VERSION 5.8 ;
BUSBITCHARS "[]" ;
DIVIDERCHAR "/" ;
UNITS
    DATABASE MICRONS 1000 ;
END UNITS

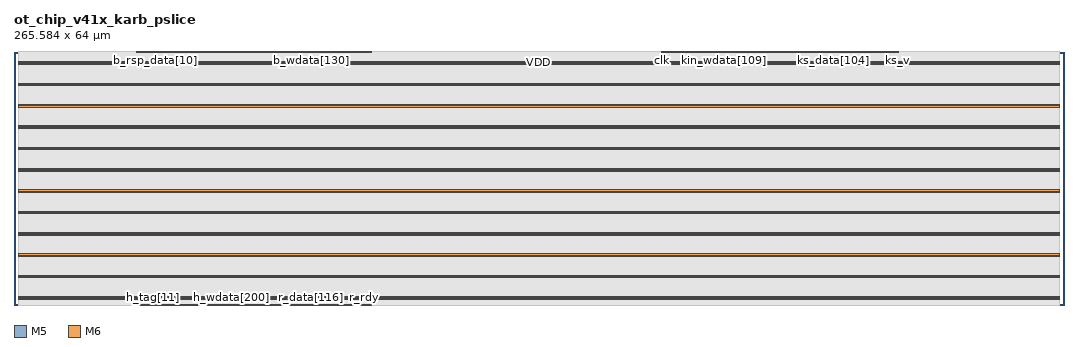
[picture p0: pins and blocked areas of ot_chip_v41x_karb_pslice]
MACRO ot_chip_v41x_karb_pslice
  FOREIGN ot_chip_v41x_karb_pslice 0 0 ;
  CLASS BLOCK ;
  SIZE 265.584 BY 64 ;
  PIN b_addr[0]
    DIRECTION INPUT ;
    USE SIGNAL ;
    PORT
      LAYER M5 ;
        RECT  31.008 63.916 31.032 64 ;
    END
  END b_addr[0]
  PIN b_addr[10]
    DIRECTION INPUT ;
    USE SIGNAL ;
    PORT
      LAYER M5 ;
        RECT  31.968 63.916 31.992 64 ;
    END
  END b_addr[10]
  PIN b_addr[11]
    DIRECTION INPUT ;
    USE SIGNAL ;
    PORT
      LAYER M5 ;
        RECT  32.064 63.916 32.088 64 ;
    END
  END b_addr[11]
  PIN b_addr[12]
    DIRECTION INPUT ;
    USE SIGNAL ;
    PORT
      LAYER M5 ;
        RECT  32.16 63.916 32.184 64 ;
    END
  END b_addr[12]
  PIN b_addr[13]
    DIRECTION INPUT ;
    USE SIGNAL ;
    PORT
      LAYER M5 ;
        RECT  32.256 63.916 32.28 64 ;
    END
  END b_addr[13]
  PIN b_addr[14]
    DIRECTION INPUT ;
    USE SIGNAL ;
    PORT
      LAYER M5 ;
        RECT  32.352 63.916 32.376 64 ;
    END
  END b_addr[14]
  PIN b_addr[15]
    DIRECTION INPUT ;
    USE SIGNAL ;
    PORT
      LAYER M5 ;
        RECT  32.448 63.916 32.472 64 ;
    END
  END b_addr[15]
  PIN b_addr[16]
    DIRECTION INPUT ;
    USE SIGNAL ;
    PORT
      LAYER M5 ;
        RECT  32.544 63.916 32.568 64 ;
    END
  END b_addr[16]
  PIN b_addr[17]
    DIRECTION INPUT ;
    USE SIGNAL ;
    PORT
      LAYER M5 ;
        RECT  32.64 63.916 32.664 64 ;
    END
  END b_addr[17]
  PIN b_addr[18]
    DIRECTION INPUT ;
    USE SIGNAL ;
    PORT
      LAYER M5 ;
        RECT  32.736 63.916 32.76 64 ;
    END
  END b_addr[18]
  PIN b_addr[19]
    DIRECTION INPUT ;
    USE SIGNAL ;
    PORT
      LAYER M5 ;
        RECT  32.832 63.916 32.856 64 ;
    END
  END b_addr[19]
  PIN b_addr[1]
    DIRECTION INPUT ;
    USE SIGNAL ;
    PORT
      LAYER M5 ;
        RECT  31.104 63.916 31.128 64 ;
    END
  END b_addr[1]
  PIN b_addr[20]
    DIRECTION INPUT ;
    USE SIGNAL ;
    PORT
      LAYER M5 ;
        RECT  32.928 63.916 32.952 64 ;
    END
  END b_addr[20]
  PIN b_addr[21]
    DIRECTION INPUT ;
    USE SIGNAL ;
    PORT
      LAYER M5 ;
        RECT  33.024 63.916 33.048 64 ;
    END
  END b_addr[21]
  PIN b_addr[22]
    DIRECTION INPUT ;
    USE SIGNAL ;
    PORT
      LAYER M5 ;
        RECT  33.12 63.916 33.144 64 ;
    END
  END b_addr[22]
  PIN b_addr[23]
    DIRECTION INPUT ;
    USE SIGNAL ;
    PORT
      LAYER M5 ;
        RECT  33.216 63.916 33.24 64 ;
    END
  END b_addr[23]
  PIN b_addr[24]
    DIRECTION INPUT ;
    USE SIGNAL ;
    PORT
      LAYER M5 ;
        RECT  33.312 63.916 33.336 64 ;
    END
  END b_addr[24]
  PIN b_addr[25]
    DIRECTION INPUT ;
    USE SIGNAL ;
    PORT
      LAYER M5 ;
        RECT  33.408 63.916 33.432 64 ;
    END
  END b_addr[25]
  PIN b_addr[26]
    DIRECTION INPUT ;
    USE SIGNAL ;
    PORT
      LAYER M5 ;
        RECT  33.504 63.916 33.528 64 ;
    END
  END b_addr[26]
  PIN b_addr[27]
    DIRECTION INPUT ;
    USE SIGNAL ;
    PORT
      LAYER M5 ;
        RECT  33.6 63.916 33.624 64 ;
    END
  END b_addr[27]
  PIN b_addr[28]
    DIRECTION INPUT ;
    USE SIGNAL ;
    PORT
      LAYER M5 ;
        RECT  33.696 63.916 33.72 64 ;
    END
  END b_addr[28]
  PIN b_addr[29]
    DIRECTION INPUT ;
    USE SIGNAL ;
    PORT
      LAYER M5 ;
        RECT  33.792 63.916 33.816 64 ;
    END
  END b_addr[29]
  PIN b_addr[2]
    DIRECTION INPUT ;
    USE SIGNAL ;
    PORT
      LAYER M5 ;
        RECT  31.2 63.916 31.224 64 ;
    END
  END b_addr[2]
  PIN b_addr[3]
    DIRECTION INPUT ;
    USE SIGNAL ;
    PORT
      LAYER M5 ;
        RECT  31.296 63.916 31.32 64 ;
    END
  END b_addr[3]
  PIN b_addr[4]
    DIRECTION INPUT ;
    USE SIGNAL ;
    PORT
      LAYER M5 ;
        RECT  31.392 63.916 31.416 64 ;
    END
  END b_addr[4]
  PIN b_addr[5]
    DIRECTION INPUT ;
    USE SIGNAL ;
    PORT
      LAYER M5 ;
        RECT  31.488 63.916 31.512 64 ;
    END
  END b_addr[5]
  PIN b_addr[6]
    DIRECTION INPUT ;
    USE SIGNAL ;
    PORT
      LAYER M5 ;
        RECT  31.584 63.916 31.608 64 ;
    END
  END b_addr[6]
  PIN b_addr[7]
    DIRECTION INPUT ;
    USE SIGNAL ;
    PORT
      LAYER M5 ;
        RECT  31.68 63.916 31.704 64 ;
    END
  END b_addr[7]
  PIN b_addr[8]
    DIRECTION INPUT ;
    USE SIGNAL ;
    PORT
      LAYER M5 ;
        RECT  31.776 63.916 31.8 64 ;
    END
  END b_addr[8]
  PIN b_addr[9]
    DIRECTION INPUT ;
    USE SIGNAL ;
    PORT
      LAYER M5 ;
        RECT  31.872 63.916 31.896 64 ;
    END
  END b_addr[9]
  PIN b_grant
    DIRECTION OUTPUT ;
    USE SIGNAL ;
    PORT
      LAYER M5 ;
        RECT  163.776 63.916 163.8 64 ;
    END
  END b_grant
  PIN b_len[0]
    DIRECTION INPUT ;
    USE SIGNAL ;
    PORT
      LAYER M5 ;
        RECT  33.888 63.916 33.912 64 ;
    END
  END b_len[0]
  PIN b_len[1]
    DIRECTION INPUT ;
    USE SIGNAL ;
    PORT
      LAYER M5 ;
        RECT  33.984 63.916 34.008 64 ;
    END
  END b_len[1]
  PIN b_len[2]
    DIRECTION INPUT ;
    USE SIGNAL ;
    PORT
      LAYER M5 ;
        RECT  34.08 63.916 34.104 64 ;
    END
  END b_len[2]
  PIN b_len[3]
    DIRECTION INPUT ;
    USE SIGNAL ;
    PORT
      LAYER M5 ;
        RECT  34.176 63.916 34.2 64 ;
    END
  END b_len[3]
  PIN b_rdy
    DIRECTION OUTPUT ;
    USE SIGNAL ;
    PORT
      LAYER M5 ;
        RECT  34.272 63.916 34.296 64 ;
    END
  END b_rdy
  PIN b_rsp_beat[0]
    DIRECTION OUTPUT ;
    USE SIGNAL ;
    PORT
      LAYER M5 ;
        RECT  34.368 63.916 34.392 64 ;
    END
  END b_rsp_beat[0]
  PIN b_rsp_beat[1]
    DIRECTION OUTPUT ;
    USE SIGNAL ;
    PORT
      LAYER M5 ;
        RECT  34.464 63.916 34.488 64 ;
    END
  END b_rsp_beat[1]
  PIN b_rsp_beat[2]
    DIRECTION OUTPUT ;
    USE SIGNAL ;
    PORT
      LAYER M5 ;
        RECT  34.56 63.916 34.584 64 ;
    END
  END b_rsp_beat[2]
  PIN b_rsp_beat[3]
    DIRECTION OUTPUT ;
    USE SIGNAL ;
    PORT
      LAYER M5 ;
        RECT  34.656 63.916 34.68 64 ;
    END
  END b_rsp_beat[3]
  PIN b_rsp_data[0]
    DIRECTION OUTPUT ;
    USE SIGNAL ;
    PORT
      LAYER M5 ;
        RECT  34.752 63.916 34.776 64 ;
    END
  END b_rsp_data[0]
  PIN b_rsp_data[100]
    DIRECTION OUTPUT ;
    USE SIGNAL ;
    PORT
      LAYER M5 ;
        RECT  44.352 63.916 44.376 64 ;
    END
  END b_rsp_data[100]
  PIN b_rsp_data[101]
    DIRECTION OUTPUT ;
    USE SIGNAL ;
    PORT
      LAYER M5 ;
        RECT  44.448 63.916 44.472 64 ;
    END
  END b_rsp_data[101]
  PIN b_rsp_data[102]
    DIRECTION OUTPUT ;
    USE SIGNAL ;
    PORT
      LAYER M5 ;
        RECT  44.544 63.916 44.568 64 ;
    END
  END b_rsp_data[102]
  PIN b_rsp_data[103]
    DIRECTION OUTPUT ;
    USE SIGNAL ;
    PORT
      LAYER M5 ;
        RECT  44.64 63.916 44.664 64 ;
    END
  END b_rsp_data[103]
  PIN b_rsp_data[104]
    DIRECTION OUTPUT ;
    USE SIGNAL ;
    PORT
      LAYER M5 ;
        RECT  44.736 63.916 44.76 64 ;
    END
  END b_rsp_data[104]
  PIN b_rsp_data[105]
    DIRECTION OUTPUT ;
    USE SIGNAL ;
    PORT
      LAYER M5 ;
        RECT  44.832 63.916 44.856 64 ;
    END
  END b_rsp_data[105]
  PIN b_rsp_data[106]
    DIRECTION OUTPUT ;
    USE SIGNAL ;
    PORT
      LAYER M5 ;
        RECT  44.928 63.916 44.952 64 ;
    END
  END b_rsp_data[106]
  PIN b_rsp_data[107]
    DIRECTION OUTPUT ;
    USE SIGNAL ;
    PORT
      LAYER M5 ;
        RECT  45.024 63.916 45.048 64 ;
    END
  END b_rsp_data[107]
  PIN b_rsp_data[108]
    DIRECTION OUTPUT ;
    USE SIGNAL ;
    PORT
      LAYER M5 ;
        RECT  45.12 63.916 45.144 64 ;
    END
  END b_rsp_data[108]
  PIN b_rsp_data[109]
    DIRECTION OUTPUT ;
    USE SIGNAL ;
    PORT
      LAYER M5 ;
        RECT  45.216 63.916 45.24 64 ;
    END
  END b_rsp_data[109]
  PIN b_rsp_data[10]
    DIRECTION OUTPUT ;
    USE SIGNAL ;
    PORT
      LAYER M5 ;
        RECT  35.712 63.916 35.736 64 ;
    END
  END b_rsp_data[10]
  PIN b_rsp_data[110]
    DIRECTION OUTPUT ;
    USE SIGNAL ;
    PORT
      LAYER M5 ;
        RECT  45.312 63.916 45.336 64 ;
    END
  END b_rsp_data[110]
  PIN b_rsp_data[111]
    DIRECTION OUTPUT ;
    USE SIGNAL ;
    PORT
      LAYER M5 ;
        RECT  45.408 63.916 45.432 64 ;
    END
  END b_rsp_data[111]
  PIN b_rsp_data[112]
    DIRECTION OUTPUT ;
    USE SIGNAL ;
    PORT
      LAYER M5 ;
        RECT  45.504 63.916 45.528 64 ;
    END
  END b_rsp_data[112]
  PIN b_rsp_data[113]
    DIRECTION OUTPUT ;
    USE SIGNAL ;
    PORT
      LAYER M5 ;
        RECT  45.6 63.916 45.624 64 ;
    END
  END b_rsp_data[113]
  PIN b_rsp_data[114]
    DIRECTION OUTPUT ;
    USE SIGNAL ;
    PORT
      LAYER M5 ;
        RECT  45.696 63.916 45.72 64 ;
    END
  END b_rsp_data[114]
  PIN b_rsp_data[115]
    DIRECTION OUTPUT ;
    USE SIGNAL ;
    PORT
      LAYER M5 ;
        RECT  45.792 63.916 45.816 64 ;
    END
  END b_rsp_data[115]
  PIN b_rsp_data[116]
    DIRECTION OUTPUT ;
    USE SIGNAL ;
    PORT
      LAYER M5 ;
        RECT  45.888 63.916 45.912 64 ;
    END
  END b_rsp_data[116]
  PIN b_rsp_data[117]
    DIRECTION OUTPUT ;
    USE SIGNAL ;
    PORT
      LAYER M5 ;
        RECT  45.984 63.916 46.008 64 ;
    END
  END b_rsp_data[117]
  PIN b_rsp_data[118]
    DIRECTION OUTPUT ;
    USE SIGNAL ;
    PORT
      LAYER M5 ;
        RECT  46.08 63.916 46.104 64 ;
    END
  END b_rsp_data[118]
  PIN b_rsp_data[119]
    DIRECTION OUTPUT ;
    USE SIGNAL ;
    PORT
      LAYER M5 ;
        RECT  46.176 63.916 46.2 64 ;
    END
  END b_rsp_data[119]
  PIN b_rsp_data[11]
    DIRECTION OUTPUT ;
    USE SIGNAL ;
    PORT
      LAYER M5 ;
        RECT  35.808 63.916 35.832 64 ;
    END
  END b_rsp_data[11]
  PIN b_rsp_data[120]
    DIRECTION OUTPUT ;
    USE SIGNAL ;
    PORT
      LAYER M5 ;
        RECT  46.272 63.916 46.296 64 ;
    END
  END b_rsp_data[120]
  PIN b_rsp_data[121]
    DIRECTION OUTPUT ;
    USE SIGNAL ;
    PORT
      LAYER M5 ;
        RECT  46.368 63.916 46.392 64 ;
    END
  END b_rsp_data[121]
  PIN b_rsp_data[122]
    DIRECTION OUTPUT ;
    USE SIGNAL ;
    PORT
      LAYER M5 ;
        RECT  46.464 63.916 46.488 64 ;
    END
  END b_rsp_data[122]
  PIN b_rsp_data[123]
    DIRECTION OUTPUT ;
    USE SIGNAL ;
    PORT
      LAYER M5 ;
        RECT  46.56 63.916 46.584 64 ;
    END
  END b_rsp_data[123]
  PIN b_rsp_data[124]
    DIRECTION OUTPUT ;
    USE SIGNAL ;
    PORT
      LAYER M5 ;
        RECT  46.656 63.916 46.68 64 ;
    END
  END b_rsp_data[124]
  PIN b_rsp_data[125]
    DIRECTION OUTPUT ;
    USE SIGNAL ;
    PORT
      LAYER M5 ;
        RECT  46.752 63.916 46.776 64 ;
    END
  END b_rsp_data[125]
  PIN b_rsp_data[126]
    DIRECTION OUTPUT ;
    USE SIGNAL ;
    PORT
      LAYER M5 ;
        RECT  46.848 63.916 46.872 64 ;
    END
  END b_rsp_data[126]
  PIN b_rsp_data[127]
    DIRECTION OUTPUT ;
    USE SIGNAL ;
    PORT
      LAYER M5 ;
        RECT  46.944 63.916 46.968 64 ;
    END
  END b_rsp_data[127]
  PIN b_rsp_data[128]
    DIRECTION OUTPUT ;
    USE SIGNAL ;
    PORT
      LAYER M5 ;
        RECT  47.04 63.916 47.064 64 ;
    END
  END b_rsp_data[128]
  PIN b_rsp_data[129]
    DIRECTION OUTPUT ;
    USE SIGNAL ;
    PORT
      LAYER M5 ;
        RECT  47.136 63.916 47.16 64 ;
    END
  END b_rsp_data[129]
  PIN b_rsp_data[12]
    DIRECTION OUTPUT ;
    USE SIGNAL ;
    PORT
      LAYER M5 ;
        RECT  35.904 63.916 35.928 64 ;
    END
  END b_rsp_data[12]
  PIN b_rsp_data[130]
    DIRECTION OUTPUT ;
    USE SIGNAL ;
    PORT
      LAYER M5 ;
        RECT  47.232 63.916 47.256 64 ;
    END
  END b_rsp_data[130]
  PIN b_rsp_data[131]
    DIRECTION OUTPUT ;
    USE SIGNAL ;
    PORT
      LAYER M5 ;
        RECT  47.328 63.916 47.352 64 ;
    END
  END b_rsp_data[131]
  PIN b_rsp_data[132]
    DIRECTION OUTPUT ;
    USE SIGNAL ;
    PORT
      LAYER M5 ;
        RECT  47.424 63.916 47.448 64 ;
    END
  END b_rsp_data[132]
  PIN b_rsp_data[133]
    DIRECTION OUTPUT ;
    USE SIGNAL ;
    PORT
      LAYER M5 ;
        RECT  47.52 63.916 47.544 64 ;
    END
  END b_rsp_data[133]
  PIN b_rsp_data[134]
    DIRECTION OUTPUT ;
    USE SIGNAL ;
    PORT
      LAYER M5 ;
        RECT  47.616 63.916 47.64 64 ;
    END
  END b_rsp_data[134]
  PIN b_rsp_data[135]
    DIRECTION OUTPUT ;
    USE SIGNAL ;
    PORT
      LAYER M5 ;
        RECT  47.712 63.916 47.736 64 ;
    END
  END b_rsp_data[135]
  PIN b_rsp_data[136]
    DIRECTION OUTPUT ;
    USE SIGNAL ;
    PORT
      LAYER M5 ;
        RECT  47.808 63.916 47.832 64 ;
    END
  END b_rsp_data[136]
  PIN b_rsp_data[137]
    DIRECTION OUTPUT ;
    USE SIGNAL ;
    PORT
      LAYER M5 ;
        RECT  47.904 63.916 47.928 64 ;
    END
  END b_rsp_data[137]
  PIN b_rsp_data[138]
    DIRECTION OUTPUT ;
    USE SIGNAL ;
    PORT
      LAYER M5 ;
        RECT  48 63.916 48.024 64 ;
    END
  END b_rsp_data[138]
  PIN b_rsp_data[139]
    DIRECTION OUTPUT ;
    USE SIGNAL ;
    PORT
      LAYER M5 ;
        RECT  48.096 63.916 48.12 64 ;
    END
  END b_rsp_data[139]
  PIN b_rsp_data[13]
    DIRECTION OUTPUT ;
    USE SIGNAL ;
    PORT
      LAYER M5 ;
        RECT  36 63.916 36.024 64 ;
    END
  END b_rsp_data[13]
  PIN b_rsp_data[140]
    DIRECTION OUTPUT ;
    USE SIGNAL ;
    PORT
      LAYER M5 ;
        RECT  48.192 63.916 48.216 64 ;
    END
  END b_rsp_data[140]
  PIN b_rsp_data[141]
    DIRECTION OUTPUT ;
    USE SIGNAL ;
    PORT
      LAYER M5 ;
        RECT  48.288 63.916 48.312 64 ;
    END
  END b_rsp_data[141]
  PIN b_rsp_data[142]
    DIRECTION OUTPUT ;
    USE SIGNAL ;
    PORT
      LAYER M5 ;
        RECT  48.384 63.916 48.408 64 ;
    END
  END b_rsp_data[142]
  PIN b_rsp_data[143]
    DIRECTION OUTPUT ;
    USE SIGNAL ;
    PORT
      LAYER M5 ;
        RECT  48.48 63.916 48.504 64 ;
    END
  END b_rsp_data[143]
  PIN b_rsp_data[144]
    DIRECTION OUTPUT ;
    USE SIGNAL ;
    PORT
      LAYER M5 ;
        RECT  48.576 63.916 48.6 64 ;
    END
  END b_rsp_data[144]
  PIN b_rsp_data[145]
    DIRECTION OUTPUT ;
    USE SIGNAL ;
    PORT
      LAYER M5 ;
        RECT  48.672 63.916 48.696 64 ;
    END
  END b_rsp_data[145]
  PIN b_rsp_data[146]
    DIRECTION OUTPUT ;
    USE SIGNAL ;
    PORT
      LAYER M5 ;
        RECT  48.768 63.916 48.792 64 ;
    END
  END b_rsp_data[146]
  PIN b_rsp_data[147]
    DIRECTION OUTPUT ;
    USE SIGNAL ;
    PORT
      LAYER M5 ;
        RECT  48.864 63.916 48.888 64 ;
    END
  END b_rsp_data[147]
  PIN b_rsp_data[148]
    DIRECTION OUTPUT ;
    USE SIGNAL ;
    PORT
      LAYER M5 ;
        RECT  48.96 63.916 48.984 64 ;
    END
  END b_rsp_data[148]
  PIN b_rsp_data[149]
    DIRECTION OUTPUT ;
    USE SIGNAL ;
    PORT
      LAYER M5 ;
        RECT  49.056 63.916 49.08 64 ;
    END
  END b_rsp_data[149]
  PIN b_rsp_data[14]
    DIRECTION OUTPUT ;
    USE SIGNAL ;
    PORT
      LAYER M5 ;
        RECT  36.096 63.916 36.12 64 ;
    END
  END b_rsp_data[14]
  PIN b_rsp_data[150]
    DIRECTION OUTPUT ;
    USE SIGNAL ;
    PORT
      LAYER M5 ;
        RECT  49.152 63.916 49.176 64 ;
    END
  END b_rsp_data[150]
  PIN b_rsp_data[151]
    DIRECTION OUTPUT ;
    USE SIGNAL ;
    PORT
      LAYER M5 ;
        RECT  49.248 63.916 49.272 64 ;
    END
  END b_rsp_data[151]
  PIN b_rsp_data[152]
    DIRECTION OUTPUT ;
    USE SIGNAL ;
    PORT
      LAYER M5 ;
        RECT  49.344 63.916 49.368 64 ;
    END
  END b_rsp_data[152]
  PIN b_rsp_data[153]
    DIRECTION OUTPUT ;
    USE SIGNAL ;
    PORT
      LAYER M5 ;
        RECT  49.44 63.916 49.464 64 ;
    END
  END b_rsp_data[153]
  PIN b_rsp_data[154]
    DIRECTION OUTPUT ;
    USE SIGNAL ;
    PORT
      LAYER M5 ;
        RECT  49.536 63.916 49.56 64 ;
    END
  END b_rsp_data[154]
  PIN b_rsp_data[155]
    DIRECTION OUTPUT ;
    USE SIGNAL ;
    PORT
      LAYER M5 ;
        RECT  49.632 63.916 49.656 64 ;
    END
  END b_rsp_data[155]
  PIN b_rsp_data[156]
    DIRECTION OUTPUT ;
    USE SIGNAL ;
    PORT
      LAYER M5 ;
        RECT  49.728 63.916 49.752 64 ;
    END
  END b_rsp_data[156]
  PIN b_rsp_data[157]
    DIRECTION OUTPUT ;
    USE SIGNAL ;
    PORT
      LAYER M5 ;
        RECT  49.824 63.916 49.848 64 ;
    END
  END b_rsp_data[157]
  PIN b_rsp_data[158]
    DIRECTION OUTPUT ;
    USE SIGNAL ;
    PORT
      LAYER M5 ;
        RECT  49.92 63.916 49.944 64 ;
    END
  END b_rsp_data[158]
  PIN b_rsp_data[159]
    DIRECTION OUTPUT ;
    USE SIGNAL ;
    PORT
      LAYER M5 ;
        RECT  50.016 63.916 50.04 64 ;
    END
  END b_rsp_data[159]
  PIN b_rsp_data[15]
    DIRECTION OUTPUT ;
    USE SIGNAL ;
    PORT
      LAYER M5 ;
        RECT  36.192 63.916 36.216 64 ;
    END
  END b_rsp_data[15]
  PIN b_rsp_data[160]
    DIRECTION OUTPUT ;
    USE SIGNAL ;
    PORT
      LAYER M5 ;
        RECT  50.112 63.916 50.136 64 ;
    END
  END b_rsp_data[160]
  PIN b_rsp_data[161]
    DIRECTION OUTPUT ;
    USE SIGNAL ;
    PORT
      LAYER M5 ;
        RECT  50.208 63.916 50.232 64 ;
    END
  END b_rsp_data[161]
  PIN b_rsp_data[162]
    DIRECTION OUTPUT ;
    USE SIGNAL ;
    PORT
      LAYER M5 ;
        RECT  50.304 63.916 50.328 64 ;
    END
  END b_rsp_data[162]
  PIN b_rsp_data[163]
    DIRECTION OUTPUT ;
    USE SIGNAL ;
    PORT
      LAYER M5 ;
        RECT  50.4 63.916 50.424 64 ;
    END
  END b_rsp_data[163]
  PIN b_rsp_data[164]
    DIRECTION OUTPUT ;
    USE SIGNAL ;
    PORT
      LAYER M5 ;
        RECT  50.496 63.916 50.52 64 ;
    END
  END b_rsp_data[164]
  PIN b_rsp_data[165]
    DIRECTION OUTPUT ;
    USE SIGNAL ;
    PORT
      LAYER M5 ;
        RECT  50.592 63.916 50.616 64 ;
    END
  END b_rsp_data[165]
  PIN b_rsp_data[166]
    DIRECTION OUTPUT ;
    USE SIGNAL ;
    PORT
      LAYER M5 ;
        RECT  50.688 63.916 50.712 64 ;
    END
  END b_rsp_data[166]
  PIN b_rsp_data[167]
    DIRECTION OUTPUT ;
    USE SIGNAL ;
    PORT
      LAYER M5 ;
        RECT  50.784 63.916 50.808 64 ;
    END
  END b_rsp_data[167]
  PIN b_rsp_data[168]
    DIRECTION OUTPUT ;
    USE SIGNAL ;
    PORT
      LAYER M5 ;
        RECT  50.88 63.916 50.904 64 ;
    END
  END b_rsp_data[168]
  PIN b_rsp_data[169]
    DIRECTION OUTPUT ;
    USE SIGNAL ;
    PORT
      LAYER M5 ;
        RECT  50.976 63.916 51 64 ;
    END
  END b_rsp_data[169]
  PIN b_rsp_data[16]
    DIRECTION OUTPUT ;
    USE SIGNAL ;
    PORT
      LAYER M5 ;
        RECT  36.288 63.916 36.312 64 ;
    END
  END b_rsp_data[16]
  PIN b_rsp_data[170]
    DIRECTION OUTPUT ;
    USE SIGNAL ;
    PORT
      LAYER M5 ;
        RECT  51.072 63.916 51.096 64 ;
    END
  END b_rsp_data[170]
  PIN b_rsp_data[171]
    DIRECTION OUTPUT ;
    USE SIGNAL ;
    PORT
      LAYER M5 ;
        RECT  51.168 63.916 51.192 64 ;
    END
  END b_rsp_data[171]
  PIN b_rsp_data[172]
    DIRECTION OUTPUT ;
    USE SIGNAL ;
    PORT
      LAYER M5 ;
        RECT  51.264 63.916 51.288 64 ;
    END
  END b_rsp_data[172]
  PIN b_rsp_data[173]
    DIRECTION OUTPUT ;
    USE SIGNAL ;
    PORT
      LAYER M5 ;
        RECT  51.36 63.916 51.384 64 ;
    END
  END b_rsp_data[173]
  PIN b_rsp_data[174]
    DIRECTION OUTPUT ;
    USE SIGNAL ;
    PORT
      LAYER M5 ;
        RECT  51.456 63.916 51.48 64 ;
    END
  END b_rsp_data[174]
  PIN b_rsp_data[175]
    DIRECTION OUTPUT ;
    USE SIGNAL ;
    PORT
      LAYER M5 ;
        RECT  51.552 63.916 51.576 64 ;
    END
  END b_rsp_data[175]
  PIN b_rsp_data[176]
    DIRECTION OUTPUT ;
    USE SIGNAL ;
    PORT
      LAYER M5 ;
        RECT  51.648 63.916 51.672 64 ;
    END
  END b_rsp_data[176]
  PIN b_rsp_data[177]
    DIRECTION OUTPUT ;
    USE SIGNAL ;
    PORT
      LAYER M5 ;
        RECT  51.744 63.916 51.768 64 ;
    END
  END b_rsp_data[177]
  PIN b_rsp_data[178]
    DIRECTION OUTPUT ;
    USE SIGNAL ;
    PORT
      LAYER M5 ;
        RECT  51.84 63.916 51.864 64 ;
    END
  END b_rsp_data[178]
  PIN b_rsp_data[179]
    DIRECTION OUTPUT ;
    USE SIGNAL ;
    PORT
      LAYER M5 ;
        RECT  51.936 63.916 51.96 64 ;
    END
  END b_rsp_data[179]
  PIN b_rsp_data[17]
    DIRECTION OUTPUT ;
    USE SIGNAL ;
    PORT
      LAYER M5 ;
        RECT  36.384 63.916 36.408 64 ;
    END
  END b_rsp_data[17]
  PIN b_rsp_data[180]
    DIRECTION OUTPUT ;
    USE SIGNAL ;
    PORT
      LAYER M5 ;
        RECT  52.032 63.916 52.056 64 ;
    END
  END b_rsp_data[180]
  PIN b_rsp_data[181]
    DIRECTION OUTPUT ;
    USE SIGNAL ;
    PORT
      LAYER M5 ;
        RECT  52.128 63.916 52.152 64 ;
    END
  END b_rsp_data[181]
  PIN b_rsp_data[182]
    DIRECTION OUTPUT ;
    USE SIGNAL ;
    PORT
      LAYER M5 ;
        RECT  52.224 63.916 52.248 64 ;
    END
  END b_rsp_data[182]
  PIN b_rsp_data[183]
    DIRECTION OUTPUT ;
    USE SIGNAL ;
    PORT
      LAYER M5 ;
        RECT  52.32 63.916 52.344 64 ;
    END
  END b_rsp_data[183]
  PIN b_rsp_data[184]
    DIRECTION OUTPUT ;
    USE SIGNAL ;
    PORT
      LAYER M5 ;
        RECT  52.416 63.916 52.44 64 ;
    END
  END b_rsp_data[184]
  PIN b_rsp_data[185]
    DIRECTION OUTPUT ;
    USE SIGNAL ;
    PORT
      LAYER M5 ;
        RECT  52.512 63.916 52.536 64 ;
    END
  END b_rsp_data[185]
  PIN b_rsp_data[186]
    DIRECTION OUTPUT ;
    USE SIGNAL ;
    PORT
      LAYER M5 ;
        RECT  52.608 63.916 52.632 64 ;
    END
  END b_rsp_data[186]
  PIN b_rsp_data[187]
    DIRECTION OUTPUT ;
    USE SIGNAL ;
    PORT
      LAYER M5 ;
        RECT  52.704 63.916 52.728 64 ;
    END
  END b_rsp_data[187]
  PIN b_rsp_data[188]
    DIRECTION OUTPUT ;
    USE SIGNAL ;
    PORT
      LAYER M5 ;
        RECT  52.8 63.916 52.824 64 ;
    END
  END b_rsp_data[188]
  PIN b_rsp_data[189]
    DIRECTION OUTPUT ;
    USE SIGNAL ;
    PORT
      LAYER M5 ;
        RECT  52.896 63.916 52.92 64 ;
    END
  END b_rsp_data[189]
  PIN b_rsp_data[18]
    DIRECTION OUTPUT ;
    USE SIGNAL ;
    PORT
      LAYER M5 ;
        RECT  36.48 63.916 36.504 64 ;
    END
  END b_rsp_data[18]
  PIN b_rsp_data[190]
    DIRECTION OUTPUT ;
    USE SIGNAL ;
    PORT
      LAYER M5 ;
        RECT  52.992 63.916 53.016 64 ;
    END
  END b_rsp_data[190]
  PIN b_rsp_data[191]
    DIRECTION OUTPUT ;
    USE SIGNAL ;
    PORT
      LAYER M5 ;
        RECT  53.088 63.916 53.112 64 ;
    END
  END b_rsp_data[191]
  PIN b_rsp_data[192]
    DIRECTION OUTPUT ;
    USE SIGNAL ;
    PORT
      LAYER M5 ;
        RECT  53.184 63.916 53.208 64 ;
    END
  END b_rsp_data[192]
  PIN b_rsp_data[193]
    DIRECTION OUTPUT ;
    USE SIGNAL ;
    PORT
      LAYER M5 ;
        RECT  53.28 63.916 53.304 64 ;
    END
  END b_rsp_data[193]
  PIN b_rsp_data[194]
    DIRECTION OUTPUT ;
    USE SIGNAL ;
    PORT
      LAYER M5 ;
        RECT  53.376 63.916 53.4 64 ;
    END
  END b_rsp_data[194]
  PIN b_rsp_data[195]
    DIRECTION OUTPUT ;
    USE SIGNAL ;
    PORT
      LAYER M5 ;
        RECT  53.472 63.916 53.496 64 ;
    END
  END b_rsp_data[195]
  PIN b_rsp_data[196]
    DIRECTION OUTPUT ;
    USE SIGNAL ;
    PORT
      LAYER M5 ;
        RECT  53.568 63.916 53.592 64 ;
    END
  END b_rsp_data[196]
  PIN b_rsp_data[197]
    DIRECTION OUTPUT ;
    USE SIGNAL ;
    PORT
      LAYER M5 ;
        RECT  53.664 63.916 53.688 64 ;
    END
  END b_rsp_data[197]
  PIN b_rsp_data[198]
    DIRECTION OUTPUT ;
    USE SIGNAL ;
    PORT
      LAYER M5 ;
        RECT  53.76 63.916 53.784 64 ;
    END
  END b_rsp_data[198]
  PIN b_rsp_data[199]
    DIRECTION OUTPUT ;
    USE SIGNAL ;
    PORT
      LAYER M5 ;
        RECT  53.856 63.916 53.88 64 ;
    END
  END b_rsp_data[199]
  PIN b_rsp_data[19]
    DIRECTION OUTPUT ;
    USE SIGNAL ;
    PORT
      LAYER M5 ;
        RECT  36.576 63.916 36.6 64 ;
    END
  END b_rsp_data[19]
  PIN b_rsp_data[1]
    DIRECTION OUTPUT ;
    USE SIGNAL ;
    PORT
      LAYER M5 ;
        RECT  34.848 63.916 34.872 64 ;
    END
  END b_rsp_data[1]
  PIN b_rsp_data[200]
    DIRECTION OUTPUT ;
    USE SIGNAL ;
    PORT
      LAYER M5 ;
        RECT  53.952 63.916 53.976 64 ;
    END
  END b_rsp_data[200]
  PIN b_rsp_data[201]
    DIRECTION OUTPUT ;
    USE SIGNAL ;
    PORT
      LAYER M5 ;
        RECT  54.048 63.916 54.072 64 ;
    END
  END b_rsp_data[201]
  PIN b_rsp_data[202]
    DIRECTION OUTPUT ;
    USE SIGNAL ;
    PORT
      LAYER M5 ;
        RECT  54.144 63.916 54.168 64 ;
    END
  END b_rsp_data[202]
  PIN b_rsp_data[203]
    DIRECTION OUTPUT ;
    USE SIGNAL ;
    PORT
      LAYER M5 ;
        RECT  54.24 63.916 54.264 64 ;
    END
  END b_rsp_data[203]
  PIN b_rsp_data[204]
    DIRECTION OUTPUT ;
    USE SIGNAL ;
    PORT
      LAYER M5 ;
        RECT  54.336 63.916 54.36 64 ;
    END
  END b_rsp_data[204]
  PIN b_rsp_data[205]
    DIRECTION OUTPUT ;
    USE SIGNAL ;
    PORT
      LAYER M5 ;
        RECT  54.432 63.916 54.456 64 ;
    END
  END b_rsp_data[205]
  PIN b_rsp_data[206]
    DIRECTION OUTPUT ;
    USE SIGNAL ;
    PORT
      LAYER M5 ;
        RECT  54.528 63.916 54.552 64 ;
    END
  END b_rsp_data[206]
  PIN b_rsp_data[207]
    DIRECTION OUTPUT ;
    USE SIGNAL ;
    PORT
      LAYER M5 ;
        RECT  54.624 63.916 54.648 64 ;
    END
  END b_rsp_data[207]
  PIN b_rsp_data[208]
    DIRECTION OUTPUT ;
    USE SIGNAL ;
    PORT
      LAYER M5 ;
        RECT  54.72 63.916 54.744 64 ;
    END
  END b_rsp_data[208]
  PIN b_rsp_data[209]
    DIRECTION OUTPUT ;
    USE SIGNAL ;
    PORT
      LAYER M5 ;
        RECT  54.816 63.916 54.84 64 ;
    END
  END b_rsp_data[209]
  PIN b_rsp_data[20]
    DIRECTION OUTPUT ;
    USE SIGNAL ;
    PORT
      LAYER M5 ;
        RECT  36.672 63.916 36.696 64 ;
    END
  END b_rsp_data[20]
  PIN b_rsp_data[210]
    DIRECTION OUTPUT ;
    USE SIGNAL ;
    PORT
      LAYER M5 ;
        RECT  54.912 63.916 54.936 64 ;
    END
  END b_rsp_data[210]
  PIN b_rsp_data[211]
    DIRECTION OUTPUT ;
    USE SIGNAL ;
    PORT
      LAYER M5 ;
        RECT  55.008 63.916 55.032 64 ;
    END
  END b_rsp_data[211]
  PIN b_rsp_data[212]
    DIRECTION OUTPUT ;
    USE SIGNAL ;
    PORT
      LAYER M5 ;
        RECT  55.104 63.916 55.128 64 ;
    END
  END b_rsp_data[212]
  PIN b_rsp_data[213]
    DIRECTION OUTPUT ;
    USE SIGNAL ;
    PORT
      LAYER M5 ;
        RECT  55.2 63.916 55.224 64 ;
    END
  END b_rsp_data[213]
  PIN b_rsp_data[214]
    DIRECTION OUTPUT ;
    USE SIGNAL ;
    PORT
      LAYER M5 ;
        RECT  55.296 63.916 55.32 64 ;
    END
  END b_rsp_data[214]
  PIN b_rsp_data[215]
    DIRECTION OUTPUT ;
    USE SIGNAL ;
    PORT
      LAYER M5 ;
        RECT  55.392 63.916 55.416 64 ;
    END
  END b_rsp_data[215]
  PIN b_rsp_data[216]
    DIRECTION OUTPUT ;
    USE SIGNAL ;
    PORT
      LAYER M5 ;
        RECT  55.488 63.916 55.512 64 ;
    END
  END b_rsp_data[216]
  PIN b_rsp_data[217]
    DIRECTION OUTPUT ;
    USE SIGNAL ;
    PORT
      LAYER M5 ;
        RECT  55.584 63.916 55.608 64 ;
    END
  END b_rsp_data[217]
  PIN b_rsp_data[218]
    DIRECTION OUTPUT ;
    USE SIGNAL ;
    PORT
      LAYER M5 ;
        RECT  55.68 63.916 55.704 64 ;
    END
  END b_rsp_data[218]
  PIN b_rsp_data[219]
    DIRECTION OUTPUT ;
    USE SIGNAL ;
    PORT
      LAYER M5 ;
        RECT  55.776 63.916 55.8 64 ;
    END
  END b_rsp_data[219]
  PIN b_rsp_data[21]
    DIRECTION OUTPUT ;
    USE SIGNAL ;
    PORT
      LAYER M5 ;
        RECT  36.768 63.916 36.792 64 ;
    END
  END b_rsp_data[21]
  PIN b_rsp_data[220]
    DIRECTION OUTPUT ;
    USE SIGNAL ;
    PORT
      LAYER M5 ;
        RECT  55.872 63.916 55.896 64 ;
    END
  END b_rsp_data[220]
  PIN b_rsp_data[221]
    DIRECTION OUTPUT ;
    USE SIGNAL ;
    PORT
      LAYER M5 ;
        RECT  55.968 63.916 55.992 64 ;
    END
  END b_rsp_data[221]
  PIN b_rsp_data[222]
    DIRECTION OUTPUT ;
    USE SIGNAL ;
    PORT
      LAYER M5 ;
        RECT  56.064 63.916 56.088 64 ;
    END
  END b_rsp_data[222]
  PIN b_rsp_data[223]
    DIRECTION OUTPUT ;
    USE SIGNAL ;
    PORT
      LAYER M5 ;
        RECT  56.16 63.916 56.184 64 ;
    END
  END b_rsp_data[223]
  PIN b_rsp_data[224]
    DIRECTION OUTPUT ;
    USE SIGNAL ;
    PORT
      LAYER M5 ;
        RECT  56.256 63.916 56.28 64 ;
    END
  END b_rsp_data[224]
  PIN b_rsp_data[225]
    DIRECTION OUTPUT ;
    USE SIGNAL ;
    PORT
      LAYER M5 ;
        RECT  56.352 63.916 56.376 64 ;
    END
  END b_rsp_data[225]
  PIN b_rsp_data[226]
    DIRECTION OUTPUT ;
    USE SIGNAL ;
    PORT
      LAYER M5 ;
        RECT  56.448 63.916 56.472 64 ;
    END
  END b_rsp_data[226]
  PIN b_rsp_data[227]
    DIRECTION OUTPUT ;
    USE SIGNAL ;
    PORT
      LAYER M5 ;
        RECT  56.544 63.916 56.568 64 ;
    END
  END b_rsp_data[227]
  PIN b_rsp_data[228]
    DIRECTION OUTPUT ;
    USE SIGNAL ;
    PORT
      LAYER M5 ;
        RECT  56.64 63.916 56.664 64 ;
    END
  END b_rsp_data[228]
  PIN b_rsp_data[229]
    DIRECTION OUTPUT ;
    USE SIGNAL ;
    PORT
      LAYER M5 ;
        RECT  56.736 63.916 56.76 64 ;
    END
  END b_rsp_data[229]
  PIN b_rsp_data[22]
    DIRECTION OUTPUT ;
    USE SIGNAL ;
    PORT
      LAYER M5 ;
        RECT  36.864 63.916 36.888 64 ;
    END
  END b_rsp_data[22]
  PIN b_rsp_data[230]
    DIRECTION OUTPUT ;
    USE SIGNAL ;
    PORT
      LAYER M5 ;
        RECT  56.832 63.916 56.856 64 ;
    END
  END b_rsp_data[230]
  PIN b_rsp_data[231]
    DIRECTION OUTPUT ;
    USE SIGNAL ;
    PORT
      LAYER M5 ;
        RECT  56.928 63.916 56.952 64 ;
    END
  END b_rsp_data[231]
  PIN b_rsp_data[232]
    DIRECTION OUTPUT ;
    USE SIGNAL ;
    PORT
      LAYER M5 ;
        RECT  57.024 63.916 57.048 64 ;
    END
  END b_rsp_data[232]
  PIN b_rsp_data[233]
    DIRECTION OUTPUT ;
    USE SIGNAL ;
    PORT
      LAYER M5 ;
        RECT  57.12 63.916 57.144 64 ;
    END
  END b_rsp_data[233]
  PIN b_rsp_data[234]
    DIRECTION OUTPUT ;
    USE SIGNAL ;
    PORT
      LAYER M5 ;
        RECT  57.216 63.916 57.24 64 ;
    END
  END b_rsp_data[234]
  PIN b_rsp_data[235]
    DIRECTION OUTPUT ;
    USE SIGNAL ;
    PORT
      LAYER M5 ;
        RECT  57.312 63.916 57.336 64 ;
    END
  END b_rsp_data[235]
  PIN b_rsp_data[236]
    DIRECTION OUTPUT ;
    USE SIGNAL ;
    PORT
      LAYER M5 ;
        RECT  57.408 63.916 57.432 64 ;
    END
  END b_rsp_data[236]
  PIN b_rsp_data[237]
    DIRECTION OUTPUT ;
    USE SIGNAL ;
    PORT
      LAYER M5 ;
        RECT  57.504 63.916 57.528 64 ;
    END
  END b_rsp_data[237]
  PIN b_rsp_data[238]
    DIRECTION OUTPUT ;
    USE SIGNAL ;
    PORT
      LAYER M5 ;
        RECT  57.6 63.916 57.624 64 ;
    END
  END b_rsp_data[238]
  PIN b_rsp_data[239]
    DIRECTION OUTPUT ;
    USE SIGNAL ;
    PORT
      LAYER M5 ;
        RECT  57.696 63.916 57.72 64 ;
    END
  END b_rsp_data[239]
  PIN b_rsp_data[23]
    DIRECTION OUTPUT ;
    USE SIGNAL ;
    PORT
      LAYER M5 ;
        RECT  36.96 63.916 36.984 64 ;
    END
  END b_rsp_data[23]
  PIN b_rsp_data[240]
    DIRECTION OUTPUT ;
    USE SIGNAL ;
    PORT
      LAYER M5 ;
        RECT  57.792 63.916 57.816 64 ;
    END
  END b_rsp_data[240]
  PIN b_rsp_data[241]
    DIRECTION OUTPUT ;
    USE SIGNAL ;
    PORT
      LAYER M5 ;
        RECT  57.888 63.916 57.912 64 ;
    END
  END b_rsp_data[241]
  PIN b_rsp_data[242]
    DIRECTION OUTPUT ;
    USE SIGNAL ;
    PORT
      LAYER M5 ;
        RECT  57.984 63.916 58.008 64 ;
    END
  END b_rsp_data[242]
  PIN b_rsp_data[243]
    DIRECTION OUTPUT ;
    USE SIGNAL ;
    PORT
      LAYER M5 ;
        RECT  58.08 63.916 58.104 64 ;
    END
  END b_rsp_data[243]
  PIN b_rsp_data[244]
    DIRECTION OUTPUT ;
    USE SIGNAL ;
    PORT
      LAYER M5 ;
        RECT  58.176 63.916 58.2 64 ;
    END
  END b_rsp_data[244]
  PIN b_rsp_data[245]
    DIRECTION OUTPUT ;
    USE SIGNAL ;
    PORT
      LAYER M5 ;
        RECT  58.272 63.916 58.296 64 ;
    END
  END b_rsp_data[245]
  PIN b_rsp_data[246]
    DIRECTION OUTPUT ;
    USE SIGNAL ;
    PORT
      LAYER M5 ;
        RECT  58.368 63.916 58.392 64 ;
    END
  END b_rsp_data[246]
  PIN b_rsp_data[247]
    DIRECTION OUTPUT ;
    USE SIGNAL ;
    PORT
      LAYER M5 ;
        RECT  58.464 63.916 58.488 64 ;
    END
  END b_rsp_data[247]
  PIN b_rsp_data[248]
    DIRECTION OUTPUT ;
    USE SIGNAL ;
    PORT
      LAYER M5 ;
        RECT  58.56 63.916 58.584 64 ;
    END
  END b_rsp_data[248]
  PIN b_rsp_data[249]
    DIRECTION OUTPUT ;
    USE SIGNAL ;
    PORT
      LAYER M5 ;
        RECT  58.656 63.916 58.68 64 ;
    END
  END b_rsp_data[249]
  PIN b_rsp_data[24]
    DIRECTION OUTPUT ;
    USE SIGNAL ;
    PORT
      LAYER M5 ;
        RECT  37.056 63.916 37.08 64 ;
    END
  END b_rsp_data[24]
  PIN b_rsp_data[250]
    DIRECTION OUTPUT ;
    USE SIGNAL ;
    PORT
      LAYER M5 ;
        RECT  58.752 63.916 58.776 64 ;
    END
  END b_rsp_data[250]
  PIN b_rsp_data[251]
    DIRECTION OUTPUT ;
    USE SIGNAL ;
    PORT
      LAYER M5 ;
        RECT  58.848 63.916 58.872 64 ;
    END
  END b_rsp_data[251]
  PIN b_rsp_data[252]
    DIRECTION OUTPUT ;
    USE SIGNAL ;
    PORT
      LAYER M5 ;
        RECT  58.944 63.916 58.968 64 ;
    END
  END b_rsp_data[252]
  PIN b_rsp_data[253]
    DIRECTION OUTPUT ;
    USE SIGNAL ;
    PORT
      LAYER M5 ;
        RECT  59.04 63.916 59.064 64 ;
    END
  END b_rsp_data[253]
  PIN b_rsp_data[254]
    DIRECTION OUTPUT ;
    USE SIGNAL ;
    PORT
      LAYER M5 ;
        RECT  59.136 63.916 59.16 64 ;
    END
  END b_rsp_data[254]
  PIN b_rsp_data[255]
    DIRECTION OUTPUT ;
    USE SIGNAL ;
    PORT
      LAYER M5 ;
        RECT  59.232 63.916 59.256 64 ;
    END
  END b_rsp_data[255]
  PIN b_rsp_data[25]
    DIRECTION OUTPUT ;
    USE SIGNAL ;
    PORT
      LAYER M5 ;
        RECT  37.152 63.916 37.176 64 ;
    END
  END b_rsp_data[25]
  PIN b_rsp_data[26]
    DIRECTION OUTPUT ;
    USE SIGNAL ;
    PORT
      LAYER M5 ;
        RECT  37.248 63.916 37.272 64 ;
    END
  END b_rsp_data[26]
  PIN b_rsp_data[27]
    DIRECTION OUTPUT ;
    USE SIGNAL ;
    PORT
      LAYER M5 ;
        RECT  37.344 63.916 37.368 64 ;
    END
  END b_rsp_data[27]
  PIN b_rsp_data[28]
    DIRECTION OUTPUT ;
    USE SIGNAL ;
    PORT
      LAYER M5 ;
        RECT  37.44 63.916 37.464 64 ;
    END
  END b_rsp_data[28]
  PIN b_rsp_data[29]
    DIRECTION OUTPUT ;
    USE SIGNAL ;
    PORT
      LAYER M5 ;
        RECT  37.536 63.916 37.56 64 ;
    END
  END b_rsp_data[29]
  PIN b_rsp_data[2]
    DIRECTION OUTPUT ;
    USE SIGNAL ;
    PORT
      LAYER M5 ;
        RECT  34.944 63.916 34.968 64 ;
    END
  END b_rsp_data[2]
  PIN b_rsp_data[30]
    DIRECTION OUTPUT ;
    USE SIGNAL ;
    PORT
      LAYER M5 ;
        RECT  37.632 63.916 37.656 64 ;
    END
  END b_rsp_data[30]
  PIN b_rsp_data[31]
    DIRECTION OUTPUT ;
    USE SIGNAL ;
    PORT
      LAYER M5 ;
        RECT  37.728 63.916 37.752 64 ;
    END
  END b_rsp_data[31]
  PIN b_rsp_data[32]
    DIRECTION OUTPUT ;
    USE SIGNAL ;
    PORT
      LAYER M5 ;
        RECT  37.824 63.916 37.848 64 ;
    END
  END b_rsp_data[32]
  PIN b_rsp_data[33]
    DIRECTION OUTPUT ;
    USE SIGNAL ;
    PORT
      LAYER M5 ;
        RECT  37.92 63.916 37.944 64 ;
    END
  END b_rsp_data[33]
  PIN b_rsp_data[34]
    DIRECTION OUTPUT ;
    USE SIGNAL ;
    PORT
      LAYER M5 ;
        RECT  38.016 63.916 38.04 64 ;
    END
  END b_rsp_data[34]
  PIN b_rsp_data[35]
    DIRECTION OUTPUT ;
    USE SIGNAL ;
    PORT
      LAYER M5 ;
        RECT  38.112 63.916 38.136 64 ;
    END
  END b_rsp_data[35]
  PIN b_rsp_data[36]
    DIRECTION OUTPUT ;
    USE SIGNAL ;
    PORT
      LAYER M5 ;
        RECT  38.208 63.916 38.232 64 ;
    END
  END b_rsp_data[36]
  PIN b_rsp_data[37]
    DIRECTION OUTPUT ;
    USE SIGNAL ;
    PORT
      LAYER M5 ;
        RECT  38.304 63.916 38.328 64 ;
    END
  END b_rsp_data[37]
  PIN b_rsp_data[38]
    DIRECTION OUTPUT ;
    USE SIGNAL ;
    PORT
      LAYER M5 ;
        RECT  38.4 63.916 38.424 64 ;
    END
  END b_rsp_data[38]
  PIN b_rsp_data[39]
    DIRECTION OUTPUT ;
    USE SIGNAL ;
    PORT
      LAYER M5 ;
        RECT  38.496 63.916 38.52 64 ;
    END
  END b_rsp_data[39]
  PIN b_rsp_data[3]
    DIRECTION OUTPUT ;
    USE SIGNAL ;
    PORT
      LAYER M5 ;
        RECT  35.04 63.916 35.064 64 ;
    END
  END b_rsp_data[3]
  PIN b_rsp_data[40]
    DIRECTION OUTPUT ;
    USE SIGNAL ;
    PORT
      LAYER M5 ;
        RECT  38.592 63.916 38.616 64 ;
    END
  END b_rsp_data[40]
  PIN b_rsp_data[41]
    DIRECTION OUTPUT ;
    USE SIGNAL ;
    PORT
      LAYER M5 ;
        RECT  38.688 63.916 38.712 64 ;
    END
  END b_rsp_data[41]
  PIN b_rsp_data[42]
    DIRECTION OUTPUT ;
    USE SIGNAL ;
    PORT
      LAYER M5 ;
        RECT  38.784 63.916 38.808 64 ;
    END
  END b_rsp_data[42]
  PIN b_rsp_data[43]
    DIRECTION OUTPUT ;
    USE SIGNAL ;
    PORT
      LAYER M5 ;
        RECT  38.88 63.916 38.904 64 ;
    END
  END b_rsp_data[43]
  PIN b_rsp_data[44]
    DIRECTION OUTPUT ;
    USE SIGNAL ;
    PORT
      LAYER M5 ;
        RECT  38.976 63.916 39 64 ;
    END
  END b_rsp_data[44]
  PIN b_rsp_data[45]
    DIRECTION OUTPUT ;
    USE SIGNAL ;
    PORT
      LAYER M5 ;
        RECT  39.072 63.916 39.096 64 ;
    END
  END b_rsp_data[45]
  PIN b_rsp_data[46]
    DIRECTION OUTPUT ;
    USE SIGNAL ;
    PORT
      LAYER M5 ;
        RECT  39.168 63.916 39.192 64 ;
    END
  END b_rsp_data[46]
  PIN b_rsp_data[47]
    DIRECTION OUTPUT ;
    USE SIGNAL ;
    PORT
      LAYER M5 ;
        RECT  39.264 63.916 39.288 64 ;
    END
  END b_rsp_data[47]
  PIN b_rsp_data[48]
    DIRECTION OUTPUT ;
    USE SIGNAL ;
    PORT
      LAYER M5 ;
        RECT  39.36 63.916 39.384 64 ;
    END
  END b_rsp_data[48]
  PIN b_rsp_data[49]
    DIRECTION OUTPUT ;
    USE SIGNAL ;
    PORT
      LAYER M5 ;
        RECT  39.456 63.916 39.48 64 ;
    END
  END b_rsp_data[49]
  PIN b_rsp_data[4]
    DIRECTION OUTPUT ;
    USE SIGNAL ;
    PORT
      LAYER M5 ;
        RECT  35.136 63.916 35.16 64 ;
    END
  END b_rsp_data[4]
  PIN b_rsp_data[50]
    DIRECTION OUTPUT ;
    USE SIGNAL ;
    PORT
      LAYER M5 ;
        RECT  39.552 63.916 39.576 64 ;
    END
  END b_rsp_data[50]
  PIN b_rsp_data[51]
    DIRECTION OUTPUT ;
    USE SIGNAL ;
    PORT
      LAYER M5 ;
        RECT  39.648 63.916 39.672 64 ;
    END
  END b_rsp_data[51]
  PIN b_rsp_data[52]
    DIRECTION OUTPUT ;
    USE SIGNAL ;
    PORT
      LAYER M5 ;
        RECT  39.744 63.916 39.768 64 ;
    END
  END b_rsp_data[52]
  PIN b_rsp_data[53]
    DIRECTION OUTPUT ;
    USE SIGNAL ;
    PORT
      LAYER M5 ;
        RECT  39.84 63.916 39.864 64 ;
    END
  END b_rsp_data[53]
  PIN b_rsp_data[54]
    DIRECTION OUTPUT ;
    USE SIGNAL ;
    PORT
      LAYER M5 ;
        RECT  39.936 63.916 39.96 64 ;
    END
  END b_rsp_data[54]
  PIN b_rsp_data[55]
    DIRECTION OUTPUT ;
    USE SIGNAL ;
    PORT
      LAYER M5 ;
        RECT  40.032 63.916 40.056 64 ;
    END
  END b_rsp_data[55]
  PIN b_rsp_data[56]
    DIRECTION OUTPUT ;
    USE SIGNAL ;
    PORT
      LAYER M5 ;
        RECT  40.128 63.916 40.152 64 ;
    END
  END b_rsp_data[56]
  PIN b_rsp_data[57]
    DIRECTION OUTPUT ;
    USE SIGNAL ;
    PORT
      LAYER M5 ;
        RECT  40.224 63.916 40.248 64 ;
    END
  END b_rsp_data[57]
  PIN b_rsp_data[58]
    DIRECTION OUTPUT ;
    USE SIGNAL ;
    PORT
      LAYER M5 ;
        RECT  40.32 63.916 40.344 64 ;
    END
  END b_rsp_data[58]
  PIN b_rsp_data[59]
    DIRECTION OUTPUT ;
    USE SIGNAL ;
    PORT
      LAYER M5 ;
        RECT  40.416 63.916 40.44 64 ;
    END
  END b_rsp_data[59]
  PIN b_rsp_data[5]
    DIRECTION OUTPUT ;
    USE SIGNAL ;
    PORT
      LAYER M5 ;
        RECT  35.232 63.916 35.256 64 ;
    END
  END b_rsp_data[5]
  PIN b_rsp_data[60]
    DIRECTION OUTPUT ;
    USE SIGNAL ;
    PORT
      LAYER M5 ;
        RECT  40.512 63.916 40.536 64 ;
    END
  END b_rsp_data[60]
  PIN b_rsp_data[61]
    DIRECTION OUTPUT ;
    USE SIGNAL ;
    PORT
      LAYER M5 ;
        RECT  40.608 63.916 40.632 64 ;
    END
  END b_rsp_data[61]
  PIN b_rsp_data[62]
    DIRECTION OUTPUT ;
    USE SIGNAL ;
    PORT
      LAYER M5 ;
        RECT  40.704 63.916 40.728 64 ;
    END
  END b_rsp_data[62]
  PIN b_rsp_data[63]
    DIRECTION OUTPUT ;
    USE SIGNAL ;
    PORT
      LAYER M5 ;
        RECT  40.8 63.916 40.824 64 ;
    END
  END b_rsp_data[63]
  PIN b_rsp_data[64]
    DIRECTION OUTPUT ;
    USE SIGNAL ;
    PORT
      LAYER M5 ;
        RECT  40.896 63.916 40.92 64 ;
    END
  END b_rsp_data[64]
  PIN b_rsp_data[65]
    DIRECTION OUTPUT ;
    USE SIGNAL ;
    PORT
      LAYER M5 ;
        RECT  40.992 63.916 41.016 64 ;
    END
  END b_rsp_data[65]
  PIN b_rsp_data[66]
    DIRECTION OUTPUT ;
    USE SIGNAL ;
    PORT
      LAYER M5 ;
        RECT  41.088 63.916 41.112 64 ;
    END
  END b_rsp_data[66]
  PIN b_rsp_data[67]
    DIRECTION OUTPUT ;
    USE SIGNAL ;
    PORT
      LAYER M5 ;
        RECT  41.184 63.916 41.208 64 ;
    END
  END b_rsp_data[67]
  PIN b_rsp_data[68]
    DIRECTION OUTPUT ;
    USE SIGNAL ;
    PORT
      LAYER M5 ;
        RECT  41.28 63.916 41.304 64 ;
    END
  END b_rsp_data[68]
  PIN b_rsp_data[69]
    DIRECTION OUTPUT ;
    USE SIGNAL ;
    PORT
      LAYER M5 ;
        RECT  41.376 63.916 41.4 64 ;
    END
  END b_rsp_data[69]
  PIN b_rsp_data[6]
    DIRECTION OUTPUT ;
    USE SIGNAL ;
    PORT
      LAYER M5 ;
        RECT  35.328 63.916 35.352 64 ;
    END
  END b_rsp_data[6]
  PIN b_rsp_data[70]
    DIRECTION OUTPUT ;
    USE SIGNAL ;
    PORT
      LAYER M5 ;
        RECT  41.472 63.916 41.496 64 ;
    END
  END b_rsp_data[70]
  PIN b_rsp_data[71]
    DIRECTION OUTPUT ;
    USE SIGNAL ;
    PORT
      LAYER M5 ;
        RECT  41.568 63.916 41.592 64 ;
    END
  END b_rsp_data[71]
  PIN b_rsp_data[72]
    DIRECTION OUTPUT ;
    USE SIGNAL ;
    PORT
      LAYER M5 ;
        RECT  41.664 63.916 41.688 64 ;
    END
  END b_rsp_data[72]
  PIN b_rsp_data[73]
    DIRECTION OUTPUT ;
    USE SIGNAL ;
    PORT
      LAYER M5 ;
        RECT  41.76 63.916 41.784 64 ;
    END
  END b_rsp_data[73]
  PIN b_rsp_data[74]
    DIRECTION OUTPUT ;
    USE SIGNAL ;
    PORT
      LAYER M5 ;
        RECT  41.856 63.916 41.88 64 ;
    END
  END b_rsp_data[74]
  PIN b_rsp_data[75]
    DIRECTION OUTPUT ;
    USE SIGNAL ;
    PORT
      LAYER M5 ;
        RECT  41.952 63.916 41.976 64 ;
    END
  END b_rsp_data[75]
  PIN b_rsp_data[76]
    DIRECTION OUTPUT ;
    USE SIGNAL ;
    PORT
      LAYER M5 ;
        RECT  42.048 63.916 42.072 64 ;
    END
  END b_rsp_data[76]
  PIN b_rsp_data[77]
    DIRECTION OUTPUT ;
    USE SIGNAL ;
    PORT
      LAYER M5 ;
        RECT  42.144 63.916 42.168 64 ;
    END
  END b_rsp_data[77]
  PIN b_rsp_data[78]
    DIRECTION OUTPUT ;
    USE SIGNAL ;
    PORT
      LAYER M5 ;
        RECT  42.24 63.916 42.264 64 ;
    END
  END b_rsp_data[78]
  PIN b_rsp_data[79]
    DIRECTION OUTPUT ;
    USE SIGNAL ;
    PORT
      LAYER M5 ;
        RECT  42.336 63.916 42.36 64 ;
    END
  END b_rsp_data[79]
  PIN b_rsp_data[7]
    DIRECTION OUTPUT ;
    USE SIGNAL ;
    PORT
      LAYER M5 ;
        RECT  35.424 63.916 35.448 64 ;
    END
  END b_rsp_data[7]
  PIN b_rsp_data[80]
    DIRECTION OUTPUT ;
    USE SIGNAL ;
    PORT
      LAYER M5 ;
        RECT  42.432 63.916 42.456 64 ;
    END
  END b_rsp_data[80]
  PIN b_rsp_data[81]
    DIRECTION OUTPUT ;
    USE SIGNAL ;
    PORT
      LAYER M5 ;
        RECT  42.528 63.916 42.552 64 ;
    END
  END b_rsp_data[81]
  PIN b_rsp_data[82]
    DIRECTION OUTPUT ;
    USE SIGNAL ;
    PORT
      LAYER M5 ;
        RECT  42.624 63.916 42.648 64 ;
    END
  END b_rsp_data[82]
  PIN b_rsp_data[83]
    DIRECTION OUTPUT ;
    USE SIGNAL ;
    PORT
      LAYER M5 ;
        RECT  42.72 63.916 42.744 64 ;
    END
  END b_rsp_data[83]
  PIN b_rsp_data[84]
    DIRECTION OUTPUT ;
    USE SIGNAL ;
    PORT
      LAYER M5 ;
        RECT  42.816 63.916 42.84 64 ;
    END
  END b_rsp_data[84]
  PIN b_rsp_data[85]
    DIRECTION OUTPUT ;
    USE SIGNAL ;
    PORT
      LAYER M5 ;
        RECT  42.912 63.916 42.936 64 ;
    END
  END b_rsp_data[85]
  PIN b_rsp_data[86]
    DIRECTION OUTPUT ;
    USE SIGNAL ;
    PORT
      LAYER M5 ;
        RECT  43.008 63.916 43.032 64 ;
    END
  END b_rsp_data[86]
  PIN b_rsp_data[87]
    DIRECTION OUTPUT ;
    USE SIGNAL ;
    PORT
      LAYER M5 ;
        RECT  43.104 63.916 43.128 64 ;
    END
  END b_rsp_data[87]
  PIN b_rsp_data[88]
    DIRECTION OUTPUT ;
    USE SIGNAL ;
    PORT
      LAYER M5 ;
        RECT  43.2 63.916 43.224 64 ;
    END
  END b_rsp_data[88]
  PIN b_rsp_data[89]
    DIRECTION OUTPUT ;
    USE SIGNAL ;
    PORT
      LAYER M5 ;
        RECT  43.296 63.916 43.32 64 ;
    END
  END b_rsp_data[89]
  PIN b_rsp_data[8]
    DIRECTION OUTPUT ;
    USE SIGNAL ;
    PORT
      LAYER M5 ;
        RECT  35.52 63.916 35.544 64 ;
    END
  END b_rsp_data[8]
  PIN b_rsp_data[90]
    DIRECTION OUTPUT ;
    USE SIGNAL ;
    PORT
      LAYER M5 ;
        RECT  43.392 63.916 43.416 64 ;
    END
  END b_rsp_data[90]
  PIN b_rsp_data[91]
    DIRECTION OUTPUT ;
    USE SIGNAL ;
    PORT
      LAYER M5 ;
        RECT  43.488 63.916 43.512 64 ;
    END
  END b_rsp_data[91]
  PIN b_rsp_data[92]
    DIRECTION OUTPUT ;
    USE SIGNAL ;
    PORT
      LAYER M5 ;
        RECT  43.584 63.916 43.608 64 ;
    END
  END b_rsp_data[92]
  PIN b_rsp_data[93]
    DIRECTION OUTPUT ;
    USE SIGNAL ;
    PORT
      LAYER M5 ;
        RECT  43.68 63.916 43.704 64 ;
    END
  END b_rsp_data[93]
  PIN b_rsp_data[94]
    DIRECTION OUTPUT ;
    USE SIGNAL ;
    PORT
      LAYER M5 ;
        RECT  43.776 63.916 43.8 64 ;
    END
  END b_rsp_data[94]
  PIN b_rsp_data[95]
    DIRECTION OUTPUT ;
    USE SIGNAL ;
    PORT
      LAYER M5 ;
        RECT  43.872 63.916 43.896 64 ;
    END
  END b_rsp_data[95]
  PIN b_rsp_data[96]
    DIRECTION OUTPUT ;
    USE SIGNAL ;
    PORT
      LAYER M5 ;
        RECT  43.968 63.916 43.992 64 ;
    END
  END b_rsp_data[96]
  PIN b_rsp_data[97]
    DIRECTION OUTPUT ;
    USE SIGNAL ;
    PORT
      LAYER M5 ;
        RECT  44.064 63.916 44.088 64 ;
    END
  END b_rsp_data[97]
  PIN b_rsp_data[98]
    DIRECTION OUTPUT ;
    USE SIGNAL ;
    PORT
      LAYER M5 ;
        RECT  44.16 63.916 44.184 64 ;
    END
  END b_rsp_data[98]
  PIN b_rsp_data[99]
    DIRECTION OUTPUT ;
    USE SIGNAL ;
    PORT
      LAYER M5 ;
        RECT  44.256 63.916 44.28 64 ;
    END
  END b_rsp_data[99]
  PIN b_rsp_data[9]
    DIRECTION OUTPUT ;
    USE SIGNAL ;
    PORT
      LAYER M5 ;
        RECT  35.616 63.916 35.64 64 ;
    END
  END b_rsp_data[9]
  PIN b_rsp_rdy
    DIRECTION INPUT ;
    USE SIGNAL ;
    PORT
      LAYER M5 ;
        RECT  59.328 63.916 59.352 64 ;
    END
  END b_rsp_rdy
  PIN b_rsp_tag[0]
    DIRECTION OUTPUT ;
    USE SIGNAL ;
    PORT
      LAYER M5 ;
        RECT  59.424 63.916 59.448 64 ;
    END
  END b_rsp_tag[0]
  PIN b_rsp_tag[10]
    DIRECTION OUTPUT ;
    USE SIGNAL ;
    PORT
      LAYER M5 ;
        RECT  60.384 63.916 60.408 64 ;
    END
  END b_rsp_tag[10]
  PIN b_rsp_tag[11]
    DIRECTION OUTPUT ;
    USE SIGNAL ;
    PORT
      LAYER M5 ;
        RECT  60.48 63.916 60.504 64 ;
    END
  END b_rsp_tag[11]
  PIN b_rsp_tag[12]
    DIRECTION OUTPUT ;
    USE SIGNAL ;
    PORT
      LAYER M5 ;
        RECT  60.576 63.916 60.6 64 ;
    END
  END b_rsp_tag[12]
  PIN b_rsp_tag[13]
    DIRECTION OUTPUT ;
    USE SIGNAL ;
    PORT
      LAYER M5 ;
        RECT  60.672 63.916 60.696 64 ;
    END
  END b_rsp_tag[13]
  PIN b_rsp_tag[14]
    DIRECTION OUTPUT ;
    USE SIGNAL ;
    PORT
      LAYER M5 ;
        RECT  60.768 63.916 60.792 64 ;
    END
  END b_rsp_tag[14]
  PIN b_rsp_tag[15]
    DIRECTION OUTPUT ;
    USE SIGNAL ;
    PORT
      LAYER M5 ;
        RECT  60.864 63.916 60.888 64 ;
    END
  END b_rsp_tag[15]
  PIN b_rsp_tag[1]
    DIRECTION OUTPUT ;
    USE SIGNAL ;
    PORT
      LAYER M5 ;
        RECT  59.52 63.916 59.544 64 ;
    END
  END b_rsp_tag[1]
  PIN b_rsp_tag[2]
    DIRECTION OUTPUT ;
    USE SIGNAL ;
    PORT
      LAYER M5 ;
        RECT  59.616 63.916 59.64 64 ;
    END
  END b_rsp_tag[2]
  PIN b_rsp_tag[3]
    DIRECTION OUTPUT ;
    USE SIGNAL ;
    PORT
      LAYER M5 ;
        RECT  59.712 63.916 59.736 64 ;
    END
  END b_rsp_tag[3]
  PIN b_rsp_tag[4]
    DIRECTION OUTPUT ;
    USE SIGNAL ;
    PORT
      LAYER M5 ;
        RECT  59.808 63.916 59.832 64 ;
    END
  END b_rsp_tag[4]
  PIN b_rsp_tag[5]
    DIRECTION OUTPUT ;
    USE SIGNAL ;
    PORT
      LAYER M5 ;
        RECT  59.904 63.916 59.928 64 ;
    END
  END b_rsp_tag[5]
  PIN b_rsp_tag[6]
    DIRECTION OUTPUT ;
    USE SIGNAL ;
    PORT
      LAYER M5 ;
        RECT  60 63.916 60.024 64 ;
    END
  END b_rsp_tag[6]
  PIN b_rsp_tag[7]
    DIRECTION OUTPUT ;
    USE SIGNAL ;
    PORT
      LAYER M5 ;
        RECT  60.096 63.916 60.12 64 ;
    END
  END b_rsp_tag[7]
  PIN b_rsp_tag[8]
    DIRECTION OUTPUT ;
    USE SIGNAL ;
    PORT
      LAYER M5 ;
        RECT  60.192 63.916 60.216 64 ;
    END
  END b_rsp_tag[8]
  PIN b_rsp_tag[9]
    DIRECTION OUTPUT ;
    USE SIGNAL ;
    PORT
      LAYER M5 ;
        RECT  60.288 63.916 60.312 64 ;
    END
  END b_rsp_tag[9]
  PIN b_rsp_v
    DIRECTION OUTPUT ;
    USE SIGNAL ;
    PORT
      LAYER M5 ;
        RECT  60.96 63.916 60.984 64 ;
    END
  END b_rsp_v
  PIN b_tag[0]
    DIRECTION INPUT ;
    USE SIGNAL ;
    PORT
      LAYER M5 ;
        RECT  61.056 63.916 61.08 64 ;
    END
  END b_tag[0]
  PIN b_tag[10]
    DIRECTION INPUT ;
    USE SIGNAL ;
    PORT
      LAYER M5 ;
        RECT  62.016 63.916 62.04 64 ;
    END
  END b_tag[10]
  PIN b_tag[11]
    DIRECTION INPUT ;
    USE SIGNAL ;
    PORT
      LAYER M5 ;
        RECT  62.112 63.916 62.136 64 ;
    END
  END b_tag[11]
  PIN b_tag[12]
    DIRECTION INPUT ;
    USE SIGNAL ;
    PORT
      LAYER M5 ;
        RECT  62.208 63.916 62.232 64 ;
    END
  END b_tag[12]
  PIN b_tag[13]
    DIRECTION INPUT ;
    USE SIGNAL ;
    PORT
      LAYER M5 ;
        RECT  62.304 63.916 62.328 64 ;
    END
  END b_tag[13]
  PIN b_tag[14]
    DIRECTION INPUT ;
    USE SIGNAL ;
    PORT
      LAYER M5 ;
        RECT  62.4 63.916 62.424 64 ;
    END
  END b_tag[14]
  PIN b_tag[15]
    DIRECTION INPUT ;
    USE SIGNAL ;
    PORT
      LAYER M5 ;
        RECT  62.496 63.916 62.52 64 ;
    END
  END b_tag[15]
  PIN b_tag[1]
    DIRECTION INPUT ;
    USE SIGNAL ;
    PORT
      LAYER M5 ;
        RECT  61.152 63.916 61.176 64 ;
    END
  END b_tag[1]
  PIN b_tag[2]
    DIRECTION INPUT ;
    USE SIGNAL ;
    PORT
      LAYER M5 ;
        RECT  61.248 63.916 61.272 64 ;
    END
  END b_tag[2]
  PIN b_tag[3]
    DIRECTION INPUT ;
    USE SIGNAL ;
    PORT
      LAYER M5 ;
        RECT  61.344 63.916 61.368 64 ;
    END
  END b_tag[3]
  PIN b_tag[4]
    DIRECTION INPUT ;
    USE SIGNAL ;
    PORT
      LAYER M5 ;
        RECT  61.44 63.916 61.464 64 ;
    END
  END b_tag[4]
  PIN b_tag[5]
    DIRECTION INPUT ;
    USE SIGNAL ;
    PORT
      LAYER M5 ;
        RECT  61.536 63.916 61.56 64 ;
    END
  END b_tag[5]
  PIN b_tag[6]
    DIRECTION INPUT ;
    USE SIGNAL ;
    PORT
      LAYER M5 ;
        RECT  61.632 63.916 61.656 64 ;
    END
  END b_tag[6]
  PIN b_tag[7]
    DIRECTION INPUT ;
    USE SIGNAL ;
    PORT
      LAYER M5 ;
        RECT  61.728 63.916 61.752 64 ;
    END
  END b_tag[7]
  PIN b_tag[8]
    DIRECTION INPUT ;
    USE SIGNAL ;
    PORT
      LAYER M5 ;
        RECT  61.824 63.916 61.848 64 ;
    END
  END b_tag[8]
  PIN b_tag[9]
    DIRECTION INPUT ;
    USE SIGNAL ;
    PORT
      LAYER M5 ;
        RECT  61.92 63.916 61.944 64 ;
    END
  END b_tag[9]
  PIN b_v
    DIRECTION INPUT ;
    USE SIGNAL ;
    PORT
      LAYER M5 ;
        RECT  62.592 63.916 62.616 64 ;
    END
  END b_v
  PIN b_wdata[0]
    DIRECTION INPUT ;
    USE SIGNAL ;
    PORT
      LAYER M5 ;
        RECT  62.688 63.916 62.712 64 ;
    END
  END b_wdata[0]
  PIN b_wdata[100]
    DIRECTION INPUT ;
    USE SIGNAL ;
    PORT
      LAYER M5 ;
        RECT  72.288 63.916 72.312 64 ;
    END
  END b_wdata[100]
  PIN b_wdata[101]
    DIRECTION INPUT ;
    USE SIGNAL ;
    PORT
      LAYER M5 ;
        RECT  72.384 63.916 72.408 64 ;
    END
  END b_wdata[101]
  PIN b_wdata[102]
    DIRECTION INPUT ;
    USE SIGNAL ;
    PORT
      LAYER M5 ;
        RECT  72.48 63.916 72.504 64 ;
    END
  END b_wdata[102]
  PIN b_wdata[103]
    DIRECTION INPUT ;
    USE SIGNAL ;
    PORT
      LAYER M5 ;
        RECT  72.576 63.916 72.6 64 ;
    END
  END b_wdata[103]
  PIN b_wdata[104]
    DIRECTION INPUT ;
    USE SIGNAL ;
    PORT
      LAYER M5 ;
        RECT  72.672 63.916 72.696 64 ;
    END
  END b_wdata[104]
  PIN b_wdata[105]
    DIRECTION INPUT ;
    USE SIGNAL ;
    PORT
      LAYER M5 ;
        RECT  72.768 63.916 72.792 64 ;
    END
  END b_wdata[105]
  PIN b_wdata[106]
    DIRECTION INPUT ;
    USE SIGNAL ;
    PORT
      LAYER M5 ;
        RECT  72.864 63.916 72.888 64 ;
    END
  END b_wdata[106]
  PIN b_wdata[107]
    DIRECTION INPUT ;
    USE SIGNAL ;
    PORT
      LAYER M5 ;
        RECT  72.96 63.916 72.984 64 ;
    END
  END b_wdata[107]
  PIN b_wdata[108]
    DIRECTION INPUT ;
    USE SIGNAL ;
    PORT
      LAYER M5 ;
        RECT  73.056 63.916 73.08 64 ;
    END
  END b_wdata[108]
  PIN b_wdata[109]
    DIRECTION INPUT ;
    USE SIGNAL ;
    PORT
      LAYER M5 ;
        RECT  73.152 63.916 73.176 64 ;
    END
  END b_wdata[109]
  PIN b_wdata[10]
    DIRECTION INPUT ;
    USE SIGNAL ;
    PORT
      LAYER M5 ;
        RECT  63.648 63.916 63.672 64 ;
    END
  END b_wdata[10]
  PIN b_wdata[110]
    DIRECTION INPUT ;
    USE SIGNAL ;
    PORT
      LAYER M5 ;
        RECT  73.248 63.916 73.272 64 ;
    END
  END b_wdata[110]
  PIN b_wdata[111]
    DIRECTION INPUT ;
    USE SIGNAL ;
    PORT
      LAYER M5 ;
        RECT  73.344 63.916 73.368 64 ;
    END
  END b_wdata[111]
  PIN b_wdata[112]
    DIRECTION INPUT ;
    USE SIGNAL ;
    PORT
      LAYER M5 ;
        RECT  73.44 63.916 73.464 64 ;
    END
  END b_wdata[112]
  PIN b_wdata[113]
    DIRECTION INPUT ;
    USE SIGNAL ;
    PORT
      LAYER M5 ;
        RECT  73.536 63.916 73.56 64 ;
    END
  END b_wdata[113]
  PIN b_wdata[114]
    DIRECTION INPUT ;
    USE SIGNAL ;
    PORT
      LAYER M5 ;
        RECT  73.632 63.916 73.656 64 ;
    END
  END b_wdata[114]
  PIN b_wdata[115]
    DIRECTION INPUT ;
    USE SIGNAL ;
    PORT
      LAYER M5 ;
        RECT  73.728 63.916 73.752 64 ;
    END
  END b_wdata[115]
  PIN b_wdata[116]
    DIRECTION INPUT ;
    USE SIGNAL ;
    PORT
      LAYER M5 ;
        RECT  73.824 63.916 73.848 64 ;
    END
  END b_wdata[116]
  PIN b_wdata[117]
    DIRECTION INPUT ;
    USE SIGNAL ;
    PORT
      LAYER M5 ;
        RECT  73.92 63.916 73.944 64 ;
    END
  END b_wdata[117]
  PIN b_wdata[118]
    DIRECTION INPUT ;
    USE SIGNAL ;
    PORT
      LAYER M5 ;
        RECT  74.016 63.916 74.04 64 ;
    END
  END b_wdata[118]
  PIN b_wdata[119]
    DIRECTION INPUT ;
    USE SIGNAL ;
    PORT
      LAYER M5 ;
        RECT  74.112 63.916 74.136 64 ;
    END
  END b_wdata[119]
  PIN b_wdata[11]
    DIRECTION INPUT ;
    USE SIGNAL ;
    PORT
      LAYER M5 ;
        RECT  63.744 63.916 63.768 64 ;
    END
  END b_wdata[11]
  PIN b_wdata[120]
    DIRECTION INPUT ;
    USE SIGNAL ;
    PORT
      LAYER M5 ;
        RECT  74.208 63.916 74.232 64 ;
    END
  END b_wdata[120]
  PIN b_wdata[121]
    DIRECTION INPUT ;
    USE SIGNAL ;
    PORT
      LAYER M5 ;
        RECT  74.304 63.916 74.328 64 ;
    END
  END b_wdata[121]
  PIN b_wdata[122]
    DIRECTION INPUT ;
    USE SIGNAL ;
    PORT
      LAYER M5 ;
        RECT  74.4 63.916 74.424 64 ;
    END
  END b_wdata[122]
  PIN b_wdata[123]
    DIRECTION INPUT ;
    USE SIGNAL ;
    PORT
      LAYER M5 ;
        RECT  74.496 63.916 74.52 64 ;
    END
  END b_wdata[123]
  PIN b_wdata[124]
    DIRECTION INPUT ;
    USE SIGNAL ;
    PORT
      LAYER M5 ;
        RECT  74.592 63.916 74.616 64 ;
    END
  END b_wdata[124]
  PIN b_wdata[125]
    DIRECTION INPUT ;
    USE SIGNAL ;
    PORT
      LAYER M5 ;
        RECT  74.688 63.916 74.712 64 ;
    END
  END b_wdata[125]
  PIN b_wdata[126]
    DIRECTION INPUT ;
    USE SIGNAL ;
    PORT
      LAYER M5 ;
        RECT  74.784 63.916 74.808 64 ;
    END
  END b_wdata[126]
  PIN b_wdata[127]
    DIRECTION INPUT ;
    USE SIGNAL ;
    PORT
      LAYER M5 ;
        RECT  74.88 63.916 74.904 64 ;
    END
  END b_wdata[127]
  PIN b_wdata[128]
    DIRECTION INPUT ;
    USE SIGNAL ;
    PORT
      LAYER M5 ;
        RECT  74.976 63.916 75 64 ;
    END
  END b_wdata[128]
  PIN b_wdata[129]
    DIRECTION INPUT ;
    USE SIGNAL ;
    PORT
      LAYER M5 ;
        RECT  75.072 63.916 75.096 64 ;
    END
  END b_wdata[129]
  PIN b_wdata[12]
    DIRECTION INPUT ;
    USE SIGNAL ;
    PORT
      LAYER M5 ;
        RECT  63.84 63.916 63.864 64 ;
    END
  END b_wdata[12]
  PIN b_wdata[130]
    DIRECTION INPUT ;
    USE SIGNAL ;
    PORT
      LAYER M5 ;
        RECT  75.168 63.916 75.192 64 ;
    END
  END b_wdata[130]
  PIN b_wdata[131]
    DIRECTION INPUT ;
    USE SIGNAL ;
    PORT
      LAYER M5 ;
        RECT  75.264 63.916 75.288 64 ;
    END
  END b_wdata[131]
  PIN b_wdata[132]
    DIRECTION INPUT ;
    USE SIGNAL ;
    PORT
      LAYER M5 ;
        RECT  75.36 63.916 75.384 64 ;
    END
  END b_wdata[132]
  PIN b_wdata[133]
    DIRECTION INPUT ;
    USE SIGNAL ;
    PORT
      LAYER M5 ;
        RECT  75.456 63.916 75.48 64 ;
    END
  END b_wdata[133]
  PIN b_wdata[134]
    DIRECTION INPUT ;
    USE SIGNAL ;
    PORT
      LAYER M5 ;
        RECT  75.552 63.916 75.576 64 ;
    END
  END b_wdata[134]
  PIN b_wdata[135]
    DIRECTION INPUT ;
    USE SIGNAL ;
    PORT
      LAYER M5 ;
        RECT  75.648 63.916 75.672 64 ;
    END
  END b_wdata[135]
  PIN b_wdata[136]
    DIRECTION INPUT ;
    USE SIGNAL ;
    PORT
      LAYER M5 ;
        RECT  75.744 63.916 75.768 64 ;
    END
  END b_wdata[136]
  PIN b_wdata[137]
    DIRECTION INPUT ;
    USE SIGNAL ;
    PORT
      LAYER M5 ;
        RECT  75.84 63.916 75.864 64 ;
    END
  END b_wdata[137]
  PIN b_wdata[138]
    DIRECTION INPUT ;
    USE SIGNAL ;
    PORT
      LAYER M5 ;
        RECT  75.936 63.916 75.96 64 ;
    END
  END b_wdata[138]
  PIN b_wdata[139]
    DIRECTION INPUT ;
    USE SIGNAL ;
    PORT
      LAYER M5 ;
        RECT  76.032 63.916 76.056 64 ;
    END
  END b_wdata[139]
  PIN b_wdata[13]
    DIRECTION INPUT ;
    USE SIGNAL ;
    PORT
      LAYER M5 ;
        RECT  63.936 63.916 63.96 64 ;
    END
  END b_wdata[13]
  PIN b_wdata[140]
    DIRECTION INPUT ;
    USE SIGNAL ;
    PORT
      LAYER M5 ;
        RECT  76.128 63.916 76.152 64 ;
    END
  END b_wdata[140]
  PIN b_wdata[141]
    DIRECTION INPUT ;
    USE SIGNAL ;
    PORT
      LAYER M5 ;
        RECT  76.224 63.916 76.248 64 ;
    END
  END b_wdata[141]
  PIN b_wdata[142]
    DIRECTION INPUT ;
    USE SIGNAL ;
    PORT
      LAYER M5 ;
        RECT  76.32 63.916 76.344 64 ;
    END
  END b_wdata[142]
  PIN b_wdata[143]
    DIRECTION INPUT ;
    USE SIGNAL ;
    PORT
      LAYER M5 ;
        RECT  76.416 63.916 76.44 64 ;
    END
  END b_wdata[143]
  PIN b_wdata[144]
    DIRECTION INPUT ;
    USE SIGNAL ;
    PORT
      LAYER M5 ;
        RECT  76.512 63.916 76.536 64 ;
    END
  END b_wdata[144]
  PIN b_wdata[145]
    DIRECTION INPUT ;
    USE SIGNAL ;
    PORT
      LAYER M5 ;
        RECT  76.608 63.916 76.632 64 ;
    END
  END b_wdata[145]
  PIN b_wdata[146]
    DIRECTION INPUT ;
    USE SIGNAL ;
    PORT
      LAYER M5 ;
        RECT  76.704 63.916 76.728 64 ;
    END
  END b_wdata[146]
  PIN b_wdata[147]
    DIRECTION INPUT ;
    USE SIGNAL ;
    PORT
      LAYER M5 ;
        RECT  76.8 63.916 76.824 64 ;
    END
  END b_wdata[147]
  PIN b_wdata[148]
    DIRECTION INPUT ;
    USE SIGNAL ;
    PORT
      LAYER M5 ;
        RECT  76.896 63.916 76.92 64 ;
    END
  END b_wdata[148]
  PIN b_wdata[149]
    DIRECTION INPUT ;
    USE SIGNAL ;
    PORT
      LAYER M5 ;
        RECT  76.992 63.916 77.016 64 ;
    END
  END b_wdata[149]
  PIN b_wdata[14]
    DIRECTION INPUT ;
    USE SIGNAL ;
    PORT
      LAYER M5 ;
        RECT  64.032 63.916 64.056 64 ;
    END
  END b_wdata[14]
  PIN b_wdata[150]
    DIRECTION INPUT ;
    USE SIGNAL ;
    PORT
      LAYER M5 ;
        RECT  77.088 63.916 77.112 64 ;
    END
  END b_wdata[150]
  PIN b_wdata[151]
    DIRECTION INPUT ;
    USE SIGNAL ;
    PORT
      LAYER M5 ;
        RECT  77.184 63.916 77.208 64 ;
    END
  END b_wdata[151]
  PIN b_wdata[152]
    DIRECTION INPUT ;
    USE SIGNAL ;
    PORT
      LAYER M5 ;
        RECT  77.28 63.916 77.304 64 ;
    END
  END b_wdata[152]
  PIN b_wdata[153]
    DIRECTION INPUT ;
    USE SIGNAL ;
    PORT
      LAYER M5 ;
        RECT  77.376 63.916 77.4 64 ;
    END
  END b_wdata[153]
  PIN b_wdata[154]
    DIRECTION INPUT ;
    USE SIGNAL ;
    PORT
      LAYER M5 ;
        RECT  77.472 63.916 77.496 64 ;
    END
  END b_wdata[154]
  PIN b_wdata[155]
    DIRECTION INPUT ;
    USE SIGNAL ;
    PORT
      LAYER M5 ;
        RECT  77.568 63.916 77.592 64 ;
    END
  END b_wdata[155]
  PIN b_wdata[156]
    DIRECTION INPUT ;
    USE SIGNAL ;
    PORT
      LAYER M5 ;
        RECT  77.664 63.916 77.688 64 ;
    END
  END b_wdata[156]
  PIN b_wdata[157]
    DIRECTION INPUT ;
    USE SIGNAL ;
    PORT
      LAYER M5 ;
        RECT  77.76 63.916 77.784 64 ;
    END
  END b_wdata[157]
  PIN b_wdata[158]
    DIRECTION INPUT ;
    USE SIGNAL ;
    PORT
      LAYER M5 ;
        RECT  77.856 63.916 77.88 64 ;
    END
  END b_wdata[158]
  PIN b_wdata[159]
    DIRECTION INPUT ;
    USE SIGNAL ;
    PORT
      LAYER M5 ;
        RECT  77.952 63.916 77.976 64 ;
    END
  END b_wdata[159]
  PIN b_wdata[15]
    DIRECTION INPUT ;
    USE SIGNAL ;
    PORT
      LAYER M5 ;
        RECT  64.128 63.916 64.152 64 ;
    END
  END b_wdata[15]
  PIN b_wdata[160]
    DIRECTION INPUT ;
    USE SIGNAL ;
    PORT
      LAYER M5 ;
        RECT  78.048 63.916 78.072 64 ;
    END
  END b_wdata[160]
  PIN b_wdata[161]
    DIRECTION INPUT ;
    USE SIGNAL ;
    PORT
      LAYER M5 ;
        RECT  78.144 63.916 78.168 64 ;
    END
  END b_wdata[161]
  PIN b_wdata[162]
    DIRECTION INPUT ;
    USE SIGNAL ;
    PORT
      LAYER M5 ;
        RECT  78.24 63.916 78.264 64 ;
    END
  END b_wdata[162]
  PIN b_wdata[163]
    DIRECTION INPUT ;
    USE SIGNAL ;
    PORT
      LAYER M5 ;
        RECT  78.336 63.916 78.36 64 ;
    END
  END b_wdata[163]
  PIN b_wdata[164]
    DIRECTION INPUT ;
    USE SIGNAL ;
    PORT
      LAYER M5 ;
        RECT  78.432 63.916 78.456 64 ;
    END
  END b_wdata[164]
  PIN b_wdata[165]
    DIRECTION INPUT ;
    USE SIGNAL ;
    PORT
      LAYER M5 ;
        RECT  78.528 63.916 78.552 64 ;
    END
  END b_wdata[165]
  PIN b_wdata[166]
    DIRECTION INPUT ;
    USE SIGNAL ;
    PORT
      LAYER M5 ;
        RECT  78.624 63.916 78.648 64 ;
    END
  END b_wdata[166]
  PIN b_wdata[167]
    DIRECTION INPUT ;
    USE SIGNAL ;
    PORT
      LAYER M5 ;
        RECT  78.72 63.916 78.744 64 ;
    END
  END b_wdata[167]
  PIN b_wdata[168]
    DIRECTION INPUT ;
    USE SIGNAL ;
    PORT
      LAYER M5 ;
        RECT  78.816 63.916 78.84 64 ;
    END
  END b_wdata[168]
  PIN b_wdata[169]
    DIRECTION INPUT ;
    USE SIGNAL ;
    PORT
      LAYER M5 ;
        RECT  78.912 63.916 78.936 64 ;
    END
  END b_wdata[169]
  PIN b_wdata[16]
    DIRECTION INPUT ;
    USE SIGNAL ;
    PORT
      LAYER M5 ;
        RECT  64.224 63.916 64.248 64 ;
    END
  END b_wdata[16]
  PIN b_wdata[170]
    DIRECTION INPUT ;
    USE SIGNAL ;
    PORT
      LAYER M5 ;
        RECT  79.008 63.916 79.032 64 ;
    END
  END b_wdata[170]
  PIN b_wdata[171]
    DIRECTION INPUT ;
    USE SIGNAL ;
    PORT
      LAYER M5 ;
        RECT  79.104 63.916 79.128 64 ;
    END
  END b_wdata[171]
  PIN b_wdata[172]
    DIRECTION INPUT ;
    USE SIGNAL ;
    PORT
      LAYER M5 ;
        RECT  79.2 63.916 79.224 64 ;
    END
  END b_wdata[172]
  PIN b_wdata[173]
    DIRECTION INPUT ;
    USE SIGNAL ;
    PORT
      LAYER M5 ;
        RECT  79.296 63.916 79.32 64 ;
    END
  END b_wdata[173]
  PIN b_wdata[174]
    DIRECTION INPUT ;
    USE SIGNAL ;
    PORT
      LAYER M5 ;
        RECT  79.392 63.916 79.416 64 ;
    END
  END b_wdata[174]
  PIN b_wdata[175]
    DIRECTION INPUT ;
    USE SIGNAL ;
    PORT
      LAYER M5 ;
        RECT  79.488 63.916 79.512 64 ;
    END
  END b_wdata[175]
  PIN b_wdata[176]
    DIRECTION INPUT ;
    USE SIGNAL ;
    PORT
      LAYER M5 ;
        RECT  79.584 63.916 79.608 64 ;
    END
  END b_wdata[176]
  PIN b_wdata[177]
    DIRECTION INPUT ;
    USE SIGNAL ;
    PORT
      LAYER M5 ;
        RECT  79.68 63.916 79.704 64 ;
    END
  END b_wdata[177]
  PIN b_wdata[178]
    DIRECTION INPUT ;
    USE SIGNAL ;
    PORT
      LAYER M5 ;
        RECT  79.776 63.916 79.8 64 ;
    END
  END b_wdata[178]
  PIN b_wdata[179]
    DIRECTION INPUT ;
    USE SIGNAL ;
    PORT
      LAYER M5 ;
        RECT  79.872 63.916 79.896 64 ;
    END
  END b_wdata[179]
  PIN b_wdata[17]
    DIRECTION INPUT ;
    USE SIGNAL ;
    PORT
      LAYER M5 ;
        RECT  64.32 63.916 64.344 64 ;
    END
  END b_wdata[17]
  PIN b_wdata[180]
    DIRECTION INPUT ;
    USE SIGNAL ;
    PORT
      LAYER M5 ;
        RECT  79.968 63.916 79.992 64 ;
    END
  END b_wdata[180]
  PIN b_wdata[181]
    DIRECTION INPUT ;
    USE SIGNAL ;
    PORT
      LAYER M5 ;
        RECT  80.064 63.916 80.088 64 ;
    END
  END b_wdata[181]
  PIN b_wdata[182]
    DIRECTION INPUT ;
    USE SIGNAL ;
    PORT
      LAYER M5 ;
        RECT  80.16 63.916 80.184 64 ;
    END
  END b_wdata[182]
  PIN b_wdata[183]
    DIRECTION INPUT ;
    USE SIGNAL ;
    PORT
      LAYER M5 ;
        RECT  80.256 63.916 80.28 64 ;
    END
  END b_wdata[183]
  PIN b_wdata[184]
    DIRECTION INPUT ;
    USE SIGNAL ;
    PORT
      LAYER M5 ;
        RECT  80.352 63.916 80.376 64 ;
    END
  END b_wdata[184]
  PIN b_wdata[185]
    DIRECTION INPUT ;
    USE SIGNAL ;
    PORT
      LAYER M5 ;
        RECT  80.448 63.916 80.472 64 ;
    END
  END b_wdata[185]
  PIN b_wdata[186]
    DIRECTION INPUT ;
    USE SIGNAL ;
    PORT
      LAYER M5 ;
        RECT  80.544 63.916 80.568 64 ;
    END
  END b_wdata[186]
  PIN b_wdata[187]
    DIRECTION INPUT ;
    USE SIGNAL ;
    PORT
      LAYER M5 ;
        RECT  80.64 63.916 80.664 64 ;
    END
  END b_wdata[187]
  PIN b_wdata[188]
    DIRECTION INPUT ;
    USE SIGNAL ;
    PORT
      LAYER M5 ;
        RECT  80.736 63.916 80.76 64 ;
    END
  END b_wdata[188]
  PIN b_wdata[189]
    DIRECTION INPUT ;
    USE SIGNAL ;
    PORT
      LAYER M5 ;
        RECT  80.832 63.916 80.856 64 ;
    END
  END b_wdata[189]
  PIN b_wdata[18]
    DIRECTION INPUT ;
    USE SIGNAL ;
    PORT
      LAYER M5 ;
        RECT  64.416 63.916 64.44 64 ;
    END
  END b_wdata[18]
  PIN b_wdata[190]
    DIRECTION INPUT ;
    USE SIGNAL ;
    PORT
      LAYER M5 ;
        RECT  80.928 63.916 80.952 64 ;
    END
  END b_wdata[190]
  PIN b_wdata[191]
    DIRECTION INPUT ;
    USE SIGNAL ;
    PORT
      LAYER M5 ;
        RECT  81.024 63.916 81.048 64 ;
    END
  END b_wdata[191]
  PIN b_wdata[192]
    DIRECTION INPUT ;
    USE SIGNAL ;
    PORT
      LAYER M5 ;
        RECT  81.12 63.916 81.144 64 ;
    END
  END b_wdata[192]
  PIN b_wdata[193]
    DIRECTION INPUT ;
    USE SIGNAL ;
    PORT
      LAYER M5 ;
        RECT  81.216 63.916 81.24 64 ;
    END
  END b_wdata[193]
  PIN b_wdata[194]
    DIRECTION INPUT ;
    USE SIGNAL ;
    PORT
      LAYER M5 ;
        RECT  81.312 63.916 81.336 64 ;
    END
  END b_wdata[194]
  PIN b_wdata[195]
    DIRECTION INPUT ;
    USE SIGNAL ;
    PORT
      LAYER M5 ;
        RECT  81.408 63.916 81.432 64 ;
    END
  END b_wdata[195]
  PIN b_wdata[196]
    DIRECTION INPUT ;
    USE SIGNAL ;
    PORT
      LAYER M5 ;
        RECT  81.504 63.916 81.528 64 ;
    END
  END b_wdata[196]
  PIN b_wdata[197]
    DIRECTION INPUT ;
    USE SIGNAL ;
    PORT
      LAYER M5 ;
        RECT  81.6 63.916 81.624 64 ;
    END
  END b_wdata[197]
  PIN b_wdata[198]
    DIRECTION INPUT ;
    USE SIGNAL ;
    PORT
      LAYER M5 ;
        RECT  81.696 63.916 81.72 64 ;
    END
  END b_wdata[198]
  PIN b_wdata[199]
    DIRECTION INPUT ;
    USE SIGNAL ;
    PORT
      LAYER M5 ;
        RECT  81.792 63.916 81.816 64 ;
    END
  END b_wdata[199]
  PIN b_wdata[19]
    DIRECTION INPUT ;
    USE SIGNAL ;
    PORT
      LAYER M5 ;
        RECT  64.512 63.916 64.536 64 ;
    END
  END b_wdata[19]
  PIN b_wdata[1]
    DIRECTION INPUT ;
    USE SIGNAL ;
    PORT
      LAYER M5 ;
        RECT  62.784 63.916 62.808 64 ;
    END
  END b_wdata[1]
  PIN b_wdata[200]
    DIRECTION INPUT ;
    USE SIGNAL ;
    PORT
      LAYER M5 ;
        RECT  81.888 63.916 81.912 64 ;
    END
  END b_wdata[200]
  PIN b_wdata[201]
    DIRECTION INPUT ;
    USE SIGNAL ;
    PORT
      LAYER M5 ;
        RECT  81.984 63.916 82.008 64 ;
    END
  END b_wdata[201]
  PIN b_wdata[202]
    DIRECTION INPUT ;
    USE SIGNAL ;
    PORT
      LAYER M5 ;
        RECT  82.08 63.916 82.104 64 ;
    END
  END b_wdata[202]
  PIN b_wdata[203]
    DIRECTION INPUT ;
    USE SIGNAL ;
    PORT
      LAYER M5 ;
        RECT  82.176 63.916 82.2 64 ;
    END
  END b_wdata[203]
  PIN b_wdata[204]
    DIRECTION INPUT ;
    USE SIGNAL ;
    PORT
      LAYER M5 ;
        RECT  82.272 63.916 82.296 64 ;
    END
  END b_wdata[204]
  PIN b_wdata[205]
    DIRECTION INPUT ;
    USE SIGNAL ;
    PORT
      LAYER M5 ;
        RECT  82.368 63.916 82.392 64 ;
    END
  END b_wdata[205]
  PIN b_wdata[206]
    DIRECTION INPUT ;
    USE SIGNAL ;
    PORT
      LAYER M5 ;
        RECT  82.464 63.916 82.488 64 ;
    END
  END b_wdata[206]
  PIN b_wdata[207]
    DIRECTION INPUT ;
    USE SIGNAL ;
    PORT
      LAYER M5 ;
        RECT  82.56 63.916 82.584 64 ;
    END
  END b_wdata[207]
  PIN b_wdata[208]
    DIRECTION INPUT ;
    USE SIGNAL ;
    PORT
      LAYER M5 ;
        RECT  82.656 63.916 82.68 64 ;
    END
  END b_wdata[208]
  PIN b_wdata[209]
    DIRECTION INPUT ;
    USE SIGNAL ;
    PORT
      LAYER M5 ;
        RECT  82.752 63.916 82.776 64 ;
    END
  END b_wdata[209]
  PIN b_wdata[20]
    DIRECTION INPUT ;
    USE SIGNAL ;
    PORT
      LAYER M5 ;
        RECT  64.608 63.916 64.632 64 ;
    END
  END b_wdata[20]
  PIN b_wdata[210]
    DIRECTION INPUT ;
    USE SIGNAL ;
    PORT
      LAYER M5 ;
        RECT  82.848 63.916 82.872 64 ;
    END
  END b_wdata[210]
  PIN b_wdata[211]
    DIRECTION INPUT ;
    USE SIGNAL ;
    PORT
      LAYER M5 ;
        RECT  82.944 63.916 82.968 64 ;
    END
  END b_wdata[211]
  PIN b_wdata[212]
    DIRECTION INPUT ;
    USE SIGNAL ;
    PORT
      LAYER M5 ;
        RECT  83.04 63.916 83.064 64 ;
    END
  END b_wdata[212]
  PIN b_wdata[213]
    DIRECTION INPUT ;
    USE SIGNAL ;
    PORT
      LAYER M5 ;
        RECT  83.136 63.916 83.16 64 ;
    END
  END b_wdata[213]
  PIN b_wdata[214]
    DIRECTION INPUT ;
    USE SIGNAL ;
    PORT
      LAYER M5 ;
        RECT  83.232 63.916 83.256 64 ;
    END
  END b_wdata[214]
  PIN b_wdata[215]
    DIRECTION INPUT ;
    USE SIGNAL ;
    PORT
      LAYER M5 ;
        RECT  83.328 63.916 83.352 64 ;
    END
  END b_wdata[215]
  PIN b_wdata[216]
    DIRECTION INPUT ;
    USE SIGNAL ;
    PORT
      LAYER M5 ;
        RECT  83.424 63.916 83.448 64 ;
    END
  END b_wdata[216]
  PIN b_wdata[217]
    DIRECTION INPUT ;
    USE SIGNAL ;
    PORT
      LAYER M5 ;
        RECT  83.52 63.916 83.544 64 ;
    END
  END b_wdata[217]
  PIN b_wdata[218]
    DIRECTION INPUT ;
    USE SIGNAL ;
    PORT
      LAYER M5 ;
        RECT  83.616 63.916 83.64 64 ;
    END
  END b_wdata[218]
  PIN b_wdata[219]
    DIRECTION INPUT ;
    USE SIGNAL ;
    PORT
      LAYER M5 ;
        RECT  83.712 63.916 83.736 64 ;
    END
  END b_wdata[219]
  PIN b_wdata[21]
    DIRECTION INPUT ;
    USE SIGNAL ;
    PORT
      LAYER M5 ;
        RECT  64.704 63.916 64.728 64 ;
    END
  END b_wdata[21]
  PIN b_wdata[220]
    DIRECTION INPUT ;
    USE SIGNAL ;
    PORT
      LAYER M5 ;
        RECT  83.808 63.916 83.832 64 ;
    END
  END b_wdata[220]
  PIN b_wdata[221]
    DIRECTION INPUT ;
    USE SIGNAL ;
    PORT
      LAYER M5 ;
        RECT  83.904 63.916 83.928 64 ;
    END
  END b_wdata[221]
  PIN b_wdata[222]
    DIRECTION INPUT ;
    USE SIGNAL ;
    PORT
      LAYER M5 ;
        RECT  84 63.916 84.024 64 ;
    END
  END b_wdata[222]
  PIN b_wdata[223]
    DIRECTION INPUT ;
    USE SIGNAL ;
    PORT
      LAYER M5 ;
        RECT  84.096 63.916 84.12 64 ;
    END
  END b_wdata[223]
  PIN b_wdata[224]
    DIRECTION INPUT ;
    USE SIGNAL ;
    PORT
      LAYER M5 ;
        RECT  84.192 63.916 84.216 64 ;
    END
  END b_wdata[224]
  PIN b_wdata[225]
    DIRECTION INPUT ;
    USE SIGNAL ;
    PORT
      LAYER M5 ;
        RECT  84.288 63.916 84.312 64 ;
    END
  END b_wdata[225]
  PIN b_wdata[226]
    DIRECTION INPUT ;
    USE SIGNAL ;
    PORT
      LAYER M5 ;
        RECT  84.384 63.916 84.408 64 ;
    END
  END b_wdata[226]
  PIN b_wdata[227]
    DIRECTION INPUT ;
    USE SIGNAL ;
    PORT
      LAYER M5 ;
        RECT  84.48 63.916 84.504 64 ;
    END
  END b_wdata[227]
  PIN b_wdata[228]
    DIRECTION INPUT ;
    USE SIGNAL ;
    PORT
      LAYER M5 ;
        RECT  84.576 63.916 84.6 64 ;
    END
  END b_wdata[228]
  PIN b_wdata[229]
    DIRECTION INPUT ;
    USE SIGNAL ;
    PORT
      LAYER M5 ;
        RECT  84.672 63.916 84.696 64 ;
    END
  END b_wdata[229]
  PIN b_wdata[22]
    DIRECTION INPUT ;
    USE SIGNAL ;
    PORT
      LAYER M5 ;
        RECT  64.8 63.916 64.824 64 ;
    END
  END b_wdata[22]
  PIN b_wdata[230]
    DIRECTION INPUT ;
    USE SIGNAL ;
    PORT
      LAYER M5 ;
        RECT  84.768 63.916 84.792 64 ;
    END
  END b_wdata[230]
  PIN b_wdata[231]
    DIRECTION INPUT ;
    USE SIGNAL ;
    PORT
      LAYER M5 ;
        RECT  84.864 63.916 84.888 64 ;
    END
  END b_wdata[231]
  PIN b_wdata[232]
    DIRECTION INPUT ;
    USE SIGNAL ;
    PORT
      LAYER M5 ;
        RECT  84.96 63.916 84.984 64 ;
    END
  END b_wdata[232]
  PIN b_wdata[233]
    DIRECTION INPUT ;
    USE SIGNAL ;
    PORT
      LAYER M5 ;
        RECT  85.056 63.916 85.08 64 ;
    END
  END b_wdata[233]
  PIN b_wdata[234]
    DIRECTION INPUT ;
    USE SIGNAL ;
    PORT
      LAYER M5 ;
        RECT  85.152 63.916 85.176 64 ;
    END
  END b_wdata[234]
  PIN b_wdata[235]
    DIRECTION INPUT ;
    USE SIGNAL ;
    PORT
      LAYER M5 ;
        RECT  85.248 63.916 85.272 64 ;
    END
  END b_wdata[235]
  PIN b_wdata[236]
    DIRECTION INPUT ;
    USE SIGNAL ;
    PORT
      LAYER M5 ;
        RECT  85.344 63.916 85.368 64 ;
    END
  END b_wdata[236]
  PIN b_wdata[237]
    DIRECTION INPUT ;
    USE SIGNAL ;
    PORT
      LAYER M5 ;
        RECT  85.44 63.916 85.464 64 ;
    END
  END b_wdata[237]
  PIN b_wdata[238]
    DIRECTION INPUT ;
    USE SIGNAL ;
    PORT
      LAYER M5 ;
        RECT  85.536 63.916 85.56 64 ;
    END
  END b_wdata[238]
  PIN b_wdata[239]
    DIRECTION INPUT ;
    USE SIGNAL ;
    PORT
      LAYER M5 ;
        RECT  85.632 63.916 85.656 64 ;
    END
  END b_wdata[239]
  PIN b_wdata[23]
    DIRECTION INPUT ;
    USE SIGNAL ;
    PORT
      LAYER M5 ;
        RECT  64.896 63.916 64.92 64 ;
    END
  END b_wdata[23]
  PIN b_wdata[240]
    DIRECTION INPUT ;
    USE SIGNAL ;
    PORT
      LAYER M5 ;
        RECT  85.728 63.916 85.752 64 ;
    END
  END b_wdata[240]
  PIN b_wdata[241]
    DIRECTION INPUT ;
    USE SIGNAL ;
    PORT
      LAYER M5 ;
        RECT  85.824 63.916 85.848 64 ;
    END
  END b_wdata[241]
  PIN b_wdata[242]
    DIRECTION INPUT ;
    USE SIGNAL ;
    PORT
      LAYER M5 ;
        RECT  85.92 63.916 85.944 64 ;
    END
  END b_wdata[242]
  PIN b_wdata[243]
    DIRECTION INPUT ;
    USE SIGNAL ;
    PORT
      LAYER M5 ;
        RECT  86.016 63.916 86.04 64 ;
    END
  END b_wdata[243]
  PIN b_wdata[244]
    DIRECTION INPUT ;
    USE SIGNAL ;
    PORT
      LAYER M5 ;
        RECT  86.112 63.916 86.136 64 ;
    END
  END b_wdata[244]
  PIN b_wdata[245]
    DIRECTION INPUT ;
    USE SIGNAL ;
    PORT
      LAYER M5 ;
        RECT  86.208 63.916 86.232 64 ;
    END
  END b_wdata[245]
  PIN b_wdata[246]
    DIRECTION INPUT ;
    USE SIGNAL ;
    PORT
      LAYER M5 ;
        RECT  86.304 63.916 86.328 64 ;
    END
  END b_wdata[246]
  PIN b_wdata[247]
    DIRECTION INPUT ;
    USE SIGNAL ;
    PORT
      LAYER M5 ;
        RECT  86.4 63.916 86.424 64 ;
    END
  END b_wdata[247]
  PIN b_wdata[248]
    DIRECTION INPUT ;
    USE SIGNAL ;
    PORT
      LAYER M5 ;
        RECT  86.496 63.916 86.52 64 ;
    END
  END b_wdata[248]
  PIN b_wdata[249]
    DIRECTION INPUT ;
    USE SIGNAL ;
    PORT
      LAYER M5 ;
        RECT  86.592 63.916 86.616 64 ;
    END
  END b_wdata[249]
  PIN b_wdata[24]
    DIRECTION INPUT ;
    USE SIGNAL ;
    PORT
      LAYER M5 ;
        RECT  64.992 63.916 65.016 64 ;
    END
  END b_wdata[24]
  PIN b_wdata[250]
    DIRECTION INPUT ;
    USE SIGNAL ;
    PORT
      LAYER M5 ;
        RECT  86.688 63.916 86.712 64 ;
    END
  END b_wdata[250]
  PIN b_wdata[251]
    DIRECTION INPUT ;
    USE SIGNAL ;
    PORT
      LAYER M5 ;
        RECT  86.784 63.916 86.808 64 ;
    END
  END b_wdata[251]
  PIN b_wdata[252]
    DIRECTION INPUT ;
    USE SIGNAL ;
    PORT
      LAYER M5 ;
        RECT  86.88 63.916 86.904 64 ;
    END
  END b_wdata[252]
  PIN b_wdata[253]
    DIRECTION INPUT ;
    USE SIGNAL ;
    PORT
      LAYER M5 ;
        RECT  86.976 63.916 87 64 ;
    END
  END b_wdata[253]
  PIN b_wdata[254]
    DIRECTION INPUT ;
    USE SIGNAL ;
    PORT
      LAYER M5 ;
        RECT  87.072 63.916 87.096 64 ;
    END
  END b_wdata[254]
  PIN b_wdata[255]
    DIRECTION INPUT ;
    USE SIGNAL ;
    PORT
      LAYER M5 ;
        RECT  87.168 63.916 87.192 64 ;
    END
  END b_wdata[255]
  PIN b_wdata[25]
    DIRECTION INPUT ;
    USE SIGNAL ;
    PORT
      LAYER M5 ;
        RECT  65.088 63.916 65.112 64 ;
    END
  END b_wdata[25]
  PIN b_wdata[26]
    DIRECTION INPUT ;
    USE SIGNAL ;
    PORT
      LAYER M5 ;
        RECT  65.184 63.916 65.208 64 ;
    END
  END b_wdata[26]
  PIN b_wdata[27]
    DIRECTION INPUT ;
    USE SIGNAL ;
    PORT
      LAYER M5 ;
        RECT  65.28 63.916 65.304 64 ;
    END
  END b_wdata[27]
  PIN b_wdata[28]
    DIRECTION INPUT ;
    USE SIGNAL ;
    PORT
      LAYER M5 ;
        RECT  65.376 63.916 65.4 64 ;
    END
  END b_wdata[28]
  PIN b_wdata[29]
    DIRECTION INPUT ;
    USE SIGNAL ;
    PORT
      LAYER M5 ;
        RECT  65.472 63.916 65.496 64 ;
    END
  END b_wdata[29]
  PIN b_wdata[2]
    DIRECTION INPUT ;
    USE SIGNAL ;
    PORT
      LAYER M5 ;
        RECT  62.88 63.916 62.904 64 ;
    END
  END b_wdata[2]
  PIN b_wdata[30]
    DIRECTION INPUT ;
    USE SIGNAL ;
    PORT
      LAYER M5 ;
        RECT  65.568 63.916 65.592 64 ;
    END
  END b_wdata[30]
  PIN b_wdata[31]
    DIRECTION INPUT ;
    USE SIGNAL ;
    PORT
      LAYER M5 ;
        RECT  65.664 63.916 65.688 64 ;
    END
  END b_wdata[31]
  PIN b_wdata[32]
    DIRECTION INPUT ;
    USE SIGNAL ;
    PORT
      LAYER M5 ;
        RECT  65.76 63.916 65.784 64 ;
    END
  END b_wdata[32]
  PIN b_wdata[33]
    DIRECTION INPUT ;
    USE SIGNAL ;
    PORT
      LAYER M5 ;
        RECT  65.856 63.916 65.88 64 ;
    END
  END b_wdata[33]
  PIN b_wdata[34]
    DIRECTION INPUT ;
    USE SIGNAL ;
    PORT
      LAYER M5 ;
        RECT  65.952 63.916 65.976 64 ;
    END
  END b_wdata[34]
  PIN b_wdata[35]
    DIRECTION INPUT ;
    USE SIGNAL ;
    PORT
      LAYER M5 ;
        RECT  66.048 63.916 66.072 64 ;
    END
  END b_wdata[35]
  PIN b_wdata[36]
    DIRECTION INPUT ;
    USE SIGNAL ;
    PORT
      LAYER M5 ;
        RECT  66.144 63.916 66.168 64 ;
    END
  END b_wdata[36]
  PIN b_wdata[37]
    DIRECTION INPUT ;
    USE SIGNAL ;
    PORT
      LAYER M5 ;
        RECT  66.24 63.916 66.264 64 ;
    END
  END b_wdata[37]
  PIN b_wdata[38]
    DIRECTION INPUT ;
    USE SIGNAL ;
    PORT
      LAYER M5 ;
        RECT  66.336 63.916 66.36 64 ;
    END
  END b_wdata[38]
  PIN b_wdata[39]
    DIRECTION INPUT ;
    USE SIGNAL ;
    PORT
      LAYER M5 ;
        RECT  66.432 63.916 66.456 64 ;
    END
  END b_wdata[39]
  PIN b_wdata[3]
    DIRECTION INPUT ;
    USE SIGNAL ;
    PORT
      LAYER M5 ;
        RECT  62.976 63.916 63 64 ;
    END
  END b_wdata[3]
  PIN b_wdata[40]
    DIRECTION INPUT ;
    USE SIGNAL ;
    PORT
      LAYER M5 ;
        RECT  66.528 63.916 66.552 64 ;
    END
  END b_wdata[40]
  PIN b_wdata[41]
    DIRECTION INPUT ;
    USE SIGNAL ;
    PORT
      LAYER M5 ;
        RECT  66.624 63.916 66.648 64 ;
    END
  END b_wdata[41]
  PIN b_wdata[42]
    DIRECTION INPUT ;
    USE SIGNAL ;
    PORT
      LAYER M5 ;
        RECT  66.72 63.916 66.744 64 ;
    END
  END b_wdata[42]
  PIN b_wdata[43]
    DIRECTION INPUT ;
    USE SIGNAL ;
    PORT
      LAYER M5 ;
        RECT  66.816 63.916 66.84 64 ;
    END
  END b_wdata[43]
  PIN b_wdata[44]
    DIRECTION INPUT ;
    USE SIGNAL ;
    PORT
      LAYER M5 ;
        RECT  66.912 63.916 66.936 64 ;
    END
  END b_wdata[44]
  PIN b_wdata[45]
    DIRECTION INPUT ;
    USE SIGNAL ;
    PORT
      LAYER M5 ;
        RECT  67.008 63.916 67.032 64 ;
    END
  END b_wdata[45]
  PIN b_wdata[46]
    DIRECTION INPUT ;
    USE SIGNAL ;
    PORT
      LAYER M5 ;
        RECT  67.104 63.916 67.128 64 ;
    END
  END b_wdata[46]
  PIN b_wdata[47]
    DIRECTION INPUT ;
    USE SIGNAL ;
    PORT
      LAYER M5 ;
        RECT  67.2 63.916 67.224 64 ;
    END
  END b_wdata[47]
  PIN b_wdata[48]
    DIRECTION INPUT ;
    USE SIGNAL ;
    PORT
      LAYER M5 ;
        RECT  67.296 63.916 67.32 64 ;
    END
  END b_wdata[48]
  PIN b_wdata[49]
    DIRECTION INPUT ;
    USE SIGNAL ;
    PORT
      LAYER M5 ;
        RECT  67.392 63.916 67.416 64 ;
    END
  END b_wdata[49]
  PIN b_wdata[4]
    DIRECTION INPUT ;
    USE SIGNAL ;
    PORT
      LAYER M5 ;
        RECT  63.072 63.916 63.096 64 ;
    END
  END b_wdata[4]
  PIN b_wdata[50]
    DIRECTION INPUT ;
    USE SIGNAL ;
    PORT
      LAYER M5 ;
        RECT  67.488 63.916 67.512 64 ;
    END
  END b_wdata[50]
  PIN b_wdata[51]
    DIRECTION INPUT ;
    USE SIGNAL ;
    PORT
      LAYER M5 ;
        RECT  67.584 63.916 67.608 64 ;
    END
  END b_wdata[51]
  PIN b_wdata[52]
    DIRECTION INPUT ;
    USE SIGNAL ;
    PORT
      LAYER M5 ;
        RECT  67.68 63.916 67.704 64 ;
    END
  END b_wdata[52]
  PIN b_wdata[53]
    DIRECTION INPUT ;
    USE SIGNAL ;
    PORT
      LAYER M5 ;
        RECT  67.776 63.916 67.8 64 ;
    END
  END b_wdata[53]
  PIN b_wdata[54]
    DIRECTION INPUT ;
    USE SIGNAL ;
    PORT
      LAYER M5 ;
        RECT  67.872 63.916 67.896 64 ;
    END
  END b_wdata[54]
  PIN b_wdata[55]
    DIRECTION INPUT ;
    USE SIGNAL ;
    PORT
      LAYER M5 ;
        RECT  67.968 63.916 67.992 64 ;
    END
  END b_wdata[55]
  PIN b_wdata[56]
    DIRECTION INPUT ;
    USE SIGNAL ;
    PORT
      LAYER M5 ;
        RECT  68.064 63.916 68.088 64 ;
    END
  END b_wdata[56]
  PIN b_wdata[57]
    DIRECTION INPUT ;
    USE SIGNAL ;
    PORT
      LAYER M5 ;
        RECT  68.16 63.916 68.184 64 ;
    END
  END b_wdata[57]
  PIN b_wdata[58]
    DIRECTION INPUT ;
    USE SIGNAL ;
    PORT
      LAYER M5 ;
        RECT  68.256 63.916 68.28 64 ;
    END
  END b_wdata[58]
  PIN b_wdata[59]
    DIRECTION INPUT ;
    USE SIGNAL ;
    PORT
      LAYER M5 ;
        RECT  68.352 63.916 68.376 64 ;
    END
  END b_wdata[59]
  PIN b_wdata[5]
    DIRECTION INPUT ;
    USE SIGNAL ;
    PORT
      LAYER M5 ;
        RECT  63.168 63.916 63.192 64 ;
    END
  END b_wdata[5]
  PIN b_wdata[60]
    DIRECTION INPUT ;
    USE SIGNAL ;
    PORT
      LAYER M5 ;
        RECT  68.448 63.916 68.472 64 ;
    END
  END b_wdata[60]
  PIN b_wdata[61]
    DIRECTION INPUT ;
    USE SIGNAL ;
    PORT
      LAYER M5 ;
        RECT  68.544 63.916 68.568 64 ;
    END
  END b_wdata[61]
  PIN b_wdata[62]
    DIRECTION INPUT ;
    USE SIGNAL ;
    PORT
      LAYER M5 ;
        RECT  68.64 63.916 68.664 64 ;
    END
  END b_wdata[62]
  PIN b_wdata[63]
    DIRECTION INPUT ;
    USE SIGNAL ;
    PORT
      LAYER M5 ;
        RECT  68.736 63.916 68.76 64 ;
    END
  END b_wdata[63]
  PIN b_wdata[64]
    DIRECTION INPUT ;
    USE SIGNAL ;
    PORT
      LAYER M5 ;
        RECT  68.832 63.916 68.856 64 ;
    END
  END b_wdata[64]
  PIN b_wdata[65]
    DIRECTION INPUT ;
    USE SIGNAL ;
    PORT
      LAYER M5 ;
        RECT  68.928 63.916 68.952 64 ;
    END
  END b_wdata[65]
  PIN b_wdata[66]
    DIRECTION INPUT ;
    USE SIGNAL ;
    PORT
      LAYER M5 ;
        RECT  69.024 63.916 69.048 64 ;
    END
  END b_wdata[66]
  PIN b_wdata[67]
    DIRECTION INPUT ;
    USE SIGNAL ;
    PORT
      LAYER M5 ;
        RECT  69.12 63.916 69.144 64 ;
    END
  END b_wdata[67]
  PIN b_wdata[68]
    DIRECTION INPUT ;
    USE SIGNAL ;
    PORT
      LAYER M5 ;
        RECT  69.216 63.916 69.24 64 ;
    END
  END b_wdata[68]
  PIN b_wdata[69]
    DIRECTION INPUT ;
    USE SIGNAL ;
    PORT
      LAYER M5 ;
        RECT  69.312 63.916 69.336 64 ;
    END
  END b_wdata[69]
  PIN b_wdata[6]
    DIRECTION INPUT ;
    USE SIGNAL ;
    PORT
      LAYER M5 ;
        RECT  63.264 63.916 63.288 64 ;
    END
  END b_wdata[6]
  PIN b_wdata[70]
    DIRECTION INPUT ;
    USE SIGNAL ;
    PORT
      LAYER M5 ;
        RECT  69.408 63.916 69.432 64 ;
    END
  END b_wdata[70]
  PIN b_wdata[71]
    DIRECTION INPUT ;
    USE SIGNAL ;
    PORT
      LAYER M5 ;
        RECT  69.504 63.916 69.528 64 ;
    END
  END b_wdata[71]
  PIN b_wdata[72]
    DIRECTION INPUT ;
    USE SIGNAL ;
    PORT
      LAYER M5 ;
        RECT  69.6 63.916 69.624 64 ;
    END
  END b_wdata[72]
  PIN b_wdata[73]
    DIRECTION INPUT ;
    USE SIGNAL ;
    PORT
      LAYER M5 ;
        RECT  69.696 63.916 69.72 64 ;
    END
  END b_wdata[73]
  PIN b_wdata[74]
    DIRECTION INPUT ;
    USE SIGNAL ;
    PORT
      LAYER M5 ;
        RECT  69.792 63.916 69.816 64 ;
    END
  END b_wdata[74]
  PIN b_wdata[75]
    DIRECTION INPUT ;
    USE SIGNAL ;
    PORT
      LAYER M5 ;
        RECT  69.888 63.916 69.912 64 ;
    END
  END b_wdata[75]
  PIN b_wdata[76]
    DIRECTION INPUT ;
    USE SIGNAL ;
    PORT
      LAYER M5 ;
        RECT  69.984 63.916 70.008 64 ;
    END
  END b_wdata[76]
  PIN b_wdata[77]
    DIRECTION INPUT ;
    USE SIGNAL ;
    PORT
      LAYER M5 ;
        RECT  70.08 63.916 70.104 64 ;
    END
  END b_wdata[77]
  PIN b_wdata[78]
    DIRECTION INPUT ;
    USE SIGNAL ;
    PORT
      LAYER M5 ;
        RECT  70.176 63.916 70.2 64 ;
    END
  END b_wdata[78]
  PIN b_wdata[79]
    DIRECTION INPUT ;
    USE SIGNAL ;
    PORT
      LAYER M5 ;
        RECT  70.272 63.916 70.296 64 ;
    END
  END b_wdata[79]
  PIN b_wdata[7]
    DIRECTION INPUT ;
    USE SIGNAL ;
    PORT
      LAYER M5 ;
        RECT  63.36 63.916 63.384 64 ;
    END
  END b_wdata[7]
  PIN b_wdata[80]
    DIRECTION INPUT ;
    USE SIGNAL ;
    PORT
      LAYER M5 ;
        RECT  70.368 63.916 70.392 64 ;
    END
  END b_wdata[80]
  PIN b_wdata[81]
    DIRECTION INPUT ;
    USE SIGNAL ;
    PORT
      LAYER M5 ;
        RECT  70.464 63.916 70.488 64 ;
    END
  END b_wdata[81]
  PIN b_wdata[82]
    DIRECTION INPUT ;
    USE SIGNAL ;
    PORT
      LAYER M5 ;
        RECT  70.56 63.916 70.584 64 ;
    END
  END b_wdata[82]
  PIN b_wdata[83]
    DIRECTION INPUT ;
    USE SIGNAL ;
    PORT
      LAYER M5 ;
        RECT  70.656 63.916 70.68 64 ;
    END
  END b_wdata[83]
  PIN b_wdata[84]
    DIRECTION INPUT ;
    USE SIGNAL ;
    PORT
      LAYER M5 ;
        RECT  70.752 63.916 70.776 64 ;
    END
  END b_wdata[84]
  PIN b_wdata[85]
    DIRECTION INPUT ;
    USE SIGNAL ;
    PORT
      LAYER M5 ;
        RECT  70.848 63.916 70.872 64 ;
    END
  END b_wdata[85]
  PIN b_wdata[86]
    DIRECTION INPUT ;
    USE SIGNAL ;
    PORT
      LAYER M5 ;
        RECT  70.944 63.916 70.968 64 ;
    END
  END b_wdata[86]
  PIN b_wdata[87]
    DIRECTION INPUT ;
    USE SIGNAL ;
    PORT
      LAYER M5 ;
        RECT  71.04 63.916 71.064 64 ;
    END
  END b_wdata[87]
  PIN b_wdata[88]
    DIRECTION INPUT ;
    USE SIGNAL ;
    PORT
      LAYER M5 ;
        RECT  71.136 63.916 71.16 64 ;
    END
  END b_wdata[88]
  PIN b_wdata[89]
    DIRECTION INPUT ;
    USE SIGNAL ;
    PORT
      LAYER M5 ;
        RECT  71.232 63.916 71.256 64 ;
    END
  END b_wdata[89]
  PIN b_wdata[8]
    DIRECTION INPUT ;
    USE SIGNAL ;
    PORT
      LAYER M5 ;
        RECT  63.456 63.916 63.48 64 ;
    END
  END b_wdata[8]
  PIN b_wdata[90]
    DIRECTION INPUT ;
    USE SIGNAL ;
    PORT
      LAYER M5 ;
        RECT  71.328 63.916 71.352 64 ;
    END
  END b_wdata[90]
  PIN b_wdata[91]
    DIRECTION INPUT ;
    USE SIGNAL ;
    PORT
      LAYER M5 ;
        RECT  71.424 63.916 71.448 64 ;
    END
  END b_wdata[91]
  PIN b_wdata[92]
    DIRECTION INPUT ;
    USE SIGNAL ;
    PORT
      LAYER M5 ;
        RECT  71.52 63.916 71.544 64 ;
    END
  END b_wdata[92]
  PIN b_wdata[93]
    DIRECTION INPUT ;
    USE SIGNAL ;
    PORT
      LAYER M5 ;
        RECT  71.616 63.916 71.64 64 ;
    END
  END b_wdata[93]
  PIN b_wdata[94]
    DIRECTION INPUT ;
    USE SIGNAL ;
    PORT
      LAYER M5 ;
        RECT  71.712 63.916 71.736 64 ;
    END
  END b_wdata[94]
  PIN b_wdata[95]
    DIRECTION INPUT ;
    USE SIGNAL ;
    PORT
      LAYER M5 ;
        RECT  71.808 63.916 71.832 64 ;
    END
  END b_wdata[95]
  PIN b_wdata[96]
    DIRECTION INPUT ;
    USE SIGNAL ;
    PORT
      LAYER M5 ;
        RECT  71.904 63.916 71.928 64 ;
    END
  END b_wdata[96]
  PIN b_wdata[97]
    DIRECTION INPUT ;
    USE SIGNAL ;
    PORT
      LAYER M5 ;
        RECT  72 63.916 72.024 64 ;
    END
  END b_wdata[97]
  PIN b_wdata[98]
    DIRECTION INPUT ;
    USE SIGNAL ;
    PORT
      LAYER M5 ;
        RECT  72.096 63.916 72.12 64 ;
    END
  END b_wdata[98]
  PIN b_wdata[99]
    DIRECTION INPUT ;
    USE SIGNAL ;
    PORT
      LAYER M5 ;
        RECT  72.192 63.916 72.216 64 ;
    END
  END b_wdata[99]
  PIN b_wdata[9]
    DIRECTION INPUT ;
    USE SIGNAL ;
    PORT
      LAYER M5 ;
        RECT  63.552 63.916 63.576 64 ;
    END
  END b_wdata[9]
  PIN b_we
    DIRECTION INPUT ;
    USE SIGNAL ;
    PORT
      LAYER M5 ;
        RECT  87.264 63.916 87.288 64 ;
    END
  END b_we
  PIN b_wr_done
    DIRECTION OUTPUT ;
    USE SIGNAL ;
    PORT
      LAYER M5 ;
        RECT  87.36 63.916 87.384 64 ;
    END
  END b_wr_done
  PIN b_wstrb[0]
    DIRECTION INPUT ;
    USE SIGNAL ;
    PORT
      LAYER M5 ;
        RECT  87.456 63.916 87.48 64 ;
    END
  END b_wstrb[0]
  PIN b_wstrb[10]
    DIRECTION INPUT ;
    USE SIGNAL ;
    PORT
      LAYER M5 ;
        RECT  88.416 63.916 88.44 64 ;
    END
  END b_wstrb[10]
  PIN b_wstrb[11]
    DIRECTION INPUT ;
    USE SIGNAL ;
    PORT
      LAYER M5 ;
        RECT  88.512 63.916 88.536 64 ;
    END
  END b_wstrb[11]
  PIN b_wstrb[12]
    DIRECTION INPUT ;
    USE SIGNAL ;
    PORT
      LAYER M5 ;
        RECT  88.608 63.916 88.632 64 ;
    END
  END b_wstrb[12]
  PIN b_wstrb[13]
    DIRECTION INPUT ;
    USE SIGNAL ;
    PORT
      LAYER M5 ;
        RECT  88.704 63.916 88.728 64 ;
    END
  END b_wstrb[13]
  PIN b_wstrb[14]
    DIRECTION INPUT ;
    USE SIGNAL ;
    PORT
      LAYER M5 ;
        RECT  88.8 63.916 88.824 64 ;
    END
  END b_wstrb[14]
  PIN b_wstrb[15]
    DIRECTION INPUT ;
    USE SIGNAL ;
    PORT
      LAYER M5 ;
        RECT  88.896 63.916 88.92 64 ;
    END
  END b_wstrb[15]
  PIN b_wstrb[16]
    DIRECTION INPUT ;
    USE SIGNAL ;
    PORT
      LAYER M5 ;
        RECT  88.992 63.916 89.016 64 ;
    END
  END b_wstrb[16]
  PIN b_wstrb[17]
    DIRECTION INPUT ;
    USE SIGNAL ;
    PORT
      LAYER M5 ;
        RECT  89.088 63.916 89.112 64 ;
    END
  END b_wstrb[17]
  PIN b_wstrb[18]
    DIRECTION INPUT ;
    USE SIGNAL ;
    PORT
      LAYER M5 ;
        RECT  89.184 63.916 89.208 64 ;
    END
  END b_wstrb[18]
  PIN b_wstrb[19]
    DIRECTION INPUT ;
    USE SIGNAL ;
    PORT
      LAYER M5 ;
        RECT  89.28 63.916 89.304 64 ;
    END
  END b_wstrb[19]
  PIN b_wstrb[1]
    DIRECTION INPUT ;
    USE SIGNAL ;
    PORT
      LAYER M5 ;
        RECT  87.552 63.916 87.576 64 ;
    END
  END b_wstrb[1]
  PIN b_wstrb[20]
    DIRECTION INPUT ;
    USE SIGNAL ;
    PORT
      LAYER M5 ;
        RECT  89.376 63.916 89.4 64 ;
    END
  END b_wstrb[20]
  PIN b_wstrb[21]
    DIRECTION INPUT ;
    USE SIGNAL ;
    PORT
      LAYER M5 ;
        RECT  89.472 63.916 89.496 64 ;
    END
  END b_wstrb[21]
  PIN b_wstrb[22]
    DIRECTION INPUT ;
    USE SIGNAL ;
    PORT
      LAYER M5 ;
        RECT  89.568 63.916 89.592 64 ;
    END
  END b_wstrb[22]
  PIN b_wstrb[23]
    DIRECTION INPUT ;
    USE SIGNAL ;
    PORT
      LAYER M5 ;
        RECT  89.664 63.916 89.688 64 ;
    END
  END b_wstrb[23]
  PIN b_wstrb[24]
    DIRECTION INPUT ;
    USE SIGNAL ;
    PORT
      LAYER M5 ;
        RECT  89.76 63.916 89.784 64 ;
    END
  END b_wstrb[24]
  PIN b_wstrb[25]
    DIRECTION INPUT ;
    USE SIGNAL ;
    PORT
      LAYER M5 ;
        RECT  89.856 63.916 89.88 64 ;
    END
  END b_wstrb[25]
  PIN b_wstrb[26]
    DIRECTION INPUT ;
    USE SIGNAL ;
    PORT
      LAYER M5 ;
        RECT  89.952 63.916 89.976 64 ;
    END
  END b_wstrb[26]
  PIN b_wstrb[27]
    DIRECTION INPUT ;
    USE SIGNAL ;
    PORT
      LAYER M5 ;
        RECT  90.048 63.916 90.072 64 ;
    END
  END b_wstrb[27]
  PIN b_wstrb[28]
    DIRECTION INPUT ;
    USE SIGNAL ;
    PORT
      LAYER M5 ;
        RECT  90.144 63.916 90.168 64 ;
    END
  END b_wstrb[28]
  PIN b_wstrb[29]
    DIRECTION INPUT ;
    USE SIGNAL ;
    PORT
      LAYER M5 ;
        RECT  90.24 63.916 90.264 64 ;
    END
  END b_wstrb[29]
  PIN b_wstrb[2]
    DIRECTION INPUT ;
    USE SIGNAL ;
    PORT
      LAYER M5 ;
        RECT  87.648 63.916 87.672 64 ;
    END
  END b_wstrb[2]
  PIN b_wstrb[30]
    DIRECTION INPUT ;
    USE SIGNAL ;
    PORT
      LAYER M5 ;
        RECT  90.336 63.916 90.36 64 ;
    END
  END b_wstrb[30]
  PIN b_wstrb[31]
    DIRECTION INPUT ;
    USE SIGNAL ;
    PORT
      LAYER M5 ;
        RECT  90.432 63.916 90.456 64 ;
    END
  END b_wstrb[31]
  PIN b_wstrb[3]
    DIRECTION INPUT ;
    USE SIGNAL ;
    PORT
      LAYER M5 ;
        RECT  87.744 63.916 87.768 64 ;
    END
  END b_wstrb[3]
  PIN b_wstrb[4]
    DIRECTION INPUT ;
    USE SIGNAL ;
    PORT
      LAYER M5 ;
        RECT  87.84 63.916 87.864 64 ;
    END
  END b_wstrb[4]
  PIN b_wstrb[5]
    DIRECTION INPUT ;
    USE SIGNAL ;
    PORT
      LAYER M5 ;
        RECT  87.936 63.916 87.96 64 ;
    END
  END b_wstrb[5]
  PIN b_wstrb[6]
    DIRECTION INPUT ;
    USE SIGNAL ;
    PORT
      LAYER M5 ;
        RECT  88.032 63.916 88.056 64 ;
    END
  END b_wstrb[6]
  PIN b_wstrb[7]
    DIRECTION INPUT ;
    USE SIGNAL ;
    PORT
      LAYER M5 ;
        RECT  88.128 63.916 88.152 64 ;
    END
  END b_wstrb[7]
  PIN b_wstrb[8]
    DIRECTION INPUT ;
    USE SIGNAL ;
    PORT
      LAYER M5 ;
        RECT  88.224 63.916 88.248 64 ;
    END
  END b_wstrb[8]
  PIN b_wstrb[9]
    DIRECTION INPUT ;
    USE SIGNAL ;
    PORT
      LAYER M5 ;
        RECT  88.32 63.916 88.344 64 ;
    END
  END b_wstrb[9]
  PIN clk
    DIRECTION INPUT ;
    USE SIGNAL ;
    PORT
      LAYER M5 ;
        RECT  163.872 63.916 163.896 64 ;
    END
  END clk
  PIN contend
    DIRECTION OUTPUT ;
    USE SIGNAL ;
    PORT
      LAYER M5 ;
        RECT  163.968 63.916 163.992 64 ;
    END
  END contend
  PIN h_addr[0]
    DIRECTION OUTPUT ;
    USE SIGNAL ;
    PORT
      LAYER M5 ;
        RECT  30.72 0 30.744 0.084 ;
    END
  END h_addr[0]
  PIN h_addr[10]
    DIRECTION OUTPUT ;
    USE SIGNAL ;
    PORT
      LAYER M5 ;
        RECT  31.68 0 31.704 0.084 ;
    END
  END h_addr[10]
  PIN h_addr[11]
    DIRECTION OUTPUT ;
    USE SIGNAL ;
    PORT
      LAYER M5 ;
        RECT  31.776 0 31.8 0.084 ;
    END
  END h_addr[11]
  PIN h_addr[12]
    DIRECTION OUTPUT ;
    USE SIGNAL ;
    PORT
      LAYER M5 ;
        RECT  31.872 0 31.896 0.084 ;
    END
  END h_addr[12]
  PIN h_addr[13]
    DIRECTION OUTPUT ;
    USE SIGNAL ;
    PORT
      LAYER M5 ;
        RECT  31.968 0 31.992 0.084 ;
    END
  END h_addr[13]
  PIN h_addr[14]
    DIRECTION OUTPUT ;
    USE SIGNAL ;
    PORT
      LAYER M5 ;
        RECT  32.064 0 32.088 0.084 ;
    END
  END h_addr[14]
  PIN h_addr[15]
    DIRECTION OUTPUT ;
    USE SIGNAL ;
    PORT
      LAYER M5 ;
        RECT  32.16 0 32.184 0.084 ;
    END
  END h_addr[15]
  PIN h_addr[16]
    DIRECTION OUTPUT ;
    USE SIGNAL ;
    PORT
      LAYER M5 ;
        RECT  32.256 0 32.28 0.084 ;
    END
  END h_addr[16]
  PIN h_addr[17]
    DIRECTION OUTPUT ;
    USE SIGNAL ;
    PORT
      LAYER M5 ;
        RECT  32.352 0 32.376 0.084 ;
    END
  END h_addr[17]
  PIN h_addr[18]
    DIRECTION OUTPUT ;
    USE SIGNAL ;
    PORT
      LAYER M5 ;
        RECT  32.448 0 32.472 0.084 ;
    END
  END h_addr[18]
  PIN h_addr[19]
    DIRECTION OUTPUT ;
    USE SIGNAL ;
    PORT
      LAYER M5 ;
        RECT  32.544 0 32.568 0.084 ;
    END
  END h_addr[19]
  PIN h_addr[1]
    DIRECTION OUTPUT ;
    USE SIGNAL ;
    PORT
      LAYER M5 ;
        RECT  30.816 0 30.84 0.084 ;
    END
  END h_addr[1]
  PIN h_addr[20]
    DIRECTION OUTPUT ;
    USE SIGNAL ;
    PORT
      LAYER M5 ;
        RECT  32.64 0 32.664 0.084 ;
    END
  END h_addr[20]
  PIN h_addr[21]
    DIRECTION OUTPUT ;
    USE SIGNAL ;
    PORT
      LAYER M5 ;
        RECT  32.736 0 32.76 0.084 ;
    END
  END h_addr[21]
  PIN h_addr[22]
    DIRECTION OUTPUT ;
    USE SIGNAL ;
    PORT
      LAYER M5 ;
        RECT  32.832 0 32.856 0.084 ;
    END
  END h_addr[22]
  PIN h_addr[23]
    DIRECTION OUTPUT ;
    USE SIGNAL ;
    PORT
      LAYER M5 ;
        RECT  32.928 0 32.952 0.084 ;
    END
  END h_addr[23]
  PIN h_addr[24]
    DIRECTION OUTPUT ;
    USE SIGNAL ;
    PORT
      LAYER M5 ;
        RECT  33.024 0 33.048 0.084 ;
    END
  END h_addr[24]
  PIN h_addr[25]
    DIRECTION OUTPUT ;
    USE SIGNAL ;
    PORT
      LAYER M5 ;
        RECT  33.12 0 33.144 0.084 ;
    END
  END h_addr[25]
  PIN h_addr[26]
    DIRECTION OUTPUT ;
    USE SIGNAL ;
    PORT
      LAYER M5 ;
        RECT  33.216 0 33.24 0.084 ;
    END
  END h_addr[26]
  PIN h_addr[27]
    DIRECTION OUTPUT ;
    USE SIGNAL ;
    PORT
      LAYER M5 ;
        RECT  33.312 0 33.336 0.084 ;
    END
  END h_addr[27]
  PIN h_addr[28]
    DIRECTION OUTPUT ;
    USE SIGNAL ;
    PORT
      LAYER M5 ;
        RECT  33.408 0 33.432 0.084 ;
    END
  END h_addr[28]
  PIN h_addr[29]
    DIRECTION OUTPUT ;
    USE SIGNAL ;
    PORT
      LAYER M5 ;
        RECT  33.504 0 33.528 0.084 ;
    END
  END h_addr[29]
  PIN h_addr[2]
    DIRECTION OUTPUT ;
    USE SIGNAL ;
    PORT
      LAYER M5 ;
        RECT  30.912 0 30.936 0.084 ;
    END
  END h_addr[2]
  PIN h_addr[3]
    DIRECTION OUTPUT ;
    USE SIGNAL ;
    PORT
      LAYER M5 ;
        RECT  31.008 0 31.032 0.084 ;
    END
  END h_addr[3]
  PIN h_addr[4]
    DIRECTION OUTPUT ;
    USE SIGNAL ;
    PORT
      LAYER M5 ;
        RECT  31.104 0 31.128 0.084 ;
    END
  END h_addr[4]
  PIN h_addr[5]
    DIRECTION OUTPUT ;
    USE SIGNAL ;
    PORT
      LAYER M5 ;
        RECT  31.2 0 31.224 0.084 ;
    END
  END h_addr[5]
  PIN h_addr[6]
    DIRECTION OUTPUT ;
    USE SIGNAL ;
    PORT
      LAYER M5 ;
        RECT  31.296 0 31.32 0.084 ;
    END
  END h_addr[6]
  PIN h_addr[7]
    DIRECTION OUTPUT ;
    USE SIGNAL ;
    PORT
      LAYER M5 ;
        RECT  31.392 0 31.416 0.084 ;
    END
  END h_addr[7]
  PIN h_addr[8]
    DIRECTION OUTPUT ;
    USE SIGNAL ;
    PORT
      LAYER M5 ;
        RECT  31.488 0 31.512 0.084 ;
    END
  END h_addr[8]
  PIN h_addr[9]
    DIRECTION OUTPUT ;
    USE SIGNAL ;
    PORT
      LAYER M5 ;
        RECT  31.584 0 31.608 0.084 ;
    END
  END h_addr[9]
  PIN h_len[0]
    DIRECTION OUTPUT ;
    USE SIGNAL ;
    PORT
      LAYER M5 ;
        RECT  33.6 0 33.624 0.084 ;
    END
  END h_len[0]
  PIN h_len[1]
    DIRECTION OUTPUT ;
    USE SIGNAL ;
    PORT
      LAYER M5 ;
        RECT  33.696 0 33.72 0.084 ;
    END
  END h_len[1]
  PIN h_len[2]
    DIRECTION OUTPUT ;
    USE SIGNAL ;
    PORT
      LAYER M5 ;
        RECT  33.792 0 33.816 0.084 ;
    END
  END h_len[2]
  PIN h_len[3]
    DIRECTION OUTPUT ;
    USE SIGNAL ;
    PORT
      LAYER M5 ;
        RECT  33.888 0 33.912 0.084 ;
    END
  END h_len[3]
  PIN h_rdy
    DIRECTION INPUT ;
    USE SIGNAL ;
    PORT
      LAYER M5 ;
        RECT  33.984 0 34.008 0.084 ;
    END
  END h_rdy
  PIN h_tag[0]
    DIRECTION OUTPUT ;
    USE SIGNAL ;
    PORT
      LAYER M5 ;
        RECT  34.08 0 34.104 0.084 ;
    END
  END h_tag[0]
  PIN h_tag[10]
    DIRECTION OUTPUT ;
    USE SIGNAL ;
    PORT
      LAYER M5 ;
        RECT  35.04 0 35.064 0.084 ;
    END
  END h_tag[10]
  PIN h_tag[11]
    DIRECTION OUTPUT ;
    USE SIGNAL ;
    PORT
      LAYER M5 ;
        RECT  35.136 0 35.16 0.084 ;
    END
  END h_tag[11]
  PIN h_tag[12]
    DIRECTION OUTPUT ;
    USE SIGNAL ;
    PORT
      LAYER M5 ;
        RECT  35.232 0 35.256 0.084 ;
    END
  END h_tag[12]
  PIN h_tag[13]
    DIRECTION OUTPUT ;
    USE SIGNAL ;
    PORT
      LAYER M5 ;
        RECT  35.328 0 35.352 0.084 ;
    END
  END h_tag[13]
  PIN h_tag[14]
    DIRECTION OUTPUT ;
    USE SIGNAL ;
    PORT
      LAYER M5 ;
        RECT  35.424 0 35.448 0.084 ;
    END
  END h_tag[14]
  PIN h_tag[15]
    DIRECTION OUTPUT ;
    USE SIGNAL ;
    PORT
      LAYER M5 ;
        RECT  35.52 0 35.544 0.084 ;
    END
  END h_tag[15]
  PIN h_tag[16]
    DIRECTION OUTPUT ;
    USE SIGNAL ;
    PORT
      LAYER M5 ;
        RECT  35.616 0 35.64 0.084 ;
    END
  END h_tag[16]
  PIN h_tag[1]
    DIRECTION OUTPUT ;
    USE SIGNAL ;
    PORT
      LAYER M5 ;
        RECT  34.176 0 34.2 0.084 ;
    END
  END h_tag[1]
  PIN h_tag[2]
    DIRECTION OUTPUT ;
    USE SIGNAL ;
    PORT
      LAYER M5 ;
        RECT  34.272 0 34.296 0.084 ;
    END
  END h_tag[2]
  PIN h_tag[3]
    DIRECTION OUTPUT ;
    USE SIGNAL ;
    PORT
      LAYER M5 ;
        RECT  34.368 0 34.392 0.084 ;
    END
  END h_tag[3]
  PIN h_tag[4]
    DIRECTION OUTPUT ;
    USE SIGNAL ;
    PORT
      LAYER M5 ;
        RECT  34.464 0 34.488 0.084 ;
    END
  END h_tag[4]
  PIN h_tag[5]
    DIRECTION OUTPUT ;
    USE SIGNAL ;
    PORT
      LAYER M5 ;
        RECT  34.56 0 34.584 0.084 ;
    END
  END h_tag[5]
  PIN h_tag[6]
    DIRECTION OUTPUT ;
    USE SIGNAL ;
    PORT
      LAYER M5 ;
        RECT  34.656 0 34.68 0.084 ;
    END
  END h_tag[6]
  PIN h_tag[7]
    DIRECTION OUTPUT ;
    USE SIGNAL ;
    PORT
      LAYER M5 ;
        RECT  34.752 0 34.776 0.084 ;
    END
  END h_tag[7]
  PIN h_tag[8]
    DIRECTION OUTPUT ;
    USE SIGNAL ;
    PORT
      LAYER M5 ;
        RECT  34.848 0 34.872 0.084 ;
    END
  END h_tag[8]
  PIN h_tag[9]
    DIRECTION OUTPUT ;
    USE SIGNAL ;
    PORT
      LAYER M5 ;
        RECT  34.944 0 34.968 0.084 ;
    END
  END h_tag[9]
  PIN h_v
    DIRECTION OUTPUT ;
    USE SIGNAL ;
    PORT
      LAYER M5 ;
        RECT  35.712 0 35.736 0.084 ;
    END
  END h_v
  PIN h_wdata[0]
    DIRECTION OUTPUT ;
    USE SIGNAL ;
    PORT
      LAYER M5 ;
        RECT  35.808 0 35.832 0.084 ;
    END
  END h_wdata[0]
  PIN h_wdata[100]
    DIRECTION OUTPUT ;
    USE SIGNAL ;
    PORT
      LAYER M5 ;
        RECT  45.408 0 45.432 0.084 ;
    END
  END h_wdata[100]
  PIN h_wdata[101]
    DIRECTION OUTPUT ;
    USE SIGNAL ;
    PORT
      LAYER M5 ;
        RECT  45.504 0 45.528 0.084 ;
    END
  END h_wdata[101]
  PIN h_wdata[102]
    DIRECTION OUTPUT ;
    USE SIGNAL ;
    PORT
      LAYER M5 ;
        RECT  45.6 0 45.624 0.084 ;
    END
  END h_wdata[102]
  PIN h_wdata[103]
    DIRECTION OUTPUT ;
    USE SIGNAL ;
    PORT
      LAYER M5 ;
        RECT  45.696 0 45.72 0.084 ;
    END
  END h_wdata[103]
  PIN h_wdata[104]
    DIRECTION OUTPUT ;
    USE SIGNAL ;
    PORT
      LAYER M5 ;
        RECT  45.792 0 45.816 0.084 ;
    END
  END h_wdata[104]
  PIN h_wdata[105]
    DIRECTION OUTPUT ;
    USE SIGNAL ;
    PORT
      LAYER M5 ;
        RECT  45.888 0 45.912 0.084 ;
    END
  END h_wdata[105]
  PIN h_wdata[106]
    DIRECTION OUTPUT ;
    USE SIGNAL ;
    PORT
      LAYER M5 ;
        RECT  45.984 0 46.008 0.084 ;
    END
  END h_wdata[106]
  PIN h_wdata[107]
    DIRECTION OUTPUT ;
    USE SIGNAL ;
    PORT
      LAYER M5 ;
        RECT  46.08 0 46.104 0.084 ;
    END
  END h_wdata[107]
  PIN h_wdata[108]
    DIRECTION OUTPUT ;
    USE SIGNAL ;
    PORT
      LAYER M5 ;
        RECT  46.176 0 46.2 0.084 ;
    END
  END h_wdata[108]
  PIN h_wdata[109]
    DIRECTION OUTPUT ;
    USE SIGNAL ;
    PORT
      LAYER M5 ;
        RECT  46.272 0 46.296 0.084 ;
    END
  END h_wdata[109]
  PIN h_wdata[10]
    DIRECTION OUTPUT ;
    USE SIGNAL ;
    PORT
      LAYER M5 ;
        RECT  36.768 0 36.792 0.084 ;
    END
  END h_wdata[10]
  PIN h_wdata[110]
    DIRECTION OUTPUT ;
    USE SIGNAL ;
    PORT
      LAYER M5 ;
        RECT  46.368 0 46.392 0.084 ;
    END
  END h_wdata[110]
  PIN h_wdata[111]
    DIRECTION OUTPUT ;
    USE SIGNAL ;
    PORT
      LAYER M5 ;
        RECT  46.464 0 46.488 0.084 ;
    END
  END h_wdata[111]
  PIN h_wdata[112]
    DIRECTION OUTPUT ;
    USE SIGNAL ;
    PORT
      LAYER M5 ;
        RECT  46.56 0 46.584 0.084 ;
    END
  END h_wdata[112]
  PIN h_wdata[113]
    DIRECTION OUTPUT ;
    USE SIGNAL ;
    PORT
      LAYER M5 ;
        RECT  46.656 0 46.68 0.084 ;
    END
  END h_wdata[113]
  PIN h_wdata[114]
    DIRECTION OUTPUT ;
    USE SIGNAL ;
    PORT
      LAYER M5 ;
        RECT  46.752 0 46.776 0.084 ;
    END
  END h_wdata[114]
  PIN h_wdata[115]
    DIRECTION OUTPUT ;
    USE SIGNAL ;
    PORT
      LAYER M5 ;
        RECT  46.848 0 46.872 0.084 ;
    END
  END h_wdata[115]
  PIN h_wdata[116]
    DIRECTION OUTPUT ;
    USE SIGNAL ;
    PORT
      LAYER M5 ;
        RECT  46.944 0 46.968 0.084 ;
    END
  END h_wdata[116]
  PIN h_wdata[117]
    DIRECTION OUTPUT ;
    USE SIGNAL ;
    PORT
      LAYER M5 ;
        RECT  47.04 0 47.064 0.084 ;
    END
  END h_wdata[117]
  PIN h_wdata[118]
    DIRECTION OUTPUT ;
    USE SIGNAL ;
    PORT
      LAYER M5 ;
        RECT  47.136 0 47.16 0.084 ;
    END
  END h_wdata[118]
  PIN h_wdata[119]
    DIRECTION OUTPUT ;
    USE SIGNAL ;
    PORT
      LAYER M5 ;
        RECT  47.232 0 47.256 0.084 ;
    END
  END h_wdata[119]
  PIN h_wdata[11]
    DIRECTION OUTPUT ;
    USE SIGNAL ;
    PORT
      LAYER M5 ;
        RECT  36.864 0 36.888 0.084 ;
    END
  END h_wdata[11]
  PIN h_wdata[120]
    DIRECTION OUTPUT ;
    USE SIGNAL ;
    PORT
      LAYER M5 ;
        RECT  47.328 0 47.352 0.084 ;
    END
  END h_wdata[120]
  PIN h_wdata[121]
    DIRECTION OUTPUT ;
    USE SIGNAL ;
    PORT
      LAYER M5 ;
        RECT  47.424 0 47.448 0.084 ;
    END
  END h_wdata[121]
  PIN h_wdata[122]
    DIRECTION OUTPUT ;
    USE SIGNAL ;
    PORT
      LAYER M5 ;
        RECT  47.52 0 47.544 0.084 ;
    END
  END h_wdata[122]
  PIN h_wdata[123]
    DIRECTION OUTPUT ;
    USE SIGNAL ;
    PORT
      LAYER M5 ;
        RECT  47.616 0 47.64 0.084 ;
    END
  END h_wdata[123]
  PIN h_wdata[124]
    DIRECTION OUTPUT ;
    USE SIGNAL ;
    PORT
      LAYER M5 ;
        RECT  47.712 0 47.736 0.084 ;
    END
  END h_wdata[124]
  PIN h_wdata[125]
    DIRECTION OUTPUT ;
    USE SIGNAL ;
    PORT
      LAYER M5 ;
        RECT  47.808 0 47.832 0.084 ;
    END
  END h_wdata[125]
  PIN h_wdata[126]
    DIRECTION OUTPUT ;
    USE SIGNAL ;
    PORT
      LAYER M5 ;
        RECT  47.904 0 47.928 0.084 ;
    END
  END h_wdata[126]
  PIN h_wdata[127]
    DIRECTION OUTPUT ;
    USE SIGNAL ;
    PORT
      LAYER M5 ;
        RECT  48 0 48.024 0.084 ;
    END
  END h_wdata[127]
  PIN h_wdata[128]
    DIRECTION OUTPUT ;
    USE SIGNAL ;
    PORT
      LAYER M5 ;
        RECT  48.096 0 48.12 0.084 ;
    END
  END h_wdata[128]
  PIN h_wdata[129]
    DIRECTION OUTPUT ;
    USE SIGNAL ;
    PORT
      LAYER M5 ;
        RECT  48.192 0 48.216 0.084 ;
    END
  END h_wdata[129]
  PIN h_wdata[12]
    DIRECTION OUTPUT ;
    USE SIGNAL ;
    PORT
      LAYER M5 ;
        RECT  36.96 0 36.984 0.084 ;
    END
  END h_wdata[12]
  PIN h_wdata[130]
    DIRECTION OUTPUT ;
    USE SIGNAL ;
    PORT
      LAYER M5 ;
        RECT  48.288 0 48.312 0.084 ;
    END
  END h_wdata[130]
  PIN h_wdata[131]
    DIRECTION OUTPUT ;
    USE SIGNAL ;
    PORT
      LAYER M5 ;
        RECT  48.384 0 48.408 0.084 ;
    END
  END h_wdata[131]
  PIN h_wdata[132]
    DIRECTION OUTPUT ;
    USE SIGNAL ;
    PORT
      LAYER M5 ;
        RECT  48.48 0 48.504 0.084 ;
    END
  END h_wdata[132]
  PIN h_wdata[133]
    DIRECTION OUTPUT ;
    USE SIGNAL ;
    PORT
      LAYER M5 ;
        RECT  48.576 0 48.6 0.084 ;
    END
  END h_wdata[133]
  PIN h_wdata[134]
    DIRECTION OUTPUT ;
    USE SIGNAL ;
    PORT
      LAYER M5 ;
        RECT  48.672 0 48.696 0.084 ;
    END
  END h_wdata[134]
  PIN h_wdata[135]
    DIRECTION OUTPUT ;
    USE SIGNAL ;
    PORT
      LAYER M5 ;
        RECT  48.768 0 48.792 0.084 ;
    END
  END h_wdata[135]
  PIN h_wdata[136]
    DIRECTION OUTPUT ;
    USE SIGNAL ;
    PORT
      LAYER M5 ;
        RECT  48.864 0 48.888 0.084 ;
    END
  END h_wdata[136]
  PIN h_wdata[137]
    DIRECTION OUTPUT ;
    USE SIGNAL ;
    PORT
      LAYER M5 ;
        RECT  48.96 0 48.984 0.084 ;
    END
  END h_wdata[137]
  PIN h_wdata[138]
    DIRECTION OUTPUT ;
    USE SIGNAL ;
    PORT
      LAYER M5 ;
        RECT  49.056 0 49.08 0.084 ;
    END
  END h_wdata[138]
  PIN h_wdata[139]
    DIRECTION OUTPUT ;
    USE SIGNAL ;
    PORT
      LAYER M5 ;
        RECT  49.152 0 49.176 0.084 ;
    END
  END h_wdata[139]
  PIN h_wdata[13]
    DIRECTION OUTPUT ;
    USE SIGNAL ;
    PORT
      LAYER M5 ;
        RECT  37.056 0 37.08 0.084 ;
    END
  END h_wdata[13]
  PIN h_wdata[140]
    DIRECTION OUTPUT ;
    USE SIGNAL ;
    PORT
      LAYER M5 ;
        RECT  49.248 0 49.272 0.084 ;
    END
  END h_wdata[140]
  PIN h_wdata[141]
    DIRECTION OUTPUT ;
    USE SIGNAL ;
    PORT
      LAYER M5 ;
        RECT  49.344 0 49.368 0.084 ;
    END
  END h_wdata[141]
  PIN h_wdata[142]
    DIRECTION OUTPUT ;
    USE SIGNAL ;
    PORT
      LAYER M5 ;
        RECT  49.44 0 49.464 0.084 ;
    END
  END h_wdata[142]
  PIN h_wdata[143]
    DIRECTION OUTPUT ;
    USE SIGNAL ;
    PORT
      LAYER M5 ;
        RECT  49.536 0 49.56 0.084 ;
    END
  END h_wdata[143]
  PIN h_wdata[144]
    DIRECTION OUTPUT ;
    USE SIGNAL ;
    PORT
      LAYER M5 ;
        RECT  49.632 0 49.656 0.084 ;
    END
  END h_wdata[144]
  PIN h_wdata[145]
    DIRECTION OUTPUT ;
    USE SIGNAL ;
    PORT
      LAYER M5 ;
        RECT  49.728 0 49.752 0.084 ;
    END
  END h_wdata[145]
  PIN h_wdata[146]
    DIRECTION OUTPUT ;
    USE SIGNAL ;
    PORT
      LAYER M5 ;
        RECT  49.824 0 49.848 0.084 ;
    END
  END h_wdata[146]
  PIN h_wdata[147]
    DIRECTION OUTPUT ;
    USE SIGNAL ;
    PORT
      LAYER M5 ;
        RECT  49.92 0 49.944 0.084 ;
    END
  END h_wdata[147]
  PIN h_wdata[148]
    DIRECTION OUTPUT ;
    USE SIGNAL ;
    PORT
      LAYER M5 ;
        RECT  50.016 0 50.04 0.084 ;
    END
  END h_wdata[148]
  PIN h_wdata[149]
    DIRECTION OUTPUT ;
    USE SIGNAL ;
    PORT
      LAYER M5 ;
        RECT  50.112 0 50.136 0.084 ;
    END
  END h_wdata[149]
  PIN h_wdata[14]
    DIRECTION OUTPUT ;
    USE SIGNAL ;
    PORT
      LAYER M5 ;
        RECT  37.152 0 37.176 0.084 ;
    END
  END h_wdata[14]
  PIN h_wdata[150]
    DIRECTION OUTPUT ;
    USE SIGNAL ;
    PORT
      LAYER M5 ;
        RECT  50.208 0 50.232 0.084 ;
    END
  END h_wdata[150]
  PIN h_wdata[151]
    DIRECTION OUTPUT ;
    USE SIGNAL ;
    PORT
      LAYER M5 ;
        RECT  50.304 0 50.328 0.084 ;
    END
  END h_wdata[151]
  PIN h_wdata[152]
    DIRECTION OUTPUT ;
    USE SIGNAL ;
    PORT
      LAYER M5 ;
        RECT  50.4 0 50.424 0.084 ;
    END
  END h_wdata[152]
  PIN h_wdata[153]
    DIRECTION OUTPUT ;
    USE SIGNAL ;
    PORT
      LAYER M5 ;
        RECT  50.496 0 50.52 0.084 ;
    END
  END h_wdata[153]
  PIN h_wdata[154]
    DIRECTION OUTPUT ;
    USE SIGNAL ;
    PORT
      LAYER M5 ;
        RECT  50.592 0 50.616 0.084 ;
    END
  END h_wdata[154]
  PIN h_wdata[155]
    DIRECTION OUTPUT ;
    USE SIGNAL ;
    PORT
      LAYER M5 ;
        RECT  50.688 0 50.712 0.084 ;
    END
  END h_wdata[155]
  PIN h_wdata[156]
    DIRECTION OUTPUT ;
    USE SIGNAL ;
    PORT
      LAYER M5 ;
        RECT  50.784 0 50.808 0.084 ;
    END
  END h_wdata[156]
  PIN h_wdata[157]
    DIRECTION OUTPUT ;
    USE SIGNAL ;
    PORT
      LAYER M5 ;
        RECT  50.88 0 50.904 0.084 ;
    END
  END h_wdata[157]
  PIN h_wdata[158]
    DIRECTION OUTPUT ;
    USE SIGNAL ;
    PORT
      LAYER M5 ;
        RECT  50.976 0 51 0.084 ;
    END
  END h_wdata[158]
  PIN h_wdata[159]
    DIRECTION OUTPUT ;
    USE SIGNAL ;
    PORT
      LAYER M5 ;
        RECT  51.072 0 51.096 0.084 ;
    END
  END h_wdata[159]
  PIN h_wdata[15]
    DIRECTION OUTPUT ;
    USE SIGNAL ;
    PORT
      LAYER M5 ;
        RECT  37.248 0 37.272 0.084 ;
    END
  END h_wdata[15]
  PIN h_wdata[160]
    DIRECTION OUTPUT ;
    USE SIGNAL ;
    PORT
      LAYER M5 ;
        RECT  51.168 0 51.192 0.084 ;
    END
  END h_wdata[160]
  PIN h_wdata[161]
    DIRECTION OUTPUT ;
    USE SIGNAL ;
    PORT
      LAYER M5 ;
        RECT  51.264 0 51.288 0.084 ;
    END
  END h_wdata[161]
  PIN h_wdata[162]
    DIRECTION OUTPUT ;
    USE SIGNAL ;
    PORT
      LAYER M5 ;
        RECT  51.36 0 51.384 0.084 ;
    END
  END h_wdata[162]
  PIN h_wdata[163]
    DIRECTION OUTPUT ;
    USE SIGNAL ;
    PORT
      LAYER M5 ;
        RECT  51.456 0 51.48 0.084 ;
    END
  END h_wdata[163]
  PIN h_wdata[164]
    DIRECTION OUTPUT ;
    USE SIGNAL ;
    PORT
      LAYER M5 ;
        RECT  51.552 0 51.576 0.084 ;
    END
  END h_wdata[164]
  PIN h_wdata[165]
    DIRECTION OUTPUT ;
    USE SIGNAL ;
    PORT
      LAYER M5 ;
        RECT  51.648 0 51.672 0.084 ;
    END
  END h_wdata[165]
  PIN h_wdata[166]
    DIRECTION OUTPUT ;
    USE SIGNAL ;
    PORT
      LAYER M5 ;
        RECT  51.744 0 51.768 0.084 ;
    END
  END h_wdata[166]
  PIN h_wdata[167]
    DIRECTION OUTPUT ;
    USE SIGNAL ;
    PORT
      LAYER M5 ;
        RECT  51.84 0 51.864 0.084 ;
    END
  END h_wdata[167]
  PIN h_wdata[168]
    DIRECTION OUTPUT ;
    USE SIGNAL ;
    PORT
      LAYER M5 ;
        RECT  51.936 0 51.96 0.084 ;
    END
  END h_wdata[168]
  PIN h_wdata[169]
    DIRECTION OUTPUT ;
    USE SIGNAL ;
    PORT
      LAYER M5 ;
        RECT  52.032 0 52.056 0.084 ;
    END
  END h_wdata[169]
  PIN h_wdata[16]
    DIRECTION OUTPUT ;
    USE SIGNAL ;
    PORT
      LAYER M5 ;
        RECT  37.344 0 37.368 0.084 ;
    END
  END h_wdata[16]
  PIN h_wdata[170]
    DIRECTION OUTPUT ;
    USE SIGNAL ;
    PORT
      LAYER M5 ;
        RECT  52.128 0 52.152 0.084 ;
    END
  END h_wdata[170]
  PIN h_wdata[171]
    DIRECTION OUTPUT ;
    USE SIGNAL ;
    PORT
      LAYER M5 ;
        RECT  52.224 0 52.248 0.084 ;
    END
  END h_wdata[171]
  PIN h_wdata[172]
    DIRECTION OUTPUT ;
    USE SIGNAL ;
    PORT
      LAYER M5 ;
        RECT  52.32 0 52.344 0.084 ;
    END
  END h_wdata[172]
  PIN h_wdata[173]
    DIRECTION OUTPUT ;
    USE SIGNAL ;
    PORT
      LAYER M5 ;
        RECT  52.416 0 52.44 0.084 ;
    END
  END h_wdata[173]
  PIN h_wdata[174]
    DIRECTION OUTPUT ;
    USE SIGNAL ;
    PORT
      LAYER M5 ;
        RECT  52.512 0 52.536 0.084 ;
    END
  END h_wdata[174]
  PIN h_wdata[175]
    DIRECTION OUTPUT ;
    USE SIGNAL ;
    PORT
      LAYER M5 ;
        RECT  52.608 0 52.632 0.084 ;
    END
  END h_wdata[175]
  PIN h_wdata[176]
    DIRECTION OUTPUT ;
    USE SIGNAL ;
    PORT
      LAYER M5 ;
        RECT  52.704 0 52.728 0.084 ;
    END
  END h_wdata[176]
  PIN h_wdata[177]
    DIRECTION OUTPUT ;
    USE SIGNAL ;
    PORT
      LAYER M5 ;
        RECT  52.8 0 52.824 0.084 ;
    END
  END h_wdata[177]
  PIN h_wdata[178]
    DIRECTION OUTPUT ;
    USE SIGNAL ;
    PORT
      LAYER M5 ;
        RECT  52.896 0 52.92 0.084 ;
    END
  END h_wdata[178]
  PIN h_wdata[179]
    DIRECTION OUTPUT ;
    USE SIGNAL ;
    PORT
      LAYER M5 ;
        RECT  52.992 0 53.016 0.084 ;
    END
  END h_wdata[179]
  PIN h_wdata[17]
    DIRECTION OUTPUT ;
    USE SIGNAL ;
    PORT
      LAYER M5 ;
        RECT  37.44 0 37.464 0.084 ;
    END
  END h_wdata[17]
  PIN h_wdata[180]
    DIRECTION OUTPUT ;
    USE SIGNAL ;
    PORT
      LAYER M5 ;
        RECT  53.088 0 53.112 0.084 ;
    END
  END h_wdata[180]
  PIN h_wdata[181]
    DIRECTION OUTPUT ;
    USE SIGNAL ;
    PORT
      LAYER M5 ;
        RECT  53.184 0 53.208 0.084 ;
    END
  END h_wdata[181]
  PIN h_wdata[182]
    DIRECTION OUTPUT ;
    USE SIGNAL ;
    PORT
      LAYER M5 ;
        RECT  53.28 0 53.304 0.084 ;
    END
  END h_wdata[182]
  PIN h_wdata[183]
    DIRECTION OUTPUT ;
    USE SIGNAL ;
    PORT
      LAYER M5 ;
        RECT  53.376 0 53.4 0.084 ;
    END
  END h_wdata[183]
  PIN h_wdata[184]
    DIRECTION OUTPUT ;
    USE SIGNAL ;
    PORT
      LAYER M5 ;
        RECT  53.472 0 53.496 0.084 ;
    END
  END h_wdata[184]
  PIN h_wdata[185]
    DIRECTION OUTPUT ;
    USE SIGNAL ;
    PORT
      LAYER M5 ;
        RECT  53.568 0 53.592 0.084 ;
    END
  END h_wdata[185]
  PIN h_wdata[186]
    DIRECTION OUTPUT ;
    USE SIGNAL ;
    PORT
      LAYER M5 ;
        RECT  53.664 0 53.688 0.084 ;
    END
  END h_wdata[186]
  PIN h_wdata[187]
    DIRECTION OUTPUT ;
    USE SIGNAL ;
    PORT
      LAYER M5 ;
        RECT  53.76 0 53.784 0.084 ;
    END
  END h_wdata[187]
  PIN h_wdata[188]
    DIRECTION OUTPUT ;
    USE SIGNAL ;
    PORT
      LAYER M5 ;
        RECT  53.856 0 53.88 0.084 ;
    END
  END h_wdata[188]
  PIN h_wdata[189]
    DIRECTION OUTPUT ;
    USE SIGNAL ;
    PORT
      LAYER M5 ;
        RECT  53.952 0 53.976 0.084 ;
    END
  END h_wdata[189]
  PIN h_wdata[18]
    DIRECTION OUTPUT ;
    USE SIGNAL ;
    PORT
      LAYER M5 ;
        RECT  37.536 0 37.56 0.084 ;
    END
  END h_wdata[18]
  PIN h_wdata[190]
    DIRECTION OUTPUT ;
    USE SIGNAL ;
    PORT
      LAYER M5 ;
        RECT  54.048 0 54.072 0.084 ;
    END
  END h_wdata[190]
  PIN h_wdata[191]
    DIRECTION OUTPUT ;
    USE SIGNAL ;
    PORT
      LAYER M5 ;
        RECT  54.144 0 54.168 0.084 ;
    END
  END h_wdata[191]
  PIN h_wdata[192]
    DIRECTION OUTPUT ;
    USE SIGNAL ;
    PORT
      LAYER M5 ;
        RECT  54.24 0 54.264 0.084 ;
    END
  END h_wdata[192]
  PIN h_wdata[193]
    DIRECTION OUTPUT ;
    USE SIGNAL ;
    PORT
      LAYER M5 ;
        RECT  54.336 0 54.36 0.084 ;
    END
  END h_wdata[193]
  PIN h_wdata[194]
    DIRECTION OUTPUT ;
    USE SIGNAL ;
    PORT
      LAYER M5 ;
        RECT  54.432 0 54.456 0.084 ;
    END
  END h_wdata[194]
  PIN h_wdata[195]
    DIRECTION OUTPUT ;
    USE SIGNAL ;
    PORT
      LAYER M5 ;
        RECT  54.528 0 54.552 0.084 ;
    END
  END h_wdata[195]
  PIN h_wdata[196]
    DIRECTION OUTPUT ;
    USE SIGNAL ;
    PORT
      LAYER M5 ;
        RECT  54.624 0 54.648 0.084 ;
    END
  END h_wdata[196]
  PIN h_wdata[197]
    DIRECTION OUTPUT ;
    USE SIGNAL ;
    PORT
      LAYER M5 ;
        RECT  54.72 0 54.744 0.084 ;
    END
  END h_wdata[197]
  PIN h_wdata[198]
    DIRECTION OUTPUT ;
    USE SIGNAL ;
    PORT
      LAYER M5 ;
        RECT  54.816 0 54.84 0.084 ;
    END
  END h_wdata[198]
  PIN h_wdata[199]
    DIRECTION OUTPUT ;
    USE SIGNAL ;
    PORT
      LAYER M5 ;
        RECT  54.912 0 54.936 0.084 ;
    END
  END h_wdata[199]
  PIN h_wdata[19]
    DIRECTION OUTPUT ;
    USE SIGNAL ;
    PORT
      LAYER M5 ;
        RECT  37.632 0 37.656 0.084 ;
    END
  END h_wdata[19]
  PIN h_wdata[1]
    DIRECTION OUTPUT ;
    USE SIGNAL ;
    PORT
      LAYER M5 ;
        RECT  35.904 0 35.928 0.084 ;
    END
  END h_wdata[1]
  PIN h_wdata[200]
    DIRECTION OUTPUT ;
    USE SIGNAL ;
    PORT
      LAYER M5 ;
        RECT  55.008 0 55.032 0.084 ;
    END
  END h_wdata[200]
  PIN h_wdata[201]
    DIRECTION OUTPUT ;
    USE SIGNAL ;
    PORT
      LAYER M5 ;
        RECT  55.104 0 55.128 0.084 ;
    END
  END h_wdata[201]
  PIN h_wdata[202]
    DIRECTION OUTPUT ;
    USE SIGNAL ;
    PORT
      LAYER M5 ;
        RECT  55.2 0 55.224 0.084 ;
    END
  END h_wdata[202]
  PIN h_wdata[203]
    DIRECTION OUTPUT ;
    USE SIGNAL ;
    PORT
      LAYER M5 ;
        RECT  55.296 0 55.32 0.084 ;
    END
  END h_wdata[203]
  PIN h_wdata[204]
    DIRECTION OUTPUT ;
    USE SIGNAL ;
    PORT
      LAYER M5 ;
        RECT  55.392 0 55.416 0.084 ;
    END
  END h_wdata[204]
  PIN h_wdata[205]
    DIRECTION OUTPUT ;
    USE SIGNAL ;
    PORT
      LAYER M5 ;
        RECT  55.488 0 55.512 0.084 ;
    END
  END h_wdata[205]
  PIN h_wdata[206]
    DIRECTION OUTPUT ;
    USE SIGNAL ;
    PORT
      LAYER M5 ;
        RECT  55.584 0 55.608 0.084 ;
    END
  END h_wdata[206]
  PIN h_wdata[207]
    DIRECTION OUTPUT ;
    USE SIGNAL ;
    PORT
      LAYER M5 ;
        RECT  55.68 0 55.704 0.084 ;
    END
  END h_wdata[207]
  PIN h_wdata[208]
    DIRECTION OUTPUT ;
    USE SIGNAL ;
    PORT
      LAYER M5 ;
        RECT  55.776 0 55.8 0.084 ;
    END
  END h_wdata[208]
  PIN h_wdata[209]
    DIRECTION OUTPUT ;
    USE SIGNAL ;
    PORT
      LAYER M5 ;
        RECT  55.872 0 55.896 0.084 ;
    END
  END h_wdata[209]
  PIN h_wdata[20]
    DIRECTION OUTPUT ;
    USE SIGNAL ;
    PORT
      LAYER M5 ;
        RECT  37.728 0 37.752 0.084 ;
    END
  END h_wdata[20]
  PIN h_wdata[210]
    DIRECTION OUTPUT ;
    USE SIGNAL ;
    PORT
      LAYER M5 ;
        RECT  55.968 0 55.992 0.084 ;
    END
  END h_wdata[210]
  PIN h_wdata[211]
    DIRECTION OUTPUT ;
    USE SIGNAL ;
    PORT
      LAYER M5 ;
        RECT  56.064 0 56.088 0.084 ;
    END
  END h_wdata[211]
  PIN h_wdata[212]
    DIRECTION OUTPUT ;
    USE SIGNAL ;
    PORT
      LAYER M5 ;
        RECT  56.16 0 56.184 0.084 ;
    END
  END h_wdata[212]
  PIN h_wdata[213]
    DIRECTION OUTPUT ;
    USE SIGNAL ;
    PORT
      LAYER M5 ;
        RECT  56.256 0 56.28 0.084 ;
    END
  END h_wdata[213]
  PIN h_wdata[214]
    DIRECTION OUTPUT ;
    USE SIGNAL ;
    PORT
      LAYER M5 ;
        RECT  56.352 0 56.376 0.084 ;
    END
  END h_wdata[214]
  PIN h_wdata[215]
    DIRECTION OUTPUT ;
    USE SIGNAL ;
    PORT
      LAYER M5 ;
        RECT  56.448 0 56.472 0.084 ;
    END
  END h_wdata[215]
  PIN h_wdata[216]
    DIRECTION OUTPUT ;
    USE SIGNAL ;
    PORT
      LAYER M5 ;
        RECT  56.544 0 56.568 0.084 ;
    END
  END h_wdata[216]
  PIN h_wdata[217]
    DIRECTION OUTPUT ;
    USE SIGNAL ;
    PORT
      LAYER M5 ;
        RECT  56.64 0 56.664 0.084 ;
    END
  END h_wdata[217]
  PIN h_wdata[218]
    DIRECTION OUTPUT ;
    USE SIGNAL ;
    PORT
      LAYER M5 ;
        RECT  56.736 0 56.76 0.084 ;
    END
  END h_wdata[218]
  PIN h_wdata[219]
    DIRECTION OUTPUT ;
    USE SIGNAL ;
    PORT
      LAYER M5 ;
        RECT  56.832 0 56.856 0.084 ;
    END
  END h_wdata[219]
  PIN h_wdata[21]
    DIRECTION OUTPUT ;
    USE SIGNAL ;
    PORT
      LAYER M5 ;
        RECT  37.824 0 37.848 0.084 ;
    END
  END h_wdata[21]
  PIN h_wdata[220]
    DIRECTION OUTPUT ;
    USE SIGNAL ;
    PORT
      LAYER M5 ;
        RECT  56.928 0 56.952 0.084 ;
    END
  END h_wdata[220]
  PIN h_wdata[221]
    DIRECTION OUTPUT ;
    USE SIGNAL ;
    PORT
      LAYER M5 ;
        RECT  57.024 0 57.048 0.084 ;
    END
  END h_wdata[221]
  PIN h_wdata[222]
    DIRECTION OUTPUT ;
    USE SIGNAL ;
    PORT
      LAYER M5 ;
        RECT  57.12 0 57.144 0.084 ;
    END
  END h_wdata[222]
  PIN h_wdata[223]
    DIRECTION OUTPUT ;
    USE SIGNAL ;
    PORT
      LAYER M5 ;
        RECT  57.216 0 57.24 0.084 ;
    END
  END h_wdata[223]
  PIN h_wdata[224]
    DIRECTION OUTPUT ;
    USE SIGNAL ;
    PORT
      LAYER M5 ;
        RECT  57.312 0 57.336 0.084 ;
    END
  END h_wdata[224]
  PIN h_wdata[225]
    DIRECTION OUTPUT ;
    USE SIGNAL ;
    PORT
      LAYER M5 ;
        RECT  57.408 0 57.432 0.084 ;
    END
  END h_wdata[225]
  PIN h_wdata[226]
    DIRECTION OUTPUT ;
    USE SIGNAL ;
    PORT
      LAYER M5 ;
        RECT  57.504 0 57.528 0.084 ;
    END
  END h_wdata[226]
  PIN h_wdata[227]
    DIRECTION OUTPUT ;
    USE SIGNAL ;
    PORT
      LAYER M5 ;
        RECT  57.6 0 57.624 0.084 ;
    END
  END h_wdata[227]
  PIN h_wdata[228]
    DIRECTION OUTPUT ;
    USE SIGNAL ;
    PORT
      LAYER M5 ;
        RECT  57.696 0 57.72 0.084 ;
    END
  END h_wdata[228]
  PIN h_wdata[229]
    DIRECTION OUTPUT ;
    USE SIGNAL ;
    PORT
      LAYER M5 ;
        RECT  57.792 0 57.816 0.084 ;
    END
  END h_wdata[229]
  PIN h_wdata[22]
    DIRECTION OUTPUT ;
    USE SIGNAL ;
    PORT
      LAYER M5 ;
        RECT  37.92 0 37.944 0.084 ;
    END
  END h_wdata[22]
  PIN h_wdata[230]
    DIRECTION OUTPUT ;
    USE SIGNAL ;
    PORT
      LAYER M5 ;
        RECT  57.888 0 57.912 0.084 ;
    END
  END h_wdata[230]
  PIN h_wdata[231]
    DIRECTION OUTPUT ;
    USE SIGNAL ;
    PORT
      LAYER M5 ;
        RECT  57.984 0 58.008 0.084 ;
    END
  END h_wdata[231]
  PIN h_wdata[232]
    DIRECTION OUTPUT ;
    USE SIGNAL ;
    PORT
      LAYER M5 ;
        RECT  58.08 0 58.104 0.084 ;
    END
  END h_wdata[232]
  PIN h_wdata[233]
    DIRECTION OUTPUT ;
    USE SIGNAL ;
    PORT
      LAYER M5 ;
        RECT  58.176 0 58.2 0.084 ;
    END
  END h_wdata[233]
  PIN h_wdata[234]
    DIRECTION OUTPUT ;
    USE SIGNAL ;
    PORT
      LAYER M5 ;
        RECT  58.272 0 58.296 0.084 ;
    END
  END h_wdata[234]
  PIN h_wdata[235]
    DIRECTION OUTPUT ;
    USE SIGNAL ;
    PORT
      LAYER M5 ;
        RECT  58.368 0 58.392 0.084 ;
    END
  END h_wdata[235]
  PIN h_wdata[236]
    DIRECTION OUTPUT ;
    USE SIGNAL ;
    PORT
      LAYER M5 ;
        RECT  58.464 0 58.488 0.084 ;
    END
  END h_wdata[236]
  PIN h_wdata[237]
    DIRECTION OUTPUT ;
    USE SIGNAL ;
    PORT
      LAYER M5 ;
        RECT  58.56 0 58.584 0.084 ;
    END
  END h_wdata[237]
  PIN h_wdata[238]
    DIRECTION OUTPUT ;
    USE SIGNAL ;
    PORT
      LAYER M5 ;
        RECT  58.656 0 58.68 0.084 ;
    END
  END h_wdata[238]
  PIN h_wdata[239]
    DIRECTION OUTPUT ;
    USE SIGNAL ;
    PORT
      LAYER M5 ;
        RECT  58.752 0 58.776 0.084 ;
    END
  END h_wdata[239]
  PIN h_wdata[23]
    DIRECTION OUTPUT ;
    USE SIGNAL ;
    PORT
      LAYER M5 ;
        RECT  38.016 0 38.04 0.084 ;
    END
  END h_wdata[23]
  PIN h_wdata[240]
    DIRECTION OUTPUT ;
    USE SIGNAL ;
    PORT
      LAYER M5 ;
        RECT  58.848 0 58.872 0.084 ;
    END
  END h_wdata[240]
  PIN h_wdata[241]
    DIRECTION OUTPUT ;
    USE SIGNAL ;
    PORT
      LAYER M5 ;
        RECT  58.944 0 58.968 0.084 ;
    END
  END h_wdata[241]
  PIN h_wdata[242]
    DIRECTION OUTPUT ;
    USE SIGNAL ;
    PORT
      LAYER M5 ;
        RECT  59.04 0 59.064 0.084 ;
    END
  END h_wdata[242]
  PIN h_wdata[243]
    DIRECTION OUTPUT ;
    USE SIGNAL ;
    PORT
      LAYER M5 ;
        RECT  59.136 0 59.16 0.084 ;
    END
  END h_wdata[243]
  PIN h_wdata[244]
    DIRECTION OUTPUT ;
    USE SIGNAL ;
    PORT
      LAYER M5 ;
        RECT  59.232 0 59.256 0.084 ;
    END
  END h_wdata[244]
  PIN h_wdata[245]
    DIRECTION OUTPUT ;
    USE SIGNAL ;
    PORT
      LAYER M5 ;
        RECT  59.328 0 59.352 0.084 ;
    END
  END h_wdata[245]
  PIN h_wdata[246]
    DIRECTION OUTPUT ;
    USE SIGNAL ;
    PORT
      LAYER M5 ;
        RECT  59.424 0 59.448 0.084 ;
    END
  END h_wdata[246]
  PIN h_wdata[247]
    DIRECTION OUTPUT ;
    USE SIGNAL ;
    PORT
      LAYER M5 ;
        RECT  59.52 0 59.544 0.084 ;
    END
  END h_wdata[247]
  PIN h_wdata[248]
    DIRECTION OUTPUT ;
    USE SIGNAL ;
    PORT
      LAYER M5 ;
        RECT  59.616 0 59.64 0.084 ;
    END
  END h_wdata[248]
  PIN h_wdata[249]
    DIRECTION OUTPUT ;
    USE SIGNAL ;
    PORT
      LAYER M5 ;
        RECT  59.712 0 59.736 0.084 ;
    END
  END h_wdata[249]
  PIN h_wdata[24]
    DIRECTION OUTPUT ;
    USE SIGNAL ;
    PORT
      LAYER M5 ;
        RECT  38.112 0 38.136 0.084 ;
    END
  END h_wdata[24]
  PIN h_wdata[250]
    DIRECTION OUTPUT ;
    USE SIGNAL ;
    PORT
      LAYER M5 ;
        RECT  59.808 0 59.832 0.084 ;
    END
  END h_wdata[250]
  PIN h_wdata[251]
    DIRECTION OUTPUT ;
    USE SIGNAL ;
    PORT
      LAYER M5 ;
        RECT  59.904 0 59.928 0.084 ;
    END
  END h_wdata[251]
  PIN h_wdata[252]
    DIRECTION OUTPUT ;
    USE SIGNAL ;
    PORT
      LAYER M5 ;
        RECT  60 0 60.024 0.084 ;
    END
  END h_wdata[252]
  PIN h_wdata[253]
    DIRECTION OUTPUT ;
    USE SIGNAL ;
    PORT
      LAYER M5 ;
        RECT  60.096 0 60.12 0.084 ;
    END
  END h_wdata[253]
  PIN h_wdata[254]
    DIRECTION OUTPUT ;
    USE SIGNAL ;
    PORT
      LAYER M5 ;
        RECT  60.192 0 60.216 0.084 ;
    END
  END h_wdata[254]
  PIN h_wdata[255]
    DIRECTION OUTPUT ;
    USE SIGNAL ;
    PORT
      LAYER M5 ;
        RECT  60.288 0 60.312 0.084 ;
    END
  END h_wdata[255]
  PIN h_wdata[25]
    DIRECTION OUTPUT ;
    USE SIGNAL ;
    PORT
      LAYER M5 ;
        RECT  38.208 0 38.232 0.084 ;
    END
  END h_wdata[25]
  PIN h_wdata[26]
    DIRECTION OUTPUT ;
    USE SIGNAL ;
    PORT
      LAYER M5 ;
        RECT  38.304 0 38.328 0.084 ;
    END
  END h_wdata[26]
  PIN h_wdata[27]
    DIRECTION OUTPUT ;
    USE SIGNAL ;
    PORT
      LAYER M5 ;
        RECT  38.4 0 38.424 0.084 ;
    END
  END h_wdata[27]
  PIN h_wdata[28]
    DIRECTION OUTPUT ;
    USE SIGNAL ;
    PORT
      LAYER M5 ;
        RECT  38.496 0 38.52 0.084 ;
    END
  END h_wdata[28]
  PIN h_wdata[29]
    DIRECTION OUTPUT ;
    USE SIGNAL ;
    PORT
      LAYER M5 ;
        RECT  38.592 0 38.616 0.084 ;
    END
  END h_wdata[29]
  PIN h_wdata[2]
    DIRECTION OUTPUT ;
    USE SIGNAL ;
    PORT
      LAYER M5 ;
        RECT  36 0 36.024 0.084 ;
    END
  END h_wdata[2]
  PIN h_wdata[30]
    DIRECTION OUTPUT ;
    USE SIGNAL ;
    PORT
      LAYER M5 ;
        RECT  38.688 0 38.712 0.084 ;
    END
  END h_wdata[30]
  PIN h_wdata[31]
    DIRECTION OUTPUT ;
    USE SIGNAL ;
    PORT
      LAYER M5 ;
        RECT  38.784 0 38.808 0.084 ;
    END
  END h_wdata[31]
  PIN h_wdata[32]
    DIRECTION OUTPUT ;
    USE SIGNAL ;
    PORT
      LAYER M5 ;
        RECT  38.88 0 38.904 0.084 ;
    END
  END h_wdata[32]
  PIN h_wdata[33]
    DIRECTION OUTPUT ;
    USE SIGNAL ;
    PORT
      LAYER M5 ;
        RECT  38.976 0 39 0.084 ;
    END
  END h_wdata[33]
  PIN h_wdata[34]
    DIRECTION OUTPUT ;
    USE SIGNAL ;
    PORT
      LAYER M5 ;
        RECT  39.072 0 39.096 0.084 ;
    END
  END h_wdata[34]
  PIN h_wdata[35]
    DIRECTION OUTPUT ;
    USE SIGNAL ;
    PORT
      LAYER M5 ;
        RECT  39.168 0 39.192 0.084 ;
    END
  END h_wdata[35]
  PIN h_wdata[36]
    DIRECTION OUTPUT ;
    USE SIGNAL ;
    PORT
      LAYER M5 ;
        RECT  39.264 0 39.288 0.084 ;
    END
  END h_wdata[36]
  PIN h_wdata[37]
    DIRECTION OUTPUT ;
    USE SIGNAL ;
    PORT
      LAYER M5 ;
        RECT  39.36 0 39.384 0.084 ;
    END
  END h_wdata[37]
  PIN h_wdata[38]
    DIRECTION OUTPUT ;
    USE SIGNAL ;
    PORT
      LAYER M5 ;
        RECT  39.456 0 39.48 0.084 ;
    END
  END h_wdata[38]
  PIN h_wdata[39]
    DIRECTION OUTPUT ;
    USE SIGNAL ;
    PORT
      LAYER M5 ;
        RECT  39.552 0 39.576 0.084 ;
    END
  END h_wdata[39]
  PIN h_wdata[3]
    DIRECTION OUTPUT ;
    USE SIGNAL ;
    PORT
      LAYER M5 ;
        RECT  36.096 0 36.12 0.084 ;
    END
  END h_wdata[3]
  PIN h_wdata[40]
    DIRECTION OUTPUT ;
    USE SIGNAL ;
    PORT
      LAYER M5 ;
        RECT  39.648 0 39.672 0.084 ;
    END
  END h_wdata[40]
  PIN h_wdata[41]
    DIRECTION OUTPUT ;
    USE SIGNAL ;
    PORT
      LAYER M5 ;
        RECT  39.744 0 39.768 0.084 ;
    END
  END h_wdata[41]
  PIN h_wdata[42]
    DIRECTION OUTPUT ;
    USE SIGNAL ;
    PORT
      LAYER M5 ;
        RECT  39.84 0 39.864 0.084 ;
    END
  END h_wdata[42]
  PIN h_wdata[43]
    DIRECTION OUTPUT ;
    USE SIGNAL ;
    PORT
      LAYER M5 ;
        RECT  39.936 0 39.96 0.084 ;
    END
  END h_wdata[43]
  PIN h_wdata[44]
    DIRECTION OUTPUT ;
    USE SIGNAL ;
    PORT
      LAYER M5 ;
        RECT  40.032 0 40.056 0.084 ;
    END
  END h_wdata[44]
  PIN h_wdata[45]
    DIRECTION OUTPUT ;
    USE SIGNAL ;
    PORT
      LAYER M5 ;
        RECT  40.128 0 40.152 0.084 ;
    END
  END h_wdata[45]
  PIN h_wdata[46]
    DIRECTION OUTPUT ;
    USE SIGNAL ;
    PORT
      LAYER M5 ;
        RECT  40.224 0 40.248 0.084 ;
    END
  END h_wdata[46]
  PIN h_wdata[47]
    DIRECTION OUTPUT ;
    USE SIGNAL ;
    PORT
      LAYER M5 ;
        RECT  40.32 0 40.344 0.084 ;
    END
  END h_wdata[47]
  PIN h_wdata[48]
    DIRECTION OUTPUT ;
    USE SIGNAL ;
    PORT
      LAYER M5 ;
        RECT  40.416 0 40.44 0.084 ;
    END
  END h_wdata[48]
  PIN h_wdata[49]
    DIRECTION OUTPUT ;
    USE SIGNAL ;
    PORT
      LAYER M5 ;
        RECT  40.512 0 40.536 0.084 ;
    END
  END h_wdata[49]
  PIN h_wdata[4]
    DIRECTION OUTPUT ;
    USE SIGNAL ;
    PORT
      LAYER M5 ;
        RECT  36.192 0 36.216 0.084 ;
    END
  END h_wdata[4]
  PIN h_wdata[50]
    DIRECTION OUTPUT ;
    USE SIGNAL ;
    PORT
      LAYER M5 ;
        RECT  40.608 0 40.632 0.084 ;
    END
  END h_wdata[50]
  PIN h_wdata[51]
    DIRECTION OUTPUT ;
    USE SIGNAL ;
    PORT
      LAYER M5 ;
        RECT  40.704 0 40.728 0.084 ;
    END
  END h_wdata[51]
  PIN h_wdata[52]
    DIRECTION OUTPUT ;
    USE SIGNAL ;
    PORT
      LAYER M5 ;
        RECT  40.8 0 40.824 0.084 ;
    END
  END h_wdata[52]
  PIN h_wdata[53]
    DIRECTION OUTPUT ;
    USE SIGNAL ;
    PORT
      LAYER M5 ;
        RECT  40.896 0 40.92 0.084 ;
    END
  END h_wdata[53]
  PIN h_wdata[54]
    DIRECTION OUTPUT ;
    USE SIGNAL ;
    PORT
      LAYER M5 ;
        RECT  40.992 0 41.016 0.084 ;
    END
  END h_wdata[54]
  PIN h_wdata[55]
    DIRECTION OUTPUT ;
    USE SIGNAL ;
    PORT
      LAYER M5 ;
        RECT  41.088 0 41.112 0.084 ;
    END
  END h_wdata[55]
  PIN h_wdata[56]
    DIRECTION OUTPUT ;
    USE SIGNAL ;
    PORT
      LAYER M5 ;
        RECT  41.184 0 41.208 0.084 ;
    END
  END h_wdata[56]
  PIN h_wdata[57]
    DIRECTION OUTPUT ;
    USE SIGNAL ;
    PORT
      LAYER M5 ;
        RECT  41.28 0 41.304 0.084 ;
    END
  END h_wdata[57]
  PIN h_wdata[58]
    DIRECTION OUTPUT ;
    USE SIGNAL ;
    PORT
      LAYER M5 ;
        RECT  41.376 0 41.4 0.084 ;
    END
  END h_wdata[58]
  PIN h_wdata[59]
    DIRECTION OUTPUT ;
    USE SIGNAL ;
    PORT
      LAYER M5 ;
        RECT  41.472 0 41.496 0.084 ;
    END
  END h_wdata[59]
  PIN h_wdata[5]
    DIRECTION OUTPUT ;
    USE SIGNAL ;
    PORT
      LAYER M5 ;
        RECT  36.288 0 36.312 0.084 ;
    END
  END h_wdata[5]
  PIN h_wdata[60]
    DIRECTION OUTPUT ;
    USE SIGNAL ;
    PORT
      LAYER M5 ;
        RECT  41.568 0 41.592 0.084 ;
    END
  END h_wdata[60]
  PIN h_wdata[61]
    DIRECTION OUTPUT ;
    USE SIGNAL ;
    PORT
      LAYER M5 ;
        RECT  41.664 0 41.688 0.084 ;
    END
  END h_wdata[61]
  PIN h_wdata[62]
    DIRECTION OUTPUT ;
    USE SIGNAL ;
    PORT
      LAYER M5 ;
        RECT  41.76 0 41.784 0.084 ;
    END
  END h_wdata[62]
  PIN h_wdata[63]
    DIRECTION OUTPUT ;
    USE SIGNAL ;
    PORT
      LAYER M5 ;
        RECT  41.856 0 41.88 0.084 ;
    END
  END h_wdata[63]
  PIN h_wdata[64]
    DIRECTION OUTPUT ;
    USE SIGNAL ;
    PORT
      LAYER M5 ;
        RECT  41.952 0 41.976 0.084 ;
    END
  END h_wdata[64]
  PIN h_wdata[65]
    DIRECTION OUTPUT ;
    USE SIGNAL ;
    PORT
      LAYER M5 ;
        RECT  42.048 0 42.072 0.084 ;
    END
  END h_wdata[65]
  PIN h_wdata[66]
    DIRECTION OUTPUT ;
    USE SIGNAL ;
    PORT
      LAYER M5 ;
        RECT  42.144 0 42.168 0.084 ;
    END
  END h_wdata[66]
  PIN h_wdata[67]
    DIRECTION OUTPUT ;
    USE SIGNAL ;
    PORT
      LAYER M5 ;
        RECT  42.24 0 42.264 0.084 ;
    END
  END h_wdata[67]
  PIN h_wdata[68]
    DIRECTION OUTPUT ;
    USE SIGNAL ;
    PORT
      LAYER M5 ;
        RECT  42.336 0 42.36 0.084 ;
    END
  END h_wdata[68]
  PIN h_wdata[69]
    DIRECTION OUTPUT ;
    USE SIGNAL ;
    PORT
      LAYER M5 ;
        RECT  42.432 0 42.456 0.084 ;
    END
  END h_wdata[69]
  PIN h_wdata[6]
    DIRECTION OUTPUT ;
    USE SIGNAL ;
    PORT
      LAYER M5 ;
        RECT  36.384 0 36.408 0.084 ;
    END
  END h_wdata[6]
  PIN h_wdata[70]
    DIRECTION OUTPUT ;
    USE SIGNAL ;
    PORT
      LAYER M5 ;
        RECT  42.528 0 42.552 0.084 ;
    END
  END h_wdata[70]
  PIN h_wdata[71]
    DIRECTION OUTPUT ;
    USE SIGNAL ;
    PORT
      LAYER M5 ;
        RECT  42.624 0 42.648 0.084 ;
    END
  END h_wdata[71]
  PIN h_wdata[72]
    DIRECTION OUTPUT ;
    USE SIGNAL ;
    PORT
      LAYER M5 ;
        RECT  42.72 0 42.744 0.084 ;
    END
  END h_wdata[72]
  PIN h_wdata[73]
    DIRECTION OUTPUT ;
    USE SIGNAL ;
    PORT
      LAYER M5 ;
        RECT  42.816 0 42.84 0.084 ;
    END
  END h_wdata[73]
  PIN h_wdata[74]
    DIRECTION OUTPUT ;
    USE SIGNAL ;
    PORT
      LAYER M5 ;
        RECT  42.912 0 42.936 0.084 ;
    END
  END h_wdata[74]
  PIN h_wdata[75]
    DIRECTION OUTPUT ;
    USE SIGNAL ;
    PORT
      LAYER M5 ;
        RECT  43.008 0 43.032 0.084 ;
    END
  END h_wdata[75]
  PIN h_wdata[76]
    DIRECTION OUTPUT ;
    USE SIGNAL ;
    PORT
      LAYER M5 ;
        RECT  43.104 0 43.128 0.084 ;
    END
  END h_wdata[76]
  PIN h_wdata[77]
    DIRECTION OUTPUT ;
    USE SIGNAL ;
    PORT
      LAYER M5 ;
        RECT  43.2 0 43.224 0.084 ;
    END
  END h_wdata[77]
  PIN h_wdata[78]
    DIRECTION OUTPUT ;
    USE SIGNAL ;
    PORT
      LAYER M5 ;
        RECT  43.296 0 43.32 0.084 ;
    END
  END h_wdata[78]
  PIN h_wdata[79]
    DIRECTION OUTPUT ;
    USE SIGNAL ;
    PORT
      LAYER M5 ;
        RECT  43.392 0 43.416 0.084 ;
    END
  END h_wdata[79]
  PIN h_wdata[7]
    DIRECTION OUTPUT ;
    USE SIGNAL ;
    PORT
      LAYER M5 ;
        RECT  36.48 0 36.504 0.084 ;
    END
  END h_wdata[7]
  PIN h_wdata[80]
    DIRECTION OUTPUT ;
    USE SIGNAL ;
    PORT
      LAYER M5 ;
        RECT  43.488 0 43.512 0.084 ;
    END
  END h_wdata[80]
  PIN h_wdata[81]
    DIRECTION OUTPUT ;
    USE SIGNAL ;
    PORT
      LAYER M5 ;
        RECT  43.584 0 43.608 0.084 ;
    END
  END h_wdata[81]
  PIN h_wdata[82]
    DIRECTION OUTPUT ;
    USE SIGNAL ;
    PORT
      LAYER M5 ;
        RECT  43.68 0 43.704 0.084 ;
    END
  END h_wdata[82]
  PIN h_wdata[83]
    DIRECTION OUTPUT ;
    USE SIGNAL ;
    PORT
      LAYER M5 ;
        RECT  43.776 0 43.8 0.084 ;
    END
  END h_wdata[83]
  PIN h_wdata[84]
    DIRECTION OUTPUT ;
    USE SIGNAL ;
    PORT
      LAYER M5 ;
        RECT  43.872 0 43.896 0.084 ;
    END
  END h_wdata[84]
  PIN h_wdata[85]
    DIRECTION OUTPUT ;
    USE SIGNAL ;
    PORT
      LAYER M5 ;
        RECT  43.968 0 43.992 0.084 ;
    END
  END h_wdata[85]
  PIN h_wdata[86]
    DIRECTION OUTPUT ;
    USE SIGNAL ;
    PORT
      LAYER M5 ;
        RECT  44.064 0 44.088 0.084 ;
    END
  END h_wdata[86]
  PIN h_wdata[87]
    DIRECTION OUTPUT ;
    USE SIGNAL ;
    PORT
      LAYER M5 ;
        RECT  44.16 0 44.184 0.084 ;
    END
  END h_wdata[87]
  PIN h_wdata[88]
    DIRECTION OUTPUT ;
    USE SIGNAL ;
    PORT
      LAYER M5 ;
        RECT  44.256 0 44.28 0.084 ;
    END
  END h_wdata[88]
  PIN h_wdata[89]
    DIRECTION OUTPUT ;
    USE SIGNAL ;
    PORT
      LAYER M5 ;
        RECT  44.352 0 44.376 0.084 ;
    END
  END h_wdata[89]
  PIN h_wdata[8]
    DIRECTION OUTPUT ;
    USE SIGNAL ;
    PORT
      LAYER M5 ;
        RECT  36.576 0 36.6 0.084 ;
    END
  END h_wdata[8]
  PIN h_wdata[90]
    DIRECTION OUTPUT ;
    USE SIGNAL ;
    PORT
      LAYER M5 ;
        RECT  44.448 0 44.472 0.084 ;
    END
  END h_wdata[90]
  PIN h_wdata[91]
    DIRECTION OUTPUT ;
    USE SIGNAL ;
    PORT
      LAYER M5 ;
        RECT  44.544 0 44.568 0.084 ;
    END
  END h_wdata[91]
  PIN h_wdata[92]
    DIRECTION OUTPUT ;
    USE SIGNAL ;
    PORT
      LAYER M5 ;
        RECT  44.64 0 44.664 0.084 ;
    END
  END h_wdata[92]
  PIN h_wdata[93]
    DIRECTION OUTPUT ;
    USE SIGNAL ;
    PORT
      LAYER M5 ;
        RECT  44.736 0 44.76 0.084 ;
    END
  END h_wdata[93]
  PIN h_wdata[94]
    DIRECTION OUTPUT ;
    USE SIGNAL ;
    PORT
      LAYER M5 ;
        RECT  44.832 0 44.856 0.084 ;
    END
  END h_wdata[94]
  PIN h_wdata[95]
    DIRECTION OUTPUT ;
    USE SIGNAL ;
    PORT
      LAYER M5 ;
        RECT  44.928 0 44.952 0.084 ;
    END
  END h_wdata[95]
  PIN h_wdata[96]
    DIRECTION OUTPUT ;
    USE SIGNAL ;
    PORT
      LAYER M5 ;
        RECT  45.024 0 45.048 0.084 ;
    END
  END h_wdata[96]
  PIN h_wdata[97]
    DIRECTION OUTPUT ;
    USE SIGNAL ;
    PORT
      LAYER M5 ;
        RECT  45.12 0 45.144 0.084 ;
    END
  END h_wdata[97]
  PIN h_wdata[98]
    DIRECTION OUTPUT ;
    USE SIGNAL ;
    PORT
      LAYER M5 ;
        RECT  45.216 0 45.24 0.084 ;
    END
  END h_wdata[98]
  PIN h_wdata[99]
    DIRECTION OUTPUT ;
    USE SIGNAL ;
    PORT
      LAYER M5 ;
        RECT  45.312 0 45.336 0.084 ;
    END
  END h_wdata[99]
  PIN h_wdata[9]
    DIRECTION OUTPUT ;
    USE SIGNAL ;
    PORT
      LAYER M5 ;
        RECT  36.672 0 36.696 0.084 ;
    END
  END h_wdata[9]
  PIN h_we
    DIRECTION OUTPUT ;
    USE SIGNAL ;
    PORT
      LAYER M5 ;
        RECT  60.384 0 60.408 0.084 ;
    END
  END h_we
  PIN h_wr_done
    DIRECTION INPUT ;
    USE SIGNAL ;
    PORT
      LAYER M5 ;
        RECT  60.48 0 60.504 0.084 ;
    END
  END h_wr_done
  PIN h_wstrb[0]
    DIRECTION OUTPUT ;
    USE SIGNAL ;
    PORT
      LAYER M5 ;
        RECT  60.576 0 60.6 0.084 ;
    END
  END h_wstrb[0]
  PIN h_wstrb[10]
    DIRECTION OUTPUT ;
    USE SIGNAL ;
    PORT
      LAYER M5 ;
        RECT  61.536 0 61.56 0.084 ;
    END
  END h_wstrb[10]
  PIN h_wstrb[11]
    DIRECTION OUTPUT ;
    USE SIGNAL ;
    PORT
      LAYER M5 ;
        RECT  61.632 0 61.656 0.084 ;
    END
  END h_wstrb[11]
  PIN h_wstrb[12]
    DIRECTION OUTPUT ;
    USE SIGNAL ;
    PORT
      LAYER M5 ;
        RECT  61.728 0 61.752 0.084 ;
    END
  END h_wstrb[12]
  PIN h_wstrb[13]
    DIRECTION OUTPUT ;
    USE SIGNAL ;
    PORT
      LAYER M5 ;
        RECT  61.824 0 61.848 0.084 ;
    END
  END h_wstrb[13]
  PIN h_wstrb[14]
    DIRECTION OUTPUT ;
    USE SIGNAL ;
    PORT
      LAYER M5 ;
        RECT  61.92 0 61.944 0.084 ;
    END
  END h_wstrb[14]
  PIN h_wstrb[15]
    DIRECTION OUTPUT ;
    USE SIGNAL ;
    PORT
      LAYER M5 ;
        RECT  62.016 0 62.04 0.084 ;
    END
  END h_wstrb[15]
  PIN h_wstrb[16]
    DIRECTION OUTPUT ;
    USE SIGNAL ;
    PORT
      LAYER M5 ;
        RECT  62.112 0 62.136 0.084 ;
    END
  END h_wstrb[16]
  PIN h_wstrb[17]
    DIRECTION OUTPUT ;
    USE SIGNAL ;
    PORT
      LAYER M5 ;
        RECT  62.208 0 62.232 0.084 ;
    END
  END h_wstrb[17]
  PIN h_wstrb[18]
    DIRECTION OUTPUT ;
    USE SIGNAL ;
    PORT
      LAYER M5 ;
        RECT  62.304 0 62.328 0.084 ;
    END
  END h_wstrb[18]
  PIN h_wstrb[19]
    DIRECTION OUTPUT ;
    USE SIGNAL ;
    PORT
      LAYER M5 ;
        RECT  62.4 0 62.424 0.084 ;
    END
  END h_wstrb[19]
  PIN h_wstrb[1]
    DIRECTION OUTPUT ;
    USE SIGNAL ;
    PORT
      LAYER M5 ;
        RECT  60.672 0 60.696 0.084 ;
    END
  END h_wstrb[1]
  PIN h_wstrb[20]
    DIRECTION OUTPUT ;
    USE SIGNAL ;
    PORT
      LAYER M5 ;
        RECT  62.496 0 62.52 0.084 ;
    END
  END h_wstrb[20]
  PIN h_wstrb[21]
    DIRECTION OUTPUT ;
    USE SIGNAL ;
    PORT
      LAYER M5 ;
        RECT  62.592 0 62.616 0.084 ;
    END
  END h_wstrb[21]
  PIN h_wstrb[22]
    DIRECTION OUTPUT ;
    USE SIGNAL ;
    PORT
      LAYER M5 ;
        RECT  62.688 0 62.712 0.084 ;
    END
  END h_wstrb[22]
  PIN h_wstrb[23]
    DIRECTION OUTPUT ;
    USE SIGNAL ;
    PORT
      LAYER M5 ;
        RECT  62.784 0 62.808 0.084 ;
    END
  END h_wstrb[23]
  PIN h_wstrb[24]
    DIRECTION OUTPUT ;
    USE SIGNAL ;
    PORT
      LAYER M5 ;
        RECT  62.88 0 62.904 0.084 ;
    END
  END h_wstrb[24]
  PIN h_wstrb[25]
    DIRECTION OUTPUT ;
    USE SIGNAL ;
    PORT
      LAYER M5 ;
        RECT  62.976 0 63 0.084 ;
    END
  END h_wstrb[25]
  PIN h_wstrb[26]
    DIRECTION OUTPUT ;
    USE SIGNAL ;
    PORT
      LAYER M5 ;
        RECT  63.072 0 63.096 0.084 ;
    END
  END h_wstrb[26]
  PIN h_wstrb[27]
    DIRECTION OUTPUT ;
    USE SIGNAL ;
    PORT
      LAYER M5 ;
        RECT  63.168 0 63.192 0.084 ;
    END
  END h_wstrb[27]
  PIN h_wstrb[28]
    DIRECTION OUTPUT ;
    USE SIGNAL ;
    PORT
      LAYER M5 ;
        RECT  63.264 0 63.288 0.084 ;
    END
  END h_wstrb[28]
  PIN h_wstrb[29]
    DIRECTION OUTPUT ;
    USE SIGNAL ;
    PORT
      LAYER M5 ;
        RECT  63.36 0 63.384 0.084 ;
    END
  END h_wstrb[29]
  PIN h_wstrb[2]
    DIRECTION OUTPUT ;
    USE SIGNAL ;
    PORT
      LAYER M5 ;
        RECT  60.768 0 60.792 0.084 ;
    END
  END h_wstrb[2]
  PIN h_wstrb[30]
    DIRECTION OUTPUT ;
    USE SIGNAL ;
    PORT
      LAYER M5 ;
        RECT  63.456 0 63.48 0.084 ;
    END
  END h_wstrb[30]
  PIN h_wstrb[31]
    DIRECTION OUTPUT ;
    USE SIGNAL ;
    PORT
      LAYER M5 ;
        RECT  63.552 0 63.576 0.084 ;
    END
  END h_wstrb[31]
  PIN h_wstrb[3]
    DIRECTION OUTPUT ;
    USE SIGNAL ;
    PORT
      LAYER M5 ;
        RECT  60.864 0 60.888 0.084 ;
    END
  END h_wstrb[3]
  PIN h_wstrb[4]
    DIRECTION OUTPUT ;
    USE SIGNAL ;
    PORT
      LAYER M5 ;
        RECT  60.96 0 60.984 0.084 ;
    END
  END h_wstrb[4]
  PIN h_wstrb[5]
    DIRECTION OUTPUT ;
    USE SIGNAL ;
    PORT
      LAYER M5 ;
        RECT  61.056 0 61.08 0.084 ;
    END
  END h_wstrb[5]
  PIN h_wstrb[6]
    DIRECTION OUTPUT ;
    USE SIGNAL ;
    PORT
      LAYER M5 ;
        RECT  61.152 0 61.176 0.084 ;
    END
  END h_wstrb[6]
  PIN h_wstrb[7]
    DIRECTION OUTPUT ;
    USE SIGNAL ;
    PORT
      LAYER M5 ;
        RECT  61.248 0 61.272 0.084 ;
    END
  END h_wstrb[7]
  PIN h_wstrb[8]
    DIRECTION OUTPUT ;
    USE SIGNAL ;
    PORT
      LAYER M5 ;
        RECT  61.344 0 61.368 0.084 ;
    END
  END h_wstrb[8]
  PIN h_wstrb[9]
    DIRECTION OUTPUT ;
    USE SIGNAL ;
    PORT
      LAYER M5 ;
        RECT  61.44 0 61.464 0.084 ;
    END
  END h_wstrb[9]
  PIN k_pop
    DIRECTION OUTPUT ;
    USE SIGNAL ;
    PORT
      LAYER M5 ;
        RECT  164.064 63.916 164.088 64 ;
    END
  END k_pop
  PIN k_wr_done
    DIRECTION OUTPUT ;
    USE SIGNAL ;
    PORT
      LAYER M5 ;
        RECT  164.16 63.916 164.184 64 ;
    END
  END k_wr_done
  PIN kin_addr[0]
    DIRECTION INPUT ;
    USE SIGNAL ;
    PORT
      LAYER M5 ;
        RECT  164.256 63.916 164.28 64 ;
    END
  END kin_addr[0]
  PIN kin_addr[10]
    DIRECTION INPUT ;
    USE SIGNAL ;
    PORT
      LAYER M5 ;
        RECT  165.216 63.916 165.24 64 ;
    END
  END kin_addr[10]
  PIN kin_addr[11]
    DIRECTION INPUT ;
    USE SIGNAL ;
    PORT
      LAYER M5 ;
        RECT  165.312 63.916 165.336 64 ;
    END
  END kin_addr[11]
  PIN kin_addr[12]
    DIRECTION INPUT ;
    USE SIGNAL ;
    PORT
      LAYER M5 ;
        RECT  165.408 63.916 165.432 64 ;
    END
  END kin_addr[12]
  PIN kin_addr[13]
    DIRECTION INPUT ;
    USE SIGNAL ;
    PORT
      LAYER M5 ;
        RECT  165.504 63.916 165.528 64 ;
    END
  END kin_addr[13]
  PIN kin_addr[14]
    DIRECTION INPUT ;
    USE SIGNAL ;
    PORT
      LAYER M5 ;
        RECT  165.6 63.916 165.624 64 ;
    END
  END kin_addr[14]
  PIN kin_addr[15]
    DIRECTION INPUT ;
    USE SIGNAL ;
    PORT
      LAYER M5 ;
        RECT  165.696 63.916 165.72 64 ;
    END
  END kin_addr[15]
  PIN kin_addr[16]
    DIRECTION INPUT ;
    USE SIGNAL ;
    PORT
      LAYER M5 ;
        RECT  165.792 63.916 165.816 64 ;
    END
  END kin_addr[16]
  PIN kin_addr[17]
    DIRECTION INPUT ;
    USE SIGNAL ;
    PORT
      LAYER M5 ;
        RECT  165.888 63.916 165.912 64 ;
    END
  END kin_addr[17]
  PIN kin_addr[18]
    DIRECTION INPUT ;
    USE SIGNAL ;
    PORT
      LAYER M5 ;
        RECT  165.984 63.916 166.008 64 ;
    END
  END kin_addr[18]
  PIN kin_addr[19]
    DIRECTION INPUT ;
    USE SIGNAL ;
    PORT
      LAYER M5 ;
        RECT  166.08 63.916 166.104 64 ;
    END
  END kin_addr[19]
  PIN kin_addr[1]
    DIRECTION INPUT ;
    USE SIGNAL ;
    PORT
      LAYER M5 ;
        RECT  164.352 63.916 164.376 64 ;
    END
  END kin_addr[1]
  PIN kin_addr[20]
    DIRECTION INPUT ;
    USE SIGNAL ;
    PORT
      LAYER M5 ;
        RECT  166.176 63.916 166.2 64 ;
    END
  END kin_addr[20]
  PIN kin_addr[21]
    DIRECTION INPUT ;
    USE SIGNAL ;
    PORT
      LAYER M5 ;
        RECT  166.272 63.916 166.296 64 ;
    END
  END kin_addr[21]
  PIN kin_addr[22]
    DIRECTION INPUT ;
    USE SIGNAL ;
    PORT
      LAYER M5 ;
        RECT  166.368 63.916 166.392 64 ;
    END
  END kin_addr[22]
  PIN kin_addr[23]
    DIRECTION INPUT ;
    USE SIGNAL ;
    PORT
      LAYER M5 ;
        RECT  166.464 63.916 166.488 64 ;
    END
  END kin_addr[23]
  PIN kin_addr[24]
    DIRECTION INPUT ;
    USE SIGNAL ;
    PORT
      LAYER M5 ;
        RECT  166.56 63.916 166.584 64 ;
    END
  END kin_addr[24]
  PIN kin_addr[25]
    DIRECTION INPUT ;
    USE SIGNAL ;
    PORT
      LAYER M5 ;
        RECT  166.656 63.916 166.68 64 ;
    END
  END kin_addr[25]
  PIN kin_addr[26]
    DIRECTION INPUT ;
    USE SIGNAL ;
    PORT
      LAYER M5 ;
        RECT  166.752 63.916 166.776 64 ;
    END
  END kin_addr[26]
  PIN kin_addr[27]
    DIRECTION INPUT ;
    USE SIGNAL ;
    PORT
      LAYER M5 ;
        RECT  166.848 63.916 166.872 64 ;
    END
  END kin_addr[27]
  PIN kin_addr[28]
    DIRECTION INPUT ;
    USE SIGNAL ;
    PORT
      LAYER M5 ;
        RECT  166.944 63.916 166.968 64 ;
    END
  END kin_addr[28]
  PIN kin_addr[29]
    DIRECTION INPUT ;
    USE SIGNAL ;
    PORT
      LAYER M5 ;
        RECT  167.04 63.916 167.064 64 ;
    END
  END kin_addr[29]
  PIN kin_addr[2]
    DIRECTION INPUT ;
    USE SIGNAL ;
    PORT
      LAYER M5 ;
        RECT  164.448 63.916 164.472 64 ;
    END
  END kin_addr[2]
  PIN kin_addr[3]
    DIRECTION INPUT ;
    USE SIGNAL ;
    PORT
      LAYER M5 ;
        RECT  164.544 63.916 164.568 64 ;
    END
  END kin_addr[3]
  PIN kin_addr[4]
    DIRECTION INPUT ;
    USE SIGNAL ;
    PORT
      LAYER M5 ;
        RECT  164.64 63.916 164.664 64 ;
    END
  END kin_addr[4]
  PIN kin_addr[5]
    DIRECTION INPUT ;
    USE SIGNAL ;
    PORT
      LAYER M5 ;
        RECT  164.736 63.916 164.76 64 ;
    END
  END kin_addr[5]
  PIN kin_addr[6]
    DIRECTION INPUT ;
    USE SIGNAL ;
    PORT
      LAYER M5 ;
        RECT  164.832 63.916 164.856 64 ;
    END
  END kin_addr[6]
  PIN kin_addr[7]
    DIRECTION INPUT ;
    USE SIGNAL ;
    PORT
      LAYER M5 ;
        RECT  164.928 63.916 164.952 64 ;
    END
  END kin_addr[7]
  PIN kin_addr[8]
    DIRECTION INPUT ;
    USE SIGNAL ;
    PORT
      LAYER M5 ;
        RECT  165.024 63.916 165.048 64 ;
    END
  END kin_addr[8]
  PIN kin_addr[9]
    DIRECTION INPUT ;
    USE SIGNAL ;
    PORT
      LAYER M5 ;
        RECT  165.12 63.916 165.144 64 ;
    END
  END kin_addr[9]
  PIN kin_len[0]
    DIRECTION INPUT ;
    USE SIGNAL ;
    PORT
      LAYER M5 ;
        RECT  167.136 63.916 167.16 64 ;
    END
  END kin_len[0]
  PIN kin_len[1]
    DIRECTION INPUT ;
    USE SIGNAL ;
    PORT
      LAYER M5 ;
        RECT  167.232 63.916 167.256 64 ;
    END
  END kin_len[1]
  PIN kin_len[2]
    DIRECTION INPUT ;
    USE SIGNAL ;
    PORT
      LAYER M5 ;
        RECT  167.328 63.916 167.352 64 ;
    END
  END kin_len[2]
  PIN kin_len[3]
    DIRECTION INPUT ;
    USE SIGNAL ;
    PORT
      LAYER M5 ;
        RECT  167.424 63.916 167.448 64 ;
    END
  END kin_len[3]
  PIN kin_tag[0]
    DIRECTION INPUT ;
    USE SIGNAL ;
    PORT
      LAYER M5 ;
        RECT  167.52 63.916 167.544 64 ;
    END
  END kin_tag[0]
  PIN kin_tag[10]
    DIRECTION INPUT ;
    USE SIGNAL ;
    PORT
      LAYER M5 ;
        RECT  168.48 63.916 168.504 64 ;
    END
  END kin_tag[10]
  PIN kin_tag[11]
    DIRECTION INPUT ;
    USE SIGNAL ;
    PORT
      LAYER M5 ;
        RECT  168.576 63.916 168.6 64 ;
    END
  END kin_tag[11]
  PIN kin_tag[12]
    DIRECTION INPUT ;
    USE SIGNAL ;
    PORT
      LAYER M5 ;
        RECT  168.672 63.916 168.696 64 ;
    END
  END kin_tag[12]
  PIN kin_tag[13]
    DIRECTION INPUT ;
    USE SIGNAL ;
    PORT
      LAYER M5 ;
        RECT  168.768 63.916 168.792 64 ;
    END
  END kin_tag[13]
  PIN kin_tag[14]
    DIRECTION INPUT ;
    USE SIGNAL ;
    PORT
      LAYER M5 ;
        RECT  168.864 63.916 168.888 64 ;
    END
  END kin_tag[14]
  PIN kin_tag[15]
    DIRECTION INPUT ;
    USE SIGNAL ;
    PORT
      LAYER M5 ;
        RECT  168.96 63.916 168.984 64 ;
    END
  END kin_tag[15]
  PIN kin_tag[1]
    DIRECTION INPUT ;
    USE SIGNAL ;
    PORT
      LAYER M5 ;
        RECT  167.616 63.916 167.64 64 ;
    END
  END kin_tag[1]
  PIN kin_tag[2]
    DIRECTION INPUT ;
    USE SIGNAL ;
    PORT
      LAYER M5 ;
        RECT  167.712 63.916 167.736 64 ;
    END
  END kin_tag[2]
  PIN kin_tag[3]
    DIRECTION INPUT ;
    USE SIGNAL ;
    PORT
      LAYER M5 ;
        RECT  167.808 63.916 167.832 64 ;
    END
  END kin_tag[3]
  PIN kin_tag[4]
    DIRECTION INPUT ;
    USE SIGNAL ;
    PORT
      LAYER M5 ;
        RECT  167.904 63.916 167.928 64 ;
    END
  END kin_tag[4]
  PIN kin_tag[5]
    DIRECTION INPUT ;
    USE SIGNAL ;
    PORT
      LAYER M5 ;
        RECT  168 63.916 168.024 64 ;
    END
  END kin_tag[5]
  PIN kin_tag[6]
    DIRECTION INPUT ;
    USE SIGNAL ;
    PORT
      LAYER M5 ;
        RECT  168.096 63.916 168.12 64 ;
    END
  END kin_tag[6]
  PIN kin_tag[7]
    DIRECTION INPUT ;
    USE SIGNAL ;
    PORT
      LAYER M5 ;
        RECT  168.192 63.916 168.216 64 ;
    END
  END kin_tag[7]
  PIN kin_tag[8]
    DIRECTION INPUT ;
    USE SIGNAL ;
    PORT
      LAYER M5 ;
        RECT  168.288 63.916 168.312 64 ;
    END
  END kin_tag[8]
  PIN kin_tag[9]
    DIRECTION INPUT ;
    USE SIGNAL ;
    PORT
      LAYER M5 ;
        RECT  168.384 63.916 168.408 64 ;
    END
  END kin_tag[9]
  PIN kin_v
    DIRECTION INPUT ;
    USE SIGNAL ;
    PORT
      LAYER M5 ;
        RECT  169.056 63.916 169.08 64 ;
    END
  END kin_v
  PIN kin_wdata[0]
    DIRECTION INPUT ;
    USE SIGNAL ;
    PORT
      LAYER M5 ;
        RECT  169.152 63.916 169.176 64 ;
    END
  END kin_wdata[0]
  PIN kin_wdata[100]
    DIRECTION INPUT ;
    USE SIGNAL ;
    PORT
      LAYER M5 ;
        RECT  178.752 63.916 178.776 64 ;
    END
  END kin_wdata[100]
  PIN kin_wdata[101]
    DIRECTION INPUT ;
    USE SIGNAL ;
    PORT
      LAYER M5 ;
        RECT  178.848 63.916 178.872 64 ;
    END
  END kin_wdata[101]
  PIN kin_wdata[102]
    DIRECTION INPUT ;
    USE SIGNAL ;
    PORT
      LAYER M5 ;
        RECT  178.944 63.916 178.968 64 ;
    END
  END kin_wdata[102]
  PIN kin_wdata[103]
    DIRECTION INPUT ;
    USE SIGNAL ;
    PORT
      LAYER M5 ;
        RECT  179.04 63.916 179.064 64 ;
    END
  END kin_wdata[103]
  PIN kin_wdata[104]
    DIRECTION INPUT ;
    USE SIGNAL ;
    PORT
      LAYER M5 ;
        RECT  179.136 63.916 179.16 64 ;
    END
  END kin_wdata[104]
  PIN kin_wdata[105]
    DIRECTION INPUT ;
    USE SIGNAL ;
    PORT
      LAYER M5 ;
        RECT  179.232 63.916 179.256 64 ;
    END
  END kin_wdata[105]
  PIN kin_wdata[106]
    DIRECTION INPUT ;
    USE SIGNAL ;
    PORT
      LAYER M5 ;
        RECT  179.328 63.916 179.352 64 ;
    END
  END kin_wdata[106]
  PIN kin_wdata[107]
    DIRECTION INPUT ;
    USE SIGNAL ;
    PORT
      LAYER M5 ;
        RECT  179.424 63.916 179.448 64 ;
    END
  END kin_wdata[107]
  PIN kin_wdata[108]
    DIRECTION INPUT ;
    USE SIGNAL ;
    PORT
      LAYER M5 ;
        RECT  179.52 63.916 179.544 64 ;
    END
  END kin_wdata[108]
  PIN kin_wdata[109]
    DIRECTION INPUT ;
    USE SIGNAL ;
    PORT
      LAYER M5 ;
        RECT  179.616 63.916 179.64 64 ;
    END
  END kin_wdata[109]
  PIN kin_wdata[10]
    DIRECTION INPUT ;
    USE SIGNAL ;
    PORT
      LAYER M5 ;
        RECT  170.112 63.916 170.136 64 ;
    END
  END kin_wdata[10]
  PIN kin_wdata[110]
    DIRECTION INPUT ;
    USE SIGNAL ;
    PORT
      LAYER M5 ;
        RECT  179.712 63.916 179.736 64 ;
    END
  END kin_wdata[110]
  PIN kin_wdata[111]
    DIRECTION INPUT ;
    USE SIGNAL ;
    PORT
      LAYER M5 ;
        RECT  179.808 63.916 179.832 64 ;
    END
  END kin_wdata[111]
  PIN kin_wdata[112]
    DIRECTION INPUT ;
    USE SIGNAL ;
    PORT
      LAYER M5 ;
        RECT  179.904 63.916 179.928 64 ;
    END
  END kin_wdata[112]
  PIN kin_wdata[113]
    DIRECTION INPUT ;
    USE SIGNAL ;
    PORT
      LAYER M5 ;
        RECT  180 63.916 180.024 64 ;
    END
  END kin_wdata[113]
  PIN kin_wdata[114]
    DIRECTION INPUT ;
    USE SIGNAL ;
    PORT
      LAYER M5 ;
        RECT  180.096 63.916 180.12 64 ;
    END
  END kin_wdata[114]
  PIN kin_wdata[115]
    DIRECTION INPUT ;
    USE SIGNAL ;
    PORT
      LAYER M5 ;
        RECT  180.192 63.916 180.216 64 ;
    END
  END kin_wdata[115]
  PIN kin_wdata[116]
    DIRECTION INPUT ;
    USE SIGNAL ;
    PORT
      LAYER M5 ;
        RECT  180.288 63.916 180.312 64 ;
    END
  END kin_wdata[116]
  PIN kin_wdata[117]
    DIRECTION INPUT ;
    USE SIGNAL ;
    PORT
      LAYER M5 ;
        RECT  180.384 63.916 180.408 64 ;
    END
  END kin_wdata[117]
  PIN kin_wdata[118]
    DIRECTION INPUT ;
    USE SIGNAL ;
    PORT
      LAYER M5 ;
        RECT  180.48 63.916 180.504 64 ;
    END
  END kin_wdata[118]
  PIN kin_wdata[119]
    DIRECTION INPUT ;
    USE SIGNAL ;
    PORT
      LAYER M5 ;
        RECT  180.576 63.916 180.6 64 ;
    END
  END kin_wdata[119]
  PIN kin_wdata[11]
    DIRECTION INPUT ;
    USE SIGNAL ;
    PORT
      LAYER M5 ;
        RECT  170.208 63.916 170.232 64 ;
    END
  END kin_wdata[11]
  PIN kin_wdata[120]
    DIRECTION INPUT ;
    USE SIGNAL ;
    PORT
      LAYER M5 ;
        RECT  180.672 63.916 180.696 64 ;
    END
  END kin_wdata[120]
  PIN kin_wdata[121]
    DIRECTION INPUT ;
    USE SIGNAL ;
    PORT
      LAYER M5 ;
        RECT  180.768 63.916 180.792 64 ;
    END
  END kin_wdata[121]
  PIN kin_wdata[122]
    DIRECTION INPUT ;
    USE SIGNAL ;
    PORT
      LAYER M5 ;
        RECT  180.864 63.916 180.888 64 ;
    END
  END kin_wdata[122]
  PIN kin_wdata[123]
    DIRECTION INPUT ;
    USE SIGNAL ;
    PORT
      LAYER M5 ;
        RECT  180.96 63.916 180.984 64 ;
    END
  END kin_wdata[123]
  PIN kin_wdata[124]
    DIRECTION INPUT ;
    USE SIGNAL ;
    PORT
      LAYER M5 ;
        RECT  181.056 63.916 181.08 64 ;
    END
  END kin_wdata[124]
  PIN kin_wdata[125]
    DIRECTION INPUT ;
    USE SIGNAL ;
    PORT
      LAYER M5 ;
        RECT  181.152 63.916 181.176 64 ;
    END
  END kin_wdata[125]
  PIN kin_wdata[126]
    DIRECTION INPUT ;
    USE SIGNAL ;
    PORT
      LAYER M5 ;
        RECT  181.248 63.916 181.272 64 ;
    END
  END kin_wdata[126]
  PIN kin_wdata[127]
    DIRECTION INPUT ;
    USE SIGNAL ;
    PORT
      LAYER M5 ;
        RECT  181.344 63.916 181.368 64 ;
    END
  END kin_wdata[127]
  PIN kin_wdata[128]
    DIRECTION INPUT ;
    USE SIGNAL ;
    PORT
      LAYER M5 ;
        RECT  181.44 63.916 181.464 64 ;
    END
  END kin_wdata[128]
  PIN kin_wdata[129]
    DIRECTION INPUT ;
    USE SIGNAL ;
    PORT
      LAYER M5 ;
        RECT  181.536 63.916 181.56 64 ;
    END
  END kin_wdata[129]
  PIN kin_wdata[12]
    DIRECTION INPUT ;
    USE SIGNAL ;
    PORT
      LAYER M5 ;
        RECT  170.304 63.916 170.328 64 ;
    END
  END kin_wdata[12]
  PIN kin_wdata[130]
    DIRECTION INPUT ;
    USE SIGNAL ;
    PORT
      LAYER M5 ;
        RECT  181.632 63.916 181.656 64 ;
    END
  END kin_wdata[130]
  PIN kin_wdata[131]
    DIRECTION INPUT ;
    USE SIGNAL ;
    PORT
      LAYER M5 ;
        RECT  181.728 63.916 181.752 64 ;
    END
  END kin_wdata[131]
  PIN kin_wdata[132]
    DIRECTION INPUT ;
    USE SIGNAL ;
    PORT
      LAYER M5 ;
        RECT  181.824 63.916 181.848 64 ;
    END
  END kin_wdata[132]
  PIN kin_wdata[133]
    DIRECTION INPUT ;
    USE SIGNAL ;
    PORT
      LAYER M5 ;
        RECT  181.92 63.916 181.944 64 ;
    END
  END kin_wdata[133]
  PIN kin_wdata[134]
    DIRECTION INPUT ;
    USE SIGNAL ;
    PORT
      LAYER M5 ;
        RECT  182.016 63.916 182.04 64 ;
    END
  END kin_wdata[134]
  PIN kin_wdata[135]
    DIRECTION INPUT ;
    USE SIGNAL ;
    PORT
      LAYER M5 ;
        RECT  182.112 63.916 182.136 64 ;
    END
  END kin_wdata[135]
  PIN kin_wdata[136]
    DIRECTION INPUT ;
    USE SIGNAL ;
    PORT
      LAYER M5 ;
        RECT  182.208 63.916 182.232 64 ;
    END
  END kin_wdata[136]
  PIN kin_wdata[137]
    DIRECTION INPUT ;
    USE SIGNAL ;
    PORT
      LAYER M5 ;
        RECT  182.304 63.916 182.328 64 ;
    END
  END kin_wdata[137]
  PIN kin_wdata[138]
    DIRECTION INPUT ;
    USE SIGNAL ;
    PORT
      LAYER M5 ;
        RECT  182.4 63.916 182.424 64 ;
    END
  END kin_wdata[138]
  PIN kin_wdata[139]
    DIRECTION INPUT ;
    USE SIGNAL ;
    PORT
      LAYER M5 ;
        RECT  182.496 63.916 182.52 64 ;
    END
  END kin_wdata[139]
  PIN kin_wdata[13]
    DIRECTION INPUT ;
    USE SIGNAL ;
    PORT
      LAYER M5 ;
        RECT  170.4 63.916 170.424 64 ;
    END
  END kin_wdata[13]
  PIN kin_wdata[140]
    DIRECTION INPUT ;
    USE SIGNAL ;
    PORT
      LAYER M5 ;
        RECT  182.592 63.916 182.616 64 ;
    END
  END kin_wdata[140]
  PIN kin_wdata[141]
    DIRECTION INPUT ;
    USE SIGNAL ;
    PORT
      LAYER M5 ;
        RECT  182.688 63.916 182.712 64 ;
    END
  END kin_wdata[141]
  PIN kin_wdata[142]
    DIRECTION INPUT ;
    USE SIGNAL ;
    PORT
      LAYER M5 ;
        RECT  182.784 63.916 182.808 64 ;
    END
  END kin_wdata[142]
  PIN kin_wdata[143]
    DIRECTION INPUT ;
    USE SIGNAL ;
    PORT
      LAYER M5 ;
        RECT  182.88 63.916 182.904 64 ;
    END
  END kin_wdata[143]
  PIN kin_wdata[144]
    DIRECTION INPUT ;
    USE SIGNAL ;
    PORT
      LAYER M5 ;
        RECT  182.976 63.916 183 64 ;
    END
  END kin_wdata[144]
  PIN kin_wdata[145]
    DIRECTION INPUT ;
    USE SIGNAL ;
    PORT
      LAYER M5 ;
        RECT  183.072 63.916 183.096 64 ;
    END
  END kin_wdata[145]
  PIN kin_wdata[146]
    DIRECTION INPUT ;
    USE SIGNAL ;
    PORT
      LAYER M5 ;
        RECT  183.168 63.916 183.192 64 ;
    END
  END kin_wdata[146]
  PIN kin_wdata[147]
    DIRECTION INPUT ;
    USE SIGNAL ;
    PORT
      LAYER M5 ;
        RECT  183.264 63.916 183.288 64 ;
    END
  END kin_wdata[147]
  PIN kin_wdata[148]
    DIRECTION INPUT ;
    USE SIGNAL ;
    PORT
      LAYER M5 ;
        RECT  183.36 63.916 183.384 64 ;
    END
  END kin_wdata[148]
  PIN kin_wdata[149]
    DIRECTION INPUT ;
    USE SIGNAL ;
    PORT
      LAYER M5 ;
        RECT  183.456 63.916 183.48 64 ;
    END
  END kin_wdata[149]
  PIN kin_wdata[14]
    DIRECTION INPUT ;
    USE SIGNAL ;
    PORT
      LAYER M5 ;
        RECT  170.496 63.916 170.52 64 ;
    END
  END kin_wdata[14]
  PIN kin_wdata[150]
    DIRECTION INPUT ;
    USE SIGNAL ;
    PORT
      LAYER M5 ;
        RECT  183.552 63.916 183.576 64 ;
    END
  END kin_wdata[150]
  PIN kin_wdata[151]
    DIRECTION INPUT ;
    USE SIGNAL ;
    PORT
      LAYER M5 ;
        RECT  183.648 63.916 183.672 64 ;
    END
  END kin_wdata[151]
  PIN kin_wdata[152]
    DIRECTION INPUT ;
    USE SIGNAL ;
    PORT
      LAYER M5 ;
        RECT  183.744 63.916 183.768 64 ;
    END
  END kin_wdata[152]
  PIN kin_wdata[153]
    DIRECTION INPUT ;
    USE SIGNAL ;
    PORT
      LAYER M5 ;
        RECT  183.84 63.916 183.864 64 ;
    END
  END kin_wdata[153]
  PIN kin_wdata[154]
    DIRECTION INPUT ;
    USE SIGNAL ;
    PORT
      LAYER M5 ;
        RECT  183.936 63.916 183.96 64 ;
    END
  END kin_wdata[154]
  PIN kin_wdata[155]
    DIRECTION INPUT ;
    USE SIGNAL ;
    PORT
      LAYER M5 ;
        RECT  184.032 63.916 184.056 64 ;
    END
  END kin_wdata[155]
  PIN kin_wdata[156]
    DIRECTION INPUT ;
    USE SIGNAL ;
    PORT
      LAYER M5 ;
        RECT  184.128 63.916 184.152 64 ;
    END
  END kin_wdata[156]
  PIN kin_wdata[157]
    DIRECTION INPUT ;
    USE SIGNAL ;
    PORT
      LAYER M5 ;
        RECT  184.224 63.916 184.248 64 ;
    END
  END kin_wdata[157]
  PIN kin_wdata[158]
    DIRECTION INPUT ;
    USE SIGNAL ;
    PORT
      LAYER M5 ;
        RECT  184.32 63.916 184.344 64 ;
    END
  END kin_wdata[158]
  PIN kin_wdata[159]
    DIRECTION INPUT ;
    USE SIGNAL ;
    PORT
      LAYER M5 ;
        RECT  184.416 63.916 184.44 64 ;
    END
  END kin_wdata[159]
  PIN kin_wdata[15]
    DIRECTION INPUT ;
    USE SIGNAL ;
    PORT
      LAYER M5 ;
        RECT  170.592 63.916 170.616 64 ;
    END
  END kin_wdata[15]
  PIN kin_wdata[160]
    DIRECTION INPUT ;
    USE SIGNAL ;
    PORT
      LAYER M5 ;
        RECT  184.512 63.916 184.536 64 ;
    END
  END kin_wdata[160]
  PIN kin_wdata[161]
    DIRECTION INPUT ;
    USE SIGNAL ;
    PORT
      LAYER M5 ;
        RECT  184.608 63.916 184.632 64 ;
    END
  END kin_wdata[161]
  PIN kin_wdata[162]
    DIRECTION INPUT ;
    USE SIGNAL ;
    PORT
      LAYER M5 ;
        RECT  184.704 63.916 184.728 64 ;
    END
  END kin_wdata[162]
  PIN kin_wdata[163]
    DIRECTION INPUT ;
    USE SIGNAL ;
    PORT
      LAYER M5 ;
        RECT  184.8 63.916 184.824 64 ;
    END
  END kin_wdata[163]
  PIN kin_wdata[164]
    DIRECTION INPUT ;
    USE SIGNAL ;
    PORT
      LAYER M5 ;
        RECT  184.896 63.916 184.92 64 ;
    END
  END kin_wdata[164]
  PIN kin_wdata[165]
    DIRECTION INPUT ;
    USE SIGNAL ;
    PORT
      LAYER M5 ;
        RECT  184.992 63.916 185.016 64 ;
    END
  END kin_wdata[165]
  PIN kin_wdata[166]
    DIRECTION INPUT ;
    USE SIGNAL ;
    PORT
      LAYER M5 ;
        RECT  185.088 63.916 185.112 64 ;
    END
  END kin_wdata[166]
  PIN kin_wdata[167]
    DIRECTION INPUT ;
    USE SIGNAL ;
    PORT
      LAYER M5 ;
        RECT  185.184 63.916 185.208 64 ;
    END
  END kin_wdata[167]
  PIN kin_wdata[168]
    DIRECTION INPUT ;
    USE SIGNAL ;
    PORT
      LAYER M5 ;
        RECT  185.28 63.916 185.304 64 ;
    END
  END kin_wdata[168]
  PIN kin_wdata[169]
    DIRECTION INPUT ;
    USE SIGNAL ;
    PORT
      LAYER M5 ;
        RECT  185.376 63.916 185.4 64 ;
    END
  END kin_wdata[169]
  PIN kin_wdata[16]
    DIRECTION INPUT ;
    USE SIGNAL ;
    PORT
      LAYER M5 ;
        RECT  170.688 63.916 170.712 64 ;
    END
  END kin_wdata[16]
  PIN kin_wdata[170]
    DIRECTION INPUT ;
    USE SIGNAL ;
    PORT
      LAYER M5 ;
        RECT  185.472 63.916 185.496 64 ;
    END
  END kin_wdata[170]
  PIN kin_wdata[171]
    DIRECTION INPUT ;
    USE SIGNAL ;
    PORT
      LAYER M5 ;
        RECT  185.568 63.916 185.592 64 ;
    END
  END kin_wdata[171]
  PIN kin_wdata[172]
    DIRECTION INPUT ;
    USE SIGNAL ;
    PORT
      LAYER M5 ;
        RECT  185.664 63.916 185.688 64 ;
    END
  END kin_wdata[172]
  PIN kin_wdata[173]
    DIRECTION INPUT ;
    USE SIGNAL ;
    PORT
      LAYER M5 ;
        RECT  185.76 63.916 185.784 64 ;
    END
  END kin_wdata[173]
  PIN kin_wdata[174]
    DIRECTION INPUT ;
    USE SIGNAL ;
    PORT
      LAYER M5 ;
        RECT  185.856 63.916 185.88 64 ;
    END
  END kin_wdata[174]
  PIN kin_wdata[175]
    DIRECTION INPUT ;
    USE SIGNAL ;
    PORT
      LAYER M5 ;
        RECT  185.952 63.916 185.976 64 ;
    END
  END kin_wdata[175]
  PIN kin_wdata[176]
    DIRECTION INPUT ;
    USE SIGNAL ;
    PORT
      LAYER M5 ;
        RECT  186.048 63.916 186.072 64 ;
    END
  END kin_wdata[176]
  PIN kin_wdata[177]
    DIRECTION INPUT ;
    USE SIGNAL ;
    PORT
      LAYER M5 ;
        RECT  186.144 63.916 186.168 64 ;
    END
  END kin_wdata[177]
  PIN kin_wdata[178]
    DIRECTION INPUT ;
    USE SIGNAL ;
    PORT
      LAYER M5 ;
        RECT  186.24 63.916 186.264 64 ;
    END
  END kin_wdata[178]
  PIN kin_wdata[179]
    DIRECTION INPUT ;
    USE SIGNAL ;
    PORT
      LAYER M5 ;
        RECT  186.336 63.916 186.36 64 ;
    END
  END kin_wdata[179]
  PIN kin_wdata[17]
    DIRECTION INPUT ;
    USE SIGNAL ;
    PORT
      LAYER M5 ;
        RECT  170.784 63.916 170.808 64 ;
    END
  END kin_wdata[17]
  PIN kin_wdata[180]
    DIRECTION INPUT ;
    USE SIGNAL ;
    PORT
      LAYER M5 ;
        RECT  186.432 63.916 186.456 64 ;
    END
  END kin_wdata[180]
  PIN kin_wdata[181]
    DIRECTION INPUT ;
    USE SIGNAL ;
    PORT
      LAYER M5 ;
        RECT  186.528 63.916 186.552 64 ;
    END
  END kin_wdata[181]
  PIN kin_wdata[182]
    DIRECTION INPUT ;
    USE SIGNAL ;
    PORT
      LAYER M5 ;
        RECT  186.624 63.916 186.648 64 ;
    END
  END kin_wdata[182]
  PIN kin_wdata[183]
    DIRECTION INPUT ;
    USE SIGNAL ;
    PORT
      LAYER M5 ;
        RECT  186.72 63.916 186.744 64 ;
    END
  END kin_wdata[183]
  PIN kin_wdata[184]
    DIRECTION INPUT ;
    USE SIGNAL ;
    PORT
      LAYER M5 ;
        RECT  186.816 63.916 186.84 64 ;
    END
  END kin_wdata[184]
  PIN kin_wdata[185]
    DIRECTION INPUT ;
    USE SIGNAL ;
    PORT
      LAYER M5 ;
        RECT  186.912 63.916 186.936 64 ;
    END
  END kin_wdata[185]
  PIN kin_wdata[186]
    DIRECTION INPUT ;
    USE SIGNAL ;
    PORT
      LAYER M5 ;
        RECT  187.008 63.916 187.032 64 ;
    END
  END kin_wdata[186]
  PIN kin_wdata[187]
    DIRECTION INPUT ;
    USE SIGNAL ;
    PORT
      LAYER M5 ;
        RECT  187.104 63.916 187.128 64 ;
    END
  END kin_wdata[187]
  PIN kin_wdata[188]
    DIRECTION INPUT ;
    USE SIGNAL ;
    PORT
      LAYER M5 ;
        RECT  187.2 63.916 187.224 64 ;
    END
  END kin_wdata[188]
  PIN kin_wdata[189]
    DIRECTION INPUT ;
    USE SIGNAL ;
    PORT
      LAYER M5 ;
        RECT  187.296 63.916 187.32 64 ;
    END
  END kin_wdata[189]
  PIN kin_wdata[18]
    DIRECTION INPUT ;
    USE SIGNAL ;
    PORT
      LAYER M5 ;
        RECT  170.88 63.916 170.904 64 ;
    END
  END kin_wdata[18]
  PIN kin_wdata[190]
    DIRECTION INPUT ;
    USE SIGNAL ;
    PORT
      LAYER M5 ;
        RECT  187.392 63.916 187.416 64 ;
    END
  END kin_wdata[190]
  PIN kin_wdata[191]
    DIRECTION INPUT ;
    USE SIGNAL ;
    PORT
      LAYER M5 ;
        RECT  187.488 63.916 187.512 64 ;
    END
  END kin_wdata[191]
  PIN kin_wdata[192]
    DIRECTION INPUT ;
    USE SIGNAL ;
    PORT
      LAYER M5 ;
        RECT  187.584 63.916 187.608 64 ;
    END
  END kin_wdata[192]
  PIN kin_wdata[193]
    DIRECTION INPUT ;
    USE SIGNAL ;
    PORT
      LAYER M5 ;
        RECT  187.68 63.916 187.704 64 ;
    END
  END kin_wdata[193]
  PIN kin_wdata[194]
    DIRECTION INPUT ;
    USE SIGNAL ;
    PORT
      LAYER M5 ;
        RECT  187.776 63.916 187.8 64 ;
    END
  END kin_wdata[194]
  PIN kin_wdata[195]
    DIRECTION INPUT ;
    USE SIGNAL ;
    PORT
      LAYER M5 ;
        RECT  187.872 63.916 187.896 64 ;
    END
  END kin_wdata[195]
  PIN kin_wdata[196]
    DIRECTION INPUT ;
    USE SIGNAL ;
    PORT
      LAYER M5 ;
        RECT  187.968 63.916 187.992 64 ;
    END
  END kin_wdata[196]
  PIN kin_wdata[197]
    DIRECTION INPUT ;
    USE SIGNAL ;
    PORT
      LAYER M5 ;
        RECT  188.064 63.916 188.088 64 ;
    END
  END kin_wdata[197]
  PIN kin_wdata[198]
    DIRECTION INPUT ;
    USE SIGNAL ;
    PORT
      LAYER M5 ;
        RECT  188.16 63.916 188.184 64 ;
    END
  END kin_wdata[198]
  PIN kin_wdata[199]
    DIRECTION INPUT ;
    USE SIGNAL ;
    PORT
      LAYER M5 ;
        RECT  188.256 63.916 188.28 64 ;
    END
  END kin_wdata[199]
  PIN kin_wdata[19]
    DIRECTION INPUT ;
    USE SIGNAL ;
    PORT
      LAYER M5 ;
        RECT  170.976 63.916 171 64 ;
    END
  END kin_wdata[19]
  PIN kin_wdata[1]
    DIRECTION INPUT ;
    USE SIGNAL ;
    PORT
      LAYER M5 ;
        RECT  169.248 63.916 169.272 64 ;
    END
  END kin_wdata[1]
  PIN kin_wdata[200]
    DIRECTION INPUT ;
    USE SIGNAL ;
    PORT
      LAYER M5 ;
        RECT  188.352 63.916 188.376 64 ;
    END
  END kin_wdata[200]
  PIN kin_wdata[201]
    DIRECTION INPUT ;
    USE SIGNAL ;
    PORT
      LAYER M5 ;
        RECT  188.448 63.916 188.472 64 ;
    END
  END kin_wdata[201]
  PIN kin_wdata[202]
    DIRECTION INPUT ;
    USE SIGNAL ;
    PORT
      LAYER M5 ;
        RECT  188.544 63.916 188.568 64 ;
    END
  END kin_wdata[202]
  PIN kin_wdata[203]
    DIRECTION INPUT ;
    USE SIGNAL ;
    PORT
      LAYER M5 ;
        RECT  188.64 63.916 188.664 64 ;
    END
  END kin_wdata[203]
  PIN kin_wdata[204]
    DIRECTION INPUT ;
    USE SIGNAL ;
    PORT
      LAYER M5 ;
        RECT  188.736 63.916 188.76 64 ;
    END
  END kin_wdata[204]
  PIN kin_wdata[205]
    DIRECTION INPUT ;
    USE SIGNAL ;
    PORT
      LAYER M5 ;
        RECT  188.832 63.916 188.856 64 ;
    END
  END kin_wdata[205]
  PIN kin_wdata[206]
    DIRECTION INPUT ;
    USE SIGNAL ;
    PORT
      LAYER M5 ;
        RECT  188.928 63.916 188.952 64 ;
    END
  END kin_wdata[206]
  PIN kin_wdata[207]
    DIRECTION INPUT ;
    USE SIGNAL ;
    PORT
      LAYER M5 ;
        RECT  189.024 63.916 189.048 64 ;
    END
  END kin_wdata[207]
  PIN kin_wdata[208]
    DIRECTION INPUT ;
    USE SIGNAL ;
    PORT
      LAYER M5 ;
        RECT  189.12 63.916 189.144 64 ;
    END
  END kin_wdata[208]
  PIN kin_wdata[209]
    DIRECTION INPUT ;
    USE SIGNAL ;
    PORT
      LAYER M5 ;
        RECT  189.216 63.916 189.24 64 ;
    END
  END kin_wdata[209]
  PIN kin_wdata[20]
    DIRECTION INPUT ;
    USE SIGNAL ;
    PORT
      LAYER M5 ;
        RECT  171.072 63.916 171.096 64 ;
    END
  END kin_wdata[20]
  PIN kin_wdata[210]
    DIRECTION INPUT ;
    USE SIGNAL ;
    PORT
      LAYER M5 ;
        RECT  189.312 63.916 189.336 64 ;
    END
  END kin_wdata[210]
  PIN kin_wdata[211]
    DIRECTION INPUT ;
    USE SIGNAL ;
    PORT
      LAYER M5 ;
        RECT  189.408 63.916 189.432 64 ;
    END
  END kin_wdata[211]
  PIN kin_wdata[212]
    DIRECTION INPUT ;
    USE SIGNAL ;
    PORT
      LAYER M5 ;
        RECT  189.504 63.916 189.528 64 ;
    END
  END kin_wdata[212]
  PIN kin_wdata[213]
    DIRECTION INPUT ;
    USE SIGNAL ;
    PORT
      LAYER M5 ;
        RECT  189.6 63.916 189.624 64 ;
    END
  END kin_wdata[213]
  PIN kin_wdata[214]
    DIRECTION INPUT ;
    USE SIGNAL ;
    PORT
      LAYER M5 ;
        RECT  189.696 63.916 189.72 64 ;
    END
  END kin_wdata[214]
  PIN kin_wdata[215]
    DIRECTION INPUT ;
    USE SIGNAL ;
    PORT
      LAYER M5 ;
        RECT  189.792 63.916 189.816 64 ;
    END
  END kin_wdata[215]
  PIN kin_wdata[216]
    DIRECTION INPUT ;
    USE SIGNAL ;
    PORT
      LAYER M5 ;
        RECT  189.888 63.916 189.912 64 ;
    END
  END kin_wdata[216]
  PIN kin_wdata[217]
    DIRECTION INPUT ;
    USE SIGNAL ;
    PORT
      LAYER M5 ;
        RECT  189.984 63.916 190.008 64 ;
    END
  END kin_wdata[217]
  PIN kin_wdata[218]
    DIRECTION INPUT ;
    USE SIGNAL ;
    PORT
      LAYER M5 ;
        RECT  190.08 63.916 190.104 64 ;
    END
  END kin_wdata[218]
  PIN kin_wdata[219]
    DIRECTION INPUT ;
    USE SIGNAL ;
    PORT
      LAYER M5 ;
        RECT  190.176 63.916 190.2 64 ;
    END
  END kin_wdata[219]
  PIN kin_wdata[21]
    DIRECTION INPUT ;
    USE SIGNAL ;
    PORT
      LAYER M5 ;
        RECT  171.168 63.916 171.192 64 ;
    END
  END kin_wdata[21]
  PIN kin_wdata[220]
    DIRECTION INPUT ;
    USE SIGNAL ;
    PORT
      LAYER M5 ;
        RECT  190.272 63.916 190.296 64 ;
    END
  END kin_wdata[220]
  PIN kin_wdata[221]
    DIRECTION INPUT ;
    USE SIGNAL ;
    PORT
      LAYER M5 ;
        RECT  190.368 63.916 190.392 64 ;
    END
  END kin_wdata[221]
  PIN kin_wdata[222]
    DIRECTION INPUT ;
    USE SIGNAL ;
    PORT
      LAYER M5 ;
        RECT  190.464 63.916 190.488 64 ;
    END
  END kin_wdata[222]
  PIN kin_wdata[223]
    DIRECTION INPUT ;
    USE SIGNAL ;
    PORT
      LAYER M5 ;
        RECT  190.56 63.916 190.584 64 ;
    END
  END kin_wdata[223]
  PIN kin_wdata[224]
    DIRECTION INPUT ;
    USE SIGNAL ;
    PORT
      LAYER M5 ;
        RECT  190.656 63.916 190.68 64 ;
    END
  END kin_wdata[224]
  PIN kin_wdata[225]
    DIRECTION INPUT ;
    USE SIGNAL ;
    PORT
      LAYER M5 ;
        RECT  190.752 63.916 190.776 64 ;
    END
  END kin_wdata[225]
  PIN kin_wdata[226]
    DIRECTION INPUT ;
    USE SIGNAL ;
    PORT
      LAYER M5 ;
        RECT  190.848 63.916 190.872 64 ;
    END
  END kin_wdata[226]
  PIN kin_wdata[227]
    DIRECTION INPUT ;
    USE SIGNAL ;
    PORT
      LAYER M5 ;
        RECT  190.944 63.916 190.968 64 ;
    END
  END kin_wdata[227]
  PIN kin_wdata[228]
    DIRECTION INPUT ;
    USE SIGNAL ;
    PORT
      LAYER M5 ;
        RECT  191.04 63.916 191.064 64 ;
    END
  END kin_wdata[228]
  PIN kin_wdata[229]
    DIRECTION INPUT ;
    USE SIGNAL ;
    PORT
      LAYER M5 ;
        RECT  191.136 63.916 191.16 64 ;
    END
  END kin_wdata[229]
  PIN kin_wdata[22]
    DIRECTION INPUT ;
    USE SIGNAL ;
    PORT
      LAYER M5 ;
        RECT  171.264 63.916 171.288 64 ;
    END
  END kin_wdata[22]
  PIN kin_wdata[230]
    DIRECTION INPUT ;
    USE SIGNAL ;
    PORT
      LAYER M5 ;
        RECT  191.232 63.916 191.256 64 ;
    END
  END kin_wdata[230]
  PIN kin_wdata[231]
    DIRECTION INPUT ;
    USE SIGNAL ;
    PORT
      LAYER M5 ;
        RECT  191.328 63.916 191.352 64 ;
    END
  END kin_wdata[231]
  PIN kin_wdata[232]
    DIRECTION INPUT ;
    USE SIGNAL ;
    PORT
      LAYER M5 ;
        RECT  191.424 63.916 191.448 64 ;
    END
  END kin_wdata[232]
  PIN kin_wdata[233]
    DIRECTION INPUT ;
    USE SIGNAL ;
    PORT
      LAYER M5 ;
        RECT  191.52 63.916 191.544 64 ;
    END
  END kin_wdata[233]
  PIN kin_wdata[234]
    DIRECTION INPUT ;
    USE SIGNAL ;
    PORT
      LAYER M5 ;
        RECT  191.616 63.916 191.64 64 ;
    END
  END kin_wdata[234]
  PIN kin_wdata[235]
    DIRECTION INPUT ;
    USE SIGNAL ;
    PORT
      LAYER M5 ;
        RECT  191.712 63.916 191.736 64 ;
    END
  END kin_wdata[235]
  PIN kin_wdata[236]
    DIRECTION INPUT ;
    USE SIGNAL ;
    PORT
      LAYER M5 ;
        RECT  191.808 63.916 191.832 64 ;
    END
  END kin_wdata[236]
  PIN kin_wdata[237]
    DIRECTION INPUT ;
    USE SIGNAL ;
    PORT
      LAYER M5 ;
        RECT  191.904 63.916 191.928 64 ;
    END
  END kin_wdata[237]
  PIN kin_wdata[238]
    DIRECTION INPUT ;
    USE SIGNAL ;
    PORT
      LAYER M5 ;
        RECT  192 63.916 192.024 64 ;
    END
  END kin_wdata[238]
  PIN kin_wdata[239]
    DIRECTION INPUT ;
    USE SIGNAL ;
    PORT
      LAYER M5 ;
        RECT  192.096 63.916 192.12 64 ;
    END
  END kin_wdata[239]
  PIN kin_wdata[23]
    DIRECTION INPUT ;
    USE SIGNAL ;
    PORT
      LAYER M5 ;
        RECT  171.36 63.916 171.384 64 ;
    END
  END kin_wdata[23]
  PIN kin_wdata[240]
    DIRECTION INPUT ;
    USE SIGNAL ;
    PORT
      LAYER M5 ;
        RECT  192.192 63.916 192.216 64 ;
    END
  END kin_wdata[240]
  PIN kin_wdata[241]
    DIRECTION INPUT ;
    USE SIGNAL ;
    PORT
      LAYER M5 ;
        RECT  192.288 63.916 192.312 64 ;
    END
  END kin_wdata[241]
  PIN kin_wdata[242]
    DIRECTION INPUT ;
    USE SIGNAL ;
    PORT
      LAYER M5 ;
        RECT  192.384 63.916 192.408 64 ;
    END
  END kin_wdata[242]
  PIN kin_wdata[243]
    DIRECTION INPUT ;
    USE SIGNAL ;
    PORT
      LAYER M5 ;
        RECT  192.48 63.916 192.504 64 ;
    END
  END kin_wdata[243]
  PIN kin_wdata[244]
    DIRECTION INPUT ;
    USE SIGNAL ;
    PORT
      LAYER M5 ;
        RECT  192.576 63.916 192.6 64 ;
    END
  END kin_wdata[244]
  PIN kin_wdata[245]
    DIRECTION INPUT ;
    USE SIGNAL ;
    PORT
      LAYER M5 ;
        RECT  192.672 63.916 192.696 64 ;
    END
  END kin_wdata[245]
  PIN kin_wdata[246]
    DIRECTION INPUT ;
    USE SIGNAL ;
    PORT
      LAYER M5 ;
        RECT  192.768 63.916 192.792 64 ;
    END
  END kin_wdata[246]
  PIN kin_wdata[247]
    DIRECTION INPUT ;
    USE SIGNAL ;
    PORT
      LAYER M5 ;
        RECT  192.864 63.916 192.888 64 ;
    END
  END kin_wdata[247]
  PIN kin_wdata[248]
    DIRECTION INPUT ;
    USE SIGNAL ;
    PORT
      LAYER M5 ;
        RECT  192.96 63.916 192.984 64 ;
    END
  END kin_wdata[248]
  PIN kin_wdata[249]
    DIRECTION INPUT ;
    USE SIGNAL ;
    PORT
      LAYER M5 ;
        RECT  193.056 63.916 193.08 64 ;
    END
  END kin_wdata[249]
  PIN kin_wdata[24]
    DIRECTION INPUT ;
    USE SIGNAL ;
    PORT
      LAYER M5 ;
        RECT  171.456 63.916 171.48 64 ;
    END
  END kin_wdata[24]
  PIN kin_wdata[250]
    DIRECTION INPUT ;
    USE SIGNAL ;
    PORT
      LAYER M5 ;
        RECT  193.152 63.916 193.176 64 ;
    END
  END kin_wdata[250]
  PIN kin_wdata[251]
    DIRECTION INPUT ;
    USE SIGNAL ;
    PORT
      LAYER M5 ;
        RECT  193.248 63.916 193.272 64 ;
    END
  END kin_wdata[251]
  PIN kin_wdata[252]
    DIRECTION INPUT ;
    USE SIGNAL ;
    PORT
      LAYER M5 ;
        RECT  193.344 63.916 193.368 64 ;
    END
  END kin_wdata[252]
  PIN kin_wdata[253]
    DIRECTION INPUT ;
    USE SIGNAL ;
    PORT
      LAYER M5 ;
        RECT  193.44 63.916 193.464 64 ;
    END
  END kin_wdata[253]
  PIN kin_wdata[254]
    DIRECTION INPUT ;
    USE SIGNAL ;
    PORT
      LAYER M5 ;
        RECT  193.536 63.916 193.56 64 ;
    END
  END kin_wdata[254]
  PIN kin_wdata[255]
    DIRECTION INPUT ;
    USE SIGNAL ;
    PORT
      LAYER M5 ;
        RECT  193.632 63.916 193.656 64 ;
    END
  END kin_wdata[255]
  PIN kin_wdata[25]
    DIRECTION INPUT ;
    USE SIGNAL ;
    PORT
      LAYER M5 ;
        RECT  171.552 63.916 171.576 64 ;
    END
  END kin_wdata[25]
  PIN kin_wdata[26]
    DIRECTION INPUT ;
    USE SIGNAL ;
    PORT
      LAYER M5 ;
        RECT  171.648 63.916 171.672 64 ;
    END
  END kin_wdata[26]
  PIN kin_wdata[27]
    DIRECTION INPUT ;
    USE SIGNAL ;
    PORT
      LAYER M5 ;
        RECT  171.744 63.916 171.768 64 ;
    END
  END kin_wdata[27]
  PIN kin_wdata[28]
    DIRECTION INPUT ;
    USE SIGNAL ;
    PORT
      LAYER M5 ;
        RECT  171.84 63.916 171.864 64 ;
    END
  END kin_wdata[28]
  PIN kin_wdata[29]
    DIRECTION INPUT ;
    USE SIGNAL ;
    PORT
      LAYER M5 ;
        RECT  171.936 63.916 171.96 64 ;
    END
  END kin_wdata[29]
  PIN kin_wdata[2]
    DIRECTION INPUT ;
    USE SIGNAL ;
    PORT
      LAYER M5 ;
        RECT  169.344 63.916 169.368 64 ;
    END
  END kin_wdata[2]
  PIN kin_wdata[30]
    DIRECTION INPUT ;
    USE SIGNAL ;
    PORT
      LAYER M5 ;
        RECT  172.032 63.916 172.056 64 ;
    END
  END kin_wdata[30]
  PIN kin_wdata[31]
    DIRECTION INPUT ;
    USE SIGNAL ;
    PORT
      LAYER M5 ;
        RECT  172.128 63.916 172.152 64 ;
    END
  END kin_wdata[31]
  PIN kin_wdata[32]
    DIRECTION INPUT ;
    USE SIGNAL ;
    PORT
      LAYER M5 ;
        RECT  172.224 63.916 172.248 64 ;
    END
  END kin_wdata[32]
  PIN kin_wdata[33]
    DIRECTION INPUT ;
    USE SIGNAL ;
    PORT
      LAYER M5 ;
        RECT  172.32 63.916 172.344 64 ;
    END
  END kin_wdata[33]
  PIN kin_wdata[34]
    DIRECTION INPUT ;
    USE SIGNAL ;
    PORT
      LAYER M5 ;
        RECT  172.416 63.916 172.44 64 ;
    END
  END kin_wdata[34]
  PIN kin_wdata[35]
    DIRECTION INPUT ;
    USE SIGNAL ;
    PORT
      LAYER M5 ;
        RECT  172.512 63.916 172.536 64 ;
    END
  END kin_wdata[35]
  PIN kin_wdata[36]
    DIRECTION INPUT ;
    USE SIGNAL ;
    PORT
      LAYER M5 ;
        RECT  172.608 63.916 172.632 64 ;
    END
  END kin_wdata[36]
  PIN kin_wdata[37]
    DIRECTION INPUT ;
    USE SIGNAL ;
    PORT
      LAYER M5 ;
        RECT  172.704 63.916 172.728 64 ;
    END
  END kin_wdata[37]
  PIN kin_wdata[38]
    DIRECTION INPUT ;
    USE SIGNAL ;
    PORT
      LAYER M5 ;
        RECT  172.8 63.916 172.824 64 ;
    END
  END kin_wdata[38]
  PIN kin_wdata[39]
    DIRECTION INPUT ;
    USE SIGNAL ;
    PORT
      LAYER M5 ;
        RECT  172.896 63.916 172.92 64 ;
    END
  END kin_wdata[39]
  PIN kin_wdata[3]
    DIRECTION INPUT ;
    USE SIGNAL ;
    PORT
      LAYER M5 ;
        RECT  169.44 63.916 169.464 64 ;
    END
  END kin_wdata[3]
  PIN kin_wdata[40]
    DIRECTION INPUT ;
    USE SIGNAL ;
    PORT
      LAYER M5 ;
        RECT  172.992 63.916 173.016 64 ;
    END
  END kin_wdata[40]
  PIN kin_wdata[41]
    DIRECTION INPUT ;
    USE SIGNAL ;
    PORT
      LAYER M5 ;
        RECT  173.088 63.916 173.112 64 ;
    END
  END kin_wdata[41]
  PIN kin_wdata[42]
    DIRECTION INPUT ;
    USE SIGNAL ;
    PORT
      LAYER M5 ;
        RECT  173.184 63.916 173.208 64 ;
    END
  END kin_wdata[42]
  PIN kin_wdata[43]
    DIRECTION INPUT ;
    USE SIGNAL ;
    PORT
      LAYER M5 ;
        RECT  173.28 63.916 173.304 64 ;
    END
  END kin_wdata[43]
  PIN kin_wdata[44]
    DIRECTION INPUT ;
    USE SIGNAL ;
    PORT
      LAYER M5 ;
        RECT  173.376 63.916 173.4 64 ;
    END
  END kin_wdata[44]
  PIN kin_wdata[45]
    DIRECTION INPUT ;
    USE SIGNAL ;
    PORT
      LAYER M5 ;
        RECT  173.472 63.916 173.496 64 ;
    END
  END kin_wdata[45]
  PIN kin_wdata[46]
    DIRECTION INPUT ;
    USE SIGNAL ;
    PORT
      LAYER M5 ;
        RECT  173.568 63.916 173.592 64 ;
    END
  END kin_wdata[46]
  PIN kin_wdata[47]
    DIRECTION INPUT ;
    USE SIGNAL ;
    PORT
      LAYER M5 ;
        RECT  173.664 63.916 173.688 64 ;
    END
  END kin_wdata[47]
  PIN kin_wdata[48]
    DIRECTION INPUT ;
    USE SIGNAL ;
    PORT
      LAYER M5 ;
        RECT  173.76 63.916 173.784 64 ;
    END
  END kin_wdata[48]
  PIN kin_wdata[49]
    DIRECTION INPUT ;
    USE SIGNAL ;
    PORT
      LAYER M5 ;
        RECT  173.856 63.916 173.88 64 ;
    END
  END kin_wdata[49]
  PIN kin_wdata[4]
    DIRECTION INPUT ;
    USE SIGNAL ;
    PORT
      LAYER M5 ;
        RECT  169.536 63.916 169.56 64 ;
    END
  END kin_wdata[4]
  PIN kin_wdata[50]
    DIRECTION INPUT ;
    USE SIGNAL ;
    PORT
      LAYER M5 ;
        RECT  173.952 63.916 173.976 64 ;
    END
  END kin_wdata[50]
  PIN kin_wdata[51]
    DIRECTION INPUT ;
    USE SIGNAL ;
    PORT
      LAYER M5 ;
        RECT  174.048 63.916 174.072 64 ;
    END
  END kin_wdata[51]
  PIN kin_wdata[52]
    DIRECTION INPUT ;
    USE SIGNAL ;
    PORT
      LAYER M5 ;
        RECT  174.144 63.916 174.168 64 ;
    END
  END kin_wdata[52]
  PIN kin_wdata[53]
    DIRECTION INPUT ;
    USE SIGNAL ;
    PORT
      LAYER M5 ;
        RECT  174.24 63.916 174.264 64 ;
    END
  END kin_wdata[53]
  PIN kin_wdata[54]
    DIRECTION INPUT ;
    USE SIGNAL ;
    PORT
      LAYER M5 ;
        RECT  174.336 63.916 174.36 64 ;
    END
  END kin_wdata[54]
  PIN kin_wdata[55]
    DIRECTION INPUT ;
    USE SIGNAL ;
    PORT
      LAYER M5 ;
        RECT  174.432 63.916 174.456 64 ;
    END
  END kin_wdata[55]
  PIN kin_wdata[56]
    DIRECTION INPUT ;
    USE SIGNAL ;
    PORT
      LAYER M5 ;
        RECT  174.528 63.916 174.552 64 ;
    END
  END kin_wdata[56]
  PIN kin_wdata[57]
    DIRECTION INPUT ;
    USE SIGNAL ;
    PORT
      LAYER M5 ;
        RECT  174.624 63.916 174.648 64 ;
    END
  END kin_wdata[57]
  PIN kin_wdata[58]
    DIRECTION INPUT ;
    USE SIGNAL ;
    PORT
      LAYER M5 ;
        RECT  174.72 63.916 174.744 64 ;
    END
  END kin_wdata[58]
  PIN kin_wdata[59]
    DIRECTION INPUT ;
    USE SIGNAL ;
    PORT
      LAYER M5 ;
        RECT  174.816 63.916 174.84 64 ;
    END
  END kin_wdata[59]
  PIN kin_wdata[5]
    DIRECTION INPUT ;
    USE SIGNAL ;
    PORT
      LAYER M5 ;
        RECT  169.632 63.916 169.656 64 ;
    END
  END kin_wdata[5]
  PIN kin_wdata[60]
    DIRECTION INPUT ;
    USE SIGNAL ;
    PORT
      LAYER M5 ;
        RECT  174.912 63.916 174.936 64 ;
    END
  END kin_wdata[60]
  PIN kin_wdata[61]
    DIRECTION INPUT ;
    USE SIGNAL ;
    PORT
      LAYER M5 ;
        RECT  175.008 63.916 175.032 64 ;
    END
  END kin_wdata[61]
  PIN kin_wdata[62]
    DIRECTION INPUT ;
    USE SIGNAL ;
    PORT
      LAYER M5 ;
        RECT  175.104 63.916 175.128 64 ;
    END
  END kin_wdata[62]
  PIN kin_wdata[63]
    DIRECTION INPUT ;
    USE SIGNAL ;
    PORT
      LAYER M5 ;
        RECT  175.2 63.916 175.224 64 ;
    END
  END kin_wdata[63]
  PIN kin_wdata[64]
    DIRECTION INPUT ;
    USE SIGNAL ;
    PORT
      LAYER M5 ;
        RECT  175.296 63.916 175.32 64 ;
    END
  END kin_wdata[64]
  PIN kin_wdata[65]
    DIRECTION INPUT ;
    USE SIGNAL ;
    PORT
      LAYER M5 ;
        RECT  175.392 63.916 175.416 64 ;
    END
  END kin_wdata[65]
  PIN kin_wdata[66]
    DIRECTION INPUT ;
    USE SIGNAL ;
    PORT
      LAYER M5 ;
        RECT  175.488 63.916 175.512 64 ;
    END
  END kin_wdata[66]
  PIN kin_wdata[67]
    DIRECTION INPUT ;
    USE SIGNAL ;
    PORT
      LAYER M5 ;
        RECT  175.584 63.916 175.608 64 ;
    END
  END kin_wdata[67]
  PIN kin_wdata[68]
    DIRECTION INPUT ;
    USE SIGNAL ;
    PORT
      LAYER M5 ;
        RECT  175.68 63.916 175.704 64 ;
    END
  END kin_wdata[68]
  PIN kin_wdata[69]
    DIRECTION INPUT ;
    USE SIGNAL ;
    PORT
      LAYER M5 ;
        RECT  175.776 63.916 175.8 64 ;
    END
  END kin_wdata[69]
  PIN kin_wdata[6]
    DIRECTION INPUT ;
    USE SIGNAL ;
    PORT
      LAYER M5 ;
        RECT  169.728 63.916 169.752 64 ;
    END
  END kin_wdata[6]
  PIN kin_wdata[70]
    DIRECTION INPUT ;
    USE SIGNAL ;
    PORT
      LAYER M5 ;
        RECT  175.872 63.916 175.896 64 ;
    END
  END kin_wdata[70]
  PIN kin_wdata[71]
    DIRECTION INPUT ;
    USE SIGNAL ;
    PORT
      LAYER M5 ;
        RECT  175.968 63.916 175.992 64 ;
    END
  END kin_wdata[71]
  PIN kin_wdata[72]
    DIRECTION INPUT ;
    USE SIGNAL ;
    PORT
      LAYER M5 ;
        RECT  176.064 63.916 176.088 64 ;
    END
  END kin_wdata[72]
  PIN kin_wdata[73]
    DIRECTION INPUT ;
    USE SIGNAL ;
    PORT
      LAYER M5 ;
        RECT  176.16 63.916 176.184 64 ;
    END
  END kin_wdata[73]
  PIN kin_wdata[74]
    DIRECTION INPUT ;
    USE SIGNAL ;
    PORT
      LAYER M5 ;
        RECT  176.256 63.916 176.28 64 ;
    END
  END kin_wdata[74]
  PIN kin_wdata[75]
    DIRECTION INPUT ;
    USE SIGNAL ;
    PORT
      LAYER M5 ;
        RECT  176.352 63.916 176.376 64 ;
    END
  END kin_wdata[75]
  PIN kin_wdata[76]
    DIRECTION INPUT ;
    USE SIGNAL ;
    PORT
      LAYER M5 ;
        RECT  176.448 63.916 176.472 64 ;
    END
  END kin_wdata[76]
  PIN kin_wdata[77]
    DIRECTION INPUT ;
    USE SIGNAL ;
    PORT
      LAYER M5 ;
        RECT  176.544 63.916 176.568 64 ;
    END
  END kin_wdata[77]
  PIN kin_wdata[78]
    DIRECTION INPUT ;
    USE SIGNAL ;
    PORT
      LAYER M5 ;
        RECT  176.64 63.916 176.664 64 ;
    END
  END kin_wdata[78]
  PIN kin_wdata[79]
    DIRECTION INPUT ;
    USE SIGNAL ;
    PORT
      LAYER M5 ;
        RECT  176.736 63.916 176.76 64 ;
    END
  END kin_wdata[79]
  PIN kin_wdata[7]
    DIRECTION INPUT ;
    USE SIGNAL ;
    PORT
      LAYER M5 ;
        RECT  169.824 63.916 169.848 64 ;
    END
  END kin_wdata[7]
  PIN kin_wdata[80]
    DIRECTION INPUT ;
    USE SIGNAL ;
    PORT
      LAYER M5 ;
        RECT  176.832 63.916 176.856 64 ;
    END
  END kin_wdata[80]
  PIN kin_wdata[81]
    DIRECTION INPUT ;
    USE SIGNAL ;
    PORT
      LAYER M5 ;
        RECT  176.928 63.916 176.952 64 ;
    END
  END kin_wdata[81]
  PIN kin_wdata[82]
    DIRECTION INPUT ;
    USE SIGNAL ;
    PORT
      LAYER M5 ;
        RECT  177.024 63.916 177.048 64 ;
    END
  END kin_wdata[82]
  PIN kin_wdata[83]
    DIRECTION INPUT ;
    USE SIGNAL ;
    PORT
      LAYER M5 ;
        RECT  177.12 63.916 177.144 64 ;
    END
  END kin_wdata[83]
  PIN kin_wdata[84]
    DIRECTION INPUT ;
    USE SIGNAL ;
    PORT
      LAYER M5 ;
        RECT  177.216 63.916 177.24 64 ;
    END
  END kin_wdata[84]
  PIN kin_wdata[85]
    DIRECTION INPUT ;
    USE SIGNAL ;
    PORT
      LAYER M5 ;
        RECT  177.312 63.916 177.336 64 ;
    END
  END kin_wdata[85]
  PIN kin_wdata[86]
    DIRECTION INPUT ;
    USE SIGNAL ;
    PORT
      LAYER M5 ;
        RECT  177.408 63.916 177.432 64 ;
    END
  END kin_wdata[86]
  PIN kin_wdata[87]
    DIRECTION INPUT ;
    USE SIGNAL ;
    PORT
      LAYER M5 ;
        RECT  177.504 63.916 177.528 64 ;
    END
  END kin_wdata[87]
  PIN kin_wdata[88]
    DIRECTION INPUT ;
    USE SIGNAL ;
    PORT
      LAYER M5 ;
        RECT  177.6 63.916 177.624 64 ;
    END
  END kin_wdata[88]
  PIN kin_wdata[89]
    DIRECTION INPUT ;
    USE SIGNAL ;
    PORT
      LAYER M5 ;
        RECT  177.696 63.916 177.72 64 ;
    END
  END kin_wdata[89]
  PIN kin_wdata[8]
    DIRECTION INPUT ;
    USE SIGNAL ;
    PORT
      LAYER M5 ;
        RECT  169.92 63.916 169.944 64 ;
    END
  END kin_wdata[8]
  PIN kin_wdata[90]
    DIRECTION INPUT ;
    USE SIGNAL ;
    PORT
      LAYER M5 ;
        RECT  177.792 63.916 177.816 64 ;
    END
  END kin_wdata[90]
  PIN kin_wdata[91]
    DIRECTION INPUT ;
    USE SIGNAL ;
    PORT
      LAYER M5 ;
        RECT  177.888 63.916 177.912 64 ;
    END
  END kin_wdata[91]
  PIN kin_wdata[92]
    DIRECTION INPUT ;
    USE SIGNAL ;
    PORT
      LAYER M5 ;
        RECT  177.984 63.916 178.008 64 ;
    END
  END kin_wdata[92]
  PIN kin_wdata[93]
    DIRECTION INPUT ;
    USE SIGNAL ;
    PORT
      LAYER M5 ;
        RECT  178.08 63.916 178.104 64 ;
    END
  END kin_wdata[93]
  PIN kin_wdata[94]
    DIRECTION INPUT ;
    USE SIGNAL ;
    PORT
      LAYER M5 ;
        RECT  178.176 63.916 178.2 64 ;
    END
  END kin_wdata[94]
  PIN kin_wdata[95]
    DIRECTION INPUT ;
    USE SIGNAL ;
    PORT
      LAYER M5 ;
        RECT  178.272 63.916 178.296 64 ;
    END
  END kin_wdata[95]
  PIN kin_wdata[96]
    DIRECTION INPUT ;
    USE SIGNAL ;
    PORT
      LAYER M5 ;
        RECT  178.368 63.916 178.392 64 ;
    END
  END kin_wdata[96]
  PIN kin_wdata[97]
    DIRECTION INPUT ;
    USE SIGNAL ;
    PORT
      LAYER M5 ;
        RECT  178.464 63.916 178.488 64 ;
    END
  END kin_wdata[97]
  PIN kin_wdata[98]
    DIRECTION INPUT ;
    USE SIGNAL ;
    PORT
      LAYER M5 ;
        RECT  178.56 63.916 178.584 64 ;
    END
  END kin_wdata[98]
  PIN kin_wdata[99]
    DIRECTION INPUT ;
    USE SIGNAL ;
    PORT
      LAYER M5 ;
        RECT  178.656 63.916 178.68 64 ;
    END
  END kin_wdata[99]
  PIN kin_wdata[9]
    DIRECTION INPUT ;
    USE SIGNAL ;
    PORT
      LAYER M5 ;
        RECT  170.016 63.916 170.04 64 ;
    END
  END kin_wdata[9]
  PIN kin_we
    DIRECTION INPUT ;
    USE SIGNAL ;
    PORT
      LAYER M5 ;
        RECT  193.728 63.916 193.752 64 ;
    END
  END kin_we
  PIN kin_wstrb[0]
    DIRECTION INPUT ;
    USE SIGNAL ;
    PORT
      LAYER M5 ;
        RECT  193.824 63.916 193.848 64 ;
    END
  END kin_wstrb[0]
  PIN kin_wstrb[10]
    DIRECTION INPUT ;
    USE SIGNAL ;
    PORT
      LAYER M5 ;
        RECT  194.784 63.916 194.808 64 ;
    END
  END kin_wstrb[10]
  PIN kin_wstrb[11]
    DIRECTION INPUT ;
    USE SIGNAL ;
    PORT
      LAYER M5 ;
        RECT  194.88 63.916 194.904 64 ;
    END
  END kin_wstrb[11]
  PIN kin_wstrb[12]
    DIRECTION INPUT ;
    USE SIGNAL ;
    PORT
      LAYER M5 ;
        RECT  194.976 63.916 195 64 ;
    END
  END kin_wstrb[12]
  PIN kin_wstrb[13]
    DIRECTION INPUT ;
    USE SIGNAL ;
    PORT
      LAYER M5 ;
        RECT  195.072 63.916 195.096 64 ;
    END
  END kin_wstrb[13]
  PIN kin_wstrb[14]
    DIRECTION INPUT ;
    USE SIGNAL ;
    PORT
      LAYER M5 ;
        RECT  195.168 63.916 195.192 64 ;
    END
  END kin_wstrb[14]
  PIN kin_wstrb[15]
    DIRECTION INPUT ;
    USE SIGNAL ;
    PORT
      LAYER M5 ;
        RECT  195.264 63.916 195.288 64 ;
    END
  END kin_wstrb[15]
  PIN kin_wstrb[16]
    DIRECTION INPUT ;
    USE SIGNAL ;
    PORT
      LAYER M5 ;
        RECT  195.36 63.916 195.384 64 ;
    END
  END kin_wstrb[16]
  PIN kin_wstrb[17]
    DIRECTION INPUT ;
    USE SIGNAL ;
    PORT
      LAYER M5 ;
        RECT  195.456 63.916 195.48 64 ;
    END
  END kin_wstrb[17]
  PIN kin_wstrb[18]
    DIRECTION INPUT ;
    USE SIGNAL ;
    PORT
      LAYER M5 ;
        RECT  195.552 63.916 195.576 64 ;
    END
  END kin_wstrb[18]
  PIN kin_wstrb[19]
    DIRECTION INPUT ;
    USE SIGNAL ;
    PORT
      LAYER M5 ;
        RECT  195.648 63.916 195.672 64 ;
    END
  END kin_wstrb[19]
  PIN kin_wstrb[1]
    DIRECTION INPUT ;
    USE SIGNAL ;
    PORT
      LAYER M5 ;
        RECT  193.92 63.916 193.944 64 ;
    END
  END kin_wstrb[1]
  PIN kin_wstrb[20]
    DIRECTION INPUT ;
    USE SIGNAL ;
    PORT
      LAYER M5 ;
        RECT  195.744 63.916 195.768 64 ;
    END
  END kin_wstrb[20]
  PIN kin_wstrb[21]
    DIRECTION INPUT ;
    USE SIGNAL ;
    PORT
      LAYER M5 ;
        RECT  195.84 63.916 195.864 64 ;
    END
  END kin_wstrb[21]
  PIN kin_wstrb[22]
    DIRECTION INPUT ;
    USE SIGNAL ;
    PORT
      LAYER M5 ;
        RECT  195.936 63.916 195.96 64 ;
    END
  END kin_wstrb[22]
  PIN kin_wstrb[23]
    DIRECTION INPUT ;
    USE SIGNAL ;
    PORT
      LAYER M5 ;
        RECT  196.032 63.916 196.056 64 ;
    END
  END kin_wstrb[23]
  PIN kin_wstrb[24]
    DIRECTION INPUT ;
    USE SIGNAL ;
    PORT
      LAYER M5 ;
        RECT  196.128 63.916 196.152 64 ;
    END
  END kin_wstrb[24]
  PIN kin_wstrb[25]
    DIRECTION INPUT ;
    USE SIGNAL ;
    PORT
      LAYER M5 ;
        RECT  196.224 63.916 196.248 64 ;
    END
  END kin_wstrb[25]
  PIN kin_wstrb[26]
    DIRECTION INPUT ;
    USE SIGNAL ;
    PORT
      LAYER M5 ;
        RECT  196.32 63.916 196.344 64 ;
    END
  END kin_wstrb[26]
  PIN kin_wstrb[27]
    DIRECTION INPUT ;
    USE SIGNAL ;
    PORT
      LAYER M5 ;
        RECT  196.416 63.916 196.44 64 ;
    END
  END kin_wstrb[27]
  PIN kin_wstrb[28]
    DIRECTION INPUT ;
    USE SIGNAL ;
    PORT
      LAYER M5 ;
        RECT  196.512 63.916 196.536 64 ;
    END
  END kin_wstrb[28]
  PIN kin_wstrb[29]
    DIRECTION INPUT ;
    USE SIGNAL ;
    PORT
      LAYER M5 ;
        RECT  196.608 63.916 196.632 64 ;
    END
  END kin_wstrb[29]
  PIN kin_wstrb[2]
    DIRECTION INPUT ;
    USE SIGNAL ;
    PORT
      LAYER M5 ;
        RECT  194.016 63.916 194.04 64 ;
    END
  END kin_wstrb[2]
  PIN kin_wstrb[30]
    DIRECTION INPUT ;
    USE SIGNAL ;
    PORT
      LAYER M5 ;
        RECT  196.704 63.916 196.728 64 ;
    END
  END kin_wstrb[30]
  PIN kin_wstrb[31]
    DIRECTION INPUT ;
    USE SIGNAL ;
    PORT
      LAYER M5 ;
        RECT  196.8 63.916 196.824 64 ;
    END
  END kin_wstrb[31]
  PIN kin_wstrb[3]
    DIRECTION INPUT ;
    USE SIGNAL ;
    PORT
      LAYER M5 ;
        RECT  194.112 63.916 194.136 64 ;
    END
  END kin_wstrb[3]
  PIN kin_wstrb[4]
    DIRECTION INPUT ;
    USE SIGNAL ;
    PORT
      LAYER M5 ;
        RECT  194.208 63.916 194.232 64 ;
    END
  END kin_wstrb[4]
  PIN kin_wstrb[5]
    DIRECTION INPUT ;
    USE SIGNAL ;
    PORT
      LAYER M5 ;
        RECT  194.304 63.916 194.328 64 ;
    END
  END kin_wstrb[5]
  PIN kin_wstrb[6]
    DIRECTION INPUT ;
    USE SIGNAL ;
    PORT
      LAYER M5 ;
        RECT  194.4 63.916 194.424 64 ;
    END
  END kin_wstrb[6]
  PIN kin_wstrb[7]
    DIRECTION INPUT ;
    USE SIGNAL ;
    PORT
      LAYER M5 ;
        RECT  194.496 63.916 194.52 64 ;
    END
  END kin_wstrb[7]
  PIN kin_wstrb[8]
    DIRECTION INPUT ;
    USE SIGNAL ;
    PORT
      LAYER M5 ;
        RECT  194.592 63.916 194.616 64 ;
    END
  END kin_wstrb[8]
  PIN kin_wstrb[9]
    DIRECTION INPUT ;
    USE SIGNAL ;
    PORT
      LAYER M5 ;
        RECT  194.688 63.916 194.712 64 ;
    END
  END kin_wstrb[9]
  PIN ks_beat[0]
    DIRECTION OUTPUT ;
    USE SIGNAL ;
    PORT
      LAYER M5 ;
        RECT  196.896 63.916 196.92 64 ;
    END
  END ks_beat[0]
  PIN ks_beat[1]
    DIRECTION OUTPUT ;
    USE SIGNAL ;
    PORT
      LAYER M5 ;
        RECT  196.992 63.916 197.016 64 ;
    END
  END ks_beat[1]
  PIN ks_beat[2]
    DIRECTION OUTPUT ;
    USE SIGNAL ;
    PORT
      LAYER M5 ;
        RECT  197.088 63.916 197.112 64 ;
    END
  END ks_beat[2]
  PIN ks_beat[3]
    DIRECTION OUTPUT ;
    USE SIGNAL ;
    PORT
      LAYER M5 ;
        RECT  197.184 63.916 197.208 64 ;
    END
  END ks_beat[3]
  PIN ks_cr
    DIRECTION INPUT ;
    USE SIGNAL ;
    PORT
      LAYER M5 ;
        RECT  197.28 63.916 197.304 64 ;
    END
  END ks_cr
  PIN ks_data[0]
    DIRECTION OUTPUT ;
    USE SIGNAL ;
    PORT
      LAYER M5 ;
        RECT  197.376 63.916 197.4 64 ;
    END
  END ks_data[0]
  PIN ks_data[100]
    DIRECTION OUTPUT ;
    USE SIGNAL ;
    PORT
      LAYER M5 ;
        RECT  206.976 63.916 207 64 ;
    END
  END ks_data[100]
  PIN ks_data[101]
    DIRECTION OUTPUT ;
    USE SIGNAL ;
    PORT
      LAYER M5 ;
        RECT  207.072 63.916 207.096 64 ;
    END
  END ks_data[101]
  PIN ks_data[102]
    DIRECTION OUTPUT ;
    USE SIGNAL ;
    PORT
      LAYER M5 ;
        RECT  207.168 63.916 207.192 64 ;
    END
  END ks_data[102]
  PIN ks_data[103]
    DIRECTION OUTPUT ;
    USE SIGNAL ;
    PORT
      LAYER M5 ;
        RECT  207.264 63.916 207.288 64 ;
    END
  END ks_data[103]
  PIN ks_data[104]
    DIRECTION OUTPUT ;
    USE SIGNAL ;
    PORT
      LAYER M5 ;
        RECT  207.36 63.916 207.384 64 ;
    END
  END ks_data[104]
  PIN ks_data[105]
    DIRECTION OUTPUT ;
    USE SIGNAL ;
    PORT
      LAYER M5 ;
        RECT  207.456 63.916 207.48 64 ;
    END
  END ks_data[105]
  PIN ks_data[106]
    DIRECTION OUTPUT ;
    USE SIGNAL ;
    PORT
      LAYER M5 ;
        RECT  207.552 63.916 207.576 64 ;
    END
  END ks_data[106]
  PIN ks_data[107]
    DIRECTION OUTPUT ;
    USE SIGNAL ;
    PORT
      LAYER M5 ;
        RECT  207.648 63.916 207.672 64 ;
    END
  END ks_data[107]
  PIN ks_data[108]
    DIRECTION OUTPUT ;
    USE SIGNAL ;
    PORT
      LAYER M5 ;
        RECT  207.744 63.916 207.768 64 ;
    END
  END ks_data[108]
  PIN ks_data[109]
    DIRECTION OUTPUT ;
    USE SIGNAL ;
    PORT
      LAYER M5 ;
        RECT  207.84 63.916 207.864 64 ;
    END
  END ks_data[109]
  PIN ks_data[10]
    DIRECTION OUTPUT ;
    USE SIGNAL ;
    PORT
      LAYER M5 ;
        RECT  198.336 63.916 198.36 64 ;
    END
  END ks_data[10]
  PIN ks_data[110]
    DIRECTION OUTPUT ;
    USE SIGNAL ;
    PORT
      LAYER M5 ;
        RECT  207.936 63.916 207.96 64 ;
    END
  END ks_data[110]
  PIN ks_data[111]
    DIRECTION OUTPUT ;
    USE SIGNAL ;
    PORT
      LAYER M5 ;
        RECT  208.032 63.916 208.056 64 ;
    END
  END ks_data[111]
  PIN ks_data[112]
    DIRECTION OUTPUT ;
    USE SIGNAL ;
    PORT
      LAYER M5 ;
        RECT  208.128 63.916 208.152 64 ;
    END
  END ks_data[112]
  PIN ks_data[113]
    DIRECTION OUTPUT ;
    USE SIGNAL ;
    PORT
      LAYER M5 ;
        RECT  208.224 63.916 208.248 64 ;
    END
  END ks_data[113]
  PIN ks_data[114]
    DIRECTION OUTPUT ;
    USE SIGNAL ;
    PORT
      LAYER M5 ;
        RECT  208.32 63.916 208.344 64 ;
    END
  END ks_data[114]
  PIN ks_data[115]
    DIRECTION OUTPUT ;
    USE SIGNAL ;
    PORT
      LAYER M5 ;
        RECT  208.416 63.916 208.44 64 ;
    END
  END ks_data[115]
  PIN ks_data[116]
    DIRECTION OUTPUT ;
    USE SIGNAL ;
    PORT
      LAYER M5 ;
        RECT  208.512 63.916 208.536 64 ;
    END
  END ks_data[116]
  PIN ks_data[117]
    DIRECTION OUTPUT ;
    USE SIGNAL ;
    PORT
      LAYER M5 ;
        RECT  208.608 63.916 208.632 64 ;
    END
  END ks_data[117]
  PIN ks_data[118]
    DIRECTION OUTPUT ;
    USE SIGNAL ;
    PORT
      LAYER M5 ;
        RECT  208.704 63.916 208.728 64 ;
    END
  END ks_data[118]
  PIN ks_data[119]
    DIRECTION OUTPUT ;
    USE SIGNAL ;
    PORT
      LAYER M5 ;
        RECT  208.8 63.916 208.824 64 ;
    END
  END ks_data[119]
  PIN ks_data[11]
    DIRECTION OUTPUT ;
    USE SIGNAL ;
    PORT
      LAYER M5 ;
        RECT  198.432 63.916 198.456 64 ;
    END
  END ks_data[11]
  PIN ks_data[120]
    DIRECTION OUTPUT ;
    USE SIGNAL ;
    PORT
      LAYER M5 ;
        RECT  208.896 63.916 208.92 64 ;
    END
  END ks_data[120]
  PIN ks_data[121]
    DIRECTION OUTPUT ;
    USE SIGNAL ;
    PORT
      LAYER M5 ;
        RECT  208.992 63.916 209.016 64 ;
    END
  END ks_data[121]
  PIN ks_data[122]
    DIRECTION OUTPUT ;
    USE SIGNAL ;
    PORT
      LAYER M5 ;
        RECT  209.088 63.916 209.112 64 ;
    END
  END ks_data[122]
  PIN ks_data[123]
    DIRECTION OUTPUT ;
    USE SIGNAL ;
    PORT
      LAYER M5 ;
        RECT  209.184 63.916 209.208 64 ;
    END
  END ks_data[123]
  PIN ks_data[124]
    DIRECTION OUTPUT ;
    USE SIGNAL ;
    PORT
      LAYER M5 ;
        RECT  209.28 63.916 209.304 64 ;
    END
  END ks_data[124]
  PIN ks_data[125]
    DIRECTION OUTPUT ;
    USE SIGNAL ;
    PORT
      LAYER M5 ;
        RECT  209.376 63.916 209.4 64 ;
    END
  END ks_data[125]
  PIN ks_data[126]
    DIRECTION OUTPUT ;
    USE SIGNAL ;
    PORT
      LAYER M5 ;
        RECT  209.472 63.916 209.496 64 ;
    END
  END ks_data[126]
  PIN ks_data[127]
    DIRECTION OUTPUT ;
    USE SIGNAL ;
    PORT
      LAYER M5 ;
        RECT  209.568 63.916 209.592 64 ;
    END
  END ks_data[127]
  PIN ks_data[128]
    DIRECTION OUTPUT ;
    USE SIGNAL ;
    PORT
      LAYER M5 ;
        RECT  209.664 63.916 209.688 64 ;
    END
  END ks_data[128]
  PIN ks_data[129]
    DIRECTION OUTPUT ;
    USE SIGNAL ;
    PORT
      LAYER M5 ;
        RECT  209.76 63.916 209.784 64 ;
    END
  END ks_data[129]
  PIN ks_data[12]
    DIRECTION OUTPUT ;
    USE SIGNAL ;
    PORT
      LAYER M5 ;
        RECT  198.528 63.916 198.552 64 ;
    END
  END ks_data[12]
  PIN ks_data[130]
    DIRECTION OUTPUT ;
    USE SIGNAL ;
    PORT
      LAYER M5 ;
        RECT  209.856 63.916 209.88 64 ;
    END
  END ks_data[130]
  PIN ks_data[131]
    DIRECTION OUTPUT ;
    USE SIGNAL ;
    PORT
      LAYER M5 ;
        RECT  209.952 63.916 209.976 64 ;
    END
  END ks_data[131]
  PIN ks_data[132]
    DIRECTION OUTPUT ;
    USE SIGNAL ;
    PORT
      LAYER M5 ;
        RECT  210.048 63.916 210.072 64 ;
    END
  END ks_data[132]
  PIN ks_data[133]
    DIRECTION OUTPUT ;
    USE SIGNAL ;
    PORT
      LAYER M5 ;
        RECT  210.144 63.916 210.168 64 ;
    END
  END ks_data[133]
  PIN ks_data[134]
    DIRECTION OUTPUT ;
    USE SIGNAL ;
    PORT
      LAYER M5 ;
        RECT  210.24 63.916 210.264 64 ;
    END
  END ks_data[134]
  PIN ks_data[135]
    DIRECTION OUTPUT ;
    USE SIGNAL ;
    PORT
      LAYER M5 ;
        RECT  210.336 63.916 210.36 64 ;
    END
  END ks_data[135]
  PIN ks_data[136]
    DIRECTION OUTPUT ;
    USE SIGNAL ;
    PORT
      LAYER M5 ;
        RECT  210.432 63.916 210.456 64 ;
    END
  END ks_data[136]
  PIN ks_data[137]
    DIRECTION OUTPUT ;
    USE SIGNAL ;
    PORT
      LAYER M5 ;
        RECT  210.528 63.916 210.552 64 ;
    END
  END ks_data[137]
  PIN ks_data[138]
    DIRECTION OUTPUT ;
    USE SIGNAL ;
    PORT
      LAYER M5 ;
        RECT  210.624 63.916 210.648 64 ;
    END
  END ks_data[138]
  PIN ks_data[139]
    DIRECTION OUTPUT ;
    USE SIGNAL ;
    PORT
      LAYER M5 ;
        RECT  210.72 63.916 210.744 64 ;
    END
  END ks_data[139]
  PIN ks_data[13]
    DIRECTION OUTPUT ;
    USE SIGNAL ;
    PORT
      LAYER M5 ;
        RECT  198.624 63.916 198.648 64 ;
    END
  END ks_data[13]
  PIN ks_data[140]
    DIRECTION OUTPUT ;
    USE SIGNAL ;
    PORT
      LAYER M5 ;
        RECT  210.816 63.916 210.84 64 ;
    END
  END ks_data[140]
  PIN ks_data[141]
    DIRECTION OUTPUT ;
    USE SIGNAL ;
    PORT
      LAYER M5 ;
        RECT  210.912 63.916 210.936 64 ;
    END
  END ks_data[141]
  PIN ks_data[142]
    DIRECTION OUTPUT ;
    USE SIGNAL ;
    PORT
      LAYER M5 ;
        RECT  211.008 63.916 211.032 64 ;
    END
  END ks_data[142]
  PIN ks_data[143]
    DIRECTION OUTPUT ;
    USE SIGNAL ;
    PORT
      LAYER M5 ;
        RECT  211.104 63.916 211.128 64 ;
    END
  END ks_data[143]
  PIN ks_data[144]
    DIRECTION OUTPUT ;
    USE SIGNAL ;
    PORT
      LAYER M5 ;
        RECT  211.2 63.916 211.224 64 ;
    END
  END ks_data[144]
  PIN ks_data[145]
    DIRECTION OUTPUT ;
    USE SIGNAL ;
    PORT
      LAYER M5 ;
        RECT  211.296 63.916 211.32 64 ;
    END
  END ks_data[145]
  PIN ks_data[146]
    DIRECTION OUTPUT ;
    USE SIGNAL ;
    PORT
      LAYER M5 ;
        RECT  211.392 63.916 211.416 64 ;
    END
  END ks_data[146]
  PIN ks_data[147]
    DIRECTION OUTPUT ;
    USE SIGNAL ;
    PORT
      LAYER M5 ;
        RECT  211.488 63.916 211.512 64 ;
    END
  END ks_data[147]
  PIN ks_data[148]
    DIRECTION OUTPUT ;
    USE SIGNAL ;
    PORT
      LAYER M5 ;
        RECT  211.584 63.916 211.608 64 ;
    END
  END ks_data[148]
  PIN ks_data[149]
    DIRECTION OUTPUT ;
    USE SIGNAL ;
    PORT
      LAYER M5 ;
        RECT  211.68 63.916 211.704 64 ;
    END
  END ks_data[149]
  PIN ks_data[14]
    DIRECTION OUTPUT ;
    USE SIGNAL ;
    PORT
      LAYER M5 ;
        RECT  198.72 63.916 198.744 64 ;
    END
  END ks_data[14]
  PIN ks_data[150]
    DIRECTION OUTPUT ;
    USE SIGNAL ;
    PORT
      LAYER M5 ;
        RECT  211.776 63.916 211.8 64 ;
    END
  END ks_data[150]
  PIN ks_data[151]
    DIRECTION OUTPUT ;
    USE SIGNAL ;
    PORT
      LAYER M5 ;
        RECT  211.872 63.916 211.896 64 ;
    END
  END ks_data[151]
  PIN ks_data[152]
    DIRECTION OUTPUT ;
    USE SIGNAL ;
    PORT
      LAYER M5 ;
        RECT  211.968 63.916 211.992 64 ;
    END
  END ks_data[152]
  PIN ks_data[153]
    DIRECTION OUTPUT ;
    USE SIGNAL ;
    PORT
      LAYER M5 ;
        RECT  212.064 63.916 212.088 64 ;
    END
  END ks_data[153]
  PIN ks_data[154]
    DIRECTION OUTPUT ;
    USE SIGNAL ;
    PORT
      LAYER M5 ;
        RECT  212.16 63.916 212.184 64 ;
    END
  END ks_data[154]
  PIN ks_data[155]
    DIRECTION OUTPUT ;
    USE SIGNAL ;
    PORT
      LAYER M5 ;
        RECT  212.256 63.916 212.28 64 ;
    END
  END ks_data[155]
  PIN ks_data[156]
    DIRECTION OUTPUT ;
    USE SIGNAL ;
    PORT
      LAYER M5 ;
        RECT  212.352 63.916 212.376 64 ;
    END
  END ks_data[156]
  PIN ks_data[157]
    DIRECTION OUTPUT ;
    USE SIGNAL ;
    PORT
      LAYER M5 ;
        RECT  212.448 63.916 212.472 64 ;
    END
  END ks_data[157]
  PIN ks_data[158]
    DIRECTION OUTPUT ;
    USE SIGNAL ;
    PORT
      LAYER M5 ;
        RECT  212.544 63.916 212.568 64 ;
    END
  END ks_data[158]
  PIN ks_data[159]
    DIRECTION OUTPUT ;
    USE SIGNAL ;
    PORT
      LAYER M5 ;
        RECT  212.64 63.916 212.664 64 ;
    END
  END ks_data[159]
  PIN ks_data[15]
    DIRECTION OUTPUT ;
    USE SIGNAL ;
    PORT
      LAYER M5 ;
        RECT  198.816 63.916 198.84 64 ;
    END
  END ks_data[15]
  PIN ks_data[160]
    DIRECTION OUTPUT ;
    USE SIGNAL ;
    PORT
      LAYER M5 ;
        RECT  212.736 63.916 212.76 64 ;
    END
  END ks_data[160]
  PIN ks_data[161]
    DIRECTION OUTPUT ;
    USE SIGNAL ;
    PORT
      LAYER M5 ;
        RECT  212.832 63.916 212.856 64 ;
    END
  END ks_data[161]
  PIN ks_data[162]
    DIRECTION OUTPUT ;
    USE SIGNAL ;
    PORT
      LAYER M5 ;
        RECT  212.928 63.916 212.952 64 ;
    END
  END ks_data[162]
  PIN ks_data[163]
    DIRECTION OUTPUT ;
    USE SIGNAL ;
    PORT
      LAYER M5 ;
        RECT  213.024 63.916 213.048 64 ;
    END
  END ks_data[163]
  PIN ks_data[164]
    DIRECTION OUTPUT ;
    USE SIGNAL ;
    PORT
      LAYER M5 ;
        RECT  213.12 63.916 213.144 64 ;
    END
  END ks_data[164]
  PIN ks_data[165]
    DIRECTION OUTPUT ;
    USE SIGNAL ;
    PORT
      LAYER M5 ;
        RECT  213.216 63.916 213.24 64 ;
    END
  END ks_data[165]
  PIN ks_data[166]
    DIRECTION OUTPUT ;
    USE SIGNAL ;
    PORT
      LAYER M5 ;
        RECT  213.312 63.916 213.336 64 ;
    END
  END ks_data[166]
  PIN ks_data[167]
    DIRECTION OUTPUT ;
    USE SIGNAL ;
    PORT
      LAYER M5 ;
        RECT  213.408 63.916 213.432 64 ;
    END
  END ks_data[167]
  PIN ks_data[168]
    DIRECTION OUTPUT ;
    USE SIGNAL ;
    PORT
      LAYER M5 ;
        RECT  213.504 63.916 213.528 64 ;
    END
  END ks_data[168]
  PIN ks_data[169]
    DIRECTION OUTPUT ;
    USE SIGNAL ;
    PORT
      LAYER M5 ;
        RECT  213.6 63.916 213.624 64 ;
    END
  END ks_data[169]
  PIN ks_data[16]
    DIRECTION OUTPUT ;
    USE SIGNAL ;
    PORT
      LAYER M5 ;
        RECT  198.912 63.916 198.936 64 ;
    END
  END ks_data[16]
  PIN ks_data[170]
    DIRECTION OUTPUT ;
    USE SIGNAL ;
    PORT
      LAYER M5 ;
        RECT  213.696 63.916 213.72 64 ;
    END
  END ks_data[170]
  PIN ks_data[171]
    DIRECTION OUTPUT ;
    USE SIGNAL ;
    PORT
      LAYER M5 ;
        RECT  213.792 63.916 213.816 64 ;
    END
  END ks_data[171]
  PIN ks_data[172]
    DIRECTION OUTPUT ;
    USE SIGNAL ;
    PORT
      LAYER M5 ;
        RECT  213.888 63.916 213.912 64 ;
    END
  END ks_data[172]
  PIN ks_data[173]
    DIRECTION OUTPUT ;
    USE SIGNAL ;
    PORT
      LAYER M5 ;
        RECT  213.984 63.916 214.008 64 ;
    END
  END ks_data[173]
  PIN ks_data[174]
    DIRECTION OUTPUT ;
    USE SIGNAL ;
    PORT
      LAYER M5 ;
        RECT  214.08 63.916 214.104 64 ;
    END
  END ks_data[174]
  PIN ks_data[175]
    DIRECTION OUTPUT ;
    USE SIGNAL ;
    PORT
      LAYER M5 ;
        RECT  214.176 63.916 214.2 64 ;
    END
  END ks_data[175]
  PIN ks_data[176]
    DIRECTION OUTPUT ;
    USE SIGNAL ;
    PORT
      LAYER M5 ;
        RECT  214.272 63.916 214.296 64 ;
    END
  END ks_data[176]
  PIN ks_data[177]
    DIRECTION OUTPUT ;
    USE SIGNAL ;
    PORT
      LAYER M5 ;
        RECT  214.368 63.916 214.392 64 ;
    END
  END ks_data[177]
  PIN ks_data[178]
    DIRECTION OUTPUT ;
    USE SIGNAL ;
    PORT
      LAYER M5 ;
        RECT  214.464 63.916 214.488 64 ;
    END
  END ks_data[178]
  PIN ks_data[179]
    DIRECTION OUTPUT ;
    USE SIGNAL ;
    PORT
      LAYER M5 ;
        RECT  214.56 63.916 214.584 64 ;
    END
  END ks_data[179]
  PIN ks_data[17]
    DIRECTION OUTPUT ;
    USE SIGNAL ;
    PORT
      LAYER M5 ;
        RECT  199.008 63.916 199.032 64 ;
    END
  END ks_data[17]
  PIN ks_data[180]
    DIRECTION OUTPUT ;
    USE SIGNAL ;
    PORT
      LAYER M5 ;
        RECT  214.656 63.916 214.68 64 ;
    END
  END ks_data[180]
  PIN ks_data[181]
    DIRECTION OUTPUT ;
    USE SIGNAL ;
    PORT
      LAYER M5 ;
        RECT  214.752 63.916 214.776 64 ;
    END
  END ks_data[181]
  PIN ks_data[182]
    DIRECTION OUTPUT ;
    USE SIGNAL ;
    PORT
      LAYER M5 ;
        RECT  214.848 63.916 214.872 64 ;
    END
  END ks_data[182]
  PIN ks_data[183]
    DIRECTION OUTPUT ;
    USE SIGNAL ;
    PORT
      LAYER M5 ;
        RECT  214.944 63.916 214.968 64 ;
    END
  END ks_data[183]
  PIN ks_data[184]
    DIRECTION OUTPUT ;
    USE SIGNAL ;
    PORT
      LAYER M5 ;
        RECT  215.04 63.916 215.064 64 ;
    END
  END ks_data[184]
  PIN ks_data[185]
    DIRECTION OUTPUT ;
    USE SIGNAL ;
    PORT
      LAYER M5 ;
        RECT  215.136 63.916 215.16 64 ;
    END
  END ks_data[185]
  PIN ks_data[186]
    DIRECTION OUTPUT ;
    USE SIGNAL ;
    PORT
      LAYER M5 ;
        RECT  215.232 63.916 215.256 64 ;
    END
  END ks_data[186]
  PIN ks_data[187]
    DIRECTION OUTPUT ;
    USE SIGNAL ;
    PORT
      LAYER M5 ;
        RECT  215.328 63.916 215.352 64 ;
    END
  END ks_data[187]
  PIN ks_data[188]
    DIRECTION OUTPUT ;
    USE SIGNAL ;
    PORT
      LAYER M5 ;
        RECT  215.424 63.916 215.448 64 ;
    END
  END ks_data[188]
  PIN ks_data[189]
    DIRECTION OUTPUT ;
    USE SIGNAL ;
    PORT
      LAYER M5 ;
        RECT  215.52 63.916 215.544 64 ;
    END
  END ks_data[189]
  PIN ks_data[18]
    DIRECTION OUTPUT ;
    USE SIGNAL ;
    PORT
      LAYER M5 ;
        RECT  199.104 63.916 199.128 64 ;
    END
  END ks_data[18]
  PIN ks_data[190]
    DIRECTION OUTPUT ;
    USE SIGNAL ;
    PORT
      LAYER M5 ;
        RECT  215.616 63.916 215.64 64 ;
    END
  END ks_data[190]
  PIN ks_data[191]
    DIRECTION OUTPUT ;
    USE SIGNAL ;
    PORT
      LAYER M5 ;
        RECT  215.712 63.916 215.736 64 ;
    END
  END ks_data[191]
  PIN ks_data[192]
    DIRECTION OUTPUT ;
    USE SIGNAL ;
    PORT
      LAYER M5 ;
        RECT  215.808 63.916 215.832 64 ;
    END
  END ks_data[192]
  PIN ks_data[193]
    DIRECTION OUTPUT ;
    USE SIGNAL ;
    PORT
      LAYER M5 ;
        RECT  215.904 63.916 215.928 64 ;
    END
  END ks_data[193]
  PIN ks_data[194]
    DIRECTION OUTPUT ;
    USE SIGNAL ;
    PORT
      LAYER M5 ;
        RECT  216 63.916 216.024 64 ;
    END
  END ks_data[194]
  PIN ks_data[195]
    DIRECTION OUTPUT ;
    USE SIGNAL ;
    PORT
      LAYER M5 ;
        RECT  216.096 63.916 216.12 64 ;
    END
  END ks_data[195]
  PIN ks_data[196]
    DIRECTION OUTPUT ;
    USE SIGNAL ;
    PORT
      LAYER M5 ;
        RECT  216.192 63.916 216.216 64 ;
    END
  END ks_data[196]
  PIN ks_data[197]
    DIRECTION OUTPUT ;
    USE SIGNAL ;
    PORT
      LAYER M5 ;
        RECT  216.288 63.916 216.312 64 ;
    END
  END ks_data[197]
  PIN ks_data[198]
    DIRECTION OUTPUT ;
    USE SIGNAL ;
    PORT
      LAYER M5 ;
        RECT  216.384 63.916 216.408 64 ;
    END
  END ks_data[198]
  PIN ks_data[199]
    DIRECTION OUTPUT ;
    USE SIGNAL ;
    PORT
      LAYER M5 ;
        RECT  216.48 63.916 216.504 64 ;
    END
  END ks_data[199]
  PIN ks_data[19]
    DIRECTION OUTPUT ;
    USE SIGNAL ;
    PORT
      LAYER M5 ;
        RECT  199.2 63.916 199.224 64 ;
    END
  END ks_data[19]
  PIN ks_data[1]
    DIRECTION OUTPUT ;
    USE SIGNAL ;
    PORT
      LAYER M5 ;
        RECT  197.472 63.916 197.496 64 ;
    END
  END ks_data[1]
  PIN ks_data[200]
    DIRECTION OUTPUT ;
    USE SIGNAL ;
    PORT
      LAYER M5 ;
        RECT  216.576 63.916 216.6 64 ;
    END
  END ks_data[200]
  PIN ks_data[201]
    DIRECTION OUTPUT ;
    USE SIGNAL ;
    PORT
      LAYER M5 ;
        RECT  216.672 63.916 216.696 64 ;
    END
  END ks_data[201]
  PIN ks_data[202]
    DIRECTION OUTPUT ;
    USE SIGNAL ;
    PORT
      LAYER M5 ;
        RECT  216.768 63.916 216.792 64 ;
    END
  END ks_data[202]
  PIN ks_data[203]
    DIRECTION OUTPUT ;
    USE SIGNAL ;
    PORT
      LAYER M5 ;
        RECT  216.864 63.916 216.888 64 ;
    END
  END ks_data[203]
  PIN ks_data[204]
    DIRECTION OUTPUT ;
    USE SIGNAL ;
    PORT
      LAYER M5 ;
        RECT  216.96 63.916 216.984 64 ;
    END
  END ks_data[204]
  PIN ks_data[205]
    DIRECTION OUTPUT ;
    USE SIGNAL ;
    PORT
      LAYER M5 ;
        RECT  217.056 63.916 217.08 64 ;
    END
  END ks_data[205]
  PIN ks_data[206]
    DIRECTION OUTPUT ;
    USE SIGNAL ;
    PORT
      LAYER M5 ;
        RECT  217.152 63.916 217.176 64 ;
    END
  END ks_data[206]
  PIN ks_data[207]
    DIRECTION OUTPUT ;
    USE SIGNAL ;
    PORT
      LAYER M5 ;
        RECT  217.248 63.916 217.272 64 ;
    END
  END ks_data[207]
  PIN ks_data[208]
    DIRECTION OUTPUT ;
    USE SIGNAL ;
    PORT
      LAYER M5 ;
        RECT  217.344 63.916 217.368 64 ;
    END
  END ks_data[208]
  PIN ks_data[209]
    DIRECTION OUTPUT ;
    USE SIGNAL ;
    PORT
      LAYER M5 ;
        RECT  217.44 63.916 217.464 64 ;
    END
  END ks_data[209]
  PIN ks_data[20]
    DIRECTION OUTPUT ;
    USE SIGNAL ;
    PORT
      LAYER M5 ;
        RECT  199.296 63.916 199.32 64 ;
    END
  END ks_data[20]
  PIN ks_data[210]
    DIRECTION OUTPUT ;
    USE SIGNAL ;
    PORT
      LAYER M5 ;
        RECT  217.536 63.916 217.56 64 ;
    END
  END ks_data[210]
  PIN ks_data[211]
    DIRECTION OUTPUT ;
    USE SIGNAL ;
    PORT
      LAYER M5 ;
        RECT  217.632 63.916 217.656 64 ;
    END
  END ks_data[211]
  PIN ks_data[212]
    DIRECTION OUTPUT ;
    USE SIGNAL ;
    PORT
      LAYER M5 ;
        RECT  217.728 63.916 217.752 64 ;
    END
  END ks_data[212]
  PIN ks_data[213]
    DIRECTION OUTPUT ;
    USE SIGNAL ;
    PORT
      LAYER M5 ;
        RECT  217.824 63.916 217.848 64 ;
    END
  END ks_data[213]
  PIN ks_data[214]
    DIRECTION OUTPUT ;
    USE SIGNAL ;
    PORT
      LAYER M5 ;
        RECT  217.92 63.916 217.944 64 ;
    END
  END ks_data[214]
  PIN ks_data[215]
    DIRECTION OUTPUT ;
    USE SIGNAL ;
    PORT
      LAYER M5 ;
        RECT  218.016 63.916 218.04 64 ;
    END
  END ks_data[215]
  PIN ks_data[216]
    DIRECTION OUTPUT ;
    USE SIGNAL ;
    PORT
      LAYER M5 ;
        RECT  218.112 63.916 218.136 64 ;
    END
  END ks_data[216]
  PIN ks_data[217]
    DIRECTION OUTPUT ;
    USE SIGNAL ;
    PORT
      LAYER M5 ;
        RECT  218.208 63.916 218.232 64 ;
    END
  END ks_data[217]
  PIN ks_data[218]
    DIRECTION OUTPUT ;
    USE SIGNAL ;
    PORT
      LAYER M5 ;
        RECT  218.304 63.916 218.328 64 ;
    END
  END ks_data[218]
  PIN ks_data[219]
    DIRECTION OUTPUT ;
    USE SIGNAL ;
    PORT
      LAYER M5 ;
        RECT  218.4 63.916 218.424 64 ;
    END
  END ks_data[219]
  PIN ks_data[21]
    DIRECTION OUTPUT ;
    USE SIGNAL ;
    PORT
      LAYER M5 ;
        RECT  199.392 63.916 199.416 64 ;
    END
  END ks_data[21]
  PIN ks_data[220]
    DIRECTION OUTPUT ;
    USE SIGNAL ;
    PORT
      LAYER M5 ;
        RECT  218.496 63.916 218.52 64 ;
    END
  END ks_data[220]
  PIN ks_data[221]
    DIRECTION OUTPUT ;
    USE SIGNAL ;
    PORT
      LAYER M5 ;
        RECT  218.592 63.916 218.616 64 ;
    END
  END ks_data[221]
  PIN ks_data[222]
    DIRECTION OUTPUT ;
    USE SIGNAL ;
    PORT
      LAYER M5 ;
        RECT  218.688 63.916 218.712 64 ;
    END
  END ks_data[222]
  PIN ks_data[223]
    DIRECTION OUTPUT ;
    USE SIGNAL ;
    PORT
      LAYER M5 ;
        RECT  218.784 63.916 218.808 64 ;
    END
  END ks_data[223]
  PIN ks_data[224]
    DIRECTION OUTPUT ;
    USE SIGNAL ;
    PORT
      LAYER M5 ;
        RECT  218.88 63.916 218.904 64 ;
    END
  END ks_data[224]
  PIN ks_data[225]
    DIRECTION OUTPUT ;
    USE SIGNAL ;
    PORT
      LAYER M5 ;
        RECT  218.976 63.916 219 64 ;
    END
  END ks_data[225]
  PIN ks_data[226]
    DIRECTION OUTPUT ;
    USE SIGNAL ;
    PORT
      LAYER M5 ;
        RECT  219.072 63.916 219.096 64 ;
    END
  END ks_data[226]
  PIN ks_data[227]
    DIRECTION OUTPUT ;
    USE SIGNAL ;
    PORT
      LAYER M5 ;
        RECT  219.168 63.916 219.192 64 ;
    END
  END ks_data[227]
  PIN ks_data[228]
    DIRECTION OUTPUT ;
    USE SIGNAL ;
    PORT
      LAYER M5 ;
        RECT  219.264 63.916 219.288 64 ;
    END
  END ks_data[228]
  PIN ks_data[229]
    DIRECTION OUTPUT ;
    USE SIGNAL ;
    PORT
      LAYER M5 ;
        RECT  219.36 63.916 219.384 64 ;
    END
  END ks_data[229]
  PIN ks_data[22]
    DIRECTION OUTPUT ;
    USE SIGNAL ;
    PORT
      LAYER M5 ;
        RECT  199.488 63.916 199.512 64 ;
    END
  END ks_data[22]
  PIN ks_data[230]
    DIRECTION OUTPUT ;
    USE SIGNAL ;
    PORT
      LAYER M5 ;
        RECT  219.456 63.916 219.48 64 ;
    END
  END ks_data[230]
  PIN ks_data[231]
    DIRECTION OUTPUT ;
    USE SIGNAL ;
    PORT
      LAYER M5 ;
        RECT  219.552 63.916 219.576 64 ;
    END
  END ks_data[231]
  PIN ks_data[232]
    DIRECTION OUTPUT ;
    USE SIGNAL ;
    PORT
      LAYER M5 ;
        RECT  219.648 63.916 219.672 64 ;
    END
  END ks_data[232]
  PIN ks_data[233]
    DIRECTION OUTPUT ;
    USE SIGNAL ;
    PORT
      LAYER M5 ;
        RECT  219.744 63.916 219.768 64 ;
    END
  END ks_data[233]
  PIN ks_data[234]
    DIRECTION OUTPUT ;
    USE SIGNAL ;
    PORT
      LAYER M5 ;
        RECT  219.84 63.916 219.864 64 ;
    END
  END ks_data[234]
  PIN ks_data[235]
    DIRECTION OUTPUT ;
    USE SIGNAL ;
    PORT
      LAYER M5 ;
        RECT  219.936 63.916 219.96 64 ;
    END
  END ks_data[235]
  PIN ks_data[236]
    DIRECTION OUTPUT ;
    USE SIGNAL ;
    PORT
      LAYER M5 ;
        RECT  220.032 63.916 220.056 64 ;
    END
  END ks_data[236]
  PIN ks_data[237]
    DIRECTION OUTPUT ;
    USE SIGNAL ;
    PORT
      LAYER M5 ;
        RECT  220.128 63.916 220.152 64 ;
    END
  END ks_data[237]
  PIN ks_data[238]
    DIRECTION OUTPUT ;
    USE SIGNAL ;
    PORT
      LAYER M5 ;
        RECT  220.224 63.916 220.248 64 ;
    END
  END ks_data[238]
  PIN ks_data[239]
    DIRECTION OUTPUT ;
    USE SIGNAL ;
    PORT
      LAYER M5 ;
        RECT  220.32 63.916 220.344 64 ;
    END
  END ks_data[239]
  PIN ks_data[23]
    DIRECTION OUTPUT ;
    USE SIGNAL ;
    PORT
      LAYER M5 ;
        RECT  199.584 63.916 199.608 64 ;
    END
  END ks_data[23]
  PIN ks_data[240]
    DIRECTION OUTPUT ;
    USE SIGNAL ;
    PORT
      LAYER M5 ;
        RECT  220.416 63.916 220.44 64 ;
    END
  END ks_data[240]
  PIN ks_data[241]
    DIRECTION OUTPUT ;
    USE SIGNAL ;
    PORT
      LAYER M5 ;
        RECT  220.512 63.916 220.536 64 ;
    END
  END ks_data[241]
  PIN ks_data[242]
    DIRECTION OUTPUT ;
    USE SIGNAL ;
    PORT
      LAYER M5 ;
        RECT  220.608 63.916 220.632 64 ;
    END
  END ks_data[242]
  PIN ks_data[243]
    DIRECTION OUTPUT ;
    USE SIGNAL ;
    PORT
      LAYER M5 ;
        RECT  220.704 63.916 220.728 64 ;
    END
  END ks_data[243]
  PIN ks_data[244]
    DIRECTION OUTPUT ;
    USE SIGNAL ;
    PORT
      LAYER M5 ;
        RECT  220.8 63.916 220.824 64 ;
    END
  END ks_data[244]
  PIN ks_data[245]
    DIRECTION OUTPUT ;
    USE SIGNAL ;
    PORT
      LAYER M5 ;
        RECT  220.896 63.916 220.92 64 ;
    END
  END ks_data[245]
  PIN ks_data[246]
    DIRECTION OUTPUT ;
    USE SIGNAL ;
    PORT
      LAYER M5 ;
        RECT  220.992 63.916 221.016 64 ;
    END
  END ks_data[246]
  PIN ks_data[247]
    DIRECTION OUTPUT ;
    USE SIGNAL ;
    PORT
      LAYER M5 ;
        RECT  221.088 63.916 221.112 64 ;
    END
  END ks_data[247]
  PIN ks_data[248]
    DIRECTION OUTPUT ;
    USE SIGNAL ;
    PORT
      LAYER M5 ;
        RECT  221.184 63.916 221.208 64 ;
    END
  END ks_data[248]
  PIN ks_data[249]
    DIRECTION OUTPUT ;
    USE SIGNAL ;
    PORT
      LAYER M5 ;
        RECT  221.28 63.916 221.304 64 ;
    END
  END ks_data[249]
  PIN ks_data[24]
    DIRECTION OUTPUT ;
    USE SIGNAL ;
    PORT
      LAYER M5 ;
        RECT  199.68 63.916 199.704 64 ;
    END
  END ks_data[24]
  PIN ks_data[250]
    DIRECTION OUTPUT ;
    USE SIGNAL ;
    PORT
      LAYER M5 ;
        RECT  221.376 63.916 221.4 64 ;
    END
  END ks_data[250]
  PIN ks_data[251]
    DIRECTION OUTPUT ;
    USE SIGNAL ;
    PORT
      LAYER M5 ;
        RECT  221.472 63.916 221.496 64 ;
    END
  END ks_data[251]
  PIN ks_data[252]
    DIRECTION OUTPUT ;
    USE SIGNAL ;
    PORT
      LAYER M5 ;
        RECT  221.568 63.916 221.592 64 ;
    END
  END ks_data[252]
  PIN ks_data[253]
    DIRECTION OUTPUT ;
    USE SIGNAL ;
    PORT
      LAYER M5 ;
        RECT  221.664 63.916 221.688 64 ;
    END
  END ks_data[253]
  PIN ks_data[254]
    DIRECTION OUTPUT ;
    USE SIGNAL ;
    PORT
      LAYER M5 ;
        RECT  221.76 63.916 221.784 64 ;
    END
  END ks_data[254]
  PIN ks_data[255]
    DIRECTION OUTPUT ;
    USE SIGNAL ;
    PORT
      LAYER M5 ;
        RECT  221.856 63.916 221.88 64 ;
    END
  END ks_data[255]
  PIN ks_data[25]
    DIRECTION OUTPUT ;
    USE SIGNAL ;
    PORT
      LAYER M5 ;
        RECT  199.776 63.916 199.8 64 ;
    END
  END ks_data[25]
  PIN ks_data[26]
    DIRECTION OUTPUT ;
    USE SIGNAL ;
    PORT
      LAYER M5 ;
        RECT  199.872 63.916 199.896 64 ;
    END
  END ks_data[26]
  PIN ks_data[27]
    DIRECTION OUTPUT ;
    USE SIGNAL ;
    PORT
      LAYER M5 ;
        RECT  199.968 63.916 199.992 64 ;
    END
  END ks_data[27]
  PIN ks_data[28]
    DIRECTION OUTPUT ;
    USE SIGNAL ;
    PORT
      LAYER M5 ;
        RECT  200.064 63.916 200.088 64 ;
    END
  END ks_data[28]
  PIN ks_data[29]
    DIRECTION OUTPUT ;
    USE SIGNAL ;
    PORT
      LAYER M5 ;
        RECT  200.16 63.916 200.184 64 ;
    END
  END ks_data[29]
  PIN ks_data[2]
    DIRECTION OUTPUT ;
    USE SIGNAL ;
    PORT
      LAYER M5 ;
        RECT  197.568 63.916 197.592 64 ;
    END
  END ks_data[2]
  PIN ks_data[30]
    DIRECTION OUTPUT ;
    USE SIGNAL ;
    PORT
      LAYER M5 ;
        RECT  200.256 63.916 200.28 64 ;
    END
  END ks_data[30]
  PIN ks_data[31]
    DIRECTION OUTPUT ;
    USE SIGNAL ;
    PORT
      LAYER M5 ;
        RECT  200.352 63.916 200.376 64 ;
    END
  END ks_data[31]
  PIN ks_data[32]
    DIRECTION OUTPUT ;
    USE SIGNAL ;
    PORT
      LAYER M5 ;
        RECT  200.448 63.916 200.472 64 ;
    END
  END ks_data[32]
  PIN ks_data[33]
    DIRECTION OUTPUT ;
    USE SIGNAL ;
    PORT
      LAYER M5 ;
        RECT  200.544 63.916 200.568 64 ;
    END
  END ks_data[33]
  PIN ks_data[34]
    DIRECTION OUTPUT ;
    USE SIGNAL ;
    PORT
      LAYER M5 ;
        RECT  200.64 63.916 200.664 64 ;
    END
  END ks_data[34]
  PIN ks_data[35]
    DIRECTION OUTPUT ;
    USE SIGNAL ;
    PORT
      LAYER M5 ;
        RECT  200.736 63.916 200.76 64 ;
    END
  END ks_data[35]
  PIN ks_data[36]
    DIRECTION OUTPUT ;
    USE SIGNAL ;
    PORT
      LAYER M5 ;
        RECT  200.832 63.916 200.856 64 ;
    END
  END ks_data[36]
  PIN ks_data[37]
    DIRECTION OUTPUT ;
    USE SIGNAL ;
    PORT
      LAYER M5 ;
        RECT  200.928 63.916 200.952 64 ;
    END
  END ks_data[37]
  PIN ks_data[38]
    DIRECTION OUTPUT ;
    USE SIGNAL ;
    PORT
      LAYER M5 ;
        RECT  201.024 63.916 201.048 64 ;
    END
  END ks_data[38]
  PIN ks_data[39]
    DIRECTION OUTPUT ;
    USE SIGNAL ;
    PORT
      LAYER M5 ;
        RECT  201.12 63.916 201.144 64 ;
    END
  END ks_data[39]
  PIN ks_data[3]
    DIRECTION OUTPUT ;
    USE SIGNAL ;
    PORT
      LAYER M5 ;
        RECT  197.664 63.916 197.688 64 ;
    END
  END ks_data[3]
  PIN ks_data[40]
    DIRECTION OUTPUT ;
    USE SIGNAL ;
    PORT
      LAYER M5 ;
        RECT  201.216 63.916 201.24 64 ;
    END
  END ks_data[40]
  PIN ks_data[41]
    DIRECTION OUTPUT ;
    USE SIGNAL ;
    PORT
      LAYER M5 ;
        RECT  201.312 63.916 201.336 64 ;
    END
  END ks_data[41]
  PIN ks_data[42]
    DIRECTION OUTPUT ;
    USE SIGNAL ;
    PORT
      LAYER M5 ;
        RECT  201.408 63.916 201.432 64 ;
    END
  END ks_data[42]
  PIN ks_data[43]
    DIRECTION OUTPUT ;
    USE SIGNAL ;
    PORT
      LAYER M5 ;
        RECT  201.504 63.916 201.528 64 ;
    END
  END ks_data[43]
  PIN ks_data[44]
    DIRECTION OUTPUT ;
    USE SIGNAL ;
    PORT
      LAYER M5 ;
        RECT  201.6 63.916 201.624 64 ;
    END
  END ks_data[44]
  PIN ks_data[45]
    DIRECTION OUTPUT ;
    USE SIGNAL ;
    PORT
      LAYER M5 ;
        RECT  201.696 63.916 201.72 64 ;
    END
  END ks_data[45]
  PIN ks_data[46]
    DIRECTION OUTPUT ;
    USE SIGNAL ;
    PORT
      LAYER M5 ;
        RECT  201.792 63.916 201.816 64 ;
    END
  END ks_data[46]
  PIN ks_data[47]
    DIRECTION OUTPUT ;
    USE SIGNAL ;
    PORT
      LAYER M5 ;
        RECT  201.888 63.916 201.912 64 ;
    END
  END ks_data[47]
  PIN ks_data[48]
    DIRECTION OUTPUT ;
    USE SIGNAL ;
    PORT
      LAYER M5 ;
        RECT  201.984 63.916 202.008 64 ;
    END
  END ks_data[48]
  PIN ks_data[49]
    DIRECTION OUTPUT ;
    USE SIGNAL ;
    PORT
      LAYER M5 ;
        RECT  202.08 63.916 202.104 64 ;
    END
  END ks_data[49]
  PIN ks_data[4]
    DIRECTION OUTPUT ;
    USE SIGNAL ;
    PORT
      LAYER M5 ;
        RECT  197.76 63.916 197.784 64 ;
    END
  END ks_data[4]
  PIN ks_data[50]
    DIRECTION OUTPUT ;
    USE SIGNAL ;
    PORT
      LAYER M5 ;
        RECT  202.176 63.916 202.2 64 ;
    END
  END ks_data[50]
  PIN ks_data[51]
    DIRECTION OUTPUT ;
    USE SIGNAL ;
    PORT
      LAYER M5 ;
        RECT  202.272 63.916 202.296 64 ;
    END
  END ks_data[51]
  PIN ks_data[52]
    DIRECTION OUTPUT ;
    USE SIGNAL ;
    PORT
      LAYER M5 ;
        RECT  202.368 63.916 202.392 64 ;
    END
  END ks_data[52]
  PIN ks_data[53]
    DIRECTION OUTPUT ;
    USE SIGNAL ;
    PORT
      LAYER M5 ;
        RECT  202.464 63.916 202.488 64 ;
    END
  END ks_data[53]
  PIN ks_data[54]
    DIRECTION OUTPUT ;
    USE SIGNAL ;
    PORT
      LAYER M5 ;
        RECT  202.56 63.916 202.584 64 ;
    END
  END ks_data[54]
  PIN ks_data[55]
    DIRECTION OUTPUT ;
    USE SIGNAL ;
    PORT
      LAYER M5 ;
        RECT  202.656 63.916 202.68 64 ;
    END
  END ks_data[55]
  PIN ks_data[56]
    DIRECTION OUTPUT ;
    USE SIGNAL ;
    PORT
      LAYER M5 ;
        RECT  202.752 63.916 202.776 64 ;
    END
  END ks_data[56]
  PIN ks_data[57]
    DIRECTION OUTPUT ;
    USE SIGNAL ;
    PORT
      LAYER M5 ;
        RECT  202.848 63.916 202.872 64 ;
    END
  END ks_data[57]
  PIN ks_data[58]
    DIRECTION OUTPUT ;
    USE SIGNAL ;
    PORT
      LAYER M5 ;
        RECT  202.944 63.916 202.968 64 ;
    END
  END ks_data[58]
  PIN ks_data[59]
    DIRECTION OUTPUT ;
    USE SIGNAL ;
    PORT
      LAYER M5 ;
        RECT  203.04 63.916 203.064 64 ;
    END
  END ks_data[59]
  PIN ks_data[5]
    DIRECTION OUTPUT ;
    USE SIGNAL ;
    PORT
      LAYER M5 ;
        RECT  197.856 63.916 197.88 64 ;
    END
  END ks_data[5]
  PIN ks_data[60]
    DIRECTION OUTPUT ;
    USE SIGNAL ;
    PORT
      LAYER M5 ;
        RECT  203.136 63.916 203.16 64 ;
    END
  END ks_data[60]
  PIN ks_data[61]
    DIRECTION OUTPUT ;
    USE SIGNAL ;
    PORT
      LAYER M5 ;
        RECT  203.232 63.916 203.256 64 ;
    END
  END ks_data[61]
  PIN ks_data[62]
    DIRECTION OUTPUT ;
    USE SIGNAL ;
    PORT
      LAYER M5 ;
        RECT  203.328 63.916 203.352 64 ;
    END
  END ks_data[62]
  PIN ks_data[63]
    DIRECTION OUTPUT ;
    USE SIGNAL ;
    PORT
      LAYER M5 ;
        RECT  203.424 63.916 203.448 64 ;
    END
  END ks_data[63]
  PIN ks_data[64]
    DIRECTION OUTPUT ;
    USE SIGNAL ;
    PORT
      LAYER M5 ;
        RECT  203.52 63.916 203.544 64 ;
    END
  END ks_data[64]
  PIN ks_data[65]
    DIRECTION OUTPUT ;
    USE SIGNAL ;
    PORT
      LAYER M5 ;
        RECT  203.616 63.916 203.64 64 ;
    END
  END ks_data[65]
  PIN ks_data[66]
    DIRECTION OUTPUT ;
    USE SIGNAL ;
    PORT
      LAYER M5 ;
        RECT  203.712 63.916 203.736 64 ;
    END
  END ks_data[66]
  PIN ks_data[67]
    DIRECTION OUTPUT ;
    USE SIGNAL ;
    PORT
      LAYER M5 ;
        RECT  203.808 63.916 203.832 64 ;
    END
  END ks_data[67]
  PIN ks_data[68]
    DIRECTION OUTPUT ;
    USE SIGNAL ;
    PORT
      LAYER M5 ;
        RECT  203.904 63.916 203.928 64 ;
    END
  END ks_data[68]
  PIN ks_data[69]
    DIRECTION OUTPUT ;
    USE SIGNAL ;
    PORT
      LAYER M5 ;
        RECT  204 63.916 204.024 64 ;
    END
  END ks_data[69]
  PIN ks_data[6]
    DIRECTION OUTPUT ;
    USE SIGNAL ;
    PORT
      LAYER M5 ;
        RECT  197.952 63.916 197.976 64 ;
    END
  END ks_data[6]
  PIN ks_data[70]
    DIRECTION OUTPUT ;
    USE SIGNAL ;
    PORT
      LAYER M5 ;
        RECT  204.096 63.916 204.12 64 ;
    END
  END ks_data[70]
  PIN ks_data[71]
    DIRECTION OUTPUT ;
    USE SIGNAL ;
    PORT
      LAYER M5 ;
        RECT  204.192 63.916 204.216 64 ;
    END
  END ks_data[71]
  PIN ks_data[72]
    DIRECTION OUTPUT ;
    USE SIGNAL ;
    PORT
      LAYER M5 ;
        RECT  204.288 63.916 204.312 64 ;
    END
  END ks_data[72]
  PIN ks_data[73]
    DIRECTION OUTPUT ;
    USE SIGNAL ;
    PORT
      LAYER M5 ;
        RECT  204.384 63.916 204.408 64 ;
    END
  END ks_data[73]
  PIN ks_data[74]
    DIRECTION OUTPUT ;
    USE SIGNAL ;
    PORT
      LAYER M5 ;
        RECT  204.48 63.916 204.504 64 ;
    END
  END ks_data[74]
  PIN ks_data[75]
    DIRECTION OUTPUT ;
    USE SIGNAL ;
    PORT
      LAYER M5 ;
        RECT  204.576 63.916 204.6 64 ;
    END
  END ks_data[75]
  PIN ks_data[76]
    DIRECTION OUTPUT ;
    USE SIGNAL ;
    PORT
      LAYER M5 ;
        RECT  204.672 63.916 204.696 64 ;
    END
  END ks_data[76]
  PIN ks_data[77]
    DIRECTION OUTPUT ;
    USE SIGNAL ;
    PORT
      LAYER M5 ;
        RECT  204.768 63.916 204.792 64 ;
    END
  END ks_data[77]
  PIN ks_data[78]
    DIRECTION OUTPUT ;
    USE SIGNAL ;
    PORT
      LAYER M5 ;
        RECT  204.864 63.916 204.888 64 ;
    END
  END ks_data[78]
  PIN ks_data[79]
    DIRECTION OUTPUT ;
    USE SIGNAL ;
    PORT
      LAYER M5 ;
        RECT  204.96 63.916 204.984 64 ;
    END
  END ks_data[79]
  PIN ks_data[7]
    DIRECTION OUTPUT ;
    USE SIGNAL ;
    PORT
      LAYER M5 ;
        RECT  198.048 63.916 198.072 64 ;
    END
  END ks_data[7]
  PIN ks_data[80]
    DIRECTION OUTPUT ;
    USE SIGNAL ;
    PORT
      LAYER M5 ;
        RECT  205.056 63.916 205.08 64 ;
    END
  END ks_data[80]
  PIN ks_data[81]
    DIRECTION OUTPUT ;
    USE SIGNAL ;
    PORT
      LAYER M5 ;
        RECT  205.152 63.916 205.176 64 ;
    END
  END ks_data[81]
  PIN ks_data[82]
    DIRECTION OUTPUT ;
    USE SIGNAL ;
    PORT
      LAYER M5 ;
        RECT  205.248 63.916 205.272 64 ;
    END
  END ks_data[82]
  PIN ks_data[83]
    DIRECTION OUTPUT ;
    USE SIGNAL ;
    PORT
      LAYER M5 ;
        RECT  205.344 63.916 205.368 64 ;
    END
  END ks_data[83]
  PIN ks_data[84]
    DIRECTION OUTPUT ;
    USE SIGNAL ;
    PORT
      LAYER M5 ;
        RECT  205.44 63.916 205.464 64 ;
    END
  END ks_data[84]
  PIN ks_data[85]
    DIRECTION OUTPUT ;
    USE SIGNAL ;
    PORT
      LAYER M5 ;
        RECT  205.536 63.916 205.56 64 ;
    END
  END ks_data[85]
  PIN ks_data[86]
    DIRECTION OUTPUT ;
    USE SIGNAL ;
    PORT
      LAYER M5 ;
        RECT  205.632 63.916 205.656 64 ;
    END
  END ks_data[86]
  PIN ks_data[87]
    DIRECTION OUTPUT ;
    USE SIGNAL ;
    PORT
      LAYER M5 ;
        RECT  205.728 63.916 205.752 64 ;
    END
  END ks_data[87]
  PIN ks_data[88]
    DIRECTION OUTPUT ;
    USE SIGNAL ;
    PORT
      LAYER M5 ;
        RECT  205.824 63.916 205.848 64 ;
    END
  END ks_data[88]
  PIN ks_data[89]
    DIRECTION OUTPUT ;
    USE SIGNAL ;
    PORT
      LAYER M5 ;
        RECT  205.92 63.916 205.944 64 ;
    END
  END ks_data[89]
  PIN ks_data[8]
    DIRECTION OUTPUT ;
    USE SIGNAL ;
    PORT
      LAYER M5 ;
        RECT  198.144 63.916 198.168 64 ;
    END
  END ks_data[8]
  PIN ks_data[90]
    DIRECTION OUTPUT ;
    USE SIGNAL ;
    PORT
      LAYER M5 ;
        RECT  206.016 63.916 206.04 64 ;
    END
  END ks_data[90]
  PIN ks_data[91]
    DIRECTION OUTPUT ;
    USE SIGNAL ;
    PORT
      LAYER M5 ;
        RECT  206.112 63.916 206.136 64 ;
    END
  END ks_data[91]
  PIN ks_data[92]
    DIRECTION OUTPUT ;
    USE SIGNAL ;
    PORT
      LAYER M5 ;
        RECT  206.208 63.916 206.232 64 ;
    END
  END ks_data[92]
  PIN ks_data[93]
    DIRECTION OUTPUT ;
    USE SIGNAL ;
    PORT
      LAYER M5 ;
        RECT  206.304 63.916 206.328 64 ;
    END
  END ks_data[93]
  PIN ks_data[94]
    DIRECTION OUTPUT ;
    USE SIGNAL ;
    PORT
      LAYER M5 ;
        RECT  206.4 63.916 206.424 64 ;
    END
  END ks_data[94]
  PIN ks_data[95]
    DIRECTION OUTPUT ;
    USE SIGNAL ;
    PORT
      LAYER M5 ;
        RECT  206.496 63.916 206.52 64 ;
    END
  END ks_data[95]
  PIN ks_data[96]
    DIRECTION OUTPUT ;
    USE SIGNAL ;
    PORT
      LAYER M5 ;
        RECT  206.592 63.916 206.616 64 ;
    END
  END ks_data[96]
  PIN ks_data[97]
    DIRECTION OUTPUT ;
    USE SIGNAL ;
    PORT
      LAYER M5 ;
        RECT  206.688 63.916 206.712 64 ;
    END
  END ks_data[97]
  PIN ks_data[98]
    DIRECTION OUTPUT ;
    USE SIGNAL ;
    PORT
      LAYER M5 ;
        RECT  206.784 63.916 206.808 64 ;
    END
  END ks_data[98]
  PIN ks_data[99]
    DIRECTION OUTPUT ;
    USE SIGNAL ;
    PORT
      LAYER M5 ;
        RECT  206.88 63.916 206.904 64 ;
    END
  END ks_data[99]
  PIN ks_data[9]
    DIRECTION OUTPUT ;
    USE SIGNAL ;
    PORT
      LAYER M5 ;
        RECT  198.24 63.916 198.264 64 ;
    END
  END ks_data[9]
  PIN ks_tag[0]
    DIRECTION OUTPUT ;
    USE SIGNAL ;
    PORT
      LAYER M5 ;
        RECT  221.952 63.916 221.976 64 ;
    END
  END ks_tag[0]
  PIN ks_tag[10]
    DIRECTION OUTPUT ;
    USE SIGNAL ;
    PORT
      LAYER M5 ;
        RECT  222.912 63.916 222.936 64 ;
    END
  END ks_tag[10]
  PIN ks_tag[11]
    DIRECTION OUTPUT ;
    USE SIGNAL ;
    PORT
      LAYER M5 ;
        RECT  223.008 63.916 223.032 64 ;
    END
  END ks_tag[11]
  PIN ks_tag[12]
    DIRECTION OUTPUT ;
    USE SIGNAL ;
    PORT
      LAYER M5 ;
        RECT  223.104 63.916 223.128 64 ;
    END
  END ks_tag[12]
  PIN ks_tag[13]
    DIRECTION OUTPUT ;
    USE SIGNAL ;
    PORT
      LAYER M5 ;
        RECT  223.2 63.916 223.224 64 ;
    END
  END ks_tag[13]
  PIN ks_tag[14]
    DIRECTION OUTPUT ;
    USE SIGNAL ;
    PORT
      LAYER M5 ;
        RECT  223.296 63.916 223.32 64 ;
    END
  END ks_tag[14]
  PIN ks_tag[15]
    DIRECTION OUTPUT ;
    USE SIGNAL ;
    PORT
      LAYER M5 ;
        RECT  223.392 63.916 223.416 64 ;
    END
  END ks_tag[15]
  PIN ks_tag[1]
    DIRECTION OUTPUT ;
    USE SIGNAL ;
    PORT
      LAYER M5 ;
        RECT  222.048 63.916 222.072 64 ;
    END
  END ks_tag[1]
  PIN ks_tag[2]
    DIRECTION OUTPUT ;
    USE SIGNAL ;
    PORT
      LAYER M5 ;
        RECT  222.144 63.916 222.168 64 ;
    END
  END ks_tag[2]
  PIN ks_tag[3]
    DIRECTION OUTPUT ;
    USE SIGNAL ;
    PORT
      LAYER M5 ;
        RECT  222.24 63.916 222.264 64 ;
    END
  END ks_tag[3]
  PIN ks_tag[4]
    DIRECTION OUTPUT ;
    USE SIGNAL ;
    PORT
      LAYER M5 ;
        RECT  222.336 63.916 222.36 64 ;
    END
  END ks_tag[4]
  PIN ks_tag[5]
    DIRECTION OUTPUT ;
    USE SIGNAL ;
    PORT
      LAYER M5 ;
        RECT  222.432 63.916 222.456 64 ;
    END
  END ks_tag[5]
  PIN ks_tag[6]
    DIRECTION OUTPUT ;
    USE SIGNAL ;
    PORT
      LAYER M5 ;
        RECT  222.528 63.916 222.552 64 ;
    END
  END ks_tag[6]
  PIN ks_tag[7]
    DIRECTION OUTPUT ;
    USE SIGNAL ;
    PORT
      LAYER M5 ;
        RECT  222.624 63.916 222.648 64 ;
    END
  END ks_tag[7]
  PIN ks_tag[8]
    DIRECTION OUTPUT ;
    USE SIGNAL ;
    PORT
      LAYER M5 ;
        RECT  222.72 63.916 222.744 64 ;
    END
  END ks_tag[8]
  PIN ks_tag[9]
    DIRECTION OUTPUT ;
    USE SIGNAL ;
    PORT
      LAYER M5 ;
        RECT  222.816 63.916 222.84 64 ;
    END
  END ks_tag[9]
  PIN ks_v
    DIRECTION OUTPUT ;
    USE SIGNAL ;
    PORT
      LAYER M5 ;
        RECT  223.488 63.916 223.512 64 ;
    END
  END ks_v
  PIN r_beat[0]
    DIRECTION INPUT ;
    USE SIGNAL ;
    PORT
      LAYER M5 ;
        RECT  63.648 0 63.672 0.084 ;
    END
  END r_beat[0]
  PIN r_beat[1]
    DIRECTION INPUT ;
    USE SIGNAL ;
    PORT
      LAYER M5 ;
        RECT  63.744 0 63.768 0.084 ;
    END
  END r_beat[1]
  PIN r_beat[2]
    DIRECTION INPUT ;
    USE SIGNAL ;
    PORT
      LAYER M5 ;
        RECT  63.84 0 63.864 0.084 ;
    END
  END r_beat[2]
  PIN r_beat[3]
    DIRECTION INPUT ;
    USE SIGNAL ;
    PORT
      LAYER M5 ;
        RECT  63.936 0 63.96 0.084 ;
    END
  END r_beat[3]
  PIN r_data[0]
    DIRECTION INPUT ;
    USE SIGNAL ;
    PORT
      LAYER M5 ;
        RECT  64.032 0 64.056 0.084 ;
    END
  END r_data[0]
  PIN r_data[100]
    DIRECTION INPUT ;
    USE SIGNAL ;
    PORT
      LAYER M5 ;
        RECT  73.632 0 73.656 0.084 ;
    END
  END r_data[100]
  PIN r_data[101]
    DIRECTION INPUT ;
    USE SIGNAL ;
    PORT
      LAYER M5 ;
        RECT  73.728 0 73.752 0.084 ;
    END
  END r_data[101]
  PIN r_data[102]
    DIRECTION INPUT ;
    USE SIGNAL ;
    PORT
      LAYER M5 ;
        RECT  73.824 0 73.848 0.084 ;
    END
  END r_data[102]
  PIN r_data[103]
    DIRECTION INPUT ;
    USE SIGNAL ;
    PORT
      LAYER M5 ;
        RECT  73.92 0 73.944 0.084 ;
    END
  END r_data[103]
  PIN r_data[104]
    DIRECTION INPUT ;
    USE SIGNAL ;
    PORT
      LAYER M5 ;
        RECT  74.016 0 74.04 0.084 ;
    END
  END r_data[104]
  PIN r_data[105]
    DIRECTION INPUT ;
    USE SIGNAL ;
    PORT
      LAYER M5 ;
        RECT  74.112 0 74.136 0.084 ;
    END
  END r_data[105]
  PIN r_data[106]
    DIRECTION INPUT ;
    USE SIGNAL ;
    PORT
      LAYER M5 ;
        RECT  74.208 0 74.232 0.084 ;
    END
  END r_data[106]
  PIN r_data[107]
    DIRECTION INPUT ;
    USE SIGNAL ;
    PORT
      LAYER M5 ;
        RECT  74.304 0 74.328 0.084 ;
    END
  END r_data[107]
  PIN r_data[108]
    DIRECTION INPUT ;
    USE SIGNAL ;
    PORT
      LAYER M5 ;
        RECT  74.4 0 74.424 0.084 ;
    END
  END r_data[108]
  PIN r_data[109]
    DIRECTION INPUT ;
    USE SIGNAL ;
    PORT
      LAYER M5 ;
        RECT  74.496 0 74.52 0.084 ;
    END
  END r_data[109]
  PIN r_data[10]
    DIRECTION INPUT ;
    USE SIGNAL ;
    PORT
      LAYER M5 ;
        RECT  64.992 0 65.016 0.084 ;
    END
  END r_data[10]
  PIN r_data[110]
    DIRECTION INPUT ;
    USE SIGNAL ;
    PORT
      LAYER M5 ;
        RECT  74.592 0 74.616 0.084 ;
    END
  END r_data[110]
  PIN r_data[111]
    DIRECTION INPUT ;
    USE SIGNAL ;
    PORT
      LAYER M5 ;
        RECT  74.688 0 74.712 0.084 ;
    END
  END r_data[111]
  PIN r_data[112]
    DIRECTION INPUT ;
    USE SIGNAL ;
    PORT
      LAYER M5 ;
        RECT  74.784 0 74.808 0.084 ;
    END
  END r_data[112]
  PIN r_data[113]
    DIRECTION INPUT ;
    USE SIGNAL ;
    PORT
      LAYER M5 ;
        RECT  74.88 0 74.904 0.084 ;
    END
  END r_data[113]
  PIN r_data[114]
    DIRECTION INPUT ;
    USE SIGNAL ;
    PORT
      LAYER M5 ;
        RECT  74.976 0 75 0.084 ;
    END
  END r_data[114]
  PIN r_data[115]
    DIRECTION INPUT ;
    USE SIGNAL ;
    PORT
      LAYER M5 ;
        RECT  75.072 0 75.096 0.084 ;
    END
  END r_data[115]
  PIN r_data[116]
    DIRECTION INPUT ;
    USE SIGNAL ;
    PORT
      LAYER M5 ;
        RECT  75.168 0 75.192 0.084 ;
    END
  END r_data[116]
  PIN r_data[117]
    DIRECTION INPUT ;
    USE SIGNAL ;
    PORT
      LAYER M5 ;
        RECT  75.264 0 75.288 0.084 ;
    END
  END r_data[117]
  PIN r_data[118]
    DIRECTION INPUT ;
    USE SIGNAL ;
    PORT
      LAYER M5 ;
        RECT  75.36 0 75.384 0.084 ;
    END
  END r_data[118]
  PIN r_data[119]
    DIRECTION INPUT ;
    USE SIGNAL ;
    PORT
      LAYER M5 ;
        RECT  75.456 0 75.48 0.084 ;
    END
  END r_data[119]
  PIN r_data[11]
    DIRECTION INPUT ;
    USE SIGNAL ;
    PORT
      LAYER M5 ;
        RECT  65.088 0 65.112 0.084 ;
    END
  END r_data[11]
  PIN r_data[120]
    DIRECTION INPUT ;
    USE SIGNAL ;
    PORT
      LAYER M5 ;
        RECT  75.552 0 75.576 0.084 ;
    END
  END r_data[120]
  PIN r_data[121]
    DIRECTION INPUT ;
    USE SIGNAL ;
    PORT
      LAYER M5 ;
        RECT  75.648 0 75.672 0.084 ;
    END
  END r_data[121]
  PIN r_data[122]
    DIRECTION INPUT ;
    USE SIGNAL ;
    PORT
      LAYER M5 ;
        RECT  75.744 0 75.768 0.084 ;
    END
  END r_data[122]
  PIN r_data[123]
    DIRECTION INPUT ;
    USE SIGNAL ;
    PORT
      LAYER M5 ;
        RECT  75.84 0 75.864 0.084 ;
    END
  END r_data[123]
  PIN r_data[124]
    DIRECTION INPUT ;
    USE SIGNAL ;
    PORT
      LAYER M5 ;
        RECT  75.936 0 75.96 0.084 ;
    END
  END r_data[124]
  PIN r_data[125]
    DIRECTION INPUT ;
    USE SIGNAL ;
    PORT
      LAYER M5 ;
        RECT  76.032 0 76.056 0.084 ;
    END
  END r_data[125]
  PIN r_data[126]
    DIRECTION INPUT ;
    USE SIGNAL ;
    PORT
      LAYER M5 ;
        RECT  76.128 0 76.152 0.084 ;
    END
  END r_data[126]
  PIN r_data[127]
    DIRECTION INPUT ;
    USE SIGNAL ;
    PORT
      LAYER M5 ;
        RECT  76.224 0 76.248 0.084 ;
    END
  END r_data[127]
  PIN r_data[128]
    DIRECTION INPUT ;
    USE SIGNAL ;
    PORT
      LAYER M5 ;
        RECT  76.32 0 76.344 0.084 ;
    END
  END r_data[128]
  PIN r_data[129]
    DIRECTION INPUT ;
    USE SIGNAL ;
    PORT
      LAYER M5 ;
        RECT  76.416 0 76.44 0.084 ;
    END
  END r_data[129]
  PIN r_data[12]
    DIRECTION INPUT ;
    USE SIGNAL ;
    PORT
      LAYER M5 ;
        RECT  65.184 0 65.208 0.084 ;
    END
  END r_data[12]
  PIN r_data[130]
    DIRECTION INPUT ;
    USE SIGNAL ;
    PORT
      LAYER M5 ;
        RECT  76.512 0 76.536 0.084 ;
    END
  END r_data[130]
  PIN r_data[131]
    DIRECTION INPUT ;
    USE SIGNAL ;
    PORT
      LAYER M5 ;
        RECT  76.608 0 76.632 0.084 ;
    END
  END r_data[131]
  PIN r_data[132]
    DIRECTION INPUT ;
    USE SIGNAL ;
    PORT
      LAYER M5 ;
        RECT  76.704 0 76.728 0.084 ;
    END
  END r_data[132]
  PIN r_data[133]
    DIRECTION INPUT ;
    USE SIGNAL ;
    PORT
      LAYER M5 ;
        RECT  76.8 0 76.824 0.084 ;
    END
  END r_data[133]
  PIN r_data[134]
    DIRECTION INPUT ;
    USE SIGNAL ;
    PORT
      LAYER M5 ;
        RECT  76.896 0 76.92 0.084 ;
    END
  END r_data[134]
  PIN r_data[135]
    DIRECTION INPUT ;
    USE SIGNAL ;
    PORT
      LAYER M5 ;
        RECT  76.992 0 77.016 0.084 ;
    END
  END r_data[135]
  PIN r_data[136]
    DIRECTION INPUT ;
    USE SIGNAL ;
    PORT
      LAYER M5 ;
        RECT  77.088 0 77.112 0.084 ;
    END
  END r_data[136]
  PIN r_data[137]
    DIRECTION INPUT ;
    USE SIGNAL ;
    PORT
      LAYER M5 ;
        RECT  77.184 0 77.208 0.084 ;
    END
  END r_data[137]
  PIN r_data[138]
    DIRECTION INPUT ;
    USE SIGNAL ;
    PORT
      LAYER M5 ;
        RECT  77.28 0 77.304 0.084 ;
    END
  END r_data[138]
  PIN r_data[139]
    DIRECTION INPUT ;
    USE SIGNAL ;
    PORT
      LAYER M5 ;
        RECT  77.376 0 77.4 0.084 ;
    END
  END r_data[139]
  PIN r_data[13]
    DIRECTION INPUT ;
    USE SIGNAL ;
    PORT
      LAYER M5 ;
        RECT  65.28 0 65.304 0.084 ;
    END
  END r_data[13]
  PIN r_data[140]
    DIRECTION INPUT ;
    USE SIGNAL ;
    PORT
      LAYER M5 ;
        RECT  77.472 0 77.496 0.084 ;
    END
  END r_data[140]
  PIN r_data[141]
    DIRECTION INPUT ;
    USE SIGNAL ;
    PORT
      LAYER M5 ;
        RECT  77.568 0 77.592 0.084 ;
    END
  END r_data[141]
  PIN r_data[142]
    DIRECTION INPUT ;
    USE SIGNAL ;
    PORT
      LAYER M5 ;
        RECT  77.664 0 77.688 0.084 ;
    END
  END r_data[142]
  PIN r_data[143]
    DIRECTION INPUT ;
    USE SIGNAL ;
    PORT
      LAYER M5 ;
        RECT  77.76 0 77.784 0.084 ;
    END
  END r_data[143]
  PIN r_data[144]
    DIRECTION INPUT ;
    USE SIGNAL ;
    PORT
      LAYER M5 ;
        RECT  77.856 0 77.88 0.084 ;
    END
  END r_data[144]
  PIN r_data[145]
    DIRECTION INPUT ;
    USE SIGNAL ;
    PORT
      LAYER M5 ;
        RECT  77.952 0 77.976 0.084 ;
    END
  END r_data[145]
  PIN r_data[146]
    DIRECTION INPUT ;
    USE SIGNAL ;
    PORT
      LAYER M5 ;
        RECT  78.048 0 78.072 0.084 ;
    END
  END r_data[146]
  PIN r_data[147]
    DIRECTION INPUT ;
    USE SIGNAL ;
    PORT
      LAYER M5 ;
        RECT  78.144 0 78.168 0.084 ;
    END
  END r_data[147]
  PIN r_data[148]
    DIRECTION INPUT ;
    USE SIGNAL ;
    PORT
      LAYER M5 ;
        RECT  78.24 0 78.264 0.084 ;
    END
  END r_data[148]
  PIN r_data[149]
    DIRECTION INPUT ;
    USE SIGNAL ;
    PORT
      LAYER M5 ;
        RECT  78.336 0 78.36 0.084 ;
    END
  END r_data[149]
  PIN r_data[14]
    DIRECTION INPUT ;
    USE SIGNAL ;
    PORT
      LAYER M5 ;
        RECT  65.376 0 65.4 0.084 ;
    END
  END r_data[14]
  PIN r_data[150]
    DIRECTION INPUT ;
    USE SIGNAL ;
    PORT
      LAYER M5 ;
        RECT  78.432 0 78.456 0.084 ;
    END
  END r_data[150]
  PIN r_data[151]
    DIRECTION INPUT ;
    USE SIGNAL ;
    PORT
      LAYER M5 ;
        RECT  78.528 0 78.552 0.084 ;
    END
  END r_data[151]
  PIN r_data[152]
    DIRECTION INPUT ;
    USE SIGNAL ;
    PORT
      LAYER M5 ;
        RECT  78.624 0 78.648 0.084 ;
    END
  END r_data[152]
  PIN r_data[153]
    DIRECTION INPUT ;
    USE SIGNAL ;
    PORT
      LAYER M5 ;
        RECT  78.72 0 78.744 0.084 ;
    END
  END r_data[153]
  PIN r_data[154]
    DIRECTION INPUT ;
    USE SIGNAL ;
    PORT
      LAYER M5 ;
        RECT  78.816 0 78.84 0.084 ;
    END
  END r_data[154]
  PIN r_data[155]
    DIRECTION INPUT ;
    USE SIGNAL ;
    PORT
      LAYER M5 ;
        RECT  78.912 0 78.936 0.084 ;
    END
  END r_data[155]
  PIN r_data[156]
    DIRECTION INPUT ;
    USE SIGNAL ;
    PORT
      LAYER M5 ;
        RECT  79.008 0 79.032 0.084 ;
    END
  END r_data[156]
  PIN r_data[157]
    DIRECTION INPUT ;
    USE SIGNAL ;
    PORT
      LAYER M5 ;
        RECT  79.104 0 79.128 0.084 ;
    END
  END r_data[157]
  PIN r_data[158]
    DIRECTION INPUT ;
    USE SIGNAL ;
    PORT
      LAYER M5 ;
        RECT  79.2 0 79.224 0.084 ;
    END
  END r_data[158]
  PIN r_data[159]
    DIRECTION INPUT ;
    USE SIGNAL ;
    PORT
      LAYER M5 ;
        RECT  79.296 0 79.32 0.084 ;
    END
  END r_data[159]
  PIN r_data[15]
    DIRECTION INPUT ;
    USE SIGNAL ;
    PORT
      LAYER M5 ;
        RECT  65.472 0 65.496 0.084 ;
    END
  END r_data[15]
  PIN r_data[160]
    DIRECTION INPUT ;
    USE SIGNAL ;
    PORT
      LAYER M5 ;
        RECT  79.392 0 79.416 0.084 ;
    END
  END r_data[160]
  PIN r_data[161]
    DIRECTION INPUT ;
    USE SIGNAL ;
    PORT
      LAYER M5 ;
        RECT  79.488 0 79.512 0.084 ;
    END
  END r_data[161]
  PIN r_data[162]
    DIRECTION INPUT ;
    USE SIGNAL ;
    PORT
      LAYER M5 ;
        RECT  79.584 0 79.608 0.084 ;
    END
  END r_data[162]
  PIN r_data[163]
    DIRECTION INPUT ;
    USE SIGNAL ;
    PORT
      LAYER M5 ;
        RECT  79.68 0 79.704 0.084 ;
    END
  END r_data[163]
  PIN r_data[164]
    DIRECTION INPUT ;
    USE SIGNAL ;
    PORT
      LAYER M5 ;
        RECT  79.776 0 79.8 0.084 ;
    END
  END r_data[164]
  PIN r_data[165]
    DIRECTION INPUT ;
    USE SIGNAL ;
    PORT
      LAYER M5 ;
        RECT  79.872 0 79.896 0.084 ;
    END
  END r_data[165]
  PIN r_data[166]
    DIRECTION INPUT ;
    USE SIGNAL ;
    PORT
      LAYER M5 ;
        RECT  79.968 0 79.992 0.084 ;
    END
  END r_data[166]
  PIN r_data[167]
    DIRECTION INPUT ;
    USE SIGNAL ;
    PORT
      LAYER M5 ;
        RECT  80.064 0 80.088 0.084 ;
    END
  END r_data[167]
  PIN r_data[168]
    DIRECTION INPUT ;
    USE SIGNAL ;
    PORT
      LAYER M5 ;
        RECT  80.16 0 80.184 0.084 ;
    END
  END r_data[168]
  PIN r_data[169]
    DIRECTION INPUT ;
    USE SIGNAL ;
    PORT
      LAYER M5 ;
        RECT  80.256 0 80.28 0.084 ;
    END
  END r_data[169]
  PIN r_data[16]
    DIRECTION INPUT ;
    USE SIGNAL ;
    PORT
      LAYER M5 ;
        RECT  65.568 0 65.592 0.084 ;
    END
  END r_data[16]
  PIN r_data[170]
    DIRECTION INPUT ;
    USE SIGNAL ;
    PORT
      LAYER M5 ;
        RECT  80.352 0 80.376 0.084 ;
    END
  END r_data[170]
  PIN r_data[171]
    DIRECTION INPUT ;
    USE SIGNAL ;
    PORT
      LAYER M5 ;
        RECT  80.448 0 80.472 0.084 ;
    END
  END r_data[171]
  PIN r_data[172]
    DIRECTION INPUT ;
    USE SIGNAL ;
    PORT
      LAYER M5 ;
        RECT  80.544 0 80.568 0.084 ;
    END
  END r_data[172]
  PIN r_data[173]
    DIRECTION INPUT ;
    USE SIGNAL ;
    PORT
      LAYER M5 ;
        RECT  80.64 0 80.664 0.084 ;
    END
  END r_data[173]
  PIN r_data[174]
    DIRECTION INPUT ;
    USE SIGNAL ;
    PORT
      LAYER M5 ;
        RECT  80.736 0 80.76 0.084 ;
    END
  END r_data[174]
  PIN r_data[175]
    DIRECTION INPUT ;
    USE SIGNAL ;
    PORT
      LAYER M5 ;
        RECT  80.832 0 80.856 0.084 ;
    END
  END r_data[175]
  PIN r_data[176]
    DIRECTION INPUT ;
    USE SIGNAL ;
    PORT
      LAYER M5 ;
        RECT  80.928 0 80.952 0.084 ;
    END
  END r_data[176]
  PIN r_data[177]
    DIRECTION INPUT ;
    USE SIGNAL ;
    PORT
      LAYER M5 ;
        RECT  81.024 0 81.048 0.084 ;
    END
  END r_data[177]
  PIN r_data[178]
    DIRECTION INPUT ;
    USE SIGNAL ;
    PORT
      LAYER M5 ;
        RECT  81.12 0 81.144 0.084 ;
    END
  END r_data[178]
  PIN r_data[179]
    DIRECTION INPUT ;
    USE SIGNAL ;
    PORT
      LAYER M5 ;
        RECT  81.216 0 81.24 0.084 ;
    END
  END r_data[179]
  PIN r_data[17]
    DIRECTION INPUT ;
    USE SIGNAL ;
    PORT
      LAYER M5 ;
        RECT  65.664 0 65.688 0.084 ;
    END
  END r_data[17]
  PIN r_data[180]
    DIRECTION INPUT ;
    USE SIGNAL ;
    PORT
      LAYER M5 ;
        RECT  81.312 0 81.336 0.084 ;
    END
  END r_data[180]
  PIN r_data[181]
    DIRECTION INPUT ;
    USE SIGNAL ;
    PORT
      LAYER M5 ;
        RECT  81.408 0 81.432 0.084 ;
    END
  END r_data[181]
  PIN r_data[182]
    DIRECTION INPUT ;
    USE SIGNAL ;
    PORT
      LAYER M5 ;
        RECT  81.504 0 81.528 0.084 ;
    END
  END r_data[182]
  PIN r_data[183]
    DIRECTION INPUT ;
    USE SIGNAL ;
    PORT
      LAYER M5 ;
        RECT  81.6 0 81.624 0.084 ;
    END
  END r_data[183]
  PIN r_data[184]
    DIRECTION INPUT ;
    USE SIGNAL ;
    PORT
      LAYER M5 ;
        RECT  81.696 0 81.72 0.084 ;
    END
  END r_data[184]
  PIN r_data[185]
    DIRECTION INPUT ;
    USE SIGNAL ;
    PORT
      LAYER M5 ;
        RECT  81.792 0 81.816 0.084 ;
    END
  END r_data[185]
  PIN r_data[186]
    DIRECTION INPUT ;
    USE SIGNAL ;
    PORT
      LAYER M5 ;
        RECT  81.888 0 81.912 0.084 ;
    END
  END r_data[186]
  PIN r_data[187]
    DIRECTION INPUT ;
    USE SIGNAL ;
    PORT
      LAYER M5 ;
        RECT  81.984 0 82.008 0.084 ;
    END
  END r_data[187]
  PIN r_data[188]
    DIRECTION INPUT ;
    USE SIGNAL ;
    PORT
      LAYER M5 ;
        RECT  82.08 0 82.104 0.084 ;
    END
  END r_data[188]
  PIN r_data[189]
    DIRECTION INPUT ;
    USE SIGNAL ;
    PORT
      LAYER M5 ;
        RECT  82.176 0 82.2 0.084 ;
    END
  END r_data[189]
  PIN r_data[18]
    DIRECTION INPUT ;
    USE SIGNAL ;
    PORT
      LAYER M5 ;
        RECT  65.76 0 65.784 0.084 ;
    END
  END r_data[18]
  PIN r_data[190]
    DIRECTION INPUT ;
    USE SIGNAL ;
    PORT
      LAYER M5 ;
        RECT  82.272 0 82.296 0.084 ;
    END
  END r_data[190]
  PIN r_data[191]
    DIRECTION INPUT ;
    USE SIGNAL ;
    PORT
      LAYER M5 ;
        RECT  82.368 0 82.392 0.084 ;
    END
  END r_data[191]
  PIN r_data[192]
    DIRECTION INPUT ;
    USE SIGNAL ;
    PORT
      LAYER M5 ;
        RECT  82.464 0 82.488 0.084 ;
    END
  END r_data[192]
  PIN r_data[193]
    DIRECTION INPUT ;
    USE SIGNAL ;
    PORT
      LAYER M5 ;
        RECT  82.56 0 82.584 0.084 ;
    END
  END r_data[193]
  PIN r_data[194]
    DIRECTION INPUT ;
    USE SIGNAL ;
    PORT
      LAYER M5 ;
        RECT  82.656 0 82.68 0.084 ;
    END
  END r_data[194]
  PIN r_data[195]
    DIRECTION INPUT ;
    USE SIGNAL ;
    PORT
      LAYER M5 ;
        RECT  82.752 0 82.776 0.084 ;
    END
  END r_data[195]
  PIN r_data[196]
    DIRECTION INPUT ;
    USE SIGNAL ;
    PORT
      LAYER M5 ;
        RECT  82.848 0 82.872 0.084 ;
    END
  END r_data[196]
  PIN r_data[197]
    DIRECTION INPUT ;
    USE SIGNAL ;
    PORT
      LAYER M5 ;
        RECT  82.944 0 82.968 0.084 ;
    END
  END r_data[197]
  PIN r_data[198]
    DIRECTION INPUT ;
    USE SIGNAL ;
    PORT
      LAYER M5 ;
        RECT  83.04 0 83.064 0.084 ;
    END
  END r_data[198]
  PIN r_data[199]
    DIRECTION INPUT ;
    USE SIGNAL ;
    PORT
      LAYER M5 ;
        RECT  83.136 0 83.16 0.084 ;
    END
  END r_data[199]
  PIN r_data[19]
    DIRECTION INPUT ;
    USE SIGNAL ;
    PORT
      LAYER M5 ;
        RECT  65.856 0 65.88 0.084 ;
    END
  END r_data[19]
  PIN r_data[1]
    DIRECTION INPUT ;
    USE SIGNAL ;
    PORT
      LAYER M5 ;
        RECT  64.128 0 64.152 0.084 ;
    END
  END r_data[1]
  PIN r_data[200]
    DIRECTION INPUT ;
    USE SIGNAL ;
    PORT
      LAYER M5 ;
        RECT  83.232 0 83.256 0.084 ;
    END
  END r_data[200]
  PIN r_data[201]
    DIRECTION INPUT ;
    USE SIGNAL ;
    PORT
      LAYER M5 ;
        RECT  83.328 0 83.352 0.084 ;
    END
  END r_data[201]
  PIN r_data[202]
    DIRECTION INPUT ;
    USE SIGNAL ;
    PORT
      LAYER M5 ;
        RECT  83.424 0 83.448 0.084 ;
    END
  END r_data[202]
  PIN r_data[203]
    DIRECTION INPUT ;
    USE SIGNAL ;
    PORT
      LAYER M5 ;
        RECT  83.52 0 83.544 0.084 ;
    END
  END r_data[203]
  PIN r_data[204]
    DIRECTION INPUT ;
    USE SIGNAL ;
    PORT
      LAYER M5 ;
        RECT  83.616 0 83.64 0.084 ;
    END
  END r_data[204]
  PIN r_data[205]
    DIRECTION INPUT ;
    USE SIGNAL ;
    PORT
      LAYER M5 ;
        RECT  83.712 0 83.736 0.084 ;
    END
  END r_data[205]
  PIN r_data[206]
    DIRECTION INPUT ;
    USE SIGNAL ;
    PORT
      LAYER M5 ;
        RECT  83.808 0 83.832 0.084 ;
    END
  END r_data[206]
  PIN r_data[207]
    DIRECTION INPUT ;
    USE SIGNAL ;
    PORT
      LAYER M5 ;
        RECT  83.904 0 83.928 0.084 ;
    END
  END r_data[207]
  PIN r_data[208]
    DIRECTION INPUT ;
    USE SIGNAL ;
    PORT
      LAYER M5 ;
        RECT  84 0 84.024 0.084 ;
    END
  END r_data[208]
  PIN r_data[209]
    DIRECTION INPUT ;
    USE SIGNAL ;
    PORT
      LAYER M5 ;
        RECT  84.096 0 84.12 0.084 ;
    END
  END r_data[209]
  PIN r_data[20]
    DIRECTION INPUT ;
    USE SIGNAL ;
    PORT
      LAYER M5 ;
        RECT  65.952 0 65.976 0.084 ;
    END
  END r_data[20]
  PIN r_data[210]
    DIRECTION INPUT ;
    USE SIGNAL ;
    PORT
      LAYER M5 ;
        RECT  84.192 0 84.216 0.084 ;
    END
  END r_data[210]
  PIN r_data[211]
    DIRECTION INPUT ;
    USE SIGNAL ;
    PORT
      LAYER M5 ;
        RECT  84.288 0 84.312 0.084 ;
    END
  END r_data[211]
  PIN r_data[212]
    DIRECTION INPUT ;
    USE SIGNAL ;
    PORT
      LAYER M5 ;
        RECT  84.384 0 84.408 0.084 ;
    END
  END r_data[212]
  PIN r_data[213]
    DIRECTION INPUT ;
    USE SIGNAL ;
    PORT
      LAYER M5 ;
        RECT  84.48 0 84.504 0.084 ;
    END
  END r_data[213]
  PIN r_data[214]
    DIRECTION INPUT ;
    USE SIGNAL ;
    PORT
      LAYER M5 ;
        RECT  84.576 0 84.6 0.084 ;
    END
  END r_data[214]
  PIN r_data[215]
    DIRECTION INPUT ;
    USE SIGNAL ;
    PORT
      LAYER M5 ;
        RECT  84.672 0 84.696 0.084 ;
    END
  END r_data[215]
  PIN r_data[216]
    DIRECTION INPUT ;
    USE SIGNAL ;
    PORT
      LAYER M5 ;
        RECT  84.768 0 84.792 0.084 ;
    END
  END r_data[216]
  PIN r_data[217]
    DIRECTION INPUT ;
    USE SIGNAL ;
    PORT
      LAYER M5 ;
        RECT  84.864 0 84.888 0.084 ;
    END
  END r_data[217]
  PIN r_data[218]
    DIRECTION INPUT ;
    USE SIGNAL ;
    PORT
      LAYER M5 ;
        RECT  84.96 0 84.984 0.084 ;
    END
  END r_data[218]
  PIN r_data[219]
    DIRECTION INPUT ;
    USE SIGNAL ;
    PORT
      LAYER M5 ;
        RECT  85.056 0 85.08 0.084 ;
    END
  END r_data[219]
  PIN r_data[21]
    DIRECTION INPUT ;
    USE SIGNAL ;
    PORT
      LAYER M5 ;
        RECT  66.048 0 66.072 0.084 ;
    END
  END r_data[21]
  PIN r_data[220]
    DIRECTION INPUT ;
    USE SIGNAL ;
    PORT
      LAYER M5 ;
        RECT  85.152 0 85.176 0.084 ;
    END
  END r_data[220]
  PIN r_data[221]
    DIRECTION INPUT ;
    USE SIGNAL ;
    PORT
      LAYER M5 ;
        RECT  85.248 0 85.272 0.084 ;
    END
  END r_data[221]
  PIN r_data[222]
    DIRECTION INPUT ;
    USE SIGNAL ;
    PORT
      LAYER M5 ;
        RECT  85.344 0 85.368 0.084 ;
    END
  END r_data[222]
  PIN r_data[223]
    DIRECTION INPUT ;
    USE SIGNAL ;
    PORT
      LAYER M5 ;
        RECT  85.44 0 85.464 0.084 ;
    END
  END r_data[223]
  PIN r_data[224]
    DIRECTION INPUT ;
    USE SIGNAL ;
    PORT
      LAYER M5 ;
        RECT  85.536 0 85.56 0.084 ;
    END
  END r_data[224]
  PIN r_data[225]
    DIRECTION INPUT ;
    USE SIGNAL ;
    PORT
      LAYER M5 ;
        RECT  85.632 0 85.656 0.084 ;
    END
  END r_data[225]
  PIN r_data[226]
    DIRECTION INPUT ;
    USE SIGNAL ;
    PORT
      LAYER M5 ;
        RECT  85.728 0 85.752 0.084 ;
    END
  END r_data[226]
  PIN r_data[227]
    DIRECTION INPUT ;
    USE SIGNAL ;
    PORT
      LAYER M5 ;
        RECT  85.824 0 85.848 0.084 ;
    END
  END r_data[227]
  PIN r_data[228]
    DIRECTION INPUT ;
    USE SIGNAL ;
    PORT
      LAYER M5 ;
        RECT  85.92 0 85.944 0.084 ;
    END
  END r_data[228]
  PIN r_data[229]
    DIRECTION INPUT ;
    USE SIGNAL ;
    PORT
      LAYER M5 ;
        RECT  86.016 0 86.04 0.084 ;
    END
  END r_data[229]
  PIN r_data[22]
    DIRECTION INPUT ;
    USE SIGNAL ;
    PORT
      LAYER M5 ;
        RECT  66.144 0 66.168 0.084 ;
    END
  END r_data[22]
  PIN r_data[230]
    DIRECTION INPUT ;
    USE SIGNAL ;
    PORT
      LAYER M5 ;
        RECT  86.112 0 86.136 0.084 ;
    END
  END r_data[230]
  PIN r_data[231]
    DIRECTION INPUT ;
    USE SIGNAL ;
    PORT
      LAYER M5 ;
        RECT  86.208 0 86.232 0.084 ;
    END
  END r_data[231]
  PIN r_data[232]
    DIRECTION INPUT ;
    USE SIGNAL ;
    PORT
      LAYER M5 ;
        RECT  86.304 0 86.328 0.084 ;
    END
  END r_data[232]
  PIN r_data[233]
    DIRECTION INPUT ;
    USE SIGNAL ;
    PORT
      LAYER M5 ;
        RECT  86.4 0 86.424 0.084 ;
    END
  END r_data[233]
  PIN r_data[234]
    DIRECTION INPUT ;
    USE SIGNAL ;
    PORT
      LAYER M5 ;
        RECT  86.496 0 86.52 0.084 ;
    END
  END r_data[234]
  PIN r_data[235]
    DIRECTION INPUT ;
    USE SIGNAL ;
    PORT
      LAYER M5 ;
        RECT  86.592 0 86.616 0.084 ;
    END
  END r_data[235]
  PIN r_data[236]
    DIRECTION INPUT ;
    USE SIGNAL ;
    PORT
      LAYER M5 ;
        RECT  86.688 0 86.712 0.084 ;
    END
  END r_data[236]
  PIN r_data[237]
    DIRECTION INPUT ;
    USE SIGNAL ;
    PORT
      LAYER M5 ;
        RECT  86.784 0 86.808 0.084 ;
    END
  END r_data[237]
  PIN r_data[238]
    DIRECTION INPUT ;
    USE SIGNAL ;
    PORT
      LAYER M5 ;
        RECT  86.88 0 86.904 0.084 ;
    END
  END r_data[238]
  PIN r_data[239]
    DIRECTION INPUT ;
    USE SIGNAL ;
    PORT
      LAYER M5 ;
        RECT  86.976 0 87 0.084 ;
    END
  END r_data[239]
  PIN r_data[23]
    DIRECTION INPUT ;
    USE SIGNAL ;
    PORT
      LAYER M5 ;
        RECT  66.24 0 66.264 0.084 ;
    END
  END r_data[23]
  PIN r_data[240]
    DIRECTION INPUT ;
    USE SIGNAL ;
    PORT
      LAYER M5 ;
        RECT  87.072 0 87.096 0.084 ;
    END
  END r_data[240]
  PIN r_data[241]
    DIRECTION INPUT ;
    USE SIGNAL ;
    PORT
      LAYER M5 ;
        RECT  87.168 0 87.192 0.084 ;
    END
  END r_data[241]
  PIN r_data[242]
    DIRECTION INPUT ;
    USE SIGNAL ;
    PORT
      LAYER M5 ;
        RECT  87.264 0 87.288 0.084 ;
    END
  END r_data[242]
  PIN r_data[243]
    DIRECTION INPUT ;
    USE SIGNAL ;
    PORT
      LAYER M5 ;
        RECT  87.36 0 87.384 0.084 ;
    END
  END r_data[243]
  PIN r_data[244]
    DIRECTION INPUT ;
    USE SIGNAL ;
    PORT
      LAYER M5 ;
        RECT  87.456 0 87.48 0.084 ;
    END
  END r_data[244]
  PIN r_data[245]
    DIRECTION INPUT ;
    USE SIGNAL ;
    PORT
      LAYER M5 ;
        RECT  87.552 0 87.576 0.084 ;
    END
  END r_data[245]
  PIN r_data[246]
    DIRECTION INPUT ;
    USE SIGNAL ;
    PORT
      LAYER M5 ;
        RECT  87.648 0 87.672 0.084 ;
    END
  END r_data[246]
  PIN r_data[247]
    DIRECTION INPUT ;
    USE SIGNAL ;
    PORT
      LAYER M5 ;
        RECT  87.744 0 87.768 0.084 ;
    END
  END r_data[247]
  PIN r_data[248]
    DIRECTION INPUT ;
    USE SIGNAL ;
    PORT
      LAYER M5 ;
        RECT  87.84 0 87.864 0.084 ;
    END
  END r_data[248]
  PIN r_data[249]
    DIRECTION INPUT ;
    USE SIGNAL ;
    PORT
      LAYER M5 ;
        RECT  87.936 0 87.96 0.084 ;
    END
  END r_data[249]
  PIN r_data[24]
    DIRECTION INPUT ;
    USE SIGNAL ;
    PORT
      LAYER M5 ;
        RECT  66.336 0 66.36 0.084 ;
    END
  END r_data[24]
  PIN r_data[250]
    DIRECTION INPUT ;
    USE SIGNAL ;
    PORT
      LAYER M5 ;
        RECT  88.032 0 88.056 0.084 ;
    END
  END r_data[250]
  PIN r_data[251]
    DIRECTION INPUT ;
    USE SIGNAL ;
    PORT
      LAYER M5 ;
        RECT  88.128 0 88.152 0.084 ;
    END
  END r_data[251]
  PIN r_data[252]
    DIRECTION INPUT ;
    USE SIGNAL ;
    PORT
      LAYER M5 ;
        RECT  88.224 0 88.248 0.084 ;
    END
  END r_data[252]
  PIN r_data[253]
    DIRECTION INPUT ;
    USE SIGNAL ;
    PORT
      LAYER M5 ;
        RECT  88.32 0 88.344 0.084 ;
    END
  END r_data[253]
  PIN r_data[254]
    DIRECTION INPUT ;
    USE SIGNAL ;
    PORT
      LAYER M5 ;
        RECT  88.416 0 88.44 0.084 ;
    END
  END r_data[254]
  PIN r_data[255]
    DIRECTION INPUT ;
    USE SIGNAL ;
    PORT
      LAYER M5 ;
        RECT  88.512 0 88.536 0.084 ;
    END
  END r_data[255]
  PIN r_data[25]
    DIRECTION INPUT ;
    USE SIGNAL ;
    PORT
      LAYER M5 ;
        RECT  66.432 0 66.456 0.084 ;
    END
  END r_data[25]
  PIN r_data[26]
    DIRECTION INPUT ;
    USE SIGNAL ;
    PORT
      LAYER M5 ;
        RECT  66.528 0 66.552 0.084 ;
    END
  END r_data[26]
  PIN r_data[27]
    DIRECTION INPUT ;
    USE SIGNAL ;
    PORT
      LAYER M5 ;
        RECT  66.624 0 66.648 0.084 ;
    END
  END r_data[27]
  PIN r_data[28]
    DIRECTION INPUT ;
    USE SIGNAL ;
    PORT
      LAYER M5 ;
        RECT  66.72 0 66.744 0.084 ;
    END
  END r_data[28]
  PIN r_data[29]
    DIRECTION INPUT ;
    USE SIGNAL ;
    PORT
      LAYER M5 ;
        RECT  66.816 0 66.84 0.084 ;
    END
  END r_data[29]
  PIN r_data[2]
    DIRECTION INPUT ;
    USE SIGNAL ;
    PORT
      LAYER M5 ;
        RECT  64.224 0 64.248 0.084 ;
    END
  END r_data[2]
  PIN r_data[30]
    DIRECTION INPUT ;
    USE SIGNAL ;
    PORT
      LAYER M5 ;
        RECT  66.912 0 66.936 0.084 ;
    END
  END r_data[30]
  PIN r_data[31]
    DIRECTION INPUT ;
    USE SIGNAL ;
    PORT
      LAYER M5 ;
        RECT  67.008 0 67.032 0.084 ;
    END
  END r_data[31]
  PIN r_data[32]
    DIRECTION INPUT ;
    USE SIGNAL ;
    PORT
      LAYER M5 ;
        RECT  67.104 0 67.128 0.084 ;
    END
  END r_data[32]
  PIN r_data[33]
    DIRECTION INPUT ;
    USE SIGNAL ;
    PORT
      LAYER M5 ;
        RECT  67.2 0 67.224 0.084 ;
    END
  END r_data[33]
  PIN r_data[34]
    DIRECTION INPUT ;
    USE SIGNAL ;
    PORT
      LAYER M5 ;
        RECT  67.296 0 67.32 0.084 ;
    END
  END r_data[34]
  PIN r_data[35]
    DIRECTION INPUT ;
    USE SIGNAL ;
    PORT
      LAYER M5 ;
        RECT  67.392 0 67.416 0.084 ;
    END
  END r_data[35]
  PIN r_data[36]
    DIRECTION INPUT ;
    USE SIGNAL ;
    PORT
      LAYER M5 ;
        RECT  67.488 0 67.512 0.084 ;
    END
  END r_data[36]
  PIN r_data[37]
    DIRECTION INPUT ;
    USE SIGNAL ;
    PORT
      LAYER M5 ;
        RECT  67.584 0 67.608 0.084 ;
    END
  END r_data[37]
  PIN r_data[38]
    DIRECTION INPUT ;
    USE SIGNAL ;
    PORT
      LAYER M5 ;
        RECT  67.68 0 67.704 0.084 ;
    END
  END r_data[38]
  PIN r_data[39]
    DIRECTION INPUT ;
    USE SIGNAL ;
    PORT
      LAYER M5 ;
        RECT  67.776 0 67.8 0.084 ;
    END
  END r_data[39]
  PIN r_data[3]
    DIRECTION INPUT ;
    USE SIGNAL ;
    PORT
      LAYER M5 ;
        RECT  64.32 0 64.344 0.084 ;
    END
  END r_data[3]
  PIN r_data[40]
    DIRECTION INPUT ;
    USE SIGNAL ;
    PORT
      LAYER M5 ;
        RECT  67.872 0 67.896 0.084 ;
    END
  END r_data[40]
  PIN r_data[41]
    DIRECTION INPUT ;
    USE SIGNAL ;
    PORT
      LAYER M5 ;
        RECT  67.968 0 67.992 0.084 ;
    END
  END r_data[41]
  PIN r_data[42]
    DIRECTION INPUT ;
    USE SIGNAL ;
    PORT
      LAYER M5 ;
        RECT  68.064 0 68.088 0.084 ;
    END
  END r_data[42]
  PIN r_data[43]
    DIRECTION INPUT ;
    USE SIGNAL ;
    PORT
      LAYER M5 ;
        RECT  68.16 0 68.184 0.084 ;
    END
  END r_data[43]
  PIN r_data[44]
    DIRECTION INPUT ;
    USE SIGNAL ;
    PORT
      LAYER M5 ;
        RECT  68.256 0 68.28 0.084 ;
    END
  END r_data[44]
  PIN r_data[45]
    DIRECTION INPUT ;
    USE SIGNAL ;
    PORT
      LAYER M5 ;
        RECT  68.352 0 68.376 0.084 ;
    END
  END r_data[45]
  PIN r_data[46]
    DIRECTION INPUT ;
    USE SIGNAL ;
    PORT
      LAYER M5 ;
        RECT  68.448 0 68.472 0.084 ;
    END
  END r_data[46]
  PIN r_data[47]
    DIRECTION INPUT ;
    USE SIGNAL ;
    PORT
      LAYER M5 ;
        RECT  68.544 0 68.568 0.084 ;
    END
  END r_data[47]
  PIN r_data[48]
    DIRECTION INPUT ;
    USE SIGNAL ;
    PORT
      LAYER M5 ;
        RECT  68.64 0 68.664 0.084 ;
    END
  END r_data[48]
  PIN r_data[49]
    DIRECTION INPUT ;
    USE SIGNAL ;
    PORT
      LAYER M5 ;
        RECT  68.736 0 68.76 0.084 ;
    END
  END r_data[49]
  PIN r_data[4]
    DIRECTION INPUT ;
    USE SIGNAL ;
    PORT
      LAYER M5 ;
        RECT  64.416 0 64.44 0.084 ;
    END
  END r_data[4]
  PIN r_data[50]
    DIRECTION INPUT ;
    USE SIGNAL ;
    PORT
      LAYER M5 ;
        RECT  68.832 0 68.856 0.084 ;
    END
  END r_data[50]
  PIN r_data[51]
    DIRECTION INPUT ;
    USE SIGNAL ;
    PORT
      LAYER M5 ;
        RECT  68.928 0 68.952 0.084 ;
    END
  END r_data[51]
  PIN r_data[52]
    DIRECTION INPUT ;
    USE SIGNAL ;
    PORT
      LAYER M5 ;
        RECT  69.024 0 69.048 0.084 ;
    END
  END r_data[52]
  PIN r_data[53]
    DIRECTION INPUT ;
    USE SIGNAL ;
    PORT
      LAYER M5 ;
        RECT  69.12 0 69.144 0.084 ;
    END
  END r_data[53]
  PIN r_data[54]
    DIRECTION INPUT ;
    USE SIGNAL ;
    PORT
      LAYER M5 ;
        RECT  69.216 0 69.24 0.084 ;
    END
  END r_data[54]
  PIN r_data[55]
    DIRECTION INPUT ;
    USE SIGNAL ;
    PORT
      LAYER M5 ;
        RECT  69.312 0 69.336 0.084 ;
    END
  END r_data[55]
  PIN r_data[56]
    DIRECTION INPUT ;
    USE SIGNAL ;
    PORT
      LAYER M5 ;
        RECT  69.408 0 69.432 0.084 ;
    END
  END r_data[56]
  PIN r_data[57]
    DIRECTION INPUT ;
    USE SIGNAL ;
    PORT
      LAYER M5 ;
        RECT  69.504 0 69.528 0.084 ;
    END
  END r_data[57]
  PIN r_data[58]
    DIRECTION INPUT ;
    USE SIGNAL ;
    PORT
      LAYER M5 ;
        RECT  69.6 0 69.624 0.084 ;
    END
  END r_data[58]
  PIN r_data[59]
    DIRECTION INPUT ;
    USE SIGNAL ;
    PORT
      LAYER M5 ;
        RECT  69.696 0 69.72 0.084 ;
    END
  END r_data[59]
  PIN r_data[5]
    DIRECTION INPUT ;
    USE SIGNAL ;
    PORT
      LAYER M5 ;
        RECT  64.512 0 64.536 0.084 ;
    END
  END r_data[5]
  PIN r_data[60]
    DIRECTION INPUT ;
    USE SIGNAL ;
    PORT
      LAYER M5 ;
        RECT  69.792 0 69.816 0.084 ;
    END
  END r_data[60]
  PIN r_data[61]
    DIRECTION INPUT ;
    USE SIGNAL ;
    PORT
      LAYER M5 ;
        RECT  69.888 0 69.912 0.084 ;
    END
  END r_data[61]
  PIN r_data[62]
    DIRECTION INPUT ;
    USE SIGNAL ;
    PORT
      LAYER M5 ;
        RECT  69.984 0 70.008 0.084 ;
    END
  END r_data[62]
  PIN r_data[63]
    DIRECTION INPUT ;
    USE SIGNAL ;
    PORT
      LAYER M5 ;
        RECT  70.08 0 70.104 0.084 ;
    END
  END r_data[63]
  PIN r_data[64]
    DIRECTION INPUT ;
    USE SIGNAL ;
    PORT
      LAYER M5 ;
        RECT  70.176 0 70.2 0.084 ;
    END
  END r_data[64]
  PIN r_data[65]
    DIRECTION INPUT ;
    USE SIGNAL ;
    PORT
      LAYER M5 ;
        RECT  70.272 0 70.296 0.084 ;
    END
  END r_data[65]
  PIN r_data[66]
    DIRECTION INPUT ;
    USE SIGNAL ;
    PORT
      LAYER M5 ;
        RECT  70.368 0 70.392 0.084 ;
    END
  END r_data[66]
  PIN r_data[67]
    DIRECTION INPUT ;
    USE SIGNAL ;
    PORT
      LAYER M5 ;
        RECT  70.464 0 70.488 0.084 ;
    END
  END r_data[67]
  PIN r_data[68]
    DIRECTION INPUT ;
    USE SIGNAL ;
    PORT
      LAYER M5 ;
        RECT  70.56 0 70.584 0.084 ;
    END
  END r_data[68]
  PIN r_data[69]
    DIRECTION INPUT ;
    USE SIGNAL ;
    PORT
      LAYER M5 ;
        RECT  70.656 0 70.68 0.084 ;
    END
  END r_data[69]
  PIN r_data[6]
    DIRECTION INPUT ;
    USE SIGNAL ;
    PORT
      LAYER M5 ;
        RECT  64.608 0 64.632 0.084 ;
    END
  END r_data[6]
  PIN r_data[70]
    DIRECTION INPUT ;
    USE SIGNAL ;
    PORT
      LAYER M5 ;
        RECT  70.752 0 70.776 0.084 ;
    END
  END r_data[70]
  PIN r_data[71]
    DIRECTION INPUT ;
    USE SIGNAL ;
    PORT
      LAYER M5 ;
        RECT  70.848 0 70.872 0.084 ;
    END
  END r_data[71]
  PIN r_data[72]
    DIRECTION INPUT ;
    USE SIGNAL ;
    PORT
      LAYER M5 ;
        RECT  70.944 0 70.968 0.084 ;
    END
  END r_data[72]
  PIN r_data[73]
    DIRECTION INPUT ;
    USE SIGNAL ;
    PORT
      LAYER M5 ;
        RECT  71.04 0 71.064 0.084 ;
    END
  END r_data[73]
  PIN r_data[74]
    DIRECTION INPUT ;
    USE SIGNAL ;
    PORT
      LAYER M5 ;
        RECT  71.136 0 71.16 0.084 ;
    END
  END r_data[74]
  PIN r_data[75]
    DIRECTION INPUT ;
    USE SIGNAL ;
    PORT
      LAYER M5 ;
        RECT  71.232 0 71.256 0.084 ;
    END
  END r_data[75]
  PIN r_data[76]
    DIRECTION INPUT ;
    USE SIGNAL ;
    PORT
      LAYER M5 ;
        RECT  71.328 0 71.352 0.084 ;
    END
  END r_data[76]
  PIN r_data[77]
    DIRECTION INPUT ;
    USE SIGNAL ;
    PORT
      LAYER M5 ;
        RECT  71.424 0 71.448 0.084 ;
    END
  END r_data[77]
  PIN r_data[78]
    DIRECTION INPUT ;
    USE SIGNAL ;
    PORT
      LAYER M5 ;
        RECT  71.52 0 71.544 0.084 ;
    END
  END r_data[78]
  PIN r_data[79]
    DIRECTION INPUT ;
    USE SIGNAL ;
    PORT
      LAYER M5 ;
        RECT  71.616 0 71.64 0.084 ;
    END
  END r_data[79]
  PIN r_data[7]
    DIRECTION INPUT ;
    USE SIGNAL ;
    PORT
      LAYER M5 ;
        RECT  64.704 0 64.728 0.084 ;
    END
  END r_data[7]
  PIN r_data[80]
    DIRECTION INPUT ;
    USE SIGNAL ;
    PORT
      LAYER M5 ;
        RECT  71.712 0 71.736 0.084 ;
    END
  END r_data[80]
  PIN r_data[81]
    DIRECTION INPUT ;
    USE SIGNAL ;
    PORT
      LAYER M5 ;
        RECT  71.808 0 71.832 0.084 ;
    END
  END r_data[81]
  PIN r_data[82]
    DIRECTION INPUT ;
    USE SIGNAL ;
    PORT
      LAYER M5 ;
        RECT  71.904 0 71.928 0.084 ;
    END
  END r_data[82]
  PIN r_data[83]
    DIRECTION INPUT ;
    USE SIGNAL ;
    PORT
      LAYER M5 ;
        RECT  72 0 72.024 0.084 ;
    END
  END r_data[83]
  PIN r_data[84]
    DIRECTION INPUT ;
    USE SIGNAL ;
    PORT
      LAYER M5 ;
        RECT  72.096 0 72.12 0.084 ;
    END
  END r_data[84]
  PIN r_data[85]
    DIRECTION INPUT ;
    USE SIGNAL ;
    PORT
      LAYER M5 ;
        RECT  72.192 0 72.216 0.084 ;
    END
  END r_data[85]
  PIN r_data[86]
    DIRECTION INPUT ;
    USE SIGNAL ;
    PORT
      LAYER M5 ;
        RECT  72.288 0 72.312 0.084 ;
    END
  END r_data[86]
  PIN r_data[87]
    DIRECTION INPUT ;
    USE SIGNAL ;
    PORT
      LAYER M5 ;
        RECT  72.384 0 72.408 0.084 ;
    END
  END r_data[87]
  PIN r_data[88]
    DIRECTION INPUT ;
    USE SIGNAL ;
    PORT
      LAYER M5 ;
        RECT  72.48 0 72.504 0.084 ;
    END
  END r_data[88]
  PIN r_data[89]
    DIRECTION INPUT ;
    USE SIGNAL ;
    PORT
      LAYER M5 ;
        RECT  72.576 0 72.6 0.084 ;
    END
  END r_data[89]
  PIN r_data[8]
    DIRECTION INPUT ;
    USE SIGNAL ;
    PORT
      LAYER M5 ;
        RECT  64.8 0 64.824 0.084 ;
    END
  END r_data[8]
  PIN r_data[90]
    DIRECTION INPUT ;
    USE SIGNAL ;
    PORT
      LAYER M5 ;
        RECT  72.672 0 72.696 0.084 ;
    END
  END r_data[90]
  PIN r_data[91]
    DIRECTION INPUT ;
    USE SIGNAL ;
    PORT
      LAYER M5 ;
        RECT  72.768 0 72.792 0.084 ;
    END
  END r_data[91]
  PIN r_data[92]
    DIRECTION INPUT ;
    USE SIGNAL ;
    PORT
      LAYER M5 ;
        RECT  72.864 0 72.888 0.084 ;
    END
  END r_data[92]
  PIN r_data[93]
    DIRECTION INPUT ;
    USE SIGNAL ;
    PORT
      LAYER M5 ;
        RECT  72.96 0 72.984 0.084 ;
    END
  END r_data[93]
  PIN r_data[94]
    DIRECTION INPUT ;
    USE SIGNAL ;
    PORT
      LAYER M5 ;
        RECT  73.056 0 73.08 0.084 ;
    END
  END r_data[94]
  PIN r_data[95]
    DIRECTION INPUT ;
    USE SIGNAL ;
    PORT
      LAYER M5 ;
        RECT  73.152 0 73.176 0.084 ;
    END
  END r_data[95]
  PIN r_data[96]
    DIRECTION INPUT ;
    USE SIGNAL ;
    PORT
      LAYER M5 ;
        RECT  73.248 0 73.272 0.084 ;
    END
  END r_data[96]
  PIN r_data[97]
    DIRECTION INPUT ;
    USE SIGNAL ;
    PORT
      LAYER M5 ;
        RECT  73.344 0 73.368 0.084 ;
    END
  END r_data[97]
  PIN r_data[98]
    DIRECTION INPUT ;
    USE SIGNAL ;
    PORT
      LAYER M5 ;
        RECT  73.44 0 73.464 0.084 ;
    END
  END r_data[98]
  PIN r_data[99]
    DIRECTION INPUT ;
    USE SIGNAL ;
    PORT
      LAYER M5 ;
        RECT  73.536 0 73.56 0.084 ;
    END
  END r_data[99]
  PIN r_data[9]
    DIRECTION INPUT ;
    USE SIGNAL ;
    PORT
      LAYER M5 ;
        RECT  64.896 0 64.92 0.084 ;
    END
  END r_data[9]
  PIN r_rdy
    DIRECTION OUTPUT ;
    USE SIGNAL ;
    PORT
      LAYER M5 ;
        RECT  88.608 0 88.632 0.084 ;
    END
  END r_rdy
  PIN r_tag[0]
    DIRECTION INPUT ;
    USE SIGNAL ;
    PORT
      LAYER M5 ;
        RECT  88.704 0 88.728 0.084 ;
    END
  END r_tag[0]
  PIN r_tag[10]
    DIRECTION INPUT ;
    USE SIGNAL ;
    PORT
      LAYER M5 ;
        RECT  89.664 0 89.688 0.084 ;
    END
  END r_tag[10]
  PIN r_tag[11]
    DIRECTION INPUT ;
    USE SIGNAL ;
    PORT
      LAYER M5 ;
        RECT  89.76 0 89.784 0.084 ;
    END
  END r_tag[11]
  PIN r_tag[12]
    DIRECTION INPUT ;
    USE SIGNAL ;
    PORT
      LAYER M5 ;
        RECT  89.856 0 89.88 0.084 ;
    END
  END r_tag[12]
  PIN r_tag[13]
    DIRECTION INPUT ;
    USE SIGNAL ;
    PORT
      LAYER M5 ;
        RECT  89.952 0 89.976 0.084 ;
    END
  END r_tag[13]
  PIN r_tag[14]
    DIRECTION INPUT ;
    USE SIGNAL ;
    PORT
      LAYER M5 ;
        RECT  90.048 0 90.072 0.084 ;
    END
  END r_tag[14]
  PIN r_tag[15]
    DIRECTION INPUT ;
    USE SIGNAL ;
    PORT
      LAYER M5 ;
        RECT  90.144 0 90.168 0.084 ;
    END
  END r_tag[15]
  PIN r_tag[16]
    DIRECTION INPUT ;
    USE SIGNAL ;
    PORT
      LAYER M5 ;
        RECT  90.24 0 90.264 0.084 ;
    END
  END r_tag[16]
  PIN r_tag[1]
    DIRECTION INPUT ;
    USE SIGNAL ;
    PORT
      LAYER M5 ;
        RECT  88.8 0 88.824 0.084 ;
    END
  END r_tag[1]
  PIN r_tag[2]
    DIRECTION INPUT ;
    USE SIGNAL ;
    PORT
      LAYER M5 ;
        RECT  88.896 0 88.92 0.084 ;
    END
  END r_tag[2]
  PIN r_tag[3]
    DIRECTION INPUT ;
    USE SIGNAL ;
    PORT
      LAYER M5 ;
        RECT  88.992 0 89.016 0.084 ;
    END
  END r_tag[3]
  PIN r_tag[4]
    DIRECTION INPUT ;
    USE SIGNAL ;
    PORT
      LAYER M5 ;
        RECT  89.088 0 89.112 0.084 ;
    END
  END r_tag[4]
  PIN r_tag[5]
    DIRECTION INPUT ;
    USE SIGNAL ;
    PORT
      LAYER M5 ;
        RECT  89.184 0 89.208 0.084 ;
    END
  END r_tag[5]
  PIN r_tag[6]
    DIRECTION INPUT ;
    USE SIGNAL ;
    PORT
      LAYER M5 ;
        RECT  89.28 0 89.304 0.084 ;
    END
  END r_tag[6]
  PIN r_tag[7]
    DIRECTION INPUT ;
    USE SIGNAL ;
    PORT
      LAYER M5 ;
        RECT  89.376 0 89.4 0.084 ;
    END
  END r_tag[7]
  PIN r_tag[8]
    DIRECTION INPUT ;
    USE SIGNAL ;
    PORT
      LAYER M5 ;
        RECT  89.472 0 89.496 0.084 ;
    END
  END r_tag[8]
  PIN r_tag[9]
    DIRECTION INPUT ;
    USE SIGNAL ;
    PORT
      LAYER M5 ;
        RECT  89.568 0 89.592 0.084 ;
    END
  END r_tag[9]
  PIN r_v
    DIRECTION INPUT ;
    USE SIGNAL ;
    PORT
      LAYER M5 ;
        RECT  90.336 0 90.36 0.084 ;
    END
  END r_v
  PIN rst_n
    DIRECTION INPUT ;
    USE SIGNAL ;
    PORT
      LAYER M5 ;
        RECT  223.584 63.916 223.608 64 ;
    END
  END rst_n
  PIN VDD
    DIRECTION INOUT ;
    USE POWER ;
    PORT
      LAYER M6 ;
        RECT  1.08 61.233 264.492 61.521 ;
        RECT  1.08 55.833 264.492 56.121 ;
        RECT  1.08 50.433 264.492 50.721 ;
        RECT  1.08 45.033 264.492 45.321 ;
        RECT  1.08 39.633 264.492 39.921 ;
        RECT  1.08 34.233 264.492 34.521 ;
        RECT  1.08 28.833 264.492 29.121 ;
        RECT  1.08 23.433 264.492 23.721 ;
        RECT  1.08 18.033 264.492 18.321 ;
        RECT  1.08 12.633 264.492 12.921 ;
        RECT  1.08 7.233 264.492 7.521 ;
        RECT  1.08 1.833 264.492 2.121 ;
    END
  END VDD
  PIN VSS
    DIRECTION INOUT ;
    USE GROUND ;
    PORT
      LAYER M6 ;
        RECT  1.08 60.849 264.492 61.137 ;
        RECT  1.08 55.449 264.492 55.737 ;
        RECT  1.08 50.049 264.492 50.337 ;
        RECT  1.08 44.649 264.492 44.937 ;
        RECT  1.08 39.249 264.492 39.537 ;
        RECT  1.08 33.849 264.492 34.137 ;
        RECT  1.08 28.449 264.492 28.737 ;
        RECT  1.08 23.049 264.492 23.337 ;
        RECT  1.08 17.649 264.492 17.937 ;
        RECT  1.08 12.249 264.492 12.537 ;
        RECT  1.08 6.849 264.492 7.137 ;
        RECT  1.08 1.449 264.492 1.737 ;
    END
  END VSS
  OBS
    LAYER RVTN ;
     RECT  1.08 0 264.492 64 ;
    LAYER RVTP ;
     RECT  1.08 0 264.492 64 ;
    LAYER M1 ;
     RECT  1.08 0 264.492 64 ;
    LAYER M2 ;
     RECT  1.08 0 264.492 64 ;
    LAYER M3 ;
     RECT  1.08 0 264.492 64 ;
    LAYER M4 ;
     RECT  1.08 0 264.492 64 ;
    LAYER M5 ;
     RECT  1.08 0 264.492 64 ;
    LAYER M6 ;
     RECT  1.08 0 264.492 64 ;
    LAYER M7 ;
     RECT  1.08 0 264.492 64 ;
  END
END ot_chip_v41x_karb_pslice
END LIBRARY
